VERSION 5.8 ;
BUSBITCHARS "[]" ;
DIVIDERCHAR "/" ;
UNITS
    DATABASE MICRONS 1000 ;
END UNITS

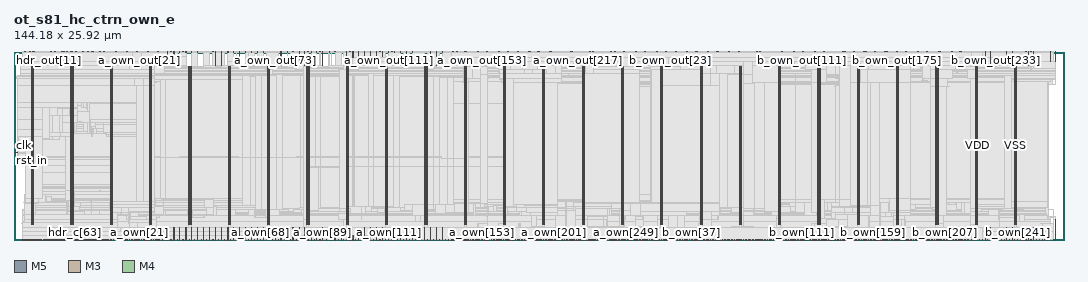
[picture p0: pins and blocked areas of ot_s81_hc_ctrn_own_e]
MACRO ot_s81_hc_ctrn_own_e
  FOREIGN ot_s81_hc_ctrn_own_e 0 0 ;
  CLASS BLOCK ;
  SIZE 144.18 BY 25.92 ;
  PIN a_own[0]
    DIRECTION INPUT ;
    USE SIGNAL ;
    PORT
      LAYER M5 ;
        RECT  13.008 0 13.032 0.084 ;
    END
  END a_own[0]
  PIN a_own[100]
    DIRECTION INPUT ;
    USE SIGNAL ;
    PORT
      LAYER M5 ;
        RECT  46.896 0 46.92 0.084 ;
    END
  END a_own[100]
  PIN a_own[101]
    DIRECTION INPUT ;
    USE SIGNAL ;
    PORT
      LAYER M3 ;
        RECT  47.304 0 47.322 0.038 ;
    END
    PORT
      LAYER M3 ;
        RECT  47.304 0.012 47.322 0.571 ;
    END
  END a_own[101]
  PIN a_own[102]
    DIRECTION INPUT ;
    USE SIGNAL ;
    PORT
      LAYER M5 ;
        RECT  47.76 0 47.784 0.084 ;
    END
  END a_own[102]
  PIN a_own[103]
    DIRECTION INPUT ;
    USE SIGNAL ;
    PORT
      LAYER M3 ;
        RECT  48.168 0 48.186 0.038 ;
    END
    PORT
      LAYER M3 ;
        RECT  48.168 0.012 48.186 1.723 ;
    END
  END a_own[103]
  PIN a_own[104]
    DIRECTION INPUT ;
    USE SIGNAL ;
    PORT
      LAYER M5 ;
        RECT  48.528 0 48.552 0.084 ;
    END
  END a_own[104]
  PIN a_own[105]
    DIRECTION INPUT ;
    USE SIGNAL ;
    PORT
      LAYER M3 ;
        RECT  48.96 0 48.978 0.038 ;
    END
    PORT
      LAYER M3 ;
        RECT  48.96 0.012 48.978 1.723 ;
    END
  END a_own[105]
  PIN a_own[106]
    DIRECTION INPUT ;
    USE SIGNAL ;
    PORT
      LAYER M5 ;
        RECT  49.392 0 49.416 0.084 ;
    END
  END a_own[106]
  PIN a_own[107]
    DIRECTION INPUT ;
    USE SIGNAL ;
    PORT
      LAYER M3 ;
        RECT  49.824 0 49.842 0.038 ;
    END
    PORT
      LAYER M3 ;
        RECT  49.824 0.012 49.842 1.723 ;
    END
  END a_own[107]
  PIN a_own[108]
    DIRECTION INPUT ;
    USE SIGNAL ;
    PORT
      LAYER M5 ;
        RECT  50.256 0 50.28 0.084 ;
    END
  END a_own[108]
  PIN a_own[109]
    DIRECTION INPUT ;
    USE SIGNAL ;
    PORT
      LAYER M3 ;
        RECT  50.58 0 50.598 0.038 ;
    END
    PORT
      LAYER M3 ;
        RECT  50.58 0.012 50.598 1.723 ;
    END
  END a_own[109]
  PIN a_own[10]
    DIRECTION INPUT ;
    USE SIGNAL ;
    PORT
      LAYER M5 ;
        RECT  15.024 0 15.048 0.084 ;
    END
  END a_own[10]
  PIN a_own[110]
    DIRECTION INPUT ;
    USE SIGNAL ;
    PORT
      LAYER M5 ;
        RECT  51.024 0 51.048 0.084 ;
    END
  END a_own[110]
  PIN a_own[111]
    DIRECTION INPUT ;
    USE SIGNAL ;
    PORT
      LAYER M3 ;
        RECT  51.444 0 51.462 0.038 ;
    END
    PORT
      LAYER M3 ;
        RECT  51.444 0.012 51.462 0.091 ;
    END
  END a_own[111]
  PIN a_own[112]
    DIRECTION INPUT ;
    USE SIGNAL ;
    PORT
      LAYER M5 ;
        RECT  51.888 0 51.912 0.084 ;
    END
  END a_own[112]
  PIN a_own[113]
    DIRECTION INPUT ;
    USE SIGNAL ;
    PORT
      LAYER M3 ;
        RECT  52.2 0 52.218 0.038 ;
    END
    PORT
      LAYER M3 ;
        RECT  52.2 0.012 52.218 0.091 ;
    END
  END a_own[113]
  PIN a_own[114]
    DIRECTION INPUT ;
    USE SIGNAL ;
    PORT
      LAYER M5 ;
        RECT  52.656 0 52.68 0.084 ;
    END
  END a_own[114]
  PIN a_own[115]
    DIRECTION INPUT ;
    USE SIGNAL ;
    PORT
      LAYER M3 ;
        RECT  53.064 0 53.082 0.038 ;
    END
    PORT
      LAYER M3 ;
        RECT  53.064 0.012 53.082 1.723 ;
    END
  END a_own[115]
  PIN a_own[116]
    DIRECTION INPUT ;
    USE SIGNAL ;
    PORT
      LAYER M5 ;
        RECT  53.52 0 53.544 0.084 ;
    END
  END a_own[116]
  PIN a_own[117]
    DIRECTION INPUT ;
    USE SIGNAL ;
    PORT
      LAYER M3 ;
        RECT  53.856 0 53.874 0.038 ;
    END
    PORT
      LAYER M3 ;
        RECT  53.856 0.012 53.874 1.723 ;
    END
  END a_own[117]
  PIN a_own[118]
    DIRECTION INPUT ;
    USE SIGNAL ;
    PORT
      LAYER M5 ;
        RECT  54.288 0 54.312 0.084 ;
    END
  END a_own[118]
  PIN a_own[119]
    DIRECTION INPUT ;
    USE SIGNAL ;
    PORT
      LAYER M3 ;
        RECT  54.72 0 54.738 0.038 ;
    END
    PORT
      LAYER M3 ;
        RECT  54.72 0.012 54.738 1.723 ;
    END
  END a_own[119]
  PIN a_own[11]
    DIRECTION INPUT ;
    USE SIGNAL ;
    PORT
      LAYER M3 ;
        RECT  15.264 0 15.282 0.038 ;
    END
  END a_own[11]
  PIN a_own[120]
    DIRECTION INPUT ;
    USE SIGNAL ;
    PORT
      LAYER M5 ;
        RECT  55.152 0 55.176 0.084 ;
    END
  END a_own[120]
  PIN a_own[121]
    DIRECTION INPUT ;
    USE SIGNAL ;
    PORT
      LAYER M3 ;
        RECT  55.476 0 55.494 0.038 ;
    END
    PORT
      LAYER M3 ;
        RECT  55.476 0.012 55.494 1.723 ;
    END
  END a_own[121]
  PIN a_own[122]
    DIRECTION INPUT ;
    USE SIGNAL ;
    PORT
      LAYER M5 ;
        RECT  55.92 0 55.944 0.084 ;
    END
  END a_own[122]
  PIN a_own[123]
    DIRECTION INPUT ;
    USE SIGNAL ;
    PORT
      LAYER M3 ;
        RECT  56.34 0 56.358 0.038 ;
    END
    PORT
      LAYER M3 ;
        RECT  56.34 0.012 56.358 1.723 ;
    END
  END a_own[123]
  PIN a_own[124]
    DIRECTION INPUT ;
    USE SIGNAL ;
    PORT
      LAYER M5 ;
        RECT  56.784 0 56.808 0.084 ;
    END
  END a_own[124]
  PIN a_own[125]
    DIRECTION INPUT ;
    USE SIGNAL ;
    PORT
      LAYER M3 ;
        RECT  57.204 0 57.222 0.038 ;
    END
    PORT
      LAYER M3 ;
        RECT  57.204 0.012 57.222 1.723 ;
    END
  END a_own[125]
  PIN a_own[126]
    DIRECTION INPUT ;
    USE SIGNAL ;
    PORT
      LAYER M5 ;
        RECT  57.552 0 57.576 0.084 ;
    END
  END a_own[126]
  PIN a_own[127]
    DIRECTION INPUT ;
    USE SIGNAL ;
    PORT
      LAYER M3 ;
        RECT  57.96 0 57.978 0.038 ;
    END
    PORT
      LAYER M3 ;
        RECT  57.96 0.012 57.978 1.723 ;
    END
  END a_own[127]
  PIN a_own[128]
    DIRECTION INPUT ;
    USE SIGNAL ;
    PORT
      LAYER M5 ;
        RECT  58.416 0 58.44 0.084 ;
    END
  END a_own[128]
  PIN a_own[129]
    DIRECTION INPUT ;
    USE SIGNAL ;
    PORT
      LAYER M3 ;
        RECT  58.824 0 58.842 0.038 ;
    END
    PORT
      LAYER M3 ;
        RECT  58.824 0.012 58.842 1.723 ;
    END
  END a_own[129]
  PIN a_own[12]
    DIRECTION INPUT ;
    USE SIGNAL ;
    PORT
      LAYER M5 ;
        RECT  15.504 0 15.528 0.084 ;
    END
  END a_own[12]
  PIN a_own[130]
    DIRECTION INPUT ;
    USE SIGNAL ;
    PORT
      LAYER M5 ;
        RECT  59.184 0 59.208 0.084 ;
    END
  END a_own[130]
  PIN a_own[131]
    DIRECTION INPUT ;
    USE SIGNAL ;
    PORT
      LAYER M3 ;
        RECT  59.616 0 59.634 0.038 ;
    END
  END a_own[131]
  PIN a_own[132]
    DIRECTION INPUT ;
    USE SIGNAL ;
    PORT
      LAYER M5 ;
        RECT  60.048 0 60.072 0.084 ;
    END
  END a_own[132]
  PIN a_own[133]
    DIRECTION INPUT ;
    USE SIGNAL ;
    PORT
      LAYER M3 ;
        RECT  60.264 0 60.282 0.038 ;
    END
  END a_own[133]
  PIN a_own[134]
    DIRECTION INPUT ;
    USE SIGNAL ;
    PORT
      LAYER M5 ;
        RECT  60.432 0 60.456 0.084 ;
    END
  END a_own[134]
  PIN a_own[135]
    DIRECTION INPUT ;
    USE SIGNAL ;
    PORT
      LAYER M3 ;
        RECT  60.66 0 60.678 0.038 ;
    END
  END a_own[135]
  PIN a_own[136]
    DIRECTION INPUT ;
    USE SIGNAL ;
    PORT
      LAYER M5 ;
        RECT  60.816 0 60.84 0.084 ;
    END
  END a_own[136]
  PIN a_own[137]
    DIRECTION INPUT ;
    USE SIGNAL ;
    PORT
      LAYER M3 ;
        RECT  61.056 0 61.074 0.038 ;
    END
  END a_own[137]
  PIN a_own[138]
    DIRECTION INPUT ;
    USE SIGNAL ;
    PORT
      LAYER M5 ;
        RECT  61.296 0 61.32 0.084 ;
    END
  END a_own[138]
  PIN a_own[139]
    DIRECTION INPUT ;
    USE SIGNAL ;
    PORT
      LAYER M3 ;
        RECT  61.416 0 61.434 0.038 ;
    END
  END a_own[139]
  PIN a_own[13]
    DIRECTION INPUT ;
    USE SIGNAL ;
    PORT
      LAYER M3 ;
        RECT  15.624 0 15.642 0.038 ;
    END
  END a_own[13]
  PIN a_own[140]
    DIRECTION INPUT ;
    USE SIGNAL ;
    PORT
      LAYER M5 ;
        RECT  61.68 0 61.704 0.084 ;
    END
  END a_own[140]
  PIN a_own[141]
    DIRECTION INPUT ;
    USE SIGNAL ;
    PORT
      LAYER M3 ;
        RECT  61.92 0 61.938 0.038 ;
    END
  END a_own[141]
  PIN a_own[142]
    DIRECTION INPUT ;
    USE SIGNAL ;
    PORT
      LAYER M5 ;
        RECT  62.064 0 62.088 0.084 ;
    END
  END a_own[142]
  PIN a_own[143]
    DIRECTION INPUT ;
    USE SIGNAL ;
    PORT
      LAYER M3 ;
        RECT  62.28 0 62.298 0.038 ;
    END
  END a_own[143]
  PIN a_own[144]
    DIRECTION INPUT ;
    USE SIGNAL ;
    PORT
      LAYER M5 ;
        RECT  62.448 0 62.472 0.084 ;
    END
  END a_own[144]
  PIN a_own[145]
    DIRECTION INPUT ;
    USE SIGNAL ;
    PORT
      LAYER M3 ;
        RECT  62.676 0 62.694 0.038 ;
    END
  END a_own[145]
  PIN a_own[146]
    DIRECTION INPUT ;
    USE SIGNAL ;
    PORT
      LAYER M5 ;
        RECT  62.928 0 62.952 0.084 ;
    END
  END a_own[146]
  PIN a_own[147]
    DIRECTION INPUT ;
    USE SIGNAL ;
    PORT
      LAYER M3 ;
        RECT  63.072 0 63.09 0.038 ;
    END
  END a_own[147]
  PIN a_own[148]
    DIRECTION INPUT ;
    USE SIGNAL ;
    PORT
      LAYER M5 ;
        RECT  63.312 0 63.336 0.084 ;
    END
  END a_own[148]
  PIN a_own[149]
    DIRECTION INPUT ;
    USE SIGNAL ;
    PORT
      LAYER M3 ;
        RECT  63.54 0 63.558 0.038 ;
    END
  END a_own[149]
  PIN a_own[14]
    DIRECTION INPUT ;
    USE SIGNAL ;
    PORT
      LAYER M5 ;
        RECT  15.888 0 15.912 0.084 ;
    END
  END a_own[14]
  PIN a_own[150]
    DIRECTION INPUT ;
    USE SIGNAL ;
    PORT
      LAYER M5 ;
        RECT  63.696 0 63.72 0.084 ;
    END
  END a_own[150]
  PIN a_own[151]
    DIRECTION INPUT ;
    USE SIGNAL ;
    PORT
      LAYER M3 ;
        RECT  63.936 0 63.954 0.038 ;
    END
  END a_own[151]
  PIN a_own[152]
    DIRECTION INPUT ;
    USE SIGNAL ;
    PORT
      LAYER M5 ;
        RECT  64.176 0 64.2 0.084 ;
    END
  END a_own[152]
  PIN a_own[153]
    DIRECTION INPUT ;
    USE SIGNAL ;
    PORT
      LAYER M3 ;
        RECT  64.296 0 64.314 0.038 ;
    END
  END a_own[153]
  PIN a_own[154]
    DIRECTION INPUT ;
    USE SIGNAL ;
    PORT
      LAYER M5 ;
        RECT  64.56 0 64.584 0.084 ;
    END
  END a_own[154]
  PIN a_own[155]
    DIRECTION INPUT ;
    USE SIGNAL ;
    PORT
      LAYER M3 ;
        RECT  64.692 0 64.71 0.038 ;
    END
  END a_own[155]
  PIN a_own[156]
    DIRECTION INPUT ;
    USE SIGNAL ;
    PORT
      LAYER M5 ;
        RECT  64.944 0 64.968 0.084 ;
    END
  END a_own[156]
  PIN a_own[157]
    DIRECTION INPUT ;
    USE SIGNAL ;
    PORT
      LAYER M3 ;
        RECT  65.16 0 65.178 0.038 ;
    END
  END a_own[157]
  PIN a_own[158]
    DIRECTION INPUT ;
    USE SIGNAL ;
    PORT
      LAYER M5 ;
        RECT  65.328 0 65.352 0.084 ;
    END
  END a_own[158]
  PIN a_own[159]
    DIRECTION INPUT ;
    USE SIGNAL ;
    PORT
      LAYER M3 ;
        RECT  65.556 0 65.574 0.038 ;
    END
  END a_own[159]
  PIN a_own[15]
    DIRECTION INPUT ;
    USE SIGNAL ;
    PORT
      LAYER M3 ;
        RECT  16.128 0 16.146 0.038 ;
    END
  END a_own[15]
  PIN a_own[160]
    DIRECTION INPUT ;
    USE SIGNAL ;
    PORT
      LAYER M5 ;
        RECT  65.808 0 65.832 0.084 ;
    END
  END a_own[160]
  PIN a_own[161]
    DIRECTION INPUT ;
    USE SIGNAL ;
    PORT
      LAYER M3 ;
        RECT  65.952 0 65.97 0.038 ;
    END
  END a_own[161]
  PIN a_own[162]
    DIRECTION INPUT ;
    USE SIGNAL ;
    PORT
      LAYER M5 ;
        RECT  66.192 0 66.216 0.084 ;
    END
  END a_own[162]
  PIN a_own[163]
    DIRECTION INPUT ;
    USE SIGNAL ;
    PORT
      LAYER M3 ;
        RECT  66.42 0 66.438 0.038 ;
    END
  END a_own[163]
  PIN a_own[164]
    DIRECTION INPUT ;
    USE SIGNAL ;
    PORT
      LAYER M5 ;
        RECT  66.576 0 66.6 0.084 ;
    END
  END a_own[164]
  PIN a_own[165]
    DIRECTION INPUT ;
    USE SIGNAL ;
    PORT
      LAYER M3 ;
        RECT  66.816 0 66.834 0.038 ;
    END
  END a_own[165]
  PIN a_own[166]
    DIRECTION INPUT ;
    USE SIGNAL ;
    PORT
      LAYER M5 ;
        RECT  66.96 0 66.984 0.084 ;
    END
  END a_own[166]
  PIN a_own[167]
    DIRECTION INPUT ;
    USE SIGNAL ;
    PORT
      LAYER M3 ;
        RECT  67.176 0 67.194 0.038 ;
    END
  END a_own[167]
  PIN a_own[168]
    DIRECTION INPUT ;
    USE SIGNAL ;
    PORT
      LAYER M5 ;
        RECT  67.44 0 67.464 0.084 ;
    END
  END a_own[168]
  PIN a_own[169]
    DIRECTION INPUT ;
    USE SIGNAL ;
    PORT
      LAYER M3 ;
        RECT  67.572 0 67.59 0.038 ;
    END
  END a_own[169]
  PIN a_own[16]
    DIRECTION INPUT ;
    USE SIGNAL ;
    PORT
      LAYER M5 ;
        RECT  16.272 0 16.296 0.084 ;
    END
  END a_own[16]
  PIN a_own[170]
    DIRECTION INPUT ;
    USE SIGNAL ;
    PORT
      LAYER M5 ;
        RECT  67.824 0 67.848 0.084 ;
    END
  END a_own[170]
  PIN a_own[171]
    DIRECTION INPUT ;
    USE SIGNAL ;
    PORT
      LAYER M3 ;
        RECT  68.04 0 68.058 0.038 ;
    END
  END a_own[171]
  PIN a_own[172]
    DIRECTION INPUT ;
    USE SIGNAL ;
    PORT
      LAYER M5 ;
        RECT  68.208 0 68.232 0.084 ;
    END
  END a_own[172]
  PIN a_own[173]
    DIRECTION INPUT ;
    USE SIGNAL ;
    PORT
      LAYER M3 ;
        RECT  68.436 0 68.454 0.038 ;
    END
  END a_own[173]
  PIN a_own[174]
    DIRECTION INPUT ;
    USE SIGNAL ;
    PORT
      LAYER M5 ;
        RECT  68.592 0 68.616 0.084 ;
    END
  END a_own[174]
  PIN a_own[175]
    DIRECTION INPUT ;
    USE SIGNAL ;
    PORT
      LAYER M3 ;
        RECT  68.832 0 68.85 0.038 ;
    END
  END a_own[175]
  PIN a_own[176]
    DIRECTION INPUT ;
    USE SIGNAL ;
    PORT
      LAYER M5 ;
        RECT  69.072 0 69.096 0.084 ;
    END
  END a_own[176]
  PIN a_own[177]
    DIRECTION INPUT ;
    USE SIGNAL ;
    PORT
      LAYER M3 ;
        RECT  69.192 0 69.21 0.038 ;
    END
  END a_own[177]
  PIN a_own[178]
    DIRECTION INPUT ;
    USE SIGNAL ;
    PORT
      LAYER M5 ;
        RECT  69.456 0 69.48 0.084 ;
    END
  END a_own[178]
  PIN a_own[179]
    DIRECTION INPUT ;
    USE SIGNAL ;
    PORT
      LAYER M3 ;
        RECT  69.696 0 69.714 0.038 ;
    END
  END a_own[179]
  PIN a_own[17]
    DIRECTION INPUT ;
    USE SIGNAL ;
    PORT
      LAYER M3 ;
        RECT  16.488 0 16.506 0.038 ;
    END
  END a_own[17]
  PIN a_own[180]
    DIRECTION INPUT ;
    USE SIGNAL ;
    PORT
      LAYER M5 ;
        RECT  69.84 0 69.864 0.084 ;
    END
  END a_own[180]
  PIN a_own[181]
    DIRECTION INPUT ;
    USE SIGNAL ;
    PORT
      LAYER M3 ;
        RECT  70.056 0 70.074 0.038 ;
    END
  END a_own[181]
  PIN a_own[182]
    DIRECTION INPUT ;
    USE SIGNAL ;
    PORT
      LAYER M5 ;
        RECT  70.32 0 70.344 0.084 ;
    END
  END a_own[182]
  PIN a_own[183]
    DIRECTION INPUT ;
    USE SIGNAL ;
    PORT
      LAYER M3 ;
        RECT  70.452 0 70.47 0.038 ;
    END
  END a_own[183]
  PIN a_own[184]
    DIRECTION INPUT ;
    USE SIGNAL ;
    PORT
      LAYER M5 ;
        RECT  70.704 0 70.728 0.084 ;
    END
  END a_own[184]
  PIN a_own[185]
    DIRECTION INPUT ;
    USE SIGNAL ;
    PORT
      LAYER M3 ;
        RECT  70.848 0 70.866 0.038 ;
    END
  END a_own[185]
  PIN a_own[186]
    DIRECTION INPUT ;
    USE SIGNAL ;
    PORT
      LAYER M5 ;
        RECT  71.088 0 71.112 0.084 ;
    END
  END a_own[186]
  PIN a_own[187]
    DIRECTION INPUT ;
    USE SIGNAL ;
    PORT
      LAYER M3 ;
        RECT  71.316 0 71.334 0.038 ;
    END
  END a_own[187]
  PIN a_own[188]
    DIRECTION INPUT ;
    USE SIGNAL ;
    PORT
      LAYER M5 ;
        RECT  71.472 0 71.496 0.084 ;
    END
  END a_own[188]
  PIN a_own[189]
    DIRECTION INPUT ;
    USE SIGNAL ;
    PORT
      LAYER M3 ;
        RECT  71.712 0 71.73 0.038 ;
    END
  END a_own[189]
  PIN a_own[18]
    DIRECTION INPUT ;
    USE SIGNAL ;
    PORT
      LAYER M5 ;
        RECT  16.656 0 16.68 0.084 ;
    END
  END a_own[18]
  PIN a_own[190]
    DIRECTION INPUT ;
    USE SIGNAL ;
    PORT
      LAYER M5 ;
        RECT  71.952 0 71.976 0.084 ;
    END
  END a_own[190]
  PIN a_own[191]
    DIRECTION INPUT ;
    USE SIGNAL ;
    PORT
      LAYER M3 ;
        RECT  72.072 0 72.09 0.038 ;
    END
  END a_own[191]
  PIN a_own[192]
    DIRECTION INPUT ;
    USE SIGNAL ;
    PORT
      LAYER M5 ;
        RECT  72.336 0 72.36 0.084 ;
    END
  END a_own[192]
  PIN a_own[193]
    DIRECTION INPUT ;
    USE SIGNAL ;
    PORT
      LAYER M3 ;
        RECT  72.468 0 72.486 0.038 ;
    END
  END a_own[193]
  PIN a_own[194]
    DIRECTION INPUT ;
    USE SIGNAL ;
    PORT
      LAYER M5 ;
        RECT  72.72 0 72.744 0.084 ;
    END
  END a_own[194]
  PIN a_own[195]
    DIRECTION INPUT ;
    USE SIGNAL ;
    PORT
      LAYER M3 ;
        RECT  72.936 0 72.954 0.038 ;
    END
  END a_own[195]
  PIN a_own[196]
    DIRECTION INPUT ;
    USE SIGNAL ;
    PORT
      LAYER M5 ;
        RECT  73.104 0 73.128 0.084 ;
    END
  END a_own[196]
  PIN a_own[197]
    DIRECTION INPUT ;
    USE SIGNAL ;
    PORT
      LAYER M3 ;
        RECT  73.332 0 73.35 0.038 ;
    END
  END a_own[197]
  PIN a_own[198]
    DIRECTION INPUT ;
    USE SIGNAL ;
    PORT
      LAYER M5 ;
        RECT  73.584 0 73.608 0.084 ;
    END
  END a_own[198]
  PIN a_own[199]
    DIRECTION INPUT ;
    USE SIGNAL ;
    PORT
      LAYER M3 ;
        RECT  73.728 0 73.746 0.038 ;
    END
  END a_own[199]
  PIN a_own[19]
    DIRECTION INPUT ;
    USE SIGNAL ;
    PORT
      LAYER M3 ;
        RECT  16.884 0 16.902 0.038 ;
    END
  END a_own[19]
  PIN a_own[1]
    DIRECTION INPUT ;
    USE SIGNAL ;
    PORT
      LAYER M3 ;
        RECT  13.248 0 13.266 0.038 ;
    END
  END a_own[1]
  PIN a_own[200]
    DIRECTION INPUT ;
    USE SIGNAL ;
    PORT
      LAYER M5 ;
        RECT  73.968 0 73.992 0.084 ;
    END
  END a_own[200]
  PIN a_own[201]
    DIRECTION INPUT ;
    USE SIGNAL ;
    PORT
      LAYER M3 ;
        RECT  74.196 0 74.214 0.038 ;
    END
  END a_own[201]
  PIN a_own[202]
    DIRECTION INPUT ;
    USE SIGNAL ;
    PORT
      LAYER M5 ;
        RECT  74.352 0 74.376 0.084 ;
    END
  END a_own[202]
  PIN a_own[203]
    DIRECTION INPUT ;
    USE SIGNAL ;
    PORT
      LAYER M3 ;
        RECT  74.592 0 74.61 0.038 ;
    END
  END a_own[203]
  PIN a_own[204]
    DIRECTION INPUT ;
    USE SIGNAL ;
    PORT
      LAYER M5 ;
        RECT  74.736 0 74.76 0.084 ;
    END
  END a_own[204]
  PIN a_own[205]
    DIRECTION INPUT ;
    USE SIGNAL ;
    PORT
      LAYER M3 ;
        RECT  74.952 0 74.97 0.038 ;
    END
  END a_own[205]
  PIN a_own[206]
    DIRECTION INPUT ;
    USE SIGNAL ;
    PORT
      LAYER M5 ;
        RECT  75.216 0 75.24 0.084 ;
    END
  END a_own[206]
  PIN a_own[207]
    DIRECTION INPUT ;
    USE SIGNAL ;
    PORT
      LAYER M3 ;
        RECT  75.348 0 75.366 0.038 ;
    END
  END a_own[207]
  PIN a_own[208]
    DIRECTION INPUT ;
    USE SIGNAL ;
    PORT
      LAYER M5 ;
        RECT  75.6 0 75.624 0.084 ;
    END
  END a_own[208]
  PIN a_own[209]
    DIRECTION INPUT ;
    USE SIGNAL ;
    PORT
      LAYER M3 ;
        RECT  75.816 0 75.834 0.038 ;
    END
  END a_own[209]
  PIN a_own[20]
    DIRECTION INPUT ;
    USE SIGNAL ;
    PORT
      LAYER M5 ;
        RECT  17.136 0 17.16 0.084 ;
    END
  END a_own[20]
  PIN a_own[210]
    DIRECTION INPUT ;
    USE SIGNAL ;
    PORT
      LAYER M5 ;
        RECT  75.984 0 76.008 0.084 ;
    END
  END a_own[210]
  PIN a_own[211]
    DIRECTION INPUT ;
    USE SIGNAL ;
    PORT
      LAYER M3 ;
        RECT  76.212 0 76.23 0.038 ;
    END
  END a_own[211]
  PIN a_own[212]
    DIRECTION INPUT ;
    USE SIGNAL ;
    PORT
      LAYER M5 ;
        RECT  76.464 0 76.488 0.084 ;
    END
  END a_own[212]
  PIN a_own[213]
    DIRECTION INPUT ;
    USE SIGNAL ;
    PORT
      LAYER M3 ;
        RECT  76.608 0 76.626 0.038 ;
    END
  END a_own[213]
  PIN a_own[214]
    DIRECTION INPUT ;
    USE SIGNAL ;
    PORT
      LAYER M5 ;
        RECT  76.848 0 76.872 0.084 ;
    END
  END a_own[214]
  PIN a_own[215]
    DIRECTION INPUT ;
    USE SIGNAL ;
    PORT
      LAYER M3 ;
        RECT  76.968 0 76.986 0.038 ;
    END
  END a_own[215]
  PIN a_own[216]
    DIRECTION INPUT ;
    USE SIGNAL ;
    PORT
      LAYER M5 ;
        RECT  77.232 0 77.256 0.084 ;
    END
  END a_own[216]
  PIN a_own[217]
    DIRECTION INPUT ;
    USE SIGNAL ;
    PORT
      LAYER M3 ;
        RECT  77.472 0 77.49 0.038 ;
    END
  END a_own[217]
  PIN a_own[218]
    DIRECTION INPUT ;
    USE SIGNAL ;
    PORT
      LAYER M5 ;
        RECT  77.616 0 77.64 0.084 ;
    END
  END a_own[218]
  PIN a_own[219]
    DIRECTION INPUT ;
    USE SIGNAL ;
    PORT
      LAYER M3 ;
        RECT  77.832 0 77.85 0.038 ;
    END
  END a_own[219]
  PIN a_own[21]
    DIRECTION INPUT ;
    USE SIGNAL ;
    PORT
      LAYER M3 ;
        RECT  17.28 0 17.298 0.038 ;
    END
  END a_own[21]
  PIN a_own[220]
    DIRECTION INPUT ;
    USE SIGNAL ;
    PORT
      LAYER M5 ;
        RECT  78.096 0 78.12 0.084 ;
    END
  END a_own[220]
  PIN a_own[221]
    DIRECTION INPUT ;
    USE SIGNAL ;
    PORT
      LAYER M3 ;
        RECT  78.228 0 78.246 0.038 ;
    END
  END a_own[221]
  PIN a_own[222]
    DIRECTION INPUT ;
    USE SIGNAL ;
    PORT
      LAYER M5 ;
        RECT  78.48 0 78.504 0.084 ;
    END
  END a_own[222]
  PIN a_own[223]
    DIRECTION INPUT ;
    USE SIGNAL ;
    PORT
      LAYER M3 ;
        RECT  78.624 0 78.642 0.038 ;
    END
  END a_own[223]
  PIN a_own[224]
    DIRECTION INPUT ;
    USE SIGNAL ;
    PORT
      LAYER M5 ;
        RECT  78.864 0 78.888 0.084 ;
    END
  END a_own[224]
  PIN a_own[225]
    DIRECTION INPUT ;
    USE SIGNAL ;
    PORT
      LAYER M3 ;
        RECT  79.092 0 79.11 0.038 ;
    END
  END a_own[225]
  PIN a_own[226]
    DIRECTION INPUT ;
    USE SIGNAL ;
    PORT
      LAYER M5 ;
        RECT  79.248 0 79.272 0.084 ;
    END
  END a_own[226]
  PIN a_own[227]
    DIRECTION INPUT ;
    USE SIGNAL ;
    PORT
      LAYER M3 ;
        RECT  79.488 0 79.506 0.038 ;
    END
  END a_own[227]
  PIN a_own[228]
    DIRECTION INPUT ;
    USE SIGNAL ;
    PORT
      LAYER M5 ;
        RECT  79.728 0 79.752 0.084 ;
    END
  END a_own[228]
  PIN a_own[229]
    DIRECTION INPUT ;
    USE SIGNAL ;
    PORT
      LAYER M3 ;
        RECT  79.848 0 79.866 0.038 ;
    END
  END a_own[229]
  PIN a_own[22]
    DIRECTION INPUT ;
    USE SIGNAL ;
    PORT
      LAYER M5 ;
        RECT  17.52 0 17.544 0.084 ;
    END
  END a_own[22]
  PIN a_own[230]
    DIRECTION INPUT ;
    USE SIGNAL ;
    PORT
      LAYER M5 ;
        RECT  80.112 0 80.136 0.084 ;
    END
  END a_own[230]
  PIN a_own[231]
    DIRECTION INPUT ;
    USE SIGNAL ;
    PORT
      LAYER M3 ;
        RECT  80.352 0 80.37 0.038 ;
    END
  END a_own[231]
  PIN a_own[232]
    DIRECTION INPUT ;
    USE SIGNAL ;
    PORT
      LAYER M5 ;
        RECT  80.496 0 80.52 0.084 ;
    END
  END a_own[232]
  PIN a_own[233]
    DIRECTION INPUT ;
    USE SIGNAL ;
    PORT
      LAYER M3 ;
        RECT  80.712 0 80.73 0.038 ;
    END
  END a_own[233]
  PIN a_own[234]
    DIRECTION INPUT ;
    USE SIGNAL ;
    PORT
      LAYER M5 ;
        RECT  80.88 0 80.904 0.084 ;
    END
  END a_own[234]
  PIN a_own[235]
    DIRECTION INPUT ;
    USE SIGNAL ;
    PORT
      LAYER M3 ;
        RECT  81.108 0 81.126 0.038 ;
    END
  END a_own[235]
  PIN a_own[236]
    DIRECTION INPUT ;
    USE SIGNAL ;
    PORT
      LAYER M5 ;
        RECT  81.36 0 81.384 0.084 ;
    END
  END a_own[236]
  PIN a_own[237]
    DIRECTION INPUT ;
    USE SIGNAL ;
    PORT
      LAYER M3 ;
        RECT  81.504 0 81.522 0.038 ;
    END
  END a_own[237]
  PIN a_own[238]
    DIRECTION INPUT ;
    USE SIGNAL ;
    PORT
      LAYER M5 ;
        RECT  81.744 0 81.768 0.084 ;
    END
  END a_own[238]
  PIN a_own[239]
    DIRECTION INPUT ;
    USE SIGNAL ;
    PORT
      LAYER M3 ;
        RECT  81.972 0 81.99 0.038 ;
    END
  END a_own[239]
  PIN a_own[23]
    DIRECTION INPUT ;
    USE SIGNAL ;
    PORT
      LAYER M3 ;
        RECT  17.748 0 17.766 0.038 ;
    END
  END a_own[23]
  PIN a_own[240]
    DIRECTION INPUT ;
    USE SIGNAL ;
    PORT
      LAYER M5 ;
        RECT  82.128 0 82.152 0.084 ;
    END
  END a_own[240]
  PIN a_own[241]
    DIRECTION INPUT ;
    USE SIGNAL ;
    PORT
      LAYER M3 ;
        RECT  82.368 0 82.386 0.038 ;
    END
  END a_own[241]
  PIN a_own[242]
    DIRECTION INPUT ;
    USE SIGNAL ;
    PORT
      LAYER M5 ;
        RECT  82.512 0 82.536 0.084 ;
    END
  END a_own[242]
  PIN a_own[243]
    DIRECTION INPUT ;
    USE SIGNAL ;
    PORT
      LAYER M3 ;
        RECT  82.728 0 82.746 0.038 ;
    END
  END a_own[243]
  PIN a_own[244]
    DIRECTION INPUT ;
    USE SIGNAL ;
    PORT
      LAYER M5 ;
        RECT  82.992 0 83.016 0.084 ;
    END
  END a_own[244]
  PIN a_own[245]
    DIRECTION INPUT ;
    USE SIGNAL ;
    PORT
      LAYER M3 ;
        RECT  83.124 0 83.142 0.038 ;
    END
  END a_own[245]
  PIN a_own[246]
    DIRECTION INPUT ;
    USE SIGNAL ;
    PORT
      LAYER M5 ;
        RECT  83.376 0 83.4 0.084 ;
    END
  END a_own[246]
  PIN a_own[247]
    DIRECTION INPUT ;
    USE SIGNAL ;
    PORT
      LAYER M3 ;
        RECT  83.592 0 83.61 0.038 ;
    END
  END a_own[247]
  PIN a_own[248]
    DIRECTION INPUT ;
    USE SIGNAL ;
    PORT
      LAYER M5 ;
        RECT  83.76 0 83.784 0.084 ;
    END
  END a_own[248]
  PIN a_own[249]
    DIRECTION INPUT ;
    USE SIGNAL ;
    PORT
      LAYER M3 ;
        RECT  83.988 0 84.006 0.038 ;
    END
  END a_own[249]
  PIN a_own[24]
    DIRECTION INPUT ;
    USE SIGNAL ;
    PORT
      LAYER M5 ;
        RECT  17.904 0 17.928 0.084 ;
    END
  END a_own[24]
  PIN a_own[250]
    DIRECTION INPUT ;
    USE SIGNAL ;
    PORT
      LAYER M5 ;
        RECT  84.24 0 84.264 0.084 ;
    END
  END a_own[250]
  PIN a_own[251]
    DIRECTION INPUT ;
    USE SIGNAL ;
    PORT
      LAYER M3 ;
        RECT  84.384 0 84.402 0.038 ;
    END
  END a_own[251]
  PIN a_own[252]
    DIRECTION INPUT ;
    USE SIGNAL ;
    PORT
      LAYER M5 ;
        RECT  84.624 0 84.648 0.084 ;
    END
  END a_own[252]
  PIN a_own[253]
    DIRECTION INPUT ;
    USE SIGNAL ;
    PORT
      LAYER M3 ;
        RECT  84.744 0 84.762 0.038 ;
    END
  END a_own[253]
  PIN a_own[254]
    DIRECTION INPUT ;
    USE SIGNAL ;
    PORT
      LAYER M5 ;
        RECT  85.008 0 85.032 0.084 ;
    END
  END a_own[254]
  PIN a_own[255]
    DIRECTION INPUT ;
    USE SIGNAL ;
    PORT
      LAYER M3 ;
        RECT  85.248 0 85.266 0.038 ;
    END
  END a_own[255]
  PIN a_own[25]
    DIRECTION INPUT ;
    USE SIGNAL ;
    PORT
      LAYER M3 ;
        RECT  18.144 0 18.162 0.038 ;
    END
  END a_own[25]
  PIN a_own[26]
    DIRECTION INPUT ;
    USE SIGNAL ;
    PORT
      LAYER M5 ;
        RECT  18.384 0 18.408 0.084 ;
    END
  END a_own[26]
  PIN a_own[27]
    DIRECTION INPUT ;
    USE SIGNAL ;
    PORT
      LAYER M3 ;
        RECT  18.504 0 18.522 0.038 ;
    END
  END a_own[27]
  PIN a_own[28]
    DIRECTION INPUT ;
    USE SIGNAL ;
    PORT
      LAYER M5 ;
        RECT  18.768 0 18.792 0.084 ;
    END
  END a_own[28]
  PIN a_own[29]
    DIRECTION INPUT ;
    USE SIGNAL ;
    PORT
      LAYER M3 ;
        RECT  18.9 0 18.918 0.038 ;
    END
  END a_own[29]
  PIN a_own[2]
    DIRECTION INPUT ;
    USE SIGNAL ;
    PORT
      LAYER M5 ;
        RECT  13.392 0 13.416 0.084 ;
    END
  END a_own[2]
  PIN a_own[30]
    DIRECTION INPUT ;
    USE SIGNAL ;
    PORT
      LAYER M5 ;
        RECT  19.152 0 19.176 0.084 ;
    END
  END a_own[30]
  PIN a_own[31]
    DIRECTION INPUT ;
    USE SIGNAL ;
    PORT
      LAYER M3 ;
        RECT  19.368 0 19.386 0.038 ;
    END
  END a_own[31]
  PIN a_own[32]
    DIRECTION INPUT ;
    USE SIGNAL ;
    PORT
      LAYER M5 ;
        RECT  19.536 0 19.56 0.084 ;
    END
  END a_own[32]
  PIN a_own[33]
    DIRECTION INPUT ;
    USE SIGNAL ;
    PORT
      LAYER M3 ;
        RECT  19.764 0 19.782 0.038 ;
    END
  END a_own[33]
  PIN a_own[34]
    DIRECTION INPUT ;
    USE SIGNAL ;
    PORT
      LAYER M5 ;
        RECT  20.016 0 20.04 0.084 ;
    END
  END a_own[34]
  PIN a_own[35]
    DIRECTION INPUT ;
    USE SIGNAL ;
    PORT
      LAYER M3 ;
        RECT  20.34 0 20.358 0.038 ;
    END
  END a_own[35]
  PIN a_own[36]
    DIRECTION INPUT ;
    USE SIGNAL ;
    PORT
      LAYER M5 ;
        RECT  20.688 0 20.712 0.084 ;
    END
  END a_own[36]
  PIN a_own[37]
    DIRECTION INPUT ;
    USE SIGNAL ;
    PORT
      LAYER M3 ;
        RECT  21.096 0 21.114 0.038 ;
    END
    PORT
      LAYER M3 ;
        RECT  21.096 0.012 21.114 1.723 ;
    END
  END a_own[37]
  PIN a_own[38]
    DIRECTION INPUT ;
    USE SIGNAL ;
    PORT
      LAYER M5 ;
        RECT  21.552 0 21.576 0.084 ;
    END
  END a_own[38]
  PIN a_own[39]
    DIRECTION INPUT ;
    USE SIGNAL ;
    PORT
      LAYER M3 ;
        RECT  21.96 0 21.978 0.038 ;
    END
    PORT
      LAYER M3 ;
        RECT  21.96 0.012 21.978 1.723 ;
    END
  END a_own[39]
  PIN a_own[3]
    DIRECTION INPUT ;
    USE SIGNAL ;
    PORT
      LAYER M3 ;
        RECT  13.608 0 13.626 0.038 ;
    END
  END a_own[3]
  PIN a_own[40]
    DIRECTION INPUT ;
    USE SIGNAL ;
    PORT
      LAYER M5 ;
        RECT  22.416 0 22.44 0.084 ;
    END
  END a_own[40]
  PIN a_own[41]
    DIRECTION INPUT ;
    USE SIGNAL ;
    PORT
      LAYER M3 ;
        RECT  22.752 0 22.77 0.038 ;
    END
    PORT
      LAYER M3 ;
        RECT  22.752 0.012 22.77 1.723 ;
    END
  END a_own[41]
  PIN a_own[42]
    DIRECTION INPUT ;
    USE SIGNAL ;
    PORT
      LAYER M5 ;
        RECT  23.184 0 23.208 0.084 ;
    END
  END a_own[42]
  PIN a_own[43]
    DIRECTION INPUT ;
    USE SIGNAL ;
    PORT
      LAYER M3 ;
        RECT  23.616 0 23.634 0.038 ;
    END
    PORT
      LAYER M3 ;
        RECT  23.616 0.012 23.634 1.723 ;
    END
  END a_own[43]
  PIN a_own[44]
    DIRECTION INPUT ;
    USE SIGNAL ;
    PORT
      LAYER M5 ;
        RECT  24.048 0 24.072 0.084 ;
    END
  END a_own[44]
  PIN a_own[45]
    DIRECTION INPUT ;
    USE SIGNAL ;
    PORT
      LAYER M3 ;
        RECT  24.372 0 24.39 0.038 ;
    END
    PORT
      LAYER M3 ;
        RECT  24.372 0.012 24.39 1.723 ;
    END
  END a_own[45]
  PIN a_own[46]
    DIRECTION INPUT ;
    USE SIGNAL ;
    PORT
      LAYER M5 ;
        RECT  24.816 0 24.84 0.084 ;
    END
  END a_own[46]
  PIN a_own[47]
    DIRECTION INPUT ;
    USE SIGNAL ;
    PORT
      LAYER M3 ;
        RECT  25.236 0 25.254 0.038 ;
    END
    PORT
      LAYER M3 ;
        RECT  25.236 0.012 25.254 1.723 ;
    END
  END a_own[47]
  PIN a_own[48]
    DIRECTION INPUT ;
    USE SIGNAL ;
    PORT
      LAYER M5 ;
        RECT  25.68 0 25.704 0.084 ;
    END
  END a_own[48]
  PIN a_own[49]
    DIRECTION INPUT ;
    USE SIGNAL ;
    PORT
      LAYER M3 ;
        RECT  25.992 0 26.01 0.038 ;
    END
    PORT
      LAYER M3 ;
        RECT  25.992 0.012 26.01 1.723 ;
    END
  END a_own[49]
  PIN a_own[4]
    DIRECTION INPUT ;
    USE SIGNAL ;
    PORT
      LAYER M5 ;
        RECT  13.872 0 13.896 0.084 ;
    END
  END a_own[4]
  PIN a_own[50]
    DIRECTION INPUT ;
    USE SIGNAL ;
    PORT
      LAYER M5 ;
        RECT  26.448 0 26.472 0.084 ;
    END
  END a_own[50]
  PIN a_own[51]
    DIRECTION INPUT ;
    USE SIGNAL ;
    PORT
      LAYER M3 ;
        RECT  26.856 0 26.874 0.038 ;
    END
    PORT
      LAYER M3 ;
        RECT  26.856 0.012 26.874 1.723 ;
    END
  END a_own[51]
  PIN a_own[52]
    DIRECTION INPUT ;
    USE SIGNAL ;
    PORT
      LAYER M5 ;
        RECT  27.312 0 27.336 0.084 ;
    END
  END a_own[52]
  PIN a_own[53]
    DIRECTION INPUT ;
    USE SIGNAL ;
    PORT
      LAYER M3 ;
        RECT  27.648 0 27.666 0.038 ;
    END
    PORT
      LAYER M3 ;
        RECT  27.648 0.012 27.666 1.723 ;
    END
  END a_own[53]
  PIN a_own[54]
    DIRECTION INPUT ;
    USE SIGNAL ;
    PORT
      LAYER M5 ;
        RECT  28.08 0 28.104 0.084 ;
    END
  END a_own[54]
  PIN a_own[55]
    DIRECTION INPUT ;
    USE SIGNAL ;
    PORT
      LAYER M3 ;
        RECT  28.512 0 28.53 0.038 ;
    END
    PORT
      LAYER M3 ;
        RECT  28.512 0.012 28.53 1.723 ;
    END
  END a_own[55]
  PIN a_own[56]
    DIRECTION INPUT ;
    USE SIGNAL ;
    PORT
      LAYER M5 ;
        RECT  28.944 0 28.968 0.084 ;
    END
  END a_own[56]
  PIN a_own[57]
    DIRECTION INPUT ;
    USE SIGNAL ;
    PORT
      LAYER M3 ;
        RECT  29.376 0 29.394 0.038 ;
    END
    PORT
      LAYER M3 ;
        RECT  29.376 0.012 29.394 1.723 ;
    END
  END a_own[57]
  PIN a_own[58]
    DIRECTION INPUT ;
    USE SIGNAL ;
    PORT
      LAYER M5 ;
        RECT  29.712 0 29.736 0.084 ;
    END
  END a_own[58]
  PIN a_own[59]
    DIRECTION INPUT ;
    USE SIGNAL ;
    PORT
      LAYER M3 ;
        RECT  30.132 0 30.15 0.038 ;
    END
    PORT
      LAYER M3 ;
        RECT  30.132 0.012 30.15 1.723 ;
    END
  END a_own[59]
  PIN a_own[5]
    DIRECTION INPUT ;
    USE SIGNAL ;
    PORT
      LAYER M3 ;
        RECT  14.004 0 14.022 0.038 ;
    END
  END a_own[5]
  PIN a_own[60]
    DIRECTION INPUT ;
    USE SIGNAL ;
    PORT
      LAYER M5 ;
        RECT  30.576 0 30.6 0.084 ;
    END
  END a_own[60]
  PIN a_own[61]
    DIRECTION INPUT ;
    USE SIGNAL ;
    PORT
      LAYER M3 ;
        RECT  30.996 0 31.014 0.038 ;
    END
    PORT
      LAYER M3 ;
        RECT  30.996 0.012 31.014 1.723 ;
    END
  END a_own[61]
  PIN a_own[62]
    DIRECTION INPUT ;
    USE SIGNAL ;
    PORT
      LAYER M5 ;
        RECT  31.344 0 31.368 0.084 ;
    END
  END a_own[62]
  PIN a_own[63]
    DIRECTION INPUT ;
    USE SIGNAL ;
    PORT
      LAYER M3 ;
        RECT  31.752 0 31.77 0.038 ;
    END
    PORT
      LAYER M3 ;
        RECT  31.752 0.012 31.77 1.723 ;
    END
  END a_own[63]
  PIN a_own[64]
    DIRECTION INPUT ;
    USE SIGNAL ;
    PORT
      LAYER M5 ;
        RECT  32.208 0 32.232 0.084 ;
    END
  END a_own[64]
  PIN a_own[65]
    DIRECTION INPUT ;
    USE SIGNAL ;
    PORT
      LAYER M3 ;
        RECT  32.616 0 32.634 0.038 ;
    END
    PORT
      LAYER M3 ;
        RECT  32.616 0.012 32.634 1.723 ;
    END
  END a_own[65]
  PIN a_own[66]
    DIRECTION INPUT ;
    USE SIGNAL ;
    PORT
      LAYER M5 ;
        RECT  32.976 0 33 0.084 ;
    END
  END a_own[66]
  PIN a_own[67]
    DIRECTION INPUT ;
    USE SIGNAL ;
    PORT
      LAYER M3 ;
        RECT  33.408 0 33.426 0.038 ;
    END
    PORT
      LAYER M3 ;
        RECT  33.408 0.012 33.426 1.723 ;
    END
  END a_own[67]
  PIN a_own[68]
    DIRECTION INPUT ;
    USE SIGNAL ;
    PORT
      LAYER M5 ;
        RECT  33.84 0 33.864 0.084 ;
    END
  END a_own[68]
  PIN a_own[69]
    DIRECTION INPUT ;
    USE SIGNAL ;
    PORT
      LAYER M3 ;
        RECT  34.272 0 34.29 0.038 ;
    END
    PORT
      LAYER M3 ;
        RECT  34.272 0.012 34.29 1.723 ;
    END
  END a_own[69]
  PIN a_own[6]
    DIRECTION INPUT ;
    USE SIGNAL ;
    PORT
      LAYER M5 ;
        RECT  14.256 0 14.28 0.084 ;
    END
  END a_own[6]
  PIN a_own[70]
    DIRECTION INPUT ;
    USE SIGNAL ;
    PORT
      LAYER M5 ;
        RECT  34.608 0 34.632 0.084 ;
    END
  END a_own[70]
  PIN a_own[71]
    DIRECTION INPUT ;
    USE SIGNAL ;
    PORT
      LAYER M3 ;
        RECT  35.028 0 35.046 0.038 ;
    END
    PORT
      LAYER M3 ;
        RECT  35.028 0.012 35.046 1.723 ;
    END
  END a_own[71]
  PIN a_own[72]
    DIRECTION INPUT ;
    USE SIGNAL ;
    PORT
      LAYER M5 ;
        RECT  35.472 0 35.496 0.084 ;
    END
  END a_own[72]
  PIN a_own[73]
    DIRECTION INPUT ;
    USE SIGNAL ;
    PORT
      LAYER M3 ;
        RECT  35.892 0 35.91 0.038 ;
    END
    PORT
      LAYER M3 ;
        RECT  35.892 0.012 35.91 1.723 ;
    END
  END a_own[73]
  PIN a_own[74]
    DIRECTION INPUT ;
    USE SIGNAL ;
    PORT
      LAYER M5 ;
        RECT  36.336 0 36.36 0.084 ;
    END
  END a_own[74]
  PIN a_own[75]
    DIRECTION INPUT ;
    USE SIGNAL ;
    PORT
      LAYER M3 ;
        RECT  36.648 0 36.666 0.038 ;
    END
    PORT
      LAYER M3 ;
        RECT  36.648 0.012 36.666 0.571 ;
    END
  END a_own[75]
  PIN a_own[76]
    DIRECTION INPUT ;
    USE SIGNAL ;
    PORT
      LAYER M5 ;
        RECT  37.104 0 37.128 0.084 ;
    END
  END a_own[76]
  PIN a_own[77]
    DIRECTION INPUT ;
    USE SIGNAL ;
    PORT
      LAYER M3 ;
        RECT  37.512 0 37.53 0.038 ;
    END
    PORT
      LAYER M3 ;
        RECT  37.512 0.012 37.53 0.571 ;
    END
  END a_own[77]
  PIN a_own[78]
    DIRECTION INPUT ;
    USE SIGNAL ;
    PORT
      LAYER M5 ;
        RECT  37.968 0 37.992 0.084 ;
    END
  END a_own[78]
  PIN a_own[79]
    DIRECTION INPUT ;
    USE SIGNAL ;
    PORT
      LAYER M3 ;
        RECT  38.304 0 38.322 0.038 ;
    END
    PORT
      LAYER M3 ;
        RECT  38.304 0.012 38.322 1.723 ;
    END
  END a_own[79]
  PIN a_own[7]
    DIRECTION INPUT ;
    USE SIGNAL ;
    PORT
      LAYER M3 ;
        RECT  14.4 0 14.418 0.038 ;
    END
  END a_own[7]
  PIN a_own[80]
    DIRECTION INPUT ;
    USE SIGNAL ;
    PORT
      LAYER M5 ;
        RECT  38.736 0 38.76 0.084 ;
    END
  END a_own[80]
  PIN a_own[81]
    DIRECTION INPUT ;
    USE SIGNAL ;
    PORT
      LAYER M3 ;
        RECT  39.168 0 39.186 0.038 ;
    END
    PORT
      LAYER M3 ;
        RECT  39.168 0.012 39.186 1.723 ;
    END
  END a_own[81]
  PIN a_own[82]
    DIRECTION INPUT ;
    USE SIGNAL ;
    PORT
      LAYER M5 ;
        RECT  39.6 0 39.624 0.084 ;
    END
  END a_own[82]
  PIN a_own[83]
    DIRECTION INPUT ;
    USE SIGNAL ;
    PORT
      LAYER M3 ;
        RECT  39.924 0 39.942 0.038 ;
    END
    PORT
      LAYER M3 ;
        RECT  39.924 0.012 39.942 1.723 ;
    END
  END a_own[83]
  PIN a_own[84]
    DIRECTION INPUT ;
    USE SIGNAL ;
    PORT
      LAYER M5 ;
        RECT  40.368 0 40.392 0.084 ;
    END
  END a_own[84]
  PIN a_own[85]
    DIRECTION INPUT ;
    USE SIGNAL ;
    PORT
      LAYER M3 ;
        RECT  40.788 0 40.806 0.038 ;
    END
    PORT
      LAYER M3 ;
        RECT  40.788 0.012 40.806 0.571 ;
    END
  END a_own[85]
  PIN a_own[86]
    DIRECTION INPUT ;
    USE SIGNAL ;
    PORT
      LAYER M5 ;
        RECT  41.232 0 41.256 0.084 ;
    END
  END a_own[86]
  PIN a_own[87]
    DIRECTION INPUT ;
    USE SIGNAL ;
    PORT
      LAYER M3 ;
        RECT  41.544 0 41.562 0.038 ;
    END
    PORT
      LAYER M3 ;
        RECT  41.544 0.012 41.562 0.571 ;
    END
  END a_own[87]
  PIN a_own[88]
    DIRECTION INPUT ;
    USE SIGNAL ;
    PORT
      LAYER M5 ;
        RECT  42 0 42.024 0.084 ;
    END
  END a_own[88]
  PIN a_own[89]
    DIRECTION INPUT ;
    USE SIGNAL ;
    PORT
      LAYER M3 ;
        RECT  42.408 0 42.426 0.038 ;
    END
    PORT
      LAYER M3 ;
        RECT  42.408 0.012 42.426 1.723 ;
    END
  END a_own[89]
  PIN a_own[8]
    DIRECTION INPUT ;
    USE SIGNAL ;
    PORT
      LAYER M5 ;
        RECT  14.64 0 14.664 0.084 ;
    END
  END a_own[8]
  PIN a_own[90]
    DIRECTION INPUT ;
    USE SIGNAL ;
    PORT
      LAYER M5 ;
        RECT  42.864 0 42.888 0.084 ;
    END
  END a_own[90]
  PIN a_own[91]
    DIRECTION INPUT ;
    USE SIGNAL ;
    PORT
      LAYER M3 ;
        RECT  43.272 0 43.29 0.038 ;
    END
    PORT
      LAYER M3 ;
        RECT  43.272 0.012 43.29 1.723 ;
    END
  END a_own[91]
  PIN a_own[92]
    DIRECTION INPUT ;
    USE SIGNAL ;
    PORT
      LAYER M5 ;
        RECT  43.632 0 43.656 0.084 ;
    END
  END a_own[92]
  PIN a_own[93]
    DIRECTION INPUT ;
    USE SIGNAL ;
    PORT
      LAYER M3 ;
        RECT  44.064 0 44.082 0.038 ;
    END
    PORT
      LAYER M3 ;
        RECT  44.064 0.012 44.082 0.571 ;
    END
  END a_own[93]
  PIN a_own[94]
    DIRECTION INPUT ;
    USE SIGNAL ;
    PORT
      LAYER M5 ;
        RECT  44.496 0 44.52 0.084 ;
    END
  END a_own[94]
  PIN a_own[95]
    DIRECTION INPUT ;
    USE SIGNAL ;
    PORT
      LAYER M3 ;
        RECT  44.928 0 44.946 0.038 ;
    END
    PORT
      LAYER M3 ;
        RECT  44.928 0.012 44.946 0.571 ;
    END
  END a_own[95]
  PIN a_own[96]
    DIRECTION INPUT ;
    USE SIGNAL ;
    PORT
      LAYER M5 ;
        RECT  45.264 0 45.288 0.084 ;
    END
  END a_own[96]
  PIN a_own[97]
    DIRECTION INPUT ;
    USE SIGNAL ;
    PORT
      LAYER M3 ;
        RECT  45.684 0 45.702 0.038 ;
    END
    PORT
      LAYER M3 ;
        RECT  45.684 0.012 45.702 1.723 ;
    END
  END a_own[97]
  PIN a_own[98]
    DIRECTION INPUT ;
    USE SIGNAL ;
    PORT
      LAYER M5 ;
        RECT  46.128 0 46.152 0.084 ;
    END
  END a_own[98]
  PIN a_own[99]
    DIRECTION INPUT ;
    USE SIGNAL ;
    PORT
      LAYER M3 ;
        RECT  46.548 0 46.566 0.038 ;
    END
    PORT
      LAYER M3 ;
        RECT  46.548 0.012 46.566 0.571 ;
    END
  END a_own[99]
  PIN a_own[9]
    DIRECTION INPUT ;
    USE SIGNAL ;
    PORT
      LAYER M3 ;
        RECT  14.868 0 14.886 0.038 ;
    END
  END a_own[9]
  PIN a_own_out[0]
    DIRECTION OUTPUT ;
    USE SIGNAL ;
    PORT
      LAYER M5 ;
        RECT  13.008 25.836 13.032 25.92 ;
    END
  END a_own_out[0]
  PIN a_own_out[100]
    DIRECTION OUTPUT ;
    USE SIGNAL ;
    PORT
      LAYER M5 ;
        RECT  46.896 25.836 46.92 25.92 ;
    END
  END a_own_out[100]
  PIN a_own_out[101]
    DIRECTION OUTPUT ;
    USE SIGNAL ;
    PORT
      LAYER M3 ;
        RECT  47.304 25.882 47.322 25.92 ;
    END
    PORT
      LAYER M3 ;
        RECT  47.304 25.085 47.322 25.901 ;
    END
  END a_own_out[101]
  PIN a_own_out[102]
    DIRECTION OUTPUT ;
    USE SIGNAL ;
    PORT
      LAYER M5 ;
        RECT  47.76 25.836 47.784 25.92 ;
    END
  END a_own_out[102]
  PIN a_own_out[103]
    DIRECTION OUTPUT ;
    USE SIGNAL ;
    PORT
      LAYER M3 ;
        RECT  48.168 25.882 48.186 25.92 ;
    END
    PORT
      LAYER M3 ;
        RECT  48.168 25.085 48.186 25.901 ;
    END
  END a_own_out[103]
  PIN a_own_out[104]
    DIRECTION OUTPUT ;
    USE SIGNAL ;
    PORT
      LAYER M5 ;
        RECT  48.528 25.836 48.552 25.92 ;
    END
  END a_own_out[104]
  PIN a_own_out[105]
    DIRECTION OUTPUT ;
    USE SIGNAL ;
    PORT
      LAYER M3 ;
        RECT  48.96 25.882 48.978 25.92 ;
    END
    PORT
      LAYER M3 ;
        RECT  48.96 25.133 48.978 25.901 ;
    END
  END a_own_out[105]
  PIN a_own_out[106]
    DIRECTION OUTPUT ;
    USE SIGNAL ;
    PORT
      LAYER M5 ;
        RECT  49.392 25.836 49.416 25.92 ;
    END
  END a_own_out[106]
  PIN a_own_out[107]
    DIRECTION OUTPUT ;
    USE SIGNAL ;
    PORT
      LAYER M3 ;
        RECT  49.824 25.882 49.842 25.92 ;
    END
    PORT
      LAYER M3 ;
        RECT  49.824 25.133 49.842 25.901 ;
    END
  END a_own_out[107]
  PIN a_own_out[108]
    DIRECTION OUTPUT ;
    USE SIGNAL ;
    PORT
      LAYER M5 ;
        RECT  50.256 25.836 50.28 25.92 ;
    END
  END a_own_out[108]
  PIN a_own_out[109]
    DIRECTION OUTPUT ;
    USE SIGNAL ;
    PORT
      LAYER M3 ;
        RECT  50.58 25.882 50.598 25.92 ;
    END
    PORT
      LAYER M3 ;
        RECT  50.58 25.133 50.598 25.901 ;
    END
  END a_own_out[109]
  PIN a_own_out[10]
    DIRECTION OUTPUT ;
    USE SIGNAL ;
    PORT
      LAYER M5 ;
        RECT  15.024 25.836 15.048 25.92 ;
    END
  END a_own_out[10]
  PIN a_own_out[110]
    DIRECTION OUTPUT ;
    USE SIGNAL ;
    PORT
      LAYER M5 ;
        RECT  51.024 25.836 51.048 25.92 ;
    END
  END a_own_out[110]
  PIN a_own_out[111]
    DIRECTION OUTPUT ;
    USE SIGNAL ;
    PORT
      LAYER M3 ;
        RECT  51.444 25.882 51.462 25.92 ;
    END
    PORT
      LAYER M3 ;
        RECT  51.444 25.805 51.462 25.901 ;
    END
  END a_own_out[111]
  PIN a_own_out[112]
    DIRECTION OUTPUT ;
    USE SIGNAL ;
    PORT
      LAYER M5 ;
        RECT  51.888 25.836 51.912 25.92 ;
    END
  END a_own_out[112]
  PIN a_own_out[113]
    DIRECTION OUTPUT ;
    USE SIGNAL ;
    PORT
      LAYER M3 ;
        RECT  52.2 25.882 52.218 25.92 ;
    END
    PORT
      LAYER M3 ;
        RECT  52.2 25.805 52.218 25.901 ;
    END
  END a_own_out[113]
  PIN a_own_out[114]
    DIRECTION OUTPUT ;
    USE SIGNAL ;
    PORT
      LAYER M5 ;
        RECT  52.656 25.836 52.68 25.92 ;
    END
  END a_own_out[114]
  PIN a_own_out[115]
    DIRECTION OUTPUT ;
    USE SIGNAL ;
    PORT
      LAYER M3 ;
        RECT  53.064 25.882 53.082 25.92 ;
    END
    PORT
      LAYER M3 ;
        RECT  53.064 25.805 53.082 25.901 ;
    END
  END a_own_out[115]
  PIN a_own_out[116]
    DIRECTION OUTPUT ;
    USE SIGNAL ;
    PORT
      LAYER M5 ;
        RECT  53.52 25.836 53.544 25.92 ;
    END
  END a_own_out[116]
  PIN a_own_out[117]
    DIRECTION OUTPUT ;
    USE SIGNAL ;
    PORT
      LAYER M3 ;
        RECT  53.856 25.882 53.874 25.92 ;
    END
    PORT
      LAYER M3 ;
        RECT  53.856 24.509 53.874 25.901 ;
    END
  END a_own_out[117]
  PIN a_own_out[118]
    DIRECTION OUTPUT ;
    USE SIGNAL ;
    PORT
      LAYER M5 ;
        RECT  54.288 25.836 54.312 25.92 ;
    END
  END a_own_out[118]
  PIN a_own_out[119]
    DIRECTION OUTPUT ;
    USE SIGNAL ;
    PORT
      LAYER M3 ;
        RECT  54.72 25.882 54.738 25.92 ;
    END
    PORT
      LAYER M3 ;
        RECT  54.72 25.805 54.738 25.901 ;
    END
  END a_own_out[119]
  PIN a_own_out[11]
    DIRECTION OUTPUT ;
    USE SIGNAL ;
    PORT
      LAYER M3 ;
        RECT  15.264 25.882 15.282 25.92 ;
    END
  END a_own_out[11]
  PIN a_own_out[120]
    DIRECTION OUTPUT ;
    USE SIGNAL ;
    PORT
      LAYER M5 ;
        RECT  55.152 25.836 55.176 25.92 ;
    END
  END a_own_out[120]
  PIN a_own_out[121]
    DIRECTION OUTPUT ;
    USE SIGNAL ;
    PORT
      LAYER M3 ;
        RECT  55.476 25.882 55.494 25.92 ;
    END
    PORT
      LAYER M3 ;
        RECT  55.476 25.889 55.494 25.901 ;
    END
  END a_own_out[121]
  PIN a_own_out[122]
    DIRECTION OUTPUT ;
    USE SIGNAL ;
    PORT
      LAYER M5 ;
        RECT  55.92 25.836 55.944 25.92 ;
    END
  END a_own_out[122]
  PIN a_own_out[123]
    DIRECTION OUTPUT ;
    USE SIGNAL ;
    PORT
      LAYER M3 ;
        RECT  56.34 25.882 56.358 25.92 ;
    END
    PORT
      LAYER M3 ;
        RECT  56.34 25.889 56.358 25.901 ;
    END
  END a_own_out[123]
  PIN a_own_out[124]
    DIRECTION OUTPUT ;
    USE SIGNAL ;
    PORT
      LAYER M5 ;
        RECT  56.784 25.836 56.808 25.92 ;
    END
  END a_own_out[124]
  PIN a_own_out[125]
    DIRECTION OUTPUT ;
    USE SIGNAL ;
    PORT
      LAYER M3 ;
        RECT  57.204 25.882 57.222 25.92 ;
    END
    PORT
      LAYER M3 ;
        RECT  57.204 23.933 57.222 25.901 ;
    END
  END a_own_out[125]
  PIN a_own_out[126]
    DIRECTION OUTPUT ;
    USE SIGNAL ;
    PORT
      LAYER M5 ;
        RECT  57.552 25.836 57.576 25.92 ;
    END
  END a_own_out[126]
  PIN a_own_out[127]
    DIRECTION OUTPUT ;
    USE SIGNAL ;
    PORT
      LAYER M3 ;
        RECT  57.96 25.882 57.978 25.92 ;
    END
    PORT
      LAYER M3 ;
        RECT  57.96 23.933 57.978 25.901 ;
    END
  END a_own_out[127]
  PIN a_own_out[128]
    DIRECTION OUTPUT ;
    USE SIGNAL ;
    PORT
      LAYER M5 ;
        RECT  58.416 25.836 58.44 25.92 ;
    END
  END a_own_out[128]
  PIN a_own_out[129]
    DIRECTION OUTPUT ;
    USE SIGNAL ;
    PORT
      LAYER M3 ;
        RECT  58.824 25.882 58.842 25.92 ;
    END
    PORT
      LAYER M3 ;
        RECT  58.824 25.805 58.842 25.901 ;
    END
  END a_own_out[129]
  PIN a_own_out[12]
    DIRECTION OUTPUT ;
    USE SIGNAL ;
    PORT
      LAYER M5 ;
        RECT  15.504 25.836 15.528 25.92 ;
    END
  END a_own_out[12]
  PIN a_own_out[130]
    DIRECTION OUTPUT ;
    USE SIGNAL ;
    PORT
      LAYER M5 ;
        RECT  59.184 25.836 59.208 25.92 ;
    END
  END a_own_out[130]
  PIN a_own_out[131]
    DIRECTION OUTPUT ;
    USE SIGNAL ;
    PORT
      LAYER M3 ;
        RECT  59.616 25.882 59.634 25.92 ;
    END
  END a_own_out[131]
  PIN a_own_out[132]
    DIRECTION OUTPUT ;
    USE SIGNAL ;
    PORT
      LAYER M5 ;
        RECT  60.048 25.836 60.072 25.92 ;
    END
  END a_own_out[132]
  PIN a_own_out[133]
    DIRECTION OUTPUT ;
    USE SIGNAL ;
    PORT
      LAYER M3 ;
        RECT  60.264 25.882 60.282 25.92 ;
    END
  END a_own_out[133]
  PIN a_own_out[134]
    DIRECTION OUTPUT ;
    USE SIGNAL ;
    PORT
      LAYER M5 ;
        RECT  60.432 25.836 60.456 25.92 ;
    END
  END a_own_out[134]
  PIN a_own_out[135]
    DIRECTION OUTPUT ;
    USE SIGNAL ;
    PORT
      LAYER M3 ;
        RECT  60.66 25.882 60.678 25.92 ;
    END
  END a_own_out[135]
  PIN a_own_out[136]
    DIRECTION OUTPUT ;
    USE SIGNAL ;
    PORT
      LAYER M5 ;
        RECT  60.816 25.836 60.84 25.92 ;
    END
  END a_own_out[136]
  PIN a_own_out[137]
    DIRECTION OUTPUT ;
    USE SIGNAL ;
    PORT
      LAYER M3 ;
        RECT  61.056 25.882 61.074 25.92 ;
    END
  END a_own_out[137]
  PIN a_own_out[138]
    DIRECTION OUTPUT ;
    USE SIGNAL ;
    PORT
      LAYER M5 ;
        RECT  61.296 25.836 61.32 25.92 ;
    END
  END a_own_out[138]
  PIN a_own_out[139]
    DIRECTION OUTPUT ;
    USE SIGNAL ;
    PORT
      LAYER M3 ;
        RECT  61.416 25.882 61.434 25.92 ;
    END
  END a_own_out[139]
  PIN a_own_out[13]
    DIRECTION OUTPUT ;
    USE SIGNAL ;
    PORT
      LAYER M3 ;
        RECT  15.624 25.882 15.642 25.92 ;
    END
  END a_own_out[13]
  PIN a_own_out[140]
    DIRECTION OUTPUT ;
    USE SIGNAL ;
    PORT
      LAYER M5 ;
        RECT  61.68 25.836 61.704 25.92 ;
    END
  END a_own_out[140]
  PIN a_own_out[141]
    DIRECTION OUTPUT ;
    USE SIGNAL ;
    PORT
      LAYER M3 ;
        RECT  61.92 25.882 61.938 25.92 ;
    END
  END a_own_out[141]
  PIN a_own_out[142]
    DIRECTION OUTPUT ;
    USE SIGNAL ;
    PORT
      LAYER M5 ;
        RECT  62.064 25.836 62.088 25.92 ;
    END
  END a_own_out[142]
  PIN a_own_out[143]
    DIRECTION OUTPUT ;
    USE SIGNAL ;
    PORT
      LAYER M3 ;
        RECT  62.28 25.882 62.298 25.92 ;
    END
  END a_own_out[143]
  PIN a_own_out[144]
    DIRECTION OUTPUT ;
    USE SIGNAL ;
    PORT
      LAYER M5 ;
        RECT  62.448 25.836 62.472 25.92 ;
    END
  END a_own_out[144]
  PIN a_own_out[145]
    DIRECTION OUTPUT ;
    USE SIGNAL ;
    PORT
      LAYER M3 ;
        RECT  62.676 25.882 62.694 25.92 ;
    END
  END a_own_out[145]
  PIN a_own_out[146]
    DIRECTION OUTPUT ;
    USE SIGNAL ;
    PORT
      LAYER M5 ;
        RECT  62.928 25.836 62.952 25.92 ;
    END
  END a_own_out[146]
  PIN a_own_out[147]
    DIRECTION OUTPUT ;
    USE SIGNAL ;
    PORT
      LAYER M3 ;
        RECT  63.072 25.882 63.09 25.92 ;
    END
  END a_own_out[147]
  PIN a_own_out[148]
    DIRECTION OUTPUT ;
    USE SIGNAL ;
    PORT
      LAYER M5 ;
        RECT  63.312 25.836 63.336 25.92 ;
    END
  END a_own_out[148]
  PIN a_own_out[149]
    DIRECTION OUTPUT ;
    USE SIGNAL ;
    PORT
      LAYER M3 ;
        RECT  63.54 25.882 63.558 25.92 ;
    END
  END a_own_out[149]
  PIN a_own_out[14]
    DIRECTION OUTPUT ;
    USE SIGNAL ;
    PORT
      LAYER M5 ;
        RECT  15.888 25.836 15.912 25.92 ;
    END
  END a_own_out[14]
  PIN a_own_out[150]
    DIRECTION OUTPUT ;
    USE SIGNAL ;
    PORT
      LAYER M5 ;
        RECT  63.696 25.836 63.72 25.92 ;
    END
  END a_own_out[150]
  PIN a_own_out[151]
    DIRECTION OUTPUT ;
    USE SIGNAL ;
    PORT
      LAYER M3 ;
        RECT  63.936 25.882 63.954 25.92 ;
    END
  END a_own_out[151]
  PIN a_own_out[152]
    DIRECTION OUTPUT ;
    USE SIGNAL ;
    PORT
      LAYER M5 ;
        RECT  64.176 25.836 64.2 25.92 ;
    END
  END a_own_out[152]
  PIN a_own_out[153]
    DIRECTION OUTPUT ;
    USE SIGNAL ;
    PORT
      LAYER M3 ;
        RECT  64.296 25.882 64.314 25.92 ;
    END
  END a_own_out[153]
  PIN a_own_out[154]
    DIRECTION OUTPUT ;
    USE SIGNAL ;
    PORT
      LAYER M5 ;
        RECT  64.56 25.836 64.584 25.92 ;
    END
  END a_own_out[154]
  PIN a_own_out[155]
    DIRECTION OUTPUT ;
    USE SIGNAL ;
    PORT
      LAYER M3 ;
        RECT  64.692 25.882 64.71 25.92 ;
    END
  END a_own_out[155]
  PIN a_own_out[156]
    DIRECTION OUTPUT ;
    USE SIGNAL ;
    PORT
      LAYER M5 ;
        RECT  64.944 25.836 64.968 25.92 ;
    END
  END a_own_out[156]
  PIN a_own_out[157]
    DIRECTION OUTPUT ;
    USE SIGNAL ;
    PORT
      LAYER M3 ;
        RECT  65.16 25.882 65.178 25.92 ;
    END
  END a_own_out[157]
  PIN a_own_out[158]
    DIRECTION OUTPUT ;
    USE SIGNAL ;
    PORT
      LAYER M5 ;
        RECT  65.328 25.836 65.352 25.92 ;
    END
  END a_own_out[158]
  PIN a_own_out[159]
    DIRECTION OUTPUT ;
    USE SIGNAL ;
    PORT
      LAYER M3 ;
        RECT  65.556 25.882 65.574 25.92 ;
    END
  END a_own_out[159]
  PIN a_own_out[15]
    DIRECTION OUTPUT ;
    USE SIGNAL ;
    PORT
      LAYER M3 ;
        RECT  16.128 25.882 16.146 25.92 ;
    END
  END a_own_out[15]
  PIN a_own_out[160]
    DIRECTION OUTPUT ;
    USE SIGNAL ;
    PORT
      LAYER M5 ;
        RECT  65.808 25.836 65.832 25.92 ;
    END
  END a_own_out[160]
  PIN a_own_out[161]
    DIRECTION OUTPUT ;
    USE SIGNAL ;
    PORT
      LAYER M3 ;
        RECT  65.952 25.882 65.97 25.92 ;
    END
  END a_own_out[161]
  PIN a_own_out[162]
    DIRECTION OUTPUT ;
    USE SIGNAL ;
    PORT
      LAYER M5 ;
        RECT  66.192 25.836 66.216 25.92 ;
    END
  END a_own_out[162]
  PIN a_own_out[163]
    DIRECTION OUTPUT ;
    USE SIGNAL ;
    PORT
      LAYER M3 ;
        RECT  66.42 25.882 66.438 25.92 ;
    END
  END a_own_out[163]
  PIN a_own_out[164]
    DIRECTION OUTPUT ;
    USE SIGNAL ;
    PORT
      LAYER M5 ;
        RECT  66.576 25.836 66.6 25.92 ;
    END
  END a_own_out[164]
  PIN a_own_out[165]
    DIRECTION OUTPUT ;
    USE SIGNAL ;
    PORT
      LAYER M3 ;
        RECT  66.816 25.882 66.834 25.92 ;
    END
  END a_own_out[165]
  PIN a_own_out[166]
    DIRECTION OUTPUT ;
    USE SIGNAL ;
    PORT
      LAYER M5 ;
        RECT  66.96 25.836 66.984 25.92 ;
    END
  END a_own_out[166]
  PIN a_own_out[167]
    DIRECTION OUTPUT ;
    USE SIGNAL ;
    PORT
      LAYER M3 ;
        RECT  67.176 25.882 67.194 25.92 ;
    END
  END a_own_out[167]
  PIN a_own_out[168]
    DIRECTION OUTPUT ;
    USE SIGNAL ;
    PORT
      LAYER M5 ;
        RECT  67.44 25.836 67.464 25.92 ;
    END
  END a_own_out[168]
  PIN a_own_out[169]
    DIRECTION OUTPUT ;
    USE SIGNAL ;
    PORT
      LAYER M3 ;
        RECT  67.572 25.882 67.59 25.92 ;
    END
  END a_own_out[169]
  PIN a_own_out[16]
    DIRECTION OUTPUT ;
    USE SIGNAL ;
    PORT
      LAYER M5 ;
        RECT  16.272 25.836 16.296 25.92 ;
    END
  END a_own_out[16]
  PIN a_own_out[170]
    DIRECTION OUTPUT ;
    USE SIGNAL ;
    PORT
      LAYER M5 ;
        RECT  67.824 25.836 67.848 25.92 ;
    END
  END a_own_out[170]
  PIN a_own_out[171]
    DIRECTION OUTPUT ;
    USE SIGNAL ;
    PORT
      LAYER M3 ;
        RECT  68.04 25.882 68.058 25.92 ;
    END
  END a_own_out[171]
  PIN a_own_out[172]
    DIRECTION OUTPUT ;
    USE SIGNAL ;
    PORT
      LAYER M5 ;
        RECT  68.208 25.836 68.232 25.92 ;
    END
  END a_own_out[172]
  PIN a_own_out[173]
    DIRECTION OUTPUT ;
    USE SIGNAL ;
    PORT
      LAYER M3 ;
        RECT  68.436 25.882 68.454 25.92 ;
    END
  END a_own_out[173]
  PIN a_own_out[174]
    DIRECTION OUTPUT ;
    USE SIGNAL ;
    PORT
      LAYER M5 ;
        RECT  68.592 25.836 68.616 25.92 ;
    END
  END a_own_out[174]
  PIN a_own_out[175]
    DIRECTION OUTPUT ;
    USE SIGNAL ;
    PORT
      LAYER M3 ;
        RECT  68.832 25.882 68.85 25.92 ;
    END
  END a_own_out[175]
  PIN a_own_out[176]
    DIRECTION OUTPUT ;
    USE SIGNAL ;
    PORT
      LAYER M5 ;
        RECT  69.072 25.836 69.096 25.92 ;
    END
  END a_own_out[176]
  PIN a_own_out[177]
    DIRECTION OUTPUT ;
    USE SIGNAL ;
    PORT
      LAYER M3 ;
        RECT  69.192 25.882 69.21 25.92 ;
    END
  END a_own_out[177]
  PIN a_own_out[178]
    DIRECTION OUTPUT ;
    USE SIGNAL ;
    PORT
      LAYER M5 ;
        RECT  69.456 25.836 69.48 25.92 ;
    END
  END a_own_out[178]
  PIN a_own_out[179]
    DIRECTION OUTPUT ;
    USE SIGNAL ;
    PORT
      LAYER M3 ;
        RECT  69.696 25.882 69.714 25.92 ;
    END
  END a_own_out[179]
  PIN a_own_out[17]
    DIRECTION OUTPUT ;
    USE SIGNAL ;
    PORT
      LAYER M3 ;
        RECT  16.488 25.882 16.506 25.92 ;
    END
  END a_own_out[17]
  PIN a_own_out[180]
    DIRECTION OUTPUT ;
    USE SIGNAL ;
    PORT
      LAYER M5 ;
        RECT  69.84 25.836 69.864 25.92 ;
    END
  END a_own_out[180]
  PIN a_own_out[181]
    DIRECTION OUTPUT ;
    USE SIGNAL ;
    PORT
      LAYER M3 ;
        RECT  70.056 25.882 70.074 25.92 ;
    END
  END a_own_out[181]
  PIN a_own_out[182]
    DIRECTION OUTPUT ;
    USE SIGNAL ;
    PORT
      LAYER M5 ;
        RECT  70.32 25.836 70.344 25.92 ;
    END
  END a_own_out[182]
  PIN a_own_out[183]
    DIRECTION OUTPUT ;
    USE SIGNAL ;
    PORT
      LAYER M3 ;
        RECT  70.452 25.882 70.47 25.92 ;
    END
  END a_own_out[183]
  PIN a_own_out[184]
    DIRECTION OUTPUT ;
    USE SIGNAL ;
    PORT
      LAYER M5 ;
        RECT  70.704 25.836 70.728 25.92 ;
    END
  END a_own_out[184]
  PIN a_own_out[185]
    DIRECTION OUTPUT ;
    USE SIGNAL ;
    PORT
      LAYER M3 ;
        RECT  70.848 25.882 70.866 25.92 ;
    END
  END a_own_out[185]
  PIN a_own_out[186]
    DIRECTION OUTPUT ;
    USE SIGNAL ;
    PORT
      LAYER M5 ;
        RECT  71.088 25.836 71.112 25.92 ;
    END
  END a_own_out[186]
  PIN a_own_out[187]
    DIRECTION OUTPUT ;
    USE SIGNAL ;
    PORT
      LAYER M3 ;
        RECT  71.316 25.882 71.334 25.92 ;
    END
  END a_own_out[187]
  PIN a_own_out[188]
    DIRECTION OUTPUT ;
    USE SIGNAL ;
    PORT
      LAYER M5 ;
        RECT  71.472 25.836 71.496 25.92 ;
    END
  END a_own_out[188]
  PIN a_own_out[189]
    DIRECTION OUTPUT ;
    USE SIGNAL ;
    PORT
      LAYER M3 ;
        RECT  71.712 25.882 71.73 25.92 ;
    END
  END a_own_out[189]
  PIN a_own_out[18]
    DIRECTION OUTPUT ;
    USE SIGNAL ;
    PORT
      LAYER M5 ;
        RECT  16.656 25.836 16.68 25.92 ;
    END
  END a_own_out[18]
  PIN a_own_out[190]
    DIRECTION OUTPUT ;
    USE SIGNAL ;
    PORT
      LAYER M5 ;
        RECT  71.952 25.836 71.976 25.92 ;
    END
  END a_own_out[190]
  PIN a_own_out[191]
    DIRECTION OUTPUT ;
    USE SIGNAL ;
    PORT
      LAYER M3 ;
        RECT  72.072 25.882 72.09 25.92 ;
    END
  END a_own_out[191]
  PIN a_own_out[192]
    DIRECTION OUTPUT ;
    USE SIGNAL ;
    PORT
      LAYER M5 ;
        RECT  72.336 25.836 72.36 25.92 ;
    END
  END a_own_out[192]
  PIN a_own_out[193]
    DIRECTION OUTPUT ;
    USE SIGNAL ;
    PORT
      LAYER M3 ;
        RECT  72.468 25.882 72.486 25.92 ;
    END
  END a_own_out[193]
  PIN a_own_out[194]
    DIRECTION OUTPUT ;
    USE SIGNAL ;
    PORT
      LAYER M5 ;
        RECT  72.72 25.836 72.744 25.92 ;
    END
  END a_own_out[194]
  PIN a_own_out[195]
    DIRECTION OUTPUT ;
    USE SIGNAL ;
    PORT
      LAYER M3 ;
        RECT  72.936 25.882 72.954 25.92 ;
    END
  END a_own_out[195]
  PIN a_own_out[196]
    DIRECTION OUTPUT ;
    USE SIGNAL ;
    PORT
      LAYER M5 ;
        RECT  73.104 25.836 73.128 25.92 ;
    END
  END a_own_out[196]
  PIN a_own_out[197]
    DIRECTION OUTPUT ;
    USE SIGNAL ;
    PORT
      LAYER M3 ;
        RECT  73.332 25.882 73.35 25.92 ;
    END
  END a_own_out[197]
  PIN a_own_out[198]
    DIRECTION OUTPUT ;
    USE SIGNAL ;
    PORT
      LAYER M5 ;
        RECT  73.584 25.836 73.608 25.92 ;
    END
  END a_own_out[198]
  PIN a_own_out[199]
    DIRECTION OUTPUT ;
    USE SIGNAL ;
    PORT
      LAYER M3 ;
        RECT  73.728 25.882 73.746 25.92 ;
    END
  END a_own_out[199]
  PIN a_own_out[19]
    DIRECTION OUTPUT ;
    USE SIGNAL ;
    PORT
      LAYER M3 ;
        RECT  16.884 25.882 16.902 25.92 ;
    END
  END a_own_out[19]
  PIN a_own_out[1]
    DIRECTION OUTPUT ;
    USE SIGNAL ;
    PORT
      LAYER M3 ;
        RECT  13.248 25.882 13.266 25.92 ;
    END
  END a_own_out[1]
  PIN a_own_out[200]
    DIRECTION OUTPUT ;
    USE SIGNAL ;
    PORT
      LAYER M5 ;
        RECT  73.968 25.836 73.992 25.92 ;
    END
  END a_own_out[200]
  PIN a_own_out[201]
    DIRECTION OUTPUT ;
    USE SIGNAL ;
    PORT
      LAYER M3 ;
        RECT  74.196 25.882 74.214 25.92 ;
    END
  END a_own_out[201]
  PIN a_own_out[202]
    DIRECTION OUTPUT ;
    USE SIGNAL ;
    PORT
      LAYER M5 ;
        RECT  74.352 25.836 74.376 25.92 ;
    END
  END a_own_out[202]
  PIN a_own_out[203]
    DIRECTION OUTPUT ;
    USE SIGNAL ;
    PORT
      LAYER M3 ;
        RECT  74.592 25.882 74.61 25.92 ;
    END
  END a_own_out[203]
  PIN a_own_out[204]
    DIRECTION OUTPUT ;
    USE SIGNAL ;
    PORT
      LAYER M5 ;
        RECT  74.736 25.836 74.76 25.92 ;
    END
  END a_own_out[204]
  PIN a_own_out[205]
    DIRECTION OUTPUT ;
    USE SIGNAL ;
    PORT
      LAYER M3 ;
        RECT  74.952 25.882 74.97 25.92 ;
    END
  END a_own_out[205]
  PIN a_own_out[206]
    DIRECTION OUTPUT ;
    USE SIGNAL ;
    PORT
      LAYER M5 ;
        RECT  75.216 25.836 75.24 25.92 ;
    END
  END a_own_out[206]
  PIN a_own_out[207]
    DIRECTION OUTPUT ;
    USE SIGNAL ;
    PORT
      LAYER M3 ;
        RECT  75.348 25.882 75.366 25.92 ;
    END
  END a_own_out[207]
  PIN a_own_out[208]
    DIRECTION OUTPUT ;
    USE SIGNAL ;
    PORT
      LAYER M5 ;
        RECT  75.6 25.836 75.624 25.92 ;
    END
  END a_own_out[208]
  PIN a_own_out[209]
    DIRECTION OUTPUT ;
    USE SIGNAL ;
    PORT
      LAYER M3 ;
        RECT  75.816 25.882 75.834 25.92 ;
    END
  END a_own_out[209]
  PIN a_own_out[20]
    DIRECTION OUTPUT ;
    USE SIGNAL ;
    PORT
      LAYER M5 ;
        RECT  17.136 25.836 17.16 25.92 ;
    END
  END a_own_out[20]
  PIN a_own_out[210]
    DIRECTION OUTPUT ;
    USE SIGNAL ;
    PORT
      LAYER M5 ;
        RECT  75.984 25.836 76.008 25.92 ;
    END
  END a_own_out[210]
  PIN a_own_out[211]
    DIRECTION OUTPUT ;
    USE SIGNAL ;
    PORT
      LAYER M3 ;
        RECT  76.212 25.882 76.23 25.92 ;
    END
  END a_own_out[211]
  PIN a_own_out[212]
    DIRECTION OUTPUT ;
    USE SIGNAL ;
    PORT
      LAYER M5 ;
        RECT  76.464 25.836 76.488 25.92 ;
    END
  END a_own_out[212]
  PIN a_own_out[213]
    DIRECTION OUTPUT ;
    USE SIGNAL ;
    PORT
      LAYER M3 ;
        RECT  76.608 25.882 76.626 25.92 ;
    END
  END a_own_out[213]
  PIN a_own_out[214]
    DIRECTION OUTPUT ;
    USE SIGNAL ;
    PORT
      LAYER M5 ;
        RECT  76.848 25.836 76.872 25.92 ;
    END
  END a_own_out[214]
  PIN a_own_out[215]
    DIRECTION OUTPUT ;
    USE SIGNAL ;
    PORT
      LAYER M3 ;
        RECT  76.968 25.882 76.986 25.92 ;
    END
  END a_own_out[215]
  PIN a_own_out[216]
    DIRECTION OUTPUT ;
    USE SIGNAL ;
    PORT
      LAYER M5 ;
        RECT  77.232 25.836 77.256 25.92 ;
    END
  END a_own_out[216]
  PIN a_own_out[217]
    DIRECTION OUTPUT ;
    USE SIGNAL ;
    PORT
      LAYER M3 ;
        RECT  77.472 25.882 77.49 25.92 ;
    END
  END a_own_out[217]
  PIN a_own_out[218]
    DIRECTION OUTPUT ;
    USE SIGNAL ;
    PORT
      LAYER M5 ;
        RECT  77.616 25.836 77.64 25.92 ;
    END
  END a_own_out[218]
  PIN a_own_out[219]
    DIRECTION OUTPUT ;
    USE SIGNAL ;
    PORT
      LAYER M3 ;
        RECT  77.832 25.882 77.85 25.92 ;
    END
  END a_own_out[219]
  PIN a_own_out[21]
    DIRECTION OUTPUT ;
    USE SIGNAL ;
    PORT
      LAYER M3 ;
        RECT  17.28 25.882 17.298 25.92 ;
    END
  END a_own_out[21]
  PIN a_own_out[220]
    DIRECTION OUTPUT ;
    USE SIGNAL ;
    PORT
      LAYER M5 ;
        RECT  78.096 25.836 78.12 25.92 ;
    END
  END a_own_out[220]
  PIN a_own_out[221]
    DIRECTION OUTPUT ;
    USE SIGNAL ;
    PORT
      LAYER M3 ;
        RECT  78.228 25.882 78.246 25.92 ;
    END
  END a_own_out[221]
  PIN a_own_out[222]
    DIRECTION OUTPUT ;
    USE SIGNAL ;
    PORT
      LAYER M5 ;
        RECT  78.48 25.836 78.504 25.92 ;
    END
  END a_own_out[222]
  PIN a_own_out[223]
    DIRECTION OUTPUT ;
    USE SIGNAL ;
    PORT
      LAYER M3 ;
        RECT  78.624 25.882 78.642 25.92 ;
    END
  END a_own_out[223]
  PIN a_own_out[224]
    DIRECTION OUTPUT ;
    USE SIGNAL ;
    PORT
      LAYER M5 ;
        RECT  78.864 25.836 78.888 25.92 ;
    END
  END a_own_out[224]
  PIN a_own_out[225]
    DIRECTION OUTPUT ;
    USE SIGNAL ;
    PORT
      LAYER M3 ;
        RECT  79.092 25.882 79.11 25.92 ;
    END
  END a_own_out[225]
  PIN a_own_out[226]
    DIRECTION OUTPUT ;
    USE SIGNAL ;
    PORT
      LAYER M5 ;
        RECT  79.248 25.836 79.272 25.92 ;
    END
  END a_own_out[226]
  PIN a_own_out[227]
    DIRECTION OUTPUT ;
    USE SIGNAL ;
    PORT
      LAYER M3 ;
        RECT  79.488 25.882 79.506 25.92 ;
    END
  END a_own_out[227]
  PIN a_own_out[228]
    DIRECTION OUTPUT ;
    USE SIGNAL ;
    PORT
      LAYER M5 ;
        RECT  79.728 25.836 79.752 25.92 ;
    END
  END a_own_out[228]
  PIN a_own_out[229]
    DIRECTION OUTPUT ;
    USE SIGNAL ;
    PORT
      LAYER M3 ;
        RECT  79.848 25.882 79.866 25.92 ;
    END
  END a_own_out[229]
  PIN a_own_out[22]
    DIRECTION OUTPUT ;
    USE SIGNAL ;
    PORT
      LAYER M5 ;
        RECT  17.52 25.836 17.544 25.92 ;
    END
  END a_own_out[22]
  PIN a_own_out[230]
    DIRECTION OUTPUT ;
    USE SIGNAL ;
    PORT
      LAYER M5 ;
        RECT  80.112 25.836 80.136 25.92 ;
    END
  END a_own_out[230]
  PIN a_own_out[231]
    DIRECTION OUTPUT ;
    USE SIGNAL ;
    PORT
      LAYER M3 ;
        RECT  80.352 25.882 80.37 25.92 ;
    END
  END a_own_out[231]
  PIN a_own_out[232]
    DIRECTION OUTPUT ;
    USE SIGNAL ;
    PORT
      LAYER M5 ;
        RECT  80.496 25.836 80.52 25.92 ;
    END
  END a_own_out[232]
  PIN a_own_out[233]
    DIRECTION OUTPUT ;
    USE SIGNAL ;
    PORT
      LAYER M3 ;
        RECT  80.712 25.882 80.73 25.92 ;
    END
  END a_own_out[233]
  PIN a_own_out[234]
    DIRECTION OUTPUT ;
    USE SIGNAL ;
    PORT
      LAYER M5 ;
        RECT  80.88 25.836 80.904 25.92 ;
    END
  END a_own_out[234]
  PIN a_own_out[235]
    DIRECTION OUTPUT ;
    USE SIGNAL ;
    PORT
      LAYER M3 ;
        RECT  81.108 25.882 81.126 25.92 ;
    END
  END a_own_out[235]
  PIN a_own_out[236]
    DIRECTION OUTPUT ;
    USE SIGNAL ;
    PORT
      LAYER M5 ;
        RECT  81.36 25.836 81.384 25.92 ;
    END
  END a_own_out[236]
  PIN a_own_out[237]
    DIRECTION OUTPUT ;
    USE SIGNAL ;
    PORT
      LAYER M3 ;
        RECT  81.504 25.882 81.522 25.92 ;
    END
  END a_own_out[237]
  PIN a_own_out[238]
    DIRECTION OUTPUT ;
    USE SIGNAL ;
    PORT
      LAYER M5 ;
        RECT  81.744 25.836 81.768 25.92 ;
    END
  END a_own_out[238]
  PIN a_own_out[239]
    DIRECTION OUTPUT ;
    USE SIGNAL ;
    PORT
      LAYER M3 ;
        RECT  81.972 25.882 81.99 25.92 ;
    END
  END a_own_out[239]
  PIN a_own_out[23]
    DIRECTION OUTPUT ;
    USE SIGNAL ;
    PORT
      LAYER M3 ;
        RECT  17.748 25.882 17.766 25.92 ;
    END
  END a_own_out[23]
  PIN a_own_out[240]
    DIRECTION OUTPUT ;
    USE SIGNAL ;
    PORT
      LAYER M5 ;
        RECT  82.128 25.836 82.152 25.92 ;
    END
  END a_own_out[240]
  PIN a_own_out[241]
    DIRECTION OUTPUT ;
    USE SIGNAL ;
    PORT
      LAYER M3 ;
        RECT  82.368 25.882 82.386 25.92 ;
    END
  END a_own_out[241]
  PIN a_own_out[242]
    DIRECTION OUTPUT ;
    USE SIGNAL ;
    PORT
      LAYER M5 ;
        RECT  82.512 25.836 82.536 25.92 ;
    END
  END a_own_out[242]
  PIN a_own_out[243]
    DIRECTION OUTPUT ;
    USE SIGNAL ;
    PORT
      LAYER M3 ;
        RECT  82.728 25.882 82.746 25.92 ;
    END
  END a_own_out[243]
  PIN a_own_out[244]
    DIRECTION OUTPUT ;
    USE SIGNAL ;
    PORT
      LAYER M5 ;
        RECT  82.992 25.836 83.016 25.92 ;
    END
  END a_own_out[244]
  PIN a_own_out[245]
    DIRECTION OUTPUT ;
    USE SIGNAL ;
    PORT
      LAYER M3 ;
        RECT  83.124 25.882 83.142 25.92 ;
    END
  END a_own_out[245]
  PIN a_own_out[246]
    DIRECTION OUTPUT ;
    USE SIGNAL ;
    PORT
      LAYER M5 ;
        RECT  83.376 25.836 83.4 25.92 ;
    END
  END a_own_out[246]
  PIN a_own_out[247]
    DIRECTION OUTPUT ;
    USE SIGNAL ;
    PORT
      LAYER M3 ;
        RECT  83.592 25.882 83.61 25.92 ;
    END
  END a_own_out[247]
  PIN a_own_out[248]
    DIRECTION OUTPUT ;
    USE SIGNAL ;
    PORT
      LAYER M5 ;
        RECT  83.76 25.836 83.784 25.92 ;
    END
  END a_own_out[248]
  PIN a_own_out[249]
    DIRECTION OUTPUT ;
    USE SIGNAL ;
    PORT
      LAYER M3 ;
        RECT  83.988 25.882 84.006 25.92 ;
    END
  END a_own_out[249]
  PIN a_own_out[24]
    DIRECTION OUTPUT ;
    USE SIGNAL ;
    PORT
      LAYER M5 ;
        RECT  17.904 25.836 17.928 25.92 ;
    END
  END a_own_out[24]
  PIN a_own_out[250]
    DIRECTION OUTPUT ;
    USE SIGNAL ;
    PORT
      LAYER M5 ;
        RECT  84.24 25.836 84.264 25.92 ;
    END
  END a_own_out[250]
  PIN a_own_out[251]
    DIRECTION OUTPUT ;
    USE SIGNAL ;
    PORT
      LAYER M3 ;
        RECT  84.384 25.882 84.402 25.92 ;
    END
  END a_own_out[251]
  PIN a_own_out[252]
    DIRECTION OUTPUT ;
    USE SIGNAL ;
    PORT
      LAYER M5 ;
        RECT  84.624 25.836 84.648 25.92 ;
    END
  END a_own_out[252]
  PIN a_own_out[253]
    DIRECTION OUTPUT ;
    USE SIGNAL ;
    PORT
      LAYER M3 ;
        RECT  84.744 25.882 84.762 25.92 ;
    END
  END a_own_out[253]
  PIN a_own_out[254]
    DIRECTION OUTPUT ;
    USE SIGNAL ;
    PORT
      LAYER M5 ;
        RECT  85.008 25.836 85.032 25.92 ;
    END
  END a_own_out[254]
  PIN a_own_out[255]
    DIRECTION OUTPUT ;
    USE SIGNAL ;
    PORT
      LAYER M3 ;
        RECT  85.248 25.882 85.266 25.92 ;
    END
  END a_own_out[255]
  PIN a_own_out[25]
    DIRECTION OUTPUT ;
    USE SIGNAL ;
    PORT
      LAYER M3 ;
        RECT  18.144 25.882 18.162 25.92 ;
    END
  END a_own_out[25]
  PIN a_own_out[26]
    DIRECTION OUTPUT ;
    USE SIGNAL ;
    PORT
      LAYER M5 ;
        RECT  18.384 25.836 18.408 25.92 ;
    END
  END a_own_out[26]
  PIN a_own_out[27]
    DIRECTION OUTPUT ;
    USE SIGNAL ;
    PORT
      LAYER M3 ;
        RECT  18.504 25.882 18.522 25.92 ;
    END
  END a_own_out[27]
  PIN a_own_out[28]
    DIRECTION OUTPUT ;
    USE SIGNAL ;
    PORT
      LAYER M5 ;
        RECT  18.768 25.836 18.792 25.92 ;
    END
  END a_own_out[28]
  PIN a_own_out[29]
    DIRECTION OUTPUT ;
    USE SIGNAL ;
    PORT
      LAYER M3 ;
        RECT  18.9 25.882 18.918 25.92 ;
    END
  END a_own_out[29]
  PIN a_own_out[2]
    DIRECTION OUTPUT ;
    USE SIGNAL ;
    PORT
      LAYER M5 ;
        RECT  13.392 25.836 13.416 25.92 ;
    END
  END a_own_out[2]
  PIN a_own_out[30]
    DIRECTION OUTPUT ;
    USE SIGNAL ;
    PORT
      LAYER M5 ;
        RECT  19.152 25.836 19.176 25.92 ;
    END
  END a_own_out[30]
  PIN a_own_out[31]
    DIRECTION OUTPUT ;
    USE SIGNAL ;
    PORT
      LAYER M3 ;
        RECT  19.368 25.882 19.386 25.92 ;
    END
  END a_own_out[31]
  PIN a_own_out[32]
    DIRECTION OUTPUT ;
    USE SIGNAL ;
    PORT
      LAYER M5 ;
        RECT  19.536 25.836 19.56 25.92 ;
    END
  END a_own_out[32]
  PIN a_own_out[33]
    DIRECTION OUTPUT ;
    USE SIGNAL ;
    PORT
      LAYER M3 ;
        RECT  19.764 25.882 19.782 25.92 ;
    END
  END a_own_out[33]
  PIN a_own_out[34]
    DIRECTION OUTPUT ;
    USE SIGNAL ;
    PORT
      LAYER M5 ;
        RECT  20.016 25.836 20.04 25.92 ;
    END
  END a_own_out[34]
  PIN a_own_out[35]
    DIRECTION OUTPUT ;
    USE SIGNAL ;
    PORT
      LAYER M3 ;
        RECT  20.34 25.882 20.358 25.92 ;
    END
  END a_own_out[35]
  PIN a_own_out[36]
    DIRECTION OUTPUT ;
    USE SIGNAL ;
    PORT
      LAYER M5 ;
        RECT  20.688 25.836 20.712 25.92 ;
    END
  END a_own_out[36]
  PIN a_own_out[37]
    DIRECTION OUTPUT ;
    USE SIGNAL ;
    PORT
      LAYER M3 ;
        RECT  21.096 25.882 21.114 25.92 ;
    END
    PORT
      LAYER M3 ;
        RECT  21.096 23.933 21.114 25.901 ;
    END
  END a_own_out[37]
  PIN a_own_out[38]
    DIRECTION OUTPUT ;
    USE SIGNAL ;
    PORT
      LAYER M5 ;
        RECT  21.552 25.836 21.576 25.92 ;
    END
  END a_own_out[38]
  PIN a_own_out[39]
    DIRECTION OUTPUT ;
    USE SIGNAL ;
    PORT
      LAYER M3 ;
        RECT  21.96 25.882 21.978 25.92 ;
    END
    PORT
      LAYER M3 ;
        RECT  21.96 25.133 21.978 25.901 ;
    END
  END a_own_out[39]
  PIN a_own_out[3]
    DIRECTION OUTPUT ;
    USE SIGNAL ;
    PORT
      LAYER M3 ;
        RECT  13.608 25.882 13.626 25.92 ;
    END
  END a_own_out[3]
  PIN a_own_out[40]
    DIRECTION OUTPUT ;
    USE SIGNAL ;
    PORT
      LAYER M5 ;
        RECT  22.416 25.836 22.44 25.92 ;
    END
  END a_own_out[40]
  PIN a_own_out[41]
    DIRECTION OUTPUT ;
    USE SIGNAL ;
    PORT
      LAYER M3 ;
        RECT  22.752 25.882 22.77 25.92 ;
    END
    PORT
      LAYER M3 ;
        RECT  22.752 25.805 22.77 25.901 ;
    END
  END a_own_out[41]
  PIN a_own_out[42]
    DIRECTION OUTPUT ;
    USE SIGNAL ;
    PORT
      LAYER M5 ;
        RECT  23.184 25.836 23.208 25.92 ;
    END
  END a_own_out[42]
  PIN a_own_out[43]
    DIRECTION OUTPUT ;
    USE SIGNAL ;
    PORT
      LAYER M3 ;
        RECT  23.616 25.882 23.634 25.92 ;
    END
    PORT
      LAYER M3 ;
        RECT  23.616 25.805 23.634 25.901 ;
    END
  END a_own_out[43]
  PIN a_own_out[44]
    DIRECTION OUTPUT ;
    USE SIGNAL ;
    PORT
      LAYER M5 ;
        RECT  24.048 25.836 24.072 25.92 ;
    END
  END a_own_out[44]
  PIN a_own_out[45]
    DIRECTION OUTPUT ;
    USE SIGNAL ;
    PORT
      LAYER M3 ;
        RECT  24.372 25.882 24.39 25.92 ;
    END
    PORT
      LAYER M3 ;
        RECT  24.372 25.805 24.39 25.901 ;
    END
  END a_own_out[45]
  PIN a_own_out[46]
    DIRECTION OUTPUT ;
    USE SIGNAL ;
    PORT
      LAYER M5 ;
        RECT  24.816 25.836 24.84 25.92 ;
    END
  END a_own_out[46]
  PIN a_own_out[47]
    DIRECTION OUTPUT ;
    USE SIGNAL ;
    PORT
      LAYER M3 ;
        RECT  25.236 25.882 25.254 25.92 ;
    END
    PORT
      LAYER M3 ;
        RECT  25.236 25.805 25.254 25.901 ;
    END
  END a_own_out[47]
  PIN a_own_out[48]
    DIRECTION OUTPUT ;
    USE SIGNAL ;
    PORT
      LAYER M5 ;
        RECT  25.68 25.836 25.704 25.92 ;
    END
  END a_own_out[48]
  PIN a_own_out[49]
    DIRECTION OUTPUT ;
    USE SIGNAL ;
    PORT
      LAYER M3 ;
        RECT  25.992 25.882 26.01 25.92 ;
    END
    PORT
      LAYER M3 ;
        RECT  25.992 25.889 26.01 25.901 ;
    END
  END a_own_out[49]
  PIN a_own_out[4]
    DIRECTION OUTPUT ;
    USE SIGNAL ;
    PORT
      LAYER M5 ;
        RECT  13.872 25.836 13.896 25.92 ;
    END
  END a_own_out[4]
  PIN a_own_out[50]
    DIRECTION OUTPUT ;
    USE SIGNAL ;
    PORT
      LAYER M5 ;
        RECT  26.448 25.836 26.472 25.92 ;
    END
  END a_own_out[50]
  PIN a_own_out[51]
    DIRECTION OUTPUT ;
    USE SIGNAL ;
    PORT
      LAYER M3 ;
        RECT  26.856 25.882 26.874 25.92 ;
    END
    PORT
      LAYER M3 ;
        RECT  26.856 25.889 26.874 25.901 ;
    END
  END a_own_out[51]
  PIN a_own_out[52]
    DIRECTION OUTPUT ;
    USE SIGNAL ;
    PORT
      LAYER M5 ;
        RECT  27.312 25.836 27.336 25.92 ;
    END
  END a_own_out[52]
  PIN a_own_out[53]
    DIRECTION OUTPUT ;
    USE SIGNAL ;
    PORT
      LAYER M3 ;
        RECT  27.648 25.882 27.666 25.92 ;
    END
    PORT
      LAYER M3 ;
        RECT  27.648 23.933 27.666 25.901 ;
    END
  END a_own_out[53]
  PIN a_own_out[54]
    DIRECTION OUTPUT ;
    USE SIGNAL ;
    PORT
      LAYER M5 ;
        RECT  28.08 25.836 28.104 25.92 ;
    END
  END a_own_out[54]
  PIN a_own_out[55]
    DIRECTION OUTPUT ;
    USE SIGNAL ;
    PORT
      LAYER M3 ;
        RECT  28.512 25.882 28.53 25.92 ;
    END
    PORT
      LAYER M3 ;
        RECT  28.512 23.933 28.53 25.901 ;
    END
  END a_own_out[55]
  PIN a_own_out[56]
    DIRECTION OUTPUT ;
    USE SIGNAL ;
    PORT
      LAYER M5 ;
        RECT  28.944 25.836 28.968 25.92 ;
    END
  END a_own_out[56]
  PIN a_own_out[57]
    DIRECTION OUTPUT ;
    USE SIGNAL ;
    PORT
      LAYER M3 ;
        RECT  29.376 25.882 29.394 25.92 ;
    END
    PORT
      LAYER M3 ;
        RECT  29.376 25.805 29.394 25.901 ;
    END
  END a_own_out[57]
  PIN a_own_out[58]
    DIRECTION OUTPUT ;
    USE SIGNAL ;
    PORT
      LAYER M5 ;
        RECT  29.712 25.836 29.736 25.92 ;
    END
  END a_own_out[58]
  PIN a_own_out[59]
    DIRECTION OUTPUT ;
    USE SIGNAL ;
    PORT
      LAYER M3 ;
        RECT  30.132 25.882 30.15 25.92 ;
    END
    PORT
      LAYER M3 ;
        RECT  30.132 25.805 30.15 25.901 ;
    END
  END a_own_out[59]
  PIN a_own_out[5]
    DIRECTION OUTPUT ;
    USE SIGNAL ;
    PORT
      LAYER M3 ;
        RECT  14.004 25.882 14.022 25.92 ;
    END
  END a_own_out[5]
  PIN a_own_out[60]
    DIRECTION OUTPUT ;
    USE SIGNAL ;
    PORT
      LAYER M5 ;
        RECT  30.576 25.836 30.6 25.92 ;
    END
  END a_own_out[60]
  PIN a_own_out[61]
    DIRECTION OUTPUT ;
    USE SIGNAL ;
    PORT
      LAYER M3 ;
        RECT  30.996 25.882 31.014 25.92 ;
    END
    PORT
      LAYER M3 ;
        RECT  30.996 24.509 31.014 25.901 ;
    END
  END a_own_out[61]
  PIN a_own_out[62]
    DIRECTION OUTPUT ;
    USE SIGNAL ;
    PORT
      LAYER M5 ;
        RECT  31.344 25.836 31.368 25.92 ;
    END
  END a_own_out[62]
  PIN a_own_out[63]
    DIRECTION OUTPUT ;
    USE SIGNAL ;
    PORT
      LAYER M3 ;
        RECT  31.752 25.882 31.77 25.92 ;
    END
    PORT
      LAYER M3 ;
        RECT  31.752 25.805 31.77 25.901 ;
    END
  END a_own_out[63]
  PIN a_own_out[64]
    DIRECTION OUTPUT ;
    USE SIGNAL ;
    PORT
      LAYER M5 ;
        RECT  32.208 25.836 32.232 25.92 ;
    END
  END a_own_out[64]
  PIN a_own_out[65]
    DIRECTION OUTPUT ;
    USE SIGNAL ;
    PORT
      LAYER M3 ;
        RECT  32.616 25.882 32.634 25.92 ;
    END
    PORT
      LAYER M3 ;
        RECT  32.616 25.805 32.634 25.901 ;
    END
  END a_own_out[65]
  PIN a_own_out[66]
    DIRECTION OUTPUT ;
    USE SIGNAL ;
    PORT
      LAYER M5 ;
        RECT  32.976 25.836 33 25.92 ;
    END
  END a_own_out[66]
  PIN a_own_out[67]
    DIRECTION OUTPUT ;
    USE SIGNAL ;
    PORT
      LAYER M3 ;
        RECT  33.408 25.882 33.426 25.92 ;
    END
    PORT
      LAYER M3 ;
        RECT  33.408 25.805 33.426 25.901 ;
    END
  END a_own_out[67]
  PIN a_own_out[68]
    DIRECTION OUTPUT ;
    USE SIGNAL ;
    PORT
      LAYER M5 ;
        RECT  33.84 25.836 33.864 25.92 ;
    END
  END a_own_out[68]
  PIN a_own_out[69]
    DIRECTION OUTPUT ;
    USE SIGNAL ;
    PORT
      LAYER M3 ;
        RECT  34.272 25.882 34.29 25.92 ;
    END
    PORT
      LAYER M3 ;
        RECT  34.272 25.805 34.29 25.901 ;
    END
  END a_own_out[69]
  PIN a_own_out[6]
    DIRECTION OUTPUT ;
    USE SIGNAL ;
    PORT
      LAYER M5 ;
        RECT  14.256 25.836 14.28 25.92 ;
    END
  END a_own_out[6]
  PIN a_own_out[70]
    DIRECTION OUTPUT ;
    USE SIGNAL ;
    PORT
      LAYER M5 ;
        RECT  34.608 25.836 34.632 25.92 ;
    END
  END a_own_out[70]
  PIN a_own_out[71]
    DIRECTION OUTPUT ;
    USE SIGNAL ;
    PORT
      LAYER M3 ;
        RECT  35.028 25.882 35.046 25.92 ;
    END
    PORT
      LAYER M3 ;
        RECT  35.028 25.889 35.046 25.901 ;
    END
  END a_own_out[71]
  PIN a_own_out[72]
    DIRECTION OUTPUT ;
    USE SIGNAL ;
    PORT
      LAYER M5 ;
        RECT  35.472 25.836 35.496 25.92 ;
    END
  END a_own_out[72]
  PIN a_own_out[73]
    DIRECTION OUTPUT ;
    USE SIGNAL ;
    PORT
      LAYER M3 ;
        RECT  35.892 25.882 35.91 25.92 ;
    END
    PORT
      LAYER M3 ;
        RECT  35.892 25.889 35.91 25.901 ;
    END
  END a_own_out[73]
  PIN a_own_out[74]
    DIRECTION OUTPUT ;
    USE SIGNAL ;
    PORT
      LAYER M5 ;
        RECT  36.336 25.836 36.36 25.92 ;
    END
  END a_own_out[74]
  PIN a_own_out[75]
    DIRECTION OUTPUT ;
    USE SIGNAL ;
    PORT
      LAYER M3 ;
        RECT  36.648 25.882 36.666 25.92 ;
    END
    PORT
      LAYER M3 ;
        RECT  36.648 23.933 36.666 25.901 ;
    END
  END a_own_out[75]
  PIN a_own_out[76]
    DIRECTION OUTPUT ;
    USE SIGNAL ;
    PORT
      LAYER M5 ;
        RECT  37.104 25.836 37.128 25.92 ;
    END
  END a_own_out[76]
  PIN a_own_out[77]
    DIRECTION OUTPUT ;
    USE SIGNAL ;
    PORT
      LAYER M3 ;
        RECT  37.512 25.882 37.53 25.92 ;
    END
    PORT
      LAYER M3 ;
        RECT  37.512 25.805 37.53 25.901 ;
    END
  END a_own_out[77]
  PIN a_own_out[78]
    DIRECTION OUTPUT ;
    USE SIGNAL ;
    PORT
      LAYER M5 ;
        RECT  37.968 25.836 37.992 25.92 ;
    END
  END a_own_out[78]
  PIN a_own_out[79]
    DIRECTION OUTPUT ;
    USE SIGNAL ;
    PORT
      LAYER M3 ;
        RECT  38.304 25.882 38.322 25.92 ;
    END
    PORT
      LAYER M3 ;
        RECT  38.304 25.861 38.394 25.889 ;
    END
    PORT
      LAYER M3 ;
        RECT  38.304 25.889 38.322 25.901 ;
    END
  END a_own_out[79]
  PIN a_own_out[7]
    DIRECTION OUTPUT ;
    USE SIGNAL ;
    PORT
      LAYER M3 ;
        RECT  14.4 25.882 14.418 25.92 ;
    END
  END a_own_out[7]
  PIN a_own_out[80]
    DIRECTION OUTPUT ;
    USE SIGNAL ;
    PORT
      LAYER M5 ;
        RECT  38.736 25.836 38.76 25.92 ;
    END
  END a_own_out[80]
  PIN a_own_out[81]
    DIRECTION OUTPUT ;
    USE SIGNAL ;
    PORT
      LAYER M3 ;
        RECT  39.168 25.882 39.186 25.92 ;
    END
    PORT
      LAYER M3 ;
        RECT  39.168 23.933 39.186 25.901 ;
    END
  END a_own_out[81]
  PIN a_own_out[82]
    DIRECTION OUTPUT ;
    USE SIGNAL ;
    PORT
      LAYER M5 ;
        RECT  39.6 25.836 39.624 25.92 ;
    END
  END a_own_out[82]
  PIN a_own_out[83]
    DIRECTION OUTPUT ;
    USE SIGNAL ;
    PORT
      LAYER M3 ;
        RECT  39.924 25.882 39.942 25.92 ;
    END
    PORT
      LAYER M3 ;
        RECT  39.924 23.933 39.942 25.901 ;
    END
  END a_own_out[83]
  PIN a_own_out[84]
    DIRECTION OUTPUT ;
    USE SIGNAL ;
    PORT
      LAYER M5 ;
        RECT  40.368 25.836 40.392 25.92 ;
    END
  END a_own_out[84]
  PIN a_own_out[85]
    DIRECTION OUTPUT ;
    USE SIGNAL ;
    PORT
      LAYER M3 ;
        RECT  40.788 25.882 40.806 25.92 ;
    END
    PORT
      LAYER M3 ;
        RECT  40.788 25.805 40.806 25.901 ;
    END
  END a_own_out[85]
  PIN a_own_out[86]
    DIRECTION OUTPUT ;
    USE SIGNAL ;
    PORT
      LAYER M5 ;
        RECT  41.232 25.836 41.256 25.92 ;
    END
  END a_own_out[86]
  PIN a_own_out[87]
    DIRECTION OUTPUT ;
    USE SIGNAL ;
    PORT
      LAYER M3 ;
        RECT  41.544 25.882 41.562 25.92 ;
    END
    PORT
      LAYER M3 ;
        RECT  41.544 25.805 41.562 25.901 ;
    END
  END a_own_out[87]
  PIN a_own_out[88]
    DIRECTION OUTPUT ;
    USE SIGNAL ;
    PORT
      LAYER M5 ;
        RECT  42 25.836 42.024 25.92 ;
    END
  END a_own_out[88]
  PIN a_own_out[89]
    DIRECTION OUTPUT ;
    USE SIGNAL ;
    PORT
      LAYER M3 ;
        RECT  42.408 25.882 42.426 25.92 ;
    END
    PORT
      LAYER M3 ;
        RECT  42.408 23.933 42.426 25.901 ;
    END
  END a_own_out[89]
  PIN a_own_out[8]
    DIRECTION OUTPUT ;
    USE SIGNAL ;
    PORT
      LAYER M5 ;
        RECT  14.64 25.836 14.664 25.92 ;
    END
  END a_own_out[8]
  PIN a_own_out[90]
    DIRECTION OUTPUT ;
    USE SIGNAL ;
    PORT
      LAYER M5 ;
        RECT  42.864 25.836 42.888 25.92 ;
    END
  END a_own_out[90]
  PIN a_own_out[91]
    DIRECTION OUTPUT ;
    USE SIGNAL ;
    PORT
      LAYER M3 ;
        RECT  43.272 25.882 43.29 25.92 ;
    END
    PORT
      LAYER M3 ;
        RECT  43.272 25.805 43.29 25.901 ;
    END
  END a_own_out[91]
  PIN a_own_out[92]
    DIRECTION OUTPUT ;
    USE SIGNAL ;
    PORT
      LAYER M5 ;
        RECT  43.632 25.836 43.656 25.92 ;
    END
  END a_own_out[92]
  PIN a_own_out[93]
    DIRECTION OUTPUT ;
    USE SIGNAL ;
    PORT
      LAYER M3 ;
        RECT  44.064 25.882 44.082 25.92 ;
    END
    PORT
      LAYER M3 ;
        RECT  44.064 25.889 44.082 25.901 ;
    END
  END a_own_out[93]
  PIN a_own_out[94]
    DIRECTION OUTPUT ;
    USE SIGNAL ;
    PORT
      LAYER M5 ;
        RECT  44.496 25.836 44.52 25.92 ;
    END
  END a_own_out[94]
  PIN a_own_out[95]
    DIRECTION OUTPUT ;
    USE SIGNAL ;
    PORT
      LAYER M3 ;
        RECT  44.928 25.882 44.946 25.92 ;
    END
    PORT
      LAYER M3 ;
        RECT  44.928 25.889 44.946 25.901 ;
    END
  END a_own_out[95]
  PIN a_own_out[96]
    DIRECTION OUTPUT ;
    USE SIGNAL ;
    PORT
      LAYER M5 ;
        RECT  45.264 25.836 45.288 25.92 ;
    END
  END a_own_out[96]
  PIN a_own_out[97]
    DIRECTION OUTPUT ;
    USE SIGNAL ;
    PORT
      LAYER M3 ;
        RECT  45.684 25.882 45.702 25.92 ;
    END
    PORT
      LAYER M3 ;
        RECT  45.684 23.933 45.702 25.901 ;
    END
  END a_own_out[97]
  PIN a_own_out[98]
    DIRECTION OUTPUT ;
    USE SIGNAL ;
    PORT
      LAYER M5 ;
        RECT  46.128 25.836 46.152 25.92 ;
    END
  END a_own_out[98]
  PIN a_own_out[99]
    DIRECTION OUTPUT ;
    USE SIGNAL ;
    PORT
      LAYER M3 ;
        RECT  46.548 25.882 46.566 25.92 ;
    END
    PORT
      LAYER M3 ;
        RECT  46.548 25.085 46.566 25.901 ;
    END
  END a_own_out[99]
  PIN a_own_out[9]
    DIRECTION OUTPUT ;
    USE SIGNAL ;
    PORT
      LAYER M3 ;
        RECT  14.868 25.882 14.886 25.92 ;
    END
  END a_own_out[9]
  PIN b_own[0]
    DIRECTION INPUT ;
    USE SIGNAL ;
    PORT
      LAYER M5 ;
        RECT  85.392 0 85.416 0.084 ;
    END
  END b_own[0]
  PIN b_own[100]
    DIRECTION INPUT ;
    USE SIGNAL ;
    PORT
      LAYER M5 ;
        RECT  105.936 0 105.96 0.084 ;
    END
  END b_own[100]
  PIN b_own[101]
    DIRECTION INPUT ;
    USE SIGNAL ;
    PORT
      LAYER M3 ;
        RECT  106.056 0 106.074 0.038 ;
    END
  END b_own[101]
  PIN b_own[102]
    DIRECTION INPUT ;
    USE SIGNAL ;
    PORT
      LAYER M5 ;
        RECT  106.32 0 106.344 0.084 ;
    END
  END b_own[102]
  PIN b_own[103]
    DIRECTION INPUT ;
    USE SIGNAL ;
    PORT
      LAYER M3 ;
        RECT  106.56 0 106.578 0.038 ;
    END
  END b_own[103]
  PIN b_own[104]
    DIRECTION INPUT ;
    USE SIGNAL ;
    PORT
      LAYER M5 ;
        RECT  106.704 0 106.728 0.084 ;
    END
  END b_own[104]
  PIN b_own[105]
    DIRECTION INPUT ;
    USE SIGNAL ;
    PORT
      LAYER M3 ;
        RECT  106.92 0 106.938 0.038 ;
    END
  END b_own[105]
  PIN b_own[106]
    DIRECTION INPUT ;
    USE SIGNAL ;
    PORT
      LAYER M5 ;
        RECT  107.088 0 107.112 0.084 ;
    END
  END b_own[106]
  PIN b_own[107]
    DIRECTION INPUT ;
    USE SIGNAL ;
    PORT
      LAYER M3 ;
        RECT  107.316 0 107.334 0.038 ;
    END
  END b_own[107]
  PIN b_own[108]
    DIRECTION INPUT ;
    USE SIGNAL ;
    PORT
      LAYER M5 ;
        RECT  107.568 0 107.592 0.084 ;
    END
  END b_own[108]
  PIN b_own[109]
    DIRECTION INPUT ;
    USE SIGNAL ;
    PORT
      LAYER M3 ;
        RECT  107.712 0 107.73 0.038 ;
    END
  END b_own[109]
  PIN b_own[10]
    DIRECTION INPUT ;
    USE SIGNAL ;
    PORT
      LAYER M5 ;
        RECT  87.504 0 87.528 0.084 ;
    END
  END b_own[10]
  PIN b_own[110]
    DIRECTION INPUT ;
    USE SIGNAL ;
    PORT
      LAYER M5 ;
        RECT  107.952 0 107.976 0.084 ;
    END
  END b_own[110]
  PIN b_own[111]
    DIRECTION INPUT ;
    USE SIGNAL ;
    PORT
      LAYER M3 ;
        RECT  108.18 0 108.198 0.038 ;
    END
  END b_own[111]
  PIN b_own[112]
    DIRECTION INPUT ;
    USE SIGNAL ;
    PORT
      LAYER M5 ;
        RECT  108.336 0 108.36 0.084 ;
    END
  END b_own[112]
  PIN b_own[113]
    DIRECTION INPUT ;
    USE SIGNAL ;
    PORT
      LAYER M3 ;
        RECT  108.576 0 108.594 0.038 ;
    END
  END b_own[113]
  PIN b_own[114]
    DIRECTION INPUT ;
    USE SIGNAL ;
    PORT
      LAYER M5 ;
        RECT  108.72 0 108.744 0.084 ;
    END
  END b_own[114]
  PIN b_own[115]
    DIRECTION INPUT ;
    USE SIGNAL ;
    PORT
      LAYER M3 ;
        RECT  108.936 0 108.954 0.038 ;
    END
  END b_own[115]
  PIN b_own[116]
    DIRECTION INPUT ;
    USE SIGNAL ;
    PORT
      LAYER M5 ;
        RECT  109.2 0 109.224 0.084 ;
    END
  END b_own[116]
  PIN b_own[117]
    DIRECTION INPUT ;
    USE SIGNAL ;
    PORT
      LAYER M3 ;
        RECT  109.332 0 109.35 0.038 ;
    END
  END b_own[117]
  PIN b_own[118]
    DIRECTION INPUT ;
    USE SIGNAL ;
    PORT
      LAYER M5 ;
        RECT  109.584 0 109.608 0.084 ;
    END
  END b_own[118]
  PIN b_own[119]
    DIRECTION INPUT ;
    USE SIGNAL ;
    PORT
      LAYER M3 ;
        RECT  109.8 0 109.818 0.038 ;
    END
  END b_own[119]
  PIN b_own[11]
    DIRECTION INPUT ;
    USE SIGNAL ;
    PORT
      LAYER M3 ;
        RECT  87.624 0 87.642 0.038 ;
    END
  END b_own[11]
  PIN b_own[120]
    DIRECTION INPUT ;
    USE SIGNAL ;
    PORT
      LAYER M5 ;
        RECT  109.968 0 109.992 0.084 ;
    END
  END b_own[120]
  PIN b_own[121]
    DIRECTION INPUT ;
    USE SIGNAL ;
    PORT
      LAYER M3 ;
        RECT  110.196 0 110.214 0.038 ;
    END
  END b_own[121]
  PIN b_own[122]
    DIRECTION INPUT ;
    USE SIGNAL ;
    PORT
      LAYER M5 ;
        RECT  110.448 0 110.472 0.084 ;
    END
  END b_own[122]
  PIN b_own[123]
    DIRECTION INPUT ;
    USE SIGNAL ;
    PORT
      LAYER M3 ;
        RECT  110.592 0 110.61 0.038 ;
    END
  END b_own[123]
  PIN b_own[124]
    DIRECTION INPUT ;
    USE SIGNAL ;
    PORT
      LAYER M5 ;
        RECT  110.832 0 110.856 0.084 ;
    END
  END b_own[124]
  PIN b_own[125]
    DIRECTION INPUT ;
    USE SIGNAL ;
    PORT
      LAYER M3 ;
        RECT  110.952 0 110.97 0.038 ;
    END
  END b_own[125]
  PIN b_own[126]
    DIRECTION INPUT ;
    USE SIGNAL ;
    PORT
      LAYER M5 ;
        RECT  111.216 0 111.24 0.084 ;
    END
  END b_own[126]
  PIN b_own[127]
    DIRECTION INPUT ;
    USE SIGNAL ;
    PORT
      LAYER M3 ;
        RECT  111.456 0 111.474 0.038 ;
    END
  END b_own[127]
  PIN b_own[128]
    DIRECTION INPUT ;
    USE SIGNAL ;
    PORT
      LAYER M5 ;
        RECT  111.6 0 111.624 0.084 ;
    END
  END b_own[128]
  PIN b_own[129]
    DIRECTION INPUT ;
    USE SIGNAL ;
    PORT
      LAYER M3 ;
        RECT  111.816 0 111.834 0.038 ;
    END
  END b_own[129]
  PIN b_own[12]
    DIRECTION INPUT ;
    USE SIGNAL ;
    PORT
      LAYER M5 ;
        RECT  87.888 0 87.912 0.084 ;
    END
  END b_own[12]
  PIN b_own[130]
    DIRECTION INPUT ;
    USE SIGNAL ;
    PORT
      LAYER M5 ;
        RECT  112.08 0 112.104 0.084 ;
    END
  END b_own[130]
  PIN b_own[131]
    DIRECTION INPUT ;
    USE SIGNAL ;
    PORT
      LAYER M3 ;
        RECT  112.212 0 112.23 0.038 ;
    END
  END b_own[131]
  PIN b_own[132]
    DIRECTION INPUT ;
    USE SIGNAL ;
    PORT
      LAYER M5 ;
        RECT  112.464 0 112.488 0.084 ;
    END
  END b_own[132]
  PIN b_own[133]
    DIRECTION INPUT ;
    USE SIGNAL ;
    PORT
      LAYER M3 ;
        RECT  112.608 0 112.626 0.038 ;
    END
  END b_own[133]
  PIN b_own[134]
    DIRECTION INPUT ;
    USE SIGNAL ;
    PORT
      LAYER M5 ;
        RECT  112.848 0 112.872 0.084 ;
    END
  END b_own[134]
  PIN b_own[135]
    DIRECTION INPUT ;
    USE SIGNAL ;
    PORT
      LAYER M3 ;
        RECT  113.076 0 113.094 0.038 ;
    END
  END b_own[135]
  PIN b_own[136]
    DIRECTION INPUT ;
    USE SIGNAL ;
    PORT
      LAYER M5 ;
        RECT  113.232 0 113.256 0.084 ;
    END
  END b_own[136]
  PIN b_own[137]
    DIRECTION INPUT ;
    USE SIGNAL ;
    PORT
      LAYER M3 ;
        RECT  113.472 0 113.49 0.038 ;
    END
  END b_own[137]
  PIN b_own[138]
    DIRECTION INPUT ;
    USE SIGNAL ;
    PORT
      LAYER M5 ;
        RECT  113.712 0 113.736 0.084 ;
    END
  END b_own[138]
  PIN b_own[139]
    DIRECTION INPUT ;
    USE SIGNAL ;
    PORT
      LAYER M3 ;
        RECT  113.832 0 113.85 0.038 ;
    END
  END b_own[139]
  PIN b_own[13]
    DIRECTION INPUT ;
    USE SIGNAL ;
    PORT
      LAYER M3 ;
        RECT  88.128 0 88.146 0.038 ;
    END
  END b_own[13]
  PIN b_own[140]
    DIRECTION INPUT ;
    USE SIGNAL ;
    PORT
      LAYER M5 ;
        RECT  114.096 0 114.12 0.084 ;
    END
  END b_own[140]
  PIN b_own[141]
    DIRECTION INPUT ;
    USE SIGNAL ;
    PORT
      LAYER M3 ;
        RECT  114.336 0 114.354 0.038 ;
    END
  END b_own[141]
  PIN b_own[142]
    DIRECTION INPUT ;
    USE SIGNAL ;
    PORT
      LAYER M5 ;
        RECT  114.48 0 114.504 0.084 ;
    END
  END b_own[142]
  PIN b_own[143]
    DIRECTION INPUT ;
    USE SIGNAL ;
    PORT
      LAYER M3 ;
        RECT  114.696 0 114.714 0.038 ;
    END
  END b_own[143]
  PIN b_own[144]
    DIRECTION INPUT ;
    USE SIGNAL ;
    PORT
      LAYER M5 ;
        RECT  114.864 0 114.888 0.084 ;
    END
  END b_own[144]
  PIN b_own[145]
    DIRECTION INPUT ;
    USE SIGNAL ;
    PORT
      LAYER M3 ;
        RECT  115.092 0 115.11 0.038 ;
    END
  END b_own[145]
  PIN b_own[146]
    DIRECTION INPUT ;
    USE SIGNAL ;
    PORT
      LAYER M5 ;
        RECT  115.344 0 115.368 0.084 ;
    END
  END b_own[146]
  PIN b_own[147]
    DIRECTION INPUT ;
    USE SIGNAL ;
    PORT
      LAYER M3 ;
        RECT  115.488 0 115.506 0.038 ;
    END
  END b_own[147]
  PIN b_own[148]
    DIRECTION INPUT ;
    USE SIGNAL ;
    PORT
      LAYER M5 ;
        RECT  115.728 0 115.752 0.084 ;
    END
  END b_own[148]
  PIN b_own[149]
    DIRECTION INPUT ;
    USE SIGNAL ;
    PORT
      LAYER M3 ;
        RECT  115.956 0 115.974 0.038 ;
    END
  END b_own[149]
  PIN b_own[14]
    DIRECTION INPUT ;
    USE SIGNAL ;
    PORT
      LAYER M5 ;
        RECT  88.272 0 88.296 0.084 ;
    END
  END b_own[14]
  PIN b_own[150]
    DIRECTION INPUT ;
    USE SIGNAL ;
    PORT
      LAYER M5 ;
        RECT  116.112 0 116.136 0.084 ;
    END
  END b_own[150]
  PIN b_own[151]
    DIRECTION INPUT ;
    USE SIGNAL ;
    PORT
      LAYER M3 ;
        RECT  116.352 0 116.37 0.038 ;
    END
  END b_own[151]
  PIN b_own[152]
    DIRECTION INPUT ;
    USE SIGNAL ;
    PORT
      LAYER M5 ;
        RECT  116.592 0 116.616 0.084 ;
    END
  END b_own[152]
  PIN b_own[153]
    DIRECTION INPUT ;
    USE SIGNAL ;
    PORT
      LAYER M3 ;
        RECT  116.712 0 116.73 0.038 ;
    END
  END b_own[153]
  PIN b_own[154]
    DIRECTION INPUT ;
    USE SIGNAL ;
    PORT
      LAYER M5 ;
        RECT  116.976 0 117 0.084 ;
    END
  END b_own[154]
  PIN b_own[155]
    DIRECTION INPUT ;
    USE SIGNAL ;
    PORT
      LAYER M3 ;
        RECT  117.108 0 117.126 0.038 ;
    END
  END b_own[155]
  PIN b_own[156]
    DIRECTION INPUT ;
    USE SIGNAL ;
    PORT
      LAYER M5 ;
        RECT  117.36 0 117.384 0.084 ;
    END
  END b_own[156]
  PIN b_own[157]
    DIRECTION INPUT ;
    USE SIGNAL ;
    PORT
      LAYER M3 ;
        RECT  117.576 0 117.594 0.038 ;
    END
  END b_own[157]
  PIN b_own[158]
    DIRECTION INPUT ;
    USE SIGNAL ;
    PORT
      LAYER M5 ;
        RECT  117.744 0 117.768 0.084 ;
    END
  END b_own[158]
  PIN b_own[159]
    DIRECTION INPUT ;
    USE SIGNAL ;
    PORT
      LAYER M3 ;
        RECT  117.972 0 117.99 0.038 ;
    END
  END b_own[159]
  PIN b_own[15]
    DIRECTION INPUT ;
    USE SIGNAL ;
    PORT
      LAYER M3 ;
        RECT  88.488 0 88.506 0.038 ;
    END
  END b_own[15]
  PIN b_own[160]
    DIRECTION INPUT ;
    USE SIGNAL ;
    PORT
      LAYER M5 ;
        RECT  118.224 0 118.248 0.084 ;
    END
  END b_own[160]
  PIN b_own[161]
    DIRECTION INPUT ;
    USE SIGNAL ;
    PORT
      LAYER M3 ;
        RECT  118.368 0 118.386 0.038 ;
    END
  END b_own[161]
  PIN b_own[162]
    DIRECTION INPUT ;
    USE SIGNAL ;
    PORT
      LAYER M5 ;
        RECT  118.608 0 118.632 0.084 ;
    END
  END b_own[162]
  PIN b_own[163]
    DIRECTION INPUT ;
    USE SIGNAL ;
    PORT
      LAYER M3 ;
        RECT  118.728 0 118.746 0.038 ;
    END
  END b_own[163]
  PIN b_own[164]
    DIRECTION INPUT ;
    USE SIGNAL ;
    PORT
      LAYER M5 ;
        RECT  118.992 0 119.016 0.084 ;
    END
  END b_own[164]
  PIN b_own[165]
    DIRECTION INPUT ;
    USE SIGNAL ;
    PORT
      LAYER M3 ;
        RECT  119.232 0 119.25 0.038 ;
    END
  END b_own[165]
  PIN b_own[166]
    DIRECTION INPUT ;
    USE SIGNAL ;
    PORT
      LAYER M5 ;
        RECT  119.376 0 119.4 0.084 ;
    END
  END b_own[166]
  PIN b_own[167]
    DIRECTION INPUT ;
    USE SIGNAL ;
    PORT
      LAYER M3 ;
        RECT  119.592 0 119.61 0.038 ;
    END
  END b_own[167]
  PIN b_own[168]
    DIRECTION INPUT ;
    USE SIGNAL ;
    PORT
      LAYER M5 ;
        RECT  119.856 0 119.88 0.084 ;
    END
  END b_own[168]
  PIN b_own[169]
    DIRECTION INPUT ;
    USE SIGNAL ;
    PORT
      LAYER M3 ;
        RECT  119.988 0 120.006 0.038 ;
    END
  END b_own[169]
  PIN b_own[16]
    DIRECTION INPUT ;
    USE SIGNAL ;
    PORT
      LAYER M5 ;
        RECT  88.656 0 88.68 0.084 ;
    END
  END b_own[16]
  PIN b_own[170]
    DIRECTION INPUT ;
    USE SIGNAL ;
    PORT
      LAYER M5 ;
        RECT  120.24 0 120.264 0.084 ;
    END
  END b_own[170]
  PIN b_own[171]
    DIRECTION INPUT ;
    USE SIGNAL ;
    PORT
      LAYER M3 ;
        RECT  120.456 0 120.474 0.038 ;
    END
  END b_own[171]
  PIN b_own[172]
    DIRECTION INPUT ;
    USE SIGNAL ;
    PORT
      LAYER M5 ;
        RECT  120.624 0 120.648 0.084 ;
    END
  END b_own[172]
  PIN b_own[173]
    DIRECTION INPUT ;
    USE SIGNAL ;
    PORT
      LAYER M3 ;
        RECT  120.852 0 120.87 0.038 ;
    END
  END b_own[173]
  PIN b_own[174]
    DIRECTION INPUT ;
    USE SIGNAL ;
    PORT
      LAYER M5 ;
        RECT  121.008 0 121.032 0.084 ;
    END
  END b_own[174]
  PIN b_own[175]
    DIRECTION INPUT ;
    USE SIGNAL ;
    PORT
      LAYER M3 ;
        RECT  121.248 0 121.266 0.038 ;
    END
  END b_own[175]
  PIN b_own[176]
    DIRECTION INPUT ;
    USE SIGNAL ;
    PORT
      LAYER M5 ;
        RECT  121.488 0 121.512 0.084 ;
    END
  END b_own[176]
  PIN b_own[177]
    DIRECTION INPUT ;
    USE SIGNAL ;
    PORT
      LAYER M3 ;
        RECT  121.608 0 121.626 0.038 ;
    END
  END b_own[177]
  PIN b_own[178]
    DIRECTION INPUT ;
    USE SIGNAL ;
    PORT
      LAYER M5 ;
        RECT  121.872 0 121.896 0.084 ;
    END
  END b_own[178]
  PIN b_own[179]
    DIRECTION INPUT ;
    USE SIGNAL ;
    PORT
      LAYER M3 ;
        RECT  122.112 0 122.13 0.038 ;
    END
  END b_own[179]
  PIN b_own[17]
    DIRECTION INPUT ;
    USE SIGNAL ;
    PORT
      LAYER M3 ;
        RECT  88.884 0 88.902 0.038 ;
    END
  END b_own[17]
  PIN b_own[180]
    DIRECTION INPUT ;
    USE SIGNAL ;
    PORT
      LAYER M5 ;
        RECT  122.256 0 122.28 0.084 ;
    END
  END b_own[180]
  PIN b_own[181]
    DIRECTION INPUT ;
    USE SIGNAL ;
    PORT
      LAYER M3 ;
        RECT  122.472 0 122.49 0.038 ;
    END
  END b_own[181]
  PIN b_own[182]
    DIRECTION INPUT ;
    USE SIGNAL ;
    PORT
      LAYER M5 ;
        RECT  122.64 0 122.664 0.084 ;
    END
  END b_own[182]
  PIN b_own[183]
    DIRECTION INPUT ;
    USE SIGNAL ;
    PORT
      LAYER M3 ;
        RECT  122.868 0 122.886 0.038 ;
    END
  END b_own[183]
  PIN b_own[184]
    DIRECTION INPUT ;
    USE SIGNAL ;
    PORT
      LAYER M5 ;
        RECT  123.12 0 123.144 0.084 ;
    END
  END b_own[184]
  PIN b_own[185]
    DIRECTION INPUT ;
    USE SIGNAL ;
    PORT
      LAYER M3 ;
        RECT  123.264 0 123.282 0.038 ;
    END
  END b_own[185]
  PIN b_own[186]
    DIRECTION INPUT ;
    USE SIGNAL ;
    PORT
      LAYER M5 ;
        RECT  123.504 0 123.528 0.084 ;
    END
  END b_own[186]
  PIN b_own[187]
    DIRECTION INPUT ;
    USE SIGNAL ;
    PORT
      LAYER M3 ;
        RECT  123.732 0 123.75 0.038 ;
    END
  END b_own[187]
  PIN b_own[188]
    DIRECTION INPUT ;
    USE SIGNAL ;
    PORT
      LAYER M5 ;
        RECT  123.888 0 123.912 0.084 ;
    END
  END b_own[188]
  PIN b_own[189]
    DIRECTION INPUT ;
    USE SIGNAL ;
    PORT
      LAYER M3 ;
        RECT  124.128 0 124.146 0.038 ;
    END
  END b_own[189]
  PIN b_own[18]
    DIRECTION INPUT ;
    USE SIGNAL ;
    PORT
      LAYER M5 ;
        RECT  89.136 0 89.16 0.084 ;
    END
  END b_own[18]
  PIN b_own[190]
    DIRECTION INPUT ;
    USE SIGNAL ;
    PORT
      LAYER M5 ;
        RECT  124.368 0 124.392 0.084 ;
    END
  END b_own[190]
  PIN b_own[191]
    DIRECTION INPUT ;
    USE SIGNAL ;
    PORT
      LAYER M3 ;
        RECT  124.488 0 124.506 0.038 ;
    END
  END b_own[191]
  PIN b_own[192]
    DIRECTION INPUT ;
    USE SIGNAL ;
    PORT
      LAYER M5 ;
        RECT  124.752 0 124.776 0.084 ;
    END
  END b_own[192]
  PIN b_own[193]
    DIRECTION INPUT ;
    USE SIGNAL ;
    PORT
      LAYER M3 ;
        RECT  124.884 0 124.902 0.038 ;
    END
  END b_own[193]
  PIN b_own[194]
    DIRECTION INPUT ;
    USE SIGNAL ;
    PORT
      LAYER M5 ;
        RECT  125.136 0 125.16 0.084 ;
    END
  END b_own[194]
  PIN b_own[195]
    DIRECTION INPUT ;
    USE SIGNAL ;
    PORT
      LAYER M3 ;
        RECT  125.352 0 125.37 0.038 ;
    END
  END b_own[195]
  PIN b_own[196]
    DIRECTION INPUT ;
    USE SIGNAL ;
    PORT
      LAYER M5 ;
        RECT  125.52 0 125.544 0.084 ;
    END
  END b_own[196]
  PIN b_own[197]
    DIRECTION INPUT ;
    USE SIGNAL ;
    PORT
      LAYER M3 ;
        RECT  125.748 0 125.766 0.038 ;
    END
  END b_own[197]
  PIN b_own[198]
    DIRECTION INPUT ;
    USE SIGNAL ;
    PORT
      LAYER M5 ;
        RECT  126 0 126.024 0.084 ;
    END
  END b_own[198]
  PIN b_own[199]
    DIRECTION INPUT ;
    USE SIGNAL ;
    PORT
      LAYER M3 ;
        RECT  126.144 0 126.162 0.038 ;
    END
  END b_own[199]
  PIN b_own[19]
    DIRECTION INPUT ;
    USE SIGNAL ;
    PORT
      LAYER M3 ;
        RECT  89.28 0 89.298 0.038 ;
    END
  END b_own[19]
  PIN b_own[1]
    DIRECTION INPUT ;
    USE SIGNAL ;
    PORT
      LAYER M3 ;
        RECT  85.608 0 85.626 0.038 ;
    END
  END b_own[1]
  PIN b_own[200]
    DIRECTION INPUT ;
    USE SIGNAL ;
    PORT
      LAYER M5 ;
        RECT  126.384 0 126.408 0.084 ;
    END
  END b_own[200]
  PIN b_own[201]
    DIRECTION INPUT ;
    USE SIGNAL ;
    PORT
      LAYER M3 ;
        RECT  126.612 0 126.63 0.038 ;
    END
  END b_own[201]
  PIN b_own[202]
    DIRECTION INPUT ;
    USE SIGNAL ;
    PORT
      LAYER M5 ;
        RECT  126.768 0 126.792 0.084 ;
    END
  END b_own[202]
  PIN b_own[203]
    DIRECTION INPUT ;
    USE SIGNAL ;
    PORT
      LAYER M3 ;
        RECT  127.008 0 127.026 0.038 ;
    END
  END b_own[203]
  PIN b_own[204]
    DIRECTION INPUT ;
    USE SIGNAL ;
    PORT
      LAYER M5 ;
        RECT  127.152 0 127.176 0.084 ;
    END
  END b_own[204]
  PIN b_own[205]
    DIRECTION INPUT ;
    USE SIGNAL ;
    PORT
      LAYER M3 ;
        RECT  127.368 0 127.386 0.038 ;
    END
  END b_own[205]
  PIN b_own[206]
    DIRECTION INPUT ;
    USE SIGNAL ;
    PORT
      LAYER M5 ;
        RECT  127.632 0 127.656 0.084 ;
    END
  END b_own[206]
  PIN b_own[207]
    DIRECTION INPUT ;
    USE SIGNAL ;
    PORT
      LAYER M3 ;
        RECT  127.764 0 127.782 0.038 ;
    END
  END b_own[207]
  PIN b_own[208]
    DIRECTION INPUT ;
    USE SIGNAL ;
    PORT
      LAYER M5 ;
        RECT  128.016 0 128.04 0.084 ;
    END
  END b_own[208]
  PIN b_own[209]
    DIRECTION INPUT ;
    USE SIGNAL ;
    PORT
      LAYER M3 ;
        RECT  128.232 0 128.25 0.038 ;
    END
  END b_own[209]
  PIN b_own[20]
    DIRECTION INPUT ;
    USE SIGNAL ;
    PORT
      LAYER M5 ;
        RECT  89.52 0 89.544 0.084 ;
    END
  END b_own[20]
  PIN b_own[210]
    DIRECTION INPUT ;
    USE SIGNAL ;
    PORT
      LAYER M5 ;
        RECT  128.4 0 128.424 0.084 ;
    END
  END b_own[210]
  PIN b_own[211]
    DIRECTION INPUT ;
    USE SIGNAL ;
    PORT
      LAYER M3 ;
        RECT  128.628 0 128.646 0.038 ;
    END
  END b_own[211]
  PIN b_own[212]
    DIRECTION INPUT ;
    USE SIGNAL ;
    PORT
      LAYER M5 ;
        RECT  128.784 0 128.808 0.084 ;
    END
  END b_own[212]
  PIN b_own[213]
    DIRECTION INPUT ;
    USE SIGNAL ;
    PORT
      LAYER M3 ;
        RECT  129.024 0 129.042 0.038 ;
    END
  END b_own[213]
  PIN b_own[214]
    DIRECTION INPUT ;
    USE SIGNAL ;
    PORT
      LAYER M5 ;
        RECT  129.264 0 129.288 0.084 ;
    END
  END b_own[214]
  PIN b_own[215]
    DIRECTION INPUT ;
    USE SIGNAL ;
    PORT
      LAYER M3 ;
        RECT  129.384 0 129.402 0.038 ;
    END
  END b_own[215]
  PIN b_own[216]
    DIRECTION INPUT ;
    USE SIGNAL ;
    PORT
      LAYER M5 ;
        RECT  129.648 0 129.672 0.084 ;
    END
  END b_own[216]
  PIN b_own[217]
    DIRECTION INPUT ;
    USE SIGNAL ;
    PORT
      LAYER M3 ;
        RECT  129.888 0 129.906 0.038 ;
    END
  END b_own[217]
  PIN b_own[218]
    DIRECTION INPUT ;
    USE SIGNAL ;
    PORT
      LAYER M5 ;
        RECT  130.032 0 130.056 0.084 ;
    END
  END b_own[218]
  PIN b_own[219]
    DIRECTION INPUT ;
    USE SIGNAL ;
    PORT
      LAYER M3 ;
        RECT  130.248 0 130.266 0.038 ;
    END
  END b_own[219]
  PIN b_own[21]
    DIRECTION INPUT ;
    USE SIGNAL ;
    PORT
      LAYER M3 ;
        RECT  89.748 0 89.766 0.038 ;
    END
  END b_own[21]
  PIN b_own[220]
    DIRECTION INPUT ;
    USE SIGNAL ;
    PORT
      LAYER M5 ;
        RECT  130.512 0 130.536 0.084 ;
    END
  END b_own[220]
  PIN b_own[221]
    DIRECTION INPUT ;
    USE SIGNAL ;
    PORT
      LAYER M3 ;
        RECT  130.644 0 130.662 0.038 ;
    END
  END b_own[221]
  PIN b_own[222]
    DIRECTION INPUT ;
    USE SIGNAL ;
    PORT
      LAYER M5 ;
        RECT  130.896 0 130.92 0.084 ;
    END
  END b_own[222]
  PIN b_own[223]
    DIRECTION INPUT ;
    USE SIGNAL ;
    PORT
      LAYER M3 ;
        RECT  131.112 0 131.13 0.038 ;
    END
  END b_own[223]
  PIN b_own[224]
    DIRECTION INPUT ;
    USE SIGNAL ;
    PORT
      LAYER M5 ;
        RECT  131.472 0 131.496 0.084 ;
    END
  END b_own[224]
  PIN b_own[225]
    DIRECTION INPUT ;
    USE SIGNAL ;
    PORT
      LAYER M3 ;
        RECT  131.904 0 131.922 0.038 ;
    END
  END b_own[225]
  PIN b_own[226]
    DIRECTION INPUT ;
    USE SIGNAL ;
    PORT
      LAYER M5 ;
        RECT  132.24 0 132.264 0.084 ;
    END
  END b_own[226]
  PIN b_own[227]
    DIRECTION INPUT ;
    USE SIGNAL ;
    PORT
      LAYER M3 ;
        RECT  132.552 0 132.57 0.038 ;
    END
  END b_own[227]
  PIN b_own[228]
    DIRECTION INPUT ;
    USE SIGNAL ;
    PORT
      LAYER M5 ;
        RECT  133.008 0 133.032 0.084 ;
    END
  END b_own[228]
  PIN b_own[229]
    DIRECTION INPUT ;
    USE SIGNAL ;
    PORT
      LAYER M3 ;
        RECT  133.344 0 133.362 0.038 ;
    END
    PORT
      LAYER M3 ;
        RECT  133.344 0.012 133.362 1.723 ;
    END
  END b_own[229]
  PIN b_own[22]
    DIRECTION INPUT ;
    USE SIGNAL ;
    PORT
      LAYER M5 ;
        RECT  89.904 0 89.928 0.084 ;
    END
  END b_own[22]
  PIN b_own[230]
    DIRECTION INPUT ;
    USE SIGNAL ;
    PORT
      LAYER M5 ;
        RECT  133.68 0 133.704 0.084 ;
    END
  END b_own[230]
  PIN b_own[231]
    DIRECTION INPUT ;
    USE SIGNAL ;
    PORT
      LAYER M3 ;
        RECT  134.1 0 134.118 0.038 ;
    END
    PORT
      LAYER M3 ;
        RECT  134.1 0.012 134.118 1.723 ;
    END
  END b_own[231]
  PIN b_own[232]
    DIRECTION INPUT ;
    USE SIGNAL ;
    PORT
      LAYER M5 ;
        RECT  134.448 0 134.472 0.084 ;
    END
  END b_own[232]
  PIN b_own[233]
    DIRECTION INPUT ;
    USE SIGNAL ;
    PORT
      LAYER M3 ;
        RECT  134.856 0 134.874 0.038 ;
    END
  END b_own[233]
  PIN b_own[234]
    DIRECTION INPUT ;
    USE SIGNAL ;
    PORT
      LAYER M5 ;
        RECT  135.216 0 135.24 0.084 ;
    END
  END b_own[234]
  PIN b_own[235]
    DIRECTION INPUT ;
    USE SIGNAL ;
    PORT
      LAYER M3 ;
        RECT  135.54 0 135.558 0.038 ;
    END
  END b_own[235]
  PIN b_own[236]
    DIRECTION INPUT ;
    USE SIGNAL ;
    PORT
      LAYER M5 ;
        RECT  135.984 0 136.008 0.084 ;
    END
  END b_own[236]
  PIN b_own[237]
    DIRECTION INPUT ;
    USE SIGNAL ;
    PORT
      LAYER M3 ;
        RECT  136.296 0 136.314 0.038 ;
    END
    PORT
      LAYER M3 ;
        RECT  136.296 0.012 136.314 1.723 ;
    END
  END b_own[237]
  PIN b_own[238]
    DIRECTION INPUT ;
    USE SIGNAL ;
    PORT
      LAYER M5 ;
        RECT  136.656 0 136.68 0.084 ;
    END
  END b_own[238]
  PIN b_own[239]
    DIRECTION INPUT ;
    USE SIGNAL ;
    PORT
      LAYER M3 ;
        RECT  137.088 0 137.106 0.038 ;
    END
    PORT
      LAYER M3 ;
        RECT  137.088 0.012 137.106 1.723 ;
    END
  END b_own[239]
  PIN b_own[23]
    DIRECTION INPUT ;
    USE SIGNAL ;
    PORT
      LAYER M3 ;
        RECT  90.144 0 90.162 0.038 ;
    END
  END b_own[23]
  PIN b_own[240]
    DIRECTION INPUT ;
    USE SIGNAL ;
    PORT
      LAYER M5 ;
        RECT  137.424 0 137.448 0.084 ;
    END
  END b_own[240]
  PIN b_own[241]
    DIRECTION INPUT ;
    USE SIGNAL ;
    PORT
      LAYER M3 ;
        RECT  137.844 0 137.862 0.038 ;
    END
  END b_own[241]
  PIN b_own[242]
    DIRECTION INPUT ;
    USE SIGNAL ;
    PORT
      LAYER M5 ;
        RECT  138.192 0 138.216 0.084 ;
    END
  END b_own[242]
  PIN b_own[243]
    DIRECTION INPUT ;
    USE SIGNAL ;
    PORT
      LAYER M3 ;
        RECT  138.528 0 138.546 0.038 ;
    END
  END b_own[243]
  PIN b_own[244]
    DIRECTION INPUT ;
    USE SIGNAL ;
    PORT
      LAYER M5 ;
        RECT  138.96 0 138.984 0.084 ;
    END
  END b_own[244]
  PIN b_own[245]
    DIRECTION INPUT ;
    USE SIGNAL ;
    PORT
      LAYER M3 ;
        RECT  139.284 0 139.302 0.038 ;
    END
    PORT
      LAYER M3 ;
        RECT  139.284 0.012 139.302 1.723 ;
    END
  END b_own[245]
  PIN b_own[246]
    DIRECTION INPUT ;
    USE SIGNAL ;
    PORT
      LAYER M5 ;
        RECT  139.632 0 139.656 0.084 ;
    END
  END b_own[246]
  PIN b_own[247]
    DIRECTION INPUT ;
    USE SIGNAL ;
    PORT
      LAYER M3 ;
        RECT  140.04 0 140.058 0.038 ;
    END
    PORT
      LAYER M3 ;
        RECT  140.04 0.012 140.058 1.723 ;
    END
  END b_own[247]
  PIN b_own[248]
    DIRECTION INPUT ;
    USE SIGNAL ;
    PORT
      LAYER M5 ;
        RECT  140.4 0 140.424 0.084 ;
    END
  END b_own[248]
  PIN b_own[249]
    DIRECTION INPUT ;
    USE SIGNAL ;
    PORT
      LAYER M3 ;
        RECT  140.832 0 140.85 0.038 ;
    END
  END b_own[249]
  PIN b_own[24]
    DIRECTION INPUT ;
    USE SIGNAL ;
    PORT
      LAYER M5 ;
        RECT  90.384 0 90.408 0.084 ;
    END
  END b_own[24]
  PIN b_own[250]
    DIRECTION INPUT ;
    USE SIGNAL ;
    PORT
      LAYER M5 ;
        RECT  141.168 0 141.192 0.084 ;
    END
  END b_own[250]
  PIN b_own[251]
    DIRECTION INPUT ;
    USE SIGNAL ;
    PORT
      LAYER M3 ;
        RECT  141.48 0 141.498 0.038 ;
    END
  END b_own[251]
  PIN b_own[252]
    DIRECTION INPUT ;
    USE SIGNAL ;
    PORT
      LAYER M5 ;
        RECT  141.936 0 141.96 0.084 ;
    END
  END b_own[252]
  PIN b_own[253]
    DIRECTION INPUT ;
    USE SIGNAL ;
    PORT
      LAYER M3 ;
        RECT  142.272 0 142.29 0.038 ;
    END
    PORT
      LAYER M3 ;
        RECT  142.272 0.012 142.29 1.147 ;
    END
  END b_own[253]
  PIN b_own[254]
    DIRECTION INPUT ;
    USE SIGNAL ;
    PORT
      LAYER M5 ;
        RECT  142.704 0 142.728 0.084 ;
    END
  END b_own[254]
  PIN b_own[255]
    DIRECTION INPUT ;
    USE SIGNAL ;
    PORT
      LAYER M3 ;
        RECT  143.028 0 143.046 0.038 ;
    END
    PORT
      LAYER M3 ;
        RECT  143.028 0.012 143.046 2.875 ;
    END
  END b_own[255]
  PIN b_own[25]
    DIRECTION INPUT ;
    USE SIGNAL ;
    PORT
      LAYER M3 ;
        RECT  90.504 0 90.522 0.038 ;
    END
  END b_own[25]
  PIN b_own[26]
    DIRECTION INPUT ;
    USE SIGNAL ;
    PORT
      LAYER M5 ;
        RECT  90.768 0 90.792 0.084 ;
    END
  END b_own[26]
  PIN b_own[27]
    DIRECTION INPUT ;
    USE SIGNAL ;
    PORT
      LAYER M3 ;
        RECT  90.9 0 90.918 0.038 ;
    END
  END b_own[27]
  PIN b_own[28]
    DIRECTION INPUT ;
    USE SIGNAL ;
    PORT
      LAYER M5 ;
        RECT  91.152 0 91.176 0.084 ;
    END
  END b_own[28]
  PIN b_own[29]
    DIRECTION INPUT ;
    USE SIGNAL ;
    PORT
      LAYER M3 ;
        RECT  91.368 0 91.386 0.038 ;
    END
  END b_own[29]
  PIN b_own[2]
    DIRECTION INPUT ;
    USE SIGNAL ;
    PORT
      LAYER M5 ;
        RECT  85.872 0 85.896 0.084 ;
    END
  END b_own[2]
  PIN b_own[30]
    DIRECTION INPUT ;
    USE SIGNAL ;
    PORT
      LAYER M5 ;
        RECT  91.536 0 91.56 0.084 ;
    END
  END b_own[30]
  PIN b_own[31]
    DIRECTION INPUT ;
    USE SIGNAL ;
    PORT
      LAYER M3 ;
        RECT  91.764 0 91.782 0.038 ;
    END
  END b_own[31]
  PIN b_own[32]
    DIRECTION INPUT ;
    USE SIGNAL ;
    PORT
      LAYER M5 ;
        RECT  92.016 0 92.04 0.084 ;
    END
  END b_own[32]
  PIN b_own[33]
    DIRECTION INPUT ;
    USE SIGNAL ;
    PORT
      LAYER M3 ;
        RECT  92.16 0 92.178 0.038 ;
    END
  END b_own[33]
  PIN b_own[34]
    DIRECTION INPUT ;
    USE SIGNAL ;
    PORT
      LAYER M5 ;
        RECT  92.4 0 92.424 0.084 ;
    END
  END b_own[34]
  PIN b_own[35]
    DIRECTION INPUT ;
    USE SIGNAL ;
    PORT
      LAYER M3 ;
        RECT  92.52 0 92.538 0.038 ;
    END
  END b_own[35]
  PIN b_own[36]
    DIRECTION INPUT ;
    USE SIGNAL ;
    PORT
      LAYER M5 ;
        RECT  92.784 0 92.808 0.084 ;
    END
  END b_own[36]
  PIN b_own[37]
    DIRECTION INPUT ;
    USE SIGNAL ;
    PORT
      LAYER M3 ;
        RECT  93.024 0 93.042 0.038 ;
    END
  END b_own[37]
  PIN b_own[38]
    DIRECTION INPUT ;
    USE SIGNAL ;
    PORT
      LAYER M5 ;
        RECT  93.168 0 93.192 0.084 ;
    END
  END b_own[38]
  PIN b_own[39]
    DIRECTION INPUT ;
    USE SIGNAL ;
    PORT
      LAYER M3 ;
        RECT  93.384 0 93.402 0.038 ;
    END
  END b_own[39]
  PIN b_own[3]
    DIRECTION INPUT ;
    USE SIGNAL ;
    PORT
      LAYER M3 ;
        RECT  86.004 0 86.022 0.038 ;
    END
  END b_own[3]
  PIN b_own[40]
    DIRECTION INPUT ;
    USE SIGNAL ;
    PORT
      LAYER M5 ;
        RECT  93.648 0 93.672 0.084 ;
    END
  END b_own[40]
  PIN b_own[41]
    DIRECTION INPUT ;
    USE SIGNAL ;
    PORT
      LAYER M3 ;
        RECT  93.78 0 93.798 0.038 ;
    END
  END b_own[41]
  PIN b_own[42]
    DIRECTION INPUT ;
    USE SIGNAL ;
    PORT
      LAYER M5 ;
        RECT  94.032 0 94.056 0.084 ;
    END
  END b_own[42]
  PIN b_own[43]
    DIRECTION INPUT ;
    USE SIGNAL ;
    PORT
      LAYER M3 ;
        RECT  94.248 0 94.266 0.038 ;
    END
  END b_own[43]
  PIN b_own[44]
    DIRECTION INPUT ;
    USE SIGNAL ;
    PORT
      LAYER M5 ;
        RECT  94.416 0 94.44 0.084 ;
    END
  END b_own[44]
  PIN b_own[45]
    DIRECTION INPUT ;
    USE SIGNAL ;
    PORT
      LAYER M3 ;
        RECT  94.644 0 94.662 0.038 ;
    END
  END b_own[45]
  PIN b_own[46]
    DIRECTION INPUT ;
    USE SIGNAL ;
    PORT
      LAYER M5 ;
        RECT  94.8 0 94.824 0.084 ;
    END
  END b_own[46]
  PIN b_own[47]
    DIRECTION INPUT ;
    USE SIGNAL ;
    PORT
      LAYER M3 ;
        RECT  95.04 0 95.058 0.038 ;
    END
  END b_own[47]
  PIN b_own[48]
    DIRECTION INPUT ;
    USE SIGNAL ;
    PORT
      LAYER M5 ;
        RECT  95.28 0 95.304 0.084 ;
    END
  END b_own[48]
  PIN b_own[49]
    DIRECTION INPUT ;
    USE SIGNAL ;
    PORT
      LAYER M3 ;
        RECT  95.4 0 95.418 0.038 ;
    END
  END b_own[49]
  PIN b_own[4]
    DIRECTION INPUT ;
    USE SIGNAL ;
    PORT
      LAYER M5 ;
        RECT  86.256 0 86.28 0.084 ;
    END
  END b_own[4]
  PIN b_own[50]
    DIRECTION INPUT ;
    USE SIGNAL ;
    PORT
      LAYER M5 ;
        RECT  95.664 0 95.688 0.084 ;
    END
  END b_own[50]
  PIN b_own[51]
    DIRECTION INPUT ;
    USE SIGNAL ;
    PORT
      LAYER M3 ;
        RECT  95.904 0 95.922 0.038 ;
    END
  END b_own[51]
  PIN b_own[52]
    DIRECTION INPUT ;
    USE SIGNAL ;
    PORT
      LAYER M5 ;
        RECT  96.048 0 96.072 0.084 ;
    END
  END b_own[52]
  PIN b_own[53]
    DIRECTION INPUT ;
    USE SIGNAL ;
    PORT
      LAYER M3 ;
        RECT  96.264 0 96.282 0.038 ;
    END
  END b_own[53]
  PIN b_own[54]
    DIRECTION INPUT ;
    USE SIGNAL ;
    PORT
      LAYER M5 ;
        RECT  96.528 0 96.552 0.084 ;
    END
  END b_own[54]
  PIN b_own[55]
    DIRECTION INPUT ;
    USE SIGNAL ;
    PORT
      LAYER M3 ;
        RECT  96.66 0 96.678 0.038 ;
    END
  END b_own[55]
  PIN b_own[56]
    DIRECTION INPUT ;
    USE SIGNAL ;
    PORT
      LAYER M5 ;
        RECT  96.912 0 96.936 0.084 ;
    END
  END b_own[56]
  PIN b_own[57]
    DIRECTION INPUT ;
    USE SIGNAL ;
    PORT
      LAYER M3 ;
        RECT  97.056 0 97.074 0.038 ;
    END
  END b_own[57]
  PIN b_own[58]
    DIRECTION INPUT ;
    USE SIGNAL ;
    PORT
      LAYER M5 ;
        RECT  97.296 0 97.32 0.084 ;
    END
  END b_own[58]
  PIN b_own[59]
    DIRECTION INPUT ;
    USE SIGNAL ;
    PORT
      LAYER M3 ;
        RECT  97.524 0 97.542 0.038 ;
    END
  END b_own[59]
  PIN b_own[5]
    DIRECTION INPUT ;
    USE SIGNAL ;
    PORT
      LAYER M3 ;
        RECT  86.472 0 86.49 0.038 ;
    END
  END b_own[5]
  PIN b_own[60]
    DIRECTION INPUT ;
    USE SIGNAL ;
    PORT
      LAYER M5 ;
        RECT  97.68 0 97.704 0.084 ;
    END
  END b_own[60]
  PIN b_own[61]
    DIRECTION INPUT ;
    USE SIGNAL ;
    PORT
      LAYER M3 ;
        RECT  97.92 0 97.938 0.038 ;
    END
  END b_own[61]
  PIN b_own[62]
    DIRECTION INPUT ;
    USE SIGNAL ;
    PORT
      LAYER M5 ;
        RECT  98.16 0 98.184 0.084 ;
    END
  END b_own[62]
  PIN b_own[63]
    DIRECTION INPUT ;
    USE SIGNAL ;
    PORT
      LAYER M3 ;
        RECT  98.28 0 98.298 0.038 ;
    END
  END b_own[63]
  PIN b_own[64]
    DIRECTION INPUT ;
    USE SIGNAL ;
    PORT
      LAYER M5 ;
        RECT  98.544 0 98.568 0.084 ;
    END
  END b_own[64]
  PIN b_own[65]
    DIRECTION INPUT ;
    USE SIGNAL ;
    PORT
      LAYER M3 ;
        RECT  98.676 0 98.694 0.038 ;
    END
  END b_own[65]
  PIN b_own[66]
    DIRECTION INPUT ;
    USE SIGNAL ;
    PORT
      LAYER M5 ;
        RECT  98.928 0 98.952 0.084 ;
    END
  END b_own[66]
  PIN b_own[67]
    DIRECTION INPUT ;
    USE SIGNAL ;
    PORT
      LAYER M3 ;
        RECT  99.144 0 99.162 0.038 ;
    END
  END b_own[67]
  PIN b_own[68]
    DIRECTION INPUT ;
    USE SIGNAL ;
    PORT
      LAYER M5 ;
        RECT  99.312 0 99.336 0.084 ;
    END
  END b_own[68]
  PIN b_own[69]
    DIRECTION INPUT ;
    USE SIGNAL ;
    PORT
      LAYER M3 ;
        RECT  99.54 0 99.558 0.038 ;
    END
  END b_own[69]
  PIN b_own[6]
    DIRECTION INPUT ;
    USE SIGNAL ;
    PORT
      LAYER M5 ;
        RECT  86.64 0 86.664 0.084 ;
    END
  END b_own[6]
  PIN b_own[70]
    DIRECTION INPUT ;
    USE SIGNAL ;
    PORT
      LAYER M5 ;
        RECT  99.792 0 99.816 0.084 ;
    END
  END b_own[70]
  PIN b_own[71]
    DIRECTION INPUT ;
    USE SIGNAL ;
    PORT
      LAYER M3 ;
        RECT  99.936 0 99.954 0.038 ;
    END
  END b_own[71]
  PIN b_own[72]
    DIRECTION INPUT ;
    USE SIGNAL ;
    PORT
      LAYER M5 ;
        RECT  100.176 0 100.2 0.084 ;
    END
  END b_own[72]
  PIN b_own[73]
    DIRECTION INPUT ;
    USE SIGNAL ;
    PORT
      LAYER M3 ;
        RECT  100.404 0 100.422 0.038 ;
    END
  END b_own[73]
  PIN b_own[74]
    DIRECTION INPUT ;
    USE SIGNAL ;
    PORT
      LAYER M5 ;
        RECT  100.56 0 100.584 0.084 ;
    END
  END b_own[74]
  PIN b_own[75]
    DIRECTION INPUT ;
    USE SIGNAL ;
    PORT
      LAYER M3 ;
        RECT  100.8 0 100.818 0.038 ;
    END
  END b_own[75]
  PIN b_own[76]
    DIRECTION INPUT ;
    USE SIGNAL ;
    PORT
      LAYER M5 ;
        RECT  100.944 0 100.968 0.084 ;
    END
  END b_own[76]
  PIN b_own[77]
    DIRECTION INPUT ;
    USE SIGNAL ;
    PORT
      LAYER M3 ;
        RECT  101.16 0 101.178 0.038 ;
    END
  END b_own[77]
  PIN b_own[78]
    DIRECTION INPUT ;
    USE SIGNAL ;
    PORT
      LAYER M5 ;
        RECT  101.424 0 101.448 0.084 ;
    END
  END b_own[78]
  PIN b_own[79]
    DIRECTION INPUT ;
    USE SIGNAL ;
    PORT
      LAYER M3 ;
        RECT  101.556 0 101.574 0.038 ;
    END
  END b_own[79]
  PIN b_own[7]
    DIRECTION INPUT ;
    USE SIGNAL ;
    PORT
      LAYER M3 ;
        RECT  86.868 0 86.886 0.038 ;
    END
  END b_own[7]
  PIN b_own[80]
    DIRECTION INPUT ;
    USE SIGNAL ;
    PORT
      LAYER M5 ;
        RECT  101.808 0 101.832 0.084 ;
    END
  END b_own[80]
  PIN b_own[81]
    DIRECTION INPUT ;
    USE SIGNAL ;
    PORT
      LAYER M3 ;
        RECT  102.024 0 102.042 0.038 ;
    END
  END b_own[81]
  PIN b_own[82]
    DIRECTION INPUT ;
    USE SIGNAL ;
    PORT
      LAYER M5 ;
        RECT  102.192 0 102.216 0.084 ;
    END
  END b_own[82]
  PIN b_own[83]
    DIRECTION INPUT ;
    USE SIGNAL ;
    PORT
      LAYER M3 ;
        RECT  102.42 0 102.438 0.038 ;
    END
  END b_own[83]
  PIN b_own[84]
    DIRECTION INPUT ;
    USE SIGNAL ;
    PORT
      LAYER M5 ;
        RECT  102.576 0 102.6 0.084 ;
    END
  END b_own[84]
  PIN b_own[85]
    DIRECTION INPUT ;
    USE SIGNAL ;
    PORT
      LAYER M3 ;
        RECT  102.816 0 102.834 0.038 ;
    END
  END b_own[85]
  PIN b_own[86]
    DIRECTION INPUT ;
    USE SIGNAL ;
    PORT
      LAYER M5 ;
        RECT  103.056 0 103.08 0.084 ;
    END
  END b_own[86]
  PIN b_own[87]
    DIRECTION INPUT ;
    USE SIGNAL ;
    PORT
      LAYER M3 ;
        RECT  103.176 0 103.194 0.038 ;
    END
  END b_own[87]
  PIN b_own[88]
    DIRECTION INPUT ;
    USE SIGNAL ;
    PORT
      LAYER M5 ;
        RECT  103.44 0 103.464 0.084 ;
    END
  END b_own[88]
  PIN b_own[89]
    DIRECTION INPUT ;
    USE SIGNAL ;
    PORT
      LAYER M3 ;
        RECT  103.68 0 103.698 0.038 ;
    END
  END b_own[89]
  PIN b_own[8]
    DIRECTION INPUT ;
    USE SIGNAL ;
    PORT
      LAYER M5 ;
        RECT  87.024 0 87.048 0.084 ;
    END
  END b_own[8]
  PIN b_own[90]
    DIRECTION INPUT ;
    USE SIGNAL ;
    PORT
      LAYER M5 ;
        RECT  103.824 0 103.848 0.084 ;
    END
  END b_own[90]
  PIN b_own[91]
    DIRECTION INPUT ;
    USE SIGNAL ;
    PORT
      LAYER M3 ;
        RECT  104.04 0 104.058 0.038 ;
    END
  END b_own[91]
  PIN b_own[92]
    DIRECTION INPUT ;
    USE SIGNAL ;
    PORT
      LAYER M5 ;
        RECT  104.304 0 104.328 0.084 ;
    END
  END b_own[92]
  PIN b_own[93]
    DIRECTION INPUT ;
    USE SIGNAL ;
    PORT
      LAYER M3 ;
        RECT  104.436 0 104.454 0.038 ;
    END
  END b_own[93]
  PIN b_own[94]
    DIRECTION INPUT ;
    USE SIGNAL ;
    PORT
      LAYER M5 ;
        RECT  104.688 0 104.712 0.084 ;
    END
  END b_own[94]
  PIN b_own[95]
    DIRECTION INPUT ;
    USE SIGNAL ;
    PORT
      LAYER M3 ;
        RECT  104.832 0 104.85 0.038 ;
    END
  END b_own[95]
  PIN b_own[96]
    DIRECTION INPUT ;
    USE SIGNAL ;
    PORT
      LAYER M5 ;
        RECT  105.072 0 105.096 0.084 ;
    END
  END b_own[96]
  PIN b_own[97]
    DIRECTION INPUT ;
    USE SIGNAL ;
    PORT
      LAYER M3 ;
        RECT  105.3 0 105.318 0.038 ;
    END
  END b_own[97]
  PIN b_own[98]
    DIRECTION INPUT ;
    USE SIGNAL ;
    PORT
      LAYER M5 ;
        RECT  105.456 0 105.48 0.084 ;
    END
  END b_own[98]
  PIN b_own[99]
    DIRECTION INPUT ;
    USE SIGNAL ;
    PORT
      LAYER M3 ;
        RECT  105.696 0 105.714 0.038 ;
    END
  END b_own[99]
  PIN b_own[9]
    DIRECTION INPUT ;
    USE SIGNAL ;
    PORT
      LAYER M3 ;
        RECT  87.264 0 87.282 0.038 ;
    END
  END b_own[9]
  PIN b_own_out[0]
    DIRECTION OUTPUT ;
    USE SIGNAL ;
    PORT
      LAYER M5 ;
        RECT  85.392 25.836 85.416 25.92 ;
    END
  END b_own_out[0]
  PIN b_own_out[100]
    DIRECTION OUTPUT ;
    USE SIGNAL ;
    PORT
      LAYER M5 ;
        RECT  105.936 25.836 105.96 25.92 ;
    END
  END b_own_out[100]
  PIN b_own_out[101]
    DIRECTION OUTPUT ;
    USE SIGNAL ;
    PORT
      LAYER M3 ;
        RECT  106.056 25.882 106.074 25.92 ;
    END
  END b_own_out[101]
  PIN b_own_out[102]
    DIRECTION OUTPUT ;
    USE SIGNAL ;
    PORT
      LAYER M5 ;
        RECT  106.32 25.836 106.344 25.92 ;
    END
  END b_own_out[102]
  PIN b_own_out[103]
    DIRECTION OUTPUT ;
    USE SIGNAL ;
    PORT
      LAYER M3 ;
        RECT  106.56 25.882 106.578 25.92 ;
    END
  END b_own_out[103]
  PIN b_own_out[104]
    DIRECTION OUTPUT ;
    USE SIGNAL ;
    PORT
      LAYER M5 ;
        RECT  106.704 25.836 106.728 25.92 ;
    END
  END b_own_out[104]
  PIN b_own_out[105]
    DIRECTION OUTPUT ;
    USE SIGNAL ;
    PORT
      LAYER M3 ;
        RECT  106.92 25.882 106.938 25.92 ;
    END
  END b_own_out[105]
  PIN b_own_out[106]
    DIRECTION OUTPUT ;
    USE SIGNAL ;
    PORT
      LAYER M5 ;
        RECT  107.088 25.836 107.112 25.92 ;
    END
  END b_own_out[106]
  PIN b_own_out[107]
    DIRECTION OUTPUT ;
    USE SIGNAL ;
    PORT
      LAYER M3 ;
        RECT  107.316 25.882 107.334 25.92 ;
    END
  END b_own_out[107]
  PIN b_own_out[108]
    DIRECTION OUTPUT ;
    USE SIGNAL ;
    PORT
      LAYER M5 ;
        RECT  107.568 25.836 107.592 25.92 ;
    END
  END b_own_out[108]
  PIN b_own_out[109]
    DIRECTION OUTPUT ;
    USE SIGNAL ;
    PORT
      LAYER M3 ;
        RECT  107.712 25.882 107.73 25.92 ;
    END
  END b_own_out[109]
  PIN b_own_out[10]
    DIRECTION OUTPUT ;
    USE SIGNAL ;
    PORT
      LAYER M5 ;
        RECT  87.504 25.836 87.528 25.92 ;
    END
  END b_own_out[10]
  PIN b_own_out[110]
    DIRECTION OUTPUT ;
    USE SIGNAL ;
    PORT
      LAYER M5 ;
        RECT  107.952 25.836 107.976 25.92 ;
    END
  END b_own_out[110]
  PIN b_own_out[111]
    DIRECTION OUTPUT ;
    USE SIGNAL ;
    PORT
      LAYER M3 ;
        RECT  108.18 25.882 108.198 25.92 ;
    END
  END b_own_out[111]
  PIN b_own_out[112]
    DIRECTION OUTPUT ;
    USE SIGNAL ;
    PORT
      LAYER M5 ;
        RECT  108.336 25.836 108.36 25.92 ;
    END
  END b_own_out[112]
  PIN b_own_out[113]
    DIRECTION OUTPUT ;
    USE SIGNAL ;
    PORT
      LAYER M3 ;
        RECT  108.576 25.882 108.594 25.92 ;
    END
  END b_own_out[113]
  PIN b_own_out[114]
    DIRECTION OUTPUT ;
    USE SIGNAL ;
    PORT
      LAYER M5 ;
        RECT  108.72 25.836 108.744 25.92 ;
    END
  END b_own_out[114]
  PIN b_own_out[115]
    DIRECTION OUTPUT ;
    USE SIGNAL ;
    PORT
      LAYER M3 ;
        RECT  108.936 25.882 108.954 25.92 ;
    END
  END b_own_out[115]
  PIN b_own_out[116]
    DIRECTION OUTPUT ;
    USE SIGNAL ;
    PORT
      LAYER M5 ;
        RECT  109.2 25.836 109.224 25.92 ;
    END
  END b_own_out[116]
  PIN b_own_out[117]
    DIRECTION OUTPUT ;
    USE SIGNAL ;
    PORT
      LAYER M3 ;
        RECT  109.332 25.882 109.35 25.92 ;
    END
  END b_own_out[117]
  PIN b_own_out[118]
    DIRECTION OUTPUT ;
    USE SIGNAL ;
    PORT
      LAYER M5 ;
        RECT  109.584 25.836 109.608 25.92 ;
    END
  END b_own_out[118]
  PIN b_own_out[119]
    DIRECTION OUTPUT ;
    USE SIGNAL ;
    PORT
      LAYER M3 ;
        RECT  109.8 25.882 109.818 25.92 ;
    END
  END b_own_out[119]
  PIN b_own_out[11]
    DIRECTION OUTPUT ;
    USE SIGNAL ;
    PORT
      LAYER M3 ;
        RECT  87.624 25.882 87.642 25.92 ;
    END
  END b_own_out[11]
  PIN b_own_out[120]
    DIRECTION OUTPUT ;
    USE SIGNAL ;
    PORT
      LAYER M5 ;
        RECT  109.968 25.836 109.992 25.92 ;
    END
  END b_own_out[120]
  PIN b_own_out[121]
    DIRECTION OUTPUT ;
    USE SIGNAL ;
    PORT
      LAYER M3 ;
        RECT  110.196 25.882 110.214 25.92 ;
    END
  END b_own_out[121]
  PIN b_own_out[122]
    DIRECTION OUTPUT ;
    USE SIGNAL ;
    PORT
      LAYER M5 ;
        RECT  110.448 25.836 110.472 25.92 ;
    END
  END b_own_out[122]
  PIN b_own_out[123]
    DIRECTION OUTPUT ;
    USE SIGNAL ;
    PORT
      LAYER M3 ;
        RECT  110.592 25.882 110.61 25.92 ;
    END
  END b_own_out[123]
  PIN b_own_out[124]
    DIRECTION OUTPUT ;
    USE SIGNAL ;
    PORT
      LAYER M5 ;
        RECT  110.832 25.836 110.856 25.92 ;
    END
  END b_own_out[124]
  PIN b_own_out[125]
    DIRECTION OUTPUT ;
    USE SIGNAL ;
    PORT
      LAYER M3 ;
        RECT  110.952 25.882 110.97 25.92 ;
    END
  END b_own_out[125]
  PIN b_own_out[126]
    DIRECTION OUTPUT ;
    USE SIGNAL ;
    PORT
      LAYER M5 ;
        RECT  111.216 25.836 111.24 25.92 ;
    END
  END b_own_out[126]
  PIN b_own_out[127]
    DIRECTION OUTPUT ;
    USE SIGNAL ;
    PORT
      LAYER M3 ;
        RECT  111.456 25.882 111.474 25.92 ;
    END
  END b_own_out[127]
  PIN b_own_out[128]
    DIRECTION OUTPUT ;
    USE SIGNAL ;
    PORT
      LAYER M5 ;
        RECT  111.6 25.836 111.624 25.92 ;
    END
  END b_own_out[128]
  PIN b_own_out[129]
    DIRECTION OUTPUT ;
    USE SIGNAL ;
    PORT
      LAYER M3 ;
        RECT  111.816 25.882 111.834 25.92 ;
    END
  END b_own_out[129]
  PIN b_own_out[12]
    DIRECTION OUTPUT ;
    USE SIGNAL ;
    PORT
      LAYER M5 ;
        RECT  87.888 25.836 87.912 25.92 ;
    END
  END b_own_out[12]
  PIN b_own_out[130]
    DIRECTION OUTPUT ;
    USE SIGNAL ;
    PORT
      LAYER M5 ;
        RECT  112.08 25.836 112.104 25.92 ;
    END
  END b_own_out[130]
  PIN b_own_out[131]
    DIRECTION OUTPUT ;
    USE SIGNAL ;
    PORT
      LAYER M3 ;
        RECT  112.212 25.882 112.23 25.92 ;
    END
  END b_own_out[131]
  PIN b_own_out[132]
    DIRECTION OUTPUT ;
    USE SIGNAL ;
    PORT
      LAYER M5 ;
        RECT  112.464 25.836 112.488 25.92 ;
    END
  END b_own_out[132]
  PIN b_own_out[133]
    DIRECTION OUTPUT ;
    USE SIGNAL ;
    PORT
      LAYER M3 ;
        RECT  112.608 25.882 112.626 25.92 ;
    END
  END b_own_out[133]
  PIN b_own_out[134]
    DIRECTION OUTPUT ;
    USE SIGNAL ;
    PORT
      LAYER M5 ;
        RECT  112.848 25.836 112.872 25.92 ;
    END
  END b_own_out[134]
  PIN b_own_out[135]
    DIRECTION OUTPUT ;
    USE SIGNAL ;
    PORT
      LAYER M3 ;
        RECT  113.076 25.882 113.094 25.92 ;
    END
  END b_own_out[135]
  PIN b_own_out[136]
    DIRECTION OUTPUT ;
    USE SIGNAL ;
    PORT
      LAYER M5 ;
        RECT  113.232 25.836 113.256 25.92 ;
    END
  END b_own_out[136]
  PIN b_own_out[137]
    DIRECTION OUTPUT ;
    USE SIGNAL ;
    PORT
      LAYER M3 ;
        RECT  113.472 25.882 113.49 25.92 ;
    END
  END b_own_out[137]
  PIN b_own_out[138]
    DIRECTION OUTPUT ;
    USE SIGNAL ;
    PORT
      LAYER M5 ;
        RECT  113.712 25.836 113.736 25.92 ;
    END
  END b_own_out[138]
  PIN b_own_out[139]
    DIRECTION OUTPUT ;
    USE SIGNAL ;
    PORT
      LAYER M3 ;
        RECT  113.832 25.882 113.85 25.92 ;
    END
  END b_own_out[139]
  PIN b_own_out[13]
    DIRECTION OUTPUT ;
    USE SIGNAL ;
    PORT
      LAYER M3 ;
        RECT  88.128 25.882 88.146 25.92 ;
    END
  END b_own_out[13]
  PIN b_own_out[140]
    DIRECTION OUTPUT ;
    USE SIGNAL ;
    PORT
      LAYER M5 ;
        RECT  114.096 25.836 114.12 25.92 ;
    END
  END b_own_out[140]
  PIN b_own_out[141]
    DIRECTION OUTPUT ;
    USE SIGNAL ;
    PORT
      LAYER M3 ;
        RECT  114.336 25.882 114.354 25.92 ;
    END
  END b_own_out[141]
  PIN b_own_out[142]
    DIRECTION OUTPUT ;
    USE SIGNAL ;
    PORT
      LAYER M5 ;
        RECT  114.48 25.836 114.504 25.92 ;
    END
  END b_own_out[142]
  PIN b_own_out[143]
    DIRECTION OUTPUT ;
    USE SIGNAL ;
    PORT
      LAYER M3 ;
        RECT  114.696 25.882 114.714 25.92 ;
    END
  END b_own_out[143]
  PIN b_own_out[144]
    DIRECTION OUTPUT ;
    USE SIGNAL ;
    PORT
      LAYER M5 ;
        RECT  114.864 25.836 114.888 25.92 ;
    END
  END b_own_out[144]
  PIN b_own_out[145]
    DIRECTION OUTPUT ;
    USE SIGNAL ;
    PORT
      LAYER M3 ;
        RECT  115.092 25.882 115.11 25.92 ;
    END
  END b_own_out[145]
  PIN b_own_out[146]
    DIRECTION OUTPUT ;
    USE SIGNAL ;
    PORT
      LAYER M5 ;
        RECT  115.344 25.836 115.368 25.92 ;
    END
  END b_own_out[146]
  PIN b_own_out[147]
    DIRECTION OUTPUT ;
    USE SIGNAL ;
    PORT
      LAYER M3 ;
        RECT  115.488 25.882 115.506 25.92 ;
    END
  END b_own_out[147]
  PIN b_own_out[148]
    DIRECTION OUTPUT ;
    USE SIGNAL ;
    PORT
      LAYER M5 ;
        RECT  115.728 25.836 115.752 25.92 ;
    END
  END b_own_out[148]
  PIN b_own_out[149]
    DIRECTION OUTPUT ;
    USE SIGNAL ;
    PORT
      LAYER M3 ;
        RECT  115.956 25.882 115.974 25.92 ;
    END
  END b_own_out[149]
  PIN b_own_out[14]
    DIRECTION OUTPUT ;
    USE SIGNAL ;
    PORT
      LAYER M5 ;
        RECT  88.272 25.836 88.296 25.92 ;
    END
  END b_own_out[14]
  PIN b_own_out[150]
    DIRECTION OUTPUT ;
    USE SIGNAL ;
    PORT
      LAYER M5 ;
        RECT  116.112 25.836 116.136 25.92 ;
    END
  END b_own_out[150]
  PIN b_own_out[151]
    DIRECTION OUTPUT ;
    USE SIGNAL ;
    PORT
      LAYER M3 ;
        RECT  116.352 25.882 116.37 25.92 ;
    END
  END b_own_out[151]
  PIN b_own_out[152]
    DIRECTION OUTPUT ;
    USE SIGNAL ;
    PORT
      LAYER M5 ;
        RECT  116.592 25.836 116.616 25.92 ;
    END
  END b_own_out[152]
  PIN b_own_out[153]
    DIRECTION OUTPUT ;
    USE SIGNAL ;
    PORT
      LAYER M3 ;
        RECT  116.712 25.882 116.73 25.92 ;
    END
  END b_own_out[153]
  PIN b_own_out[154]
    DIRECTION OUTPUT ;
    USE SIGNAL ;
    PORT
      LAYER M5 ;
        RECT  116.976 25.836 117 25.92 ;
    END
  END b_own_out[154]
  PIN b_own_out[155]
    DIRECTION OUTPUT ;
    USE SIGNAL ;
    PORT
      LAYER M3 ;
        RECT  117.108 25.882 117.126 25.92 ;
    END
  END b_own_out[155]
  PIN b_own_out[156]
    DIRECTION OUTPUT ;
    USE SIGNAL ;
    PORT
      LAYER M5 ;
        RECT  117.36 25.836 117.384 25.92 ;
    END
  END b_own_out[156]
  PIN b_own_out[157]
    DIRECTION OUTPUT ;
    USE SIGNAL ;
    PORT
      LAYER M3 ;
        RECT  117.576 25.882 117.594 25.92 ;
    END
  END b_own_out[157]
  PIN b_own_out[158]
    DIRECTION OUTPUT ;
    USE SIGNAL ;
    PORT
      LAYER M5 ;
        RECT  117.744 25.836 117.768 25.92 ;
    END
  END b_own_out[158]
  PIN b_own_out[159]
    DIRECTION OUTPUT ;
    USE SIGNAL ;
    PORT
      LAYER M3 ;
        RECT  117.972 25.882 117.99 25.92 ;
    END
  END b_own_out[159]
  PIN b_own_out[15]
    DIRECTION OUTPUT ;
    USE SIGNAL ;
    PORT
      LAYER M3 ;
        RECT  88.488 25.882 88.506 25.92 ;
    END
  END b_own_out[15]
  PIN b_own_out[160]
    DIRECTION OUTPUT ;
    USE SIGNAL ;
    PORT
      LAYER M5 ;
        RECT  118.224 25.836 118.248 25.92 ;
    END
  END b_own_out[160]
  PIN b_own_out[161]
    DIRECTION OUTPUT ;
    USE SIGNAL ;
    PORT
      LAYER M3 ;
        RECT  118.368 25.882 118.386 25.92 ;
    END
  END b_own_out[161]
  PIN b_own_out[162]
    DIRECTION OUTPUT ;
    USE SIGNAL ;
    PORT
      LAYER M5 ;
        RECT  118.608 25.836 118.632 25.92 ;
    END
  END b_own_out[162]
  PIN b_own_out[163]
    DIRECTION OUTPUT ;
    USE SIGNAL ;
    PORT
      LAYER M3 ;
        RECT  118.728 25.882 118.746 25.92 ;
    END
  END b_own_out[163]
  PIN b_own_out[164]
    DIRECTION OUTPUT ;
    USE SIGNAL ;
    PORT
      LAYER M5 ;
        RECT  118.992 25.836 119.016 25.92 ;
    END
  END b_own_out[164]
  PIN b_own_out[165]
    DIRECTION OUTPUT ;
    USE SIGNAL ;
    PORT
      LAYER M3 ;
        RECT  119.232 25.882 119.25 25.92 ;
    END
  END b_own_out[165]
  PIN b_own_out[166]
    DIRECTION OUTPUT ;
    USE SIGNAL ;
    PORT
      LAYER M5 ;
        RECT  119.376 25.836 119.4 25.92 ;
    END
  END b_own_out[166]
  PIN b_own_out[167]
    DIRECTION OUTPUT ;
    USE SIGNAL ;
    PORT
      LAYER M3 ;
        RECT  119.592 25.882 119.61 25.92 ;
    END
  END b_own_out[167]
  PIN b_own_out[168]
    DIRECTION OUTPUT ;
    USE SIGNAL ;
    PORT
      LAYER M5 ;
        RECT  119.856 25.836 119.88 25.92 ;
    END
  END b_own_out[168]
  PIN b_own_out[169]
    DIRECTION OUTPUT ;
    USE SIGNAL ;
    PORT
      LAYER M3 ;
        RECT  119.988 25.882 120.006 25.92 ;
    END
  END b_own_out[169]
  PIN b_own_out[16]
    DIRECTION OUTPUT ;
    USE SIGNAL ;
    PORT
      LAYER M5 ;
        RECT  88.656 25.836 88.68 25.92 ;
    END
  END b_own_out[16]
  PIN b_own_out[170]
    DIRECTION OUTPUT ;
    USE SIGNAL ;
    PORT
      LAYER M5 ;
        RECT  120.24 25.836 120.264 25.92 ;
    END
  END b_own_out[170]
  PIN b_own_out[171]
    DIRECTION OUTPUT ;
    USE SIGNAL ;
    PORT
      LAYER M3 ;
        RECT  120.456 25.882 120.474 25.92 ;
    END
  END b_own_out[171]
  PIN b_own_out[172]
    DIRECTION OUTPUT ;
    USE SIGNAL ;
    PORT
      LAYER M5 ;
        RECT  120.624 25.836 120.648 25.92 ;
    END
  END b_own_out[172]
  PIN b_own_out[173]
    DIRECTION OUTPUT ;
    USE SIGNAL ;
    PORT
      LAYER M3 ;
        RECT  120.852 25.882 120.87 25.92 ;
    END
  END b_own_out[173]
  PIN b_own_out[174]
    DIRECTION OUTPUT ;
    USE SIGNAL ;
    PORT
      LAYER M5 ;
        RECT  121.008 25.836 121.032 25.92 ;
    END
  END b_own_out[174]
  PIN b_own_out[175]
    DIRECTION OUTPUT ;
    USE SIGNAL ;
    PORT
      LAYER M3 ;
        RECT  121.248 25.882 121.266 25.92 ;
    END
  END b_own_out[175]
  PIN b_own_out[176]
    DIRECTION OUTPUT ;
    USE SIGNAL ;
    PORT
      LAYER M5 ;
        RECT  121.488 25.836 121.512 25.92 ;
    END
  END b_own_out[176]
  PIN b_own_out[177]
    DIRECTION OUTPUT ;
    USE SIGNAL ;
    PORT
      LAYER M3 ;
        RECT  121.608 25.882 121.626 25.92 ;
    END
  END b_own_out[177]
  PIN b_own_out[178]
    DIRECTION OUTPUT ;
    USE SIGNAL ;
    PORT
      LAYER M5 ;
        RECT  121.872 25.836 121.896 25.92 ;
    END
  END b_own_out[178]
  PIN b_own_out[179]
    DIRECTION OUTPUT ;
    USE SIGNAL ;
    PORT
      LAYER M3 ;
        RECT  122.112 25.882 122.13 25.92 ;
    END
  END b_own_out[179]
  PIN b_own_out[17]
    DIRECTION OUTPUT ;
    USE SIGNAL ;
    PORT
      LAYER M3 ;
        RECT  88.884 25.882 88.902 25.92 ;
    END
  END b_own_out[17]
  PIN b_own_out[180]
    DIRECTION OUTPUT ;
    USE SIGNAL ;
    PORT
      LAYER M5 ;
        RECT  122.256 25.836 122.28 25.92 ;
    END
  END b_own_out[180]
  PIN b_own_out[181]
    DIRECTION OUTPUT ;
    USE SIGNAL ;
    PORT
      LAYER M3 ;
        RECT  122.472 25.882 122.49 25.92 ;
    END
  END b_own_out[181]
  PIN b_own_out[182]
    DIRECTION OUTPUT ;
    USE SIGNAL ;
    PORT
      LAYER M5 ;
        RECT  122.64 25.836 122.664 25.92 ;
    END
  END b_own_out[182]
  PIN b_own_out[183]
    DIRECTION OUTPUT ;
    USE SIGNAL ;
    PORT
      LAYER M3 ;
        RECT  122.868 25.882 122.886 25.92 ;
    END
  END b_own_out[183]
  PIN b_own_out[184]
    DIRECTION OUTPUT ;
    USE SIGNAL ;
    PORT
      LAYER M5 ;
        RECT  123.12 25.836 123.144 25.92 ;
    END
  END b_own_out[184]
  PIN b_own_out[185]
    DIRECTION OUTPUT ;
    USE SIGNAL ;
    PORT
      LAYER M3 ;
        RECT  123.264 25.882 123.282 25.92 ;
    END
  END b_own_out[185]
  PIN b_own_out[186]
    DIRECTION OUTPUT ;
    USE SIGNAL ;
    PORT
      LAYER M5 ;
        RECT  123.504 25.836 123.528 25.92 ;
    END
  END b_own_out[186]
  PIN b_own_out[187]
    DIRECTION OUTPUT ;
    USE SIGNAL ;
    PORT
      LAYER M3 ;
        RECT  123.732 25.882 123.75 25.92 ;
    END
  END b_own_out[187]
  PIN b_own_out[188]
    DIRECTION OUTPUT ;
    USE SIGNAL ;
    PORT
      LAYER M5 ;
        RECT  123.888 25.836 123.912 25.92 ;
    END
  END b_own_out[188]
  PIN b_own_out[189]
    DIRECTION OUTPUT ;
    USE SIGNAL ;
    PORT
      LAYER M3 ;
        RECT  124.128 25.882 124.146 25.92 ;
    END
  END b_own_out[189]
  PIN b_own_out[18]
    DIRECTION OUTPUT ;
    USE SIGNAL ;
    PORT
      LAYER M5 ;
        RECT  89.136 25.836 89.16 25.92 ;
    END
  END b_own_out[18]
  PIN b_own_out[190]
    DIRECTION OUTPUT ;
    USE SIGNAL ;
    PORT
      LAYER M5 ;
        RECT  124.368 25.836 124.392 25.92 ;
    END
  END b_own_out[190]
  PIN b_own_out[191]
    DIRECTION OUTPUT ;
    USE SIGNAL ;
    PORT
      LAYER M3 ;
        RECT  124.488 25.882 124.506 25.92 ;
    END
  END b_own_out[191]
  PIN b_own_out[192]
    DIRECTION OUTPUT ;
    USE SIGNAL ;
    PORT
      LAYER M5 ;
        RECT  124.752 25.836 124.776 25.92 ;
    END
  END b_own_out[192]
  PIN b_own_out[193]
    DIRECTION OUTPUT ;
    USE SIGNAL ;
    PORT
      LAYER M3 ;
        RECT  124.884 25.882 124.902 25.92 ;
    END
  END b_own_out[193]
  PIN b_own_out[194]
    DIRECTION OUTPUT ;
    USE SIGNAL ;
    PORT
      LAYER M5 ;
        RECT  125.136 25.836 125.16 25.92 ;
    END
  END b_own_out[194]
  PIN b_own_out[195]
    DIRECTION OUTPUT ;
    USE SIGNAL ;
    PORT
      LAYER M3 ;
        RECT  125.352 25.882 125.37 25.92 ;
    END
  END b_own_out[195]
  PIN b_own_out[196]
    DIRECTION OUTPUT ;
    USE SIGNAL ;
    PORT
      LAYER M5 ;
        RECT  125.52 25.836 125.544 25.92 ;
    END
  END b_own_out[196]
  PIN b_own_out[197]
    DIRECTION OUTPUT ;
    USE SIGNAL ;
    PORT
      LAYER M3 ;
        RECT  125.748 25.882 125.766 25.92 ;
    END
  END b_own_out[197]
  PIN b_own_out[198]
    DIRECTION OUTPUT ;
    USE SIGNAL ;
    PORT
      LAYER M5 ;
        RECT  126 25.836 126.024 25.92 ;
    END
  END b_own_out[198]
  PIN b_own_out[199]
    DIRECTION OUTPUT ;
    USE SIGNAL ;
    PORT
      LAYER M3 ;
        RECT  126.144 25.882 126.162 25.92 ;
    END
  END b_own_out[199]
  PIN b_own_out[19]
    DIRECTION OUTPUT ;
    USE SIGNAL ;
    PORT
      LAYER M3 ;
        RECT  89.28 25.882 89.298 25.92 ;
    END
  END b_own_out[19]
  PIN b_own_out[1]
    DIRECTION OUTPUT ;
    USE SIGNAL ;
    PORT
      LAYER M3 ;
        RECT  85.608 25.882 85.626 25.92 ;
    END
  END b_own_out[1]
  PIN b_own_out[200]
    DIRECTION OUTPUT ;
    USE SIGNAL ;
    PORT
      LAYER M5 ;
        RECT  126.384 25.836 126.408 25.92 ;
    END
  END b_own_out[200]
  PIN b_own_out[201]
    DIRECTION OUTPUT ;
    USE SIGNAL ;
    PORT
      LAYER M3 ;
        RECT  126.612 25.882 126.63 25.92 ;
    END
  END b_own_out[201]
  PIN b_own_out[202]
    DIRECTION OUTPUT ;
    USE SIGNAL ;
    PORT
      LAYER M5 ;
        RECT  126.768 25.836 126.792 25.92 ;
    END
  END b_own_out[202]
  PIN b_own_out[203]
    DIRECTION OUTPUT ;
    USE SIGNAL ;
    PORT
      LAYER M3 ;
        RECT  127.008 25.882 127.026 25.92 ;
    END
  END b_own_out[203]
  PIN b_own_out[204]
    DIRECTION OUTPUT ;
    USE SIGNAL ;
    PORT
      LAYER M5 ;
        RECT  127.152 25.836 127.176 25.92 ;
    END
  END b_own_out[204]
  PIN b_own_out[205]
    DIRECTION OUTPUT ;
    USE SIGNAL ;
    PORT
      LAYER M3 ;
        RECT  127.368 25.882 127.386 25.92 ;
    END
  END b_own_out[205]
  PIN b_own_out[206]
    DIRECTION OUTPUT ;
    USE SIGNAL ;
    PORT
      LAYER M5 ;
        RECT  127.632 25.836 127.656 25.92 ;
    END
  END b_own_out[206]
  PIN b_own_out[207]
    DIRECTION OUTPUT ;
    USE SIGNAL ;
    PORT
      LAYER M3 ;
        RECT  127.764 25.882 127.782 25.92 ;
    END
  END b_own_out[207]
  PIN b_own_out[208]
    DIRECTION OUTPUT ;
    USE SIGNAL ;
    PORT
      LAYER M5 ;
        RECT  128.016 25.836 128.04 25.92 ;
    END
  END b_own_out[208]
  PIN b_own_out[209]
    DIRECTION OUTPUT ;
    USE SIGNAL ;
    PORT
      LAYER M3 ;
        RECT  128.232 25.882 128.25 25.92 ;
    END
  END b_own_out[209]
  PIN b_own_out[20]
    DIRECTION OUTPUT ;
    USE SIGNAL ;
    PORT
      LAYER M5 ;
        RECT  89.52 25.836 89.544 25.92 ;
    END
  END b_own_out[20]
  PIN b_own_out[210]
    DIRECTION OUTPUT ;
    USE SIGNAL ;
    PORT
      LAYER M5 ;
        RECT  128.4 25.836 128.424 25.92 ;
    END
  END b_own_out[210]
  PIN b_own_out[211]
    DIRECTION OUTPUT ;
    USE SIGNAL ;
    PORT
      LAYER M3 ;
        RECT  128.628 25.882 128.646 25.92 ;
    END
  END b_own_out[211]
  PIN b_own_out[212]
    DIRECTION OUTPUT ;
    USE SIGNAL ;
    PORT
      LAYER M5 ;
        RECT  128.784 25.836 128.808 25.92 ;
    END
  END b_own_out[212]
  PIN b_own_out[213]
    DIRECTION OUTPUT ;
    USE SIGNAL ;
    PORT
      LAYER M3 ;
        RECT  129.024 25.882 129.042 25.92 ;
    END
  END b_own_out[213]
  PIN b_own_out[214]
    DIRECTION OUTPUT ;
    USE SIGNAL ;
    PORT
      LAYER M5 ;
        RECT  129.264 25.836 129.288 25.92 ;
    END
  END b_own_out[214]
  PIN b_own_out[215]
    DIRECTION OUTPUT ;
    USE SIGNAL ;
    PORT
      LAYER M3 ;
        RECT  129.384 25.882 129.402 25.92 ;
    END
  END b_own_out[215]
  PIN b_own_out[216]
    DIRECTION OUTPUT ;
    USE SIGNAL ;
    PORT
      LAYER M5 ;
        RECT  129.648 25.836 129.672 25.92 ;
    END
  END b_own_out[216]
  PIN b_own_out[217]
    DIRECTION OUTPUT ;
    USE SIGNAL ;
    PORT
      LAYER M3 ;
        RECT  129.888 25.882 129.906 25.92 ;
    END
  END b_own_out[217]
  PIN b_own_out[218]
    DIRECTION OUTPUT ;
    USE SIGNAL ;
    PORT
      LAYER M5 ;
        RECT  130.032 25.836 130.056 25.92 ;
    END
  END b_own_out[218]
  PIN b_own_out[219]
    DIRECTION OUTPUT ;
    USE SIGNAL ;
    PORT
      LAYER M3 ;
        RECT  130.248 25.882 130.266 25.92 ;
    END
  END b_own_out[219]
  PIN b_own_out[21]
    DIRECTION OUTPUT ;
    USE SIGNAL ;
    PORT
      LAYER M3 ;
        RECT  89.748 25.882 89.766 25.92 ;
    END
  END b_own_out[21]
  PIN b_own_out[220]
    DIRECTION OUTPUT ;
    USE SIGNAL ;
    PORT
      LAYER M5 ;
        RECT  130.512 25.836 130.536 25.92 ;
    END
  END b_own_out[220]
  PIN b_own_out[221]
    DIRECTION OUTPUT ;
    USE SIGNAL ;
    PORT
      LAYER M3 ;
        RECT  130.644 25.882 130.662 25.92 ;
    END
  END b_own_out[221]
  PIN b_own_out[222]
    DIRECTION OUTPUT ;
    USE SIGNAL ;
    PORT
      LAYER M5 ;
        RECT  130.896 25.836 130.92 25.92 ;
    END
  END b_own_out[222]
  PIN b_own_out[223]
    DIRECTION OUTPUT ;
    USE SIGNAL ;
    PORT
      LAYER M3 ;
        RECT  131.112 25.882 131.13 25.92 ;
    END
  END b_own_out[223]
  PIN b_own_out[224]
    DIRECTION OUTPUT ;
    USE SIGNAL ;
    PORT
      LAYER M5 ;
        RECT  131.472 25.836 131.496 25.92 ;
    END
  END b_own_out[224]
  PIN b_own_out[225]
    DIRECTION OUTPUT ;
    USE SIGNAL ;
    PORT
      LAYER M3 ;
        RECT  131.904 25.882 131.922 25.92 ;
    END
  END b_own_out[225]
  PIN b_own_out[226]
    DIRECTION OUTPUT ;
    USE SIGNAL ;
    PORT
      LAYER M5 ;
        RECT  132.24 25.836 132.264 25.92 ;
    END
  END b_own_out[226]
  PIN b_own_out[227]
    DIRECTION OUTPUT ;
    USE SIGNAL ;
    PORT
      LAYER M3 ;
        RECT  132.552 25.882 132.57 25.92 ;
    END
  END b_own_out[227]
  PIN b_own_out[228]
    DIRECTION OUTPUT ;
    USE SIGNAL ;
    PORT
      LAYER M5 ;
        RECT  133.008 25.836 133.032 25.92 ;
    END
  END b_own_out[228]
  PIN b_own_out[229]
    DIRECTION OUTPUT ;
    USE SIGNAL ;
    PORT
      LAYER M3 ;
        RECT  133.344 25.882 133.362 25.92 ;
    END
    PORT
      LAYER M3 ;
        RECT  133.344 23.999 133.362 25.901 ;
    END
  END b_own_out[229]
  PIN b_own_out[22]
    DIRECTION OUTPUT ;
    USE SIGNAL ;
    PORT
      LAYER M5 ;
        RECT  89.904 25.836 89.928 25.92 ;
    END
  END b_own_out[22]
  PIN b_own_out[230]
    DIRECTION OUTPUT ;
    USE SIGNAL ;
    PORT
      LAYER M5 ;
        RECT  133.68 25.836 133.704 25.92 ;
    END
  END b_own_out[230]
  PIN b_own_out[231]
    DIRECTION OUTPUT ;
    USE SIGNAL ;
    PORT
      LAYER M3 ;
        RECT  134.1 25.882 134.118 25.92 ;
    END
    PORT
      LAYER M3 ;
        RECT  134.1 23.933 134.118 25.901 ;
    END
  END b_own_out[231]
  PIN b_own_out[232]
    DIRECTION OUTPUT ;
    USE SIGNAL ;
    PORT
      LAYER M5 ;
        RECT  134.448 25.836 134.472 25.92 ;
    END
  END b_own_out[232]
  PIN b_own_out[233]
    DIRECTION OUTPUT ;
    USE SIGNAL ;
    PORT
      LAYER M3 ;
        RECT  134.856 25.882 134.874 25.92 ;
    END
  END b_own_out[233]
  PIN b_own_out[234]
    DIRECTION OUTPUT ;
    USE SIGNAL ;
    PORT
      LAYER M5 ;
        RECT  135.216 25.836 135.24 25.92 ;
    END
  END b_own_out[234]
  PIN b_own_out[235]
    DIRECTION OUTPUT ;
    USE SIGNAL ;
    PORT
      LAYER M3 ;
        RECT  135.54 25.882 135.558 25.92 ;
    END
  END b_own_out[235]
  PIN b_own_out[236]
    DIRECTION OUTPUT ;
    USE SIGNAL ;
    PORT
      LAYER M5 ;
        RECT  135.984 25.836 136.008 25.92 ;
    END
  END b_own_out[236]
  PIN b_own_out[237]
    DIRECTION OUTPUT ;
    USE SIGNAL ;
    PORT
      LAYER M3 ;
        RECT  136.296 25.882 136.314 25.92 ;
    END
    PORT
      LAYER M3 ;
        RECT  136.296 23.933 136.314 25.901 ;
    END
  END b_own_out[237]
  PIN b_own_out[238]
    DIRECTION OUTPUT ;
    USE SIGNAL ;
    PORT
      LAYER M5 ;
        RECT  136.656 25.836 136.68 25.92 ;
    END
  END b_own_out[238]
  PIN b_own_out[239]
    DIRECTION OUTPUT ;
    USE SIGNAL ;
    PORT
      LAYER M3 ;
        RECT  137.088 25.882 137.106 25.92 ;
    END
    PORT
      LAYER M3 ;
        RECT  137.088 25.805 137.106 25.901 ;
    END
  END b_own_out[239]
  PIN b_own_out[23]
    DIRECTION OUTPUT ;
    USE SIGNAL ;
    PORT
      LAYER M3 ;
        RECT  90.144 25.882 90.162 25.92 ;
    END
  END b_own_out[23]
  PIN b_own_out[240]
    DIRECTION OUTPUT ;
    USE SIGNAL ;
    PORT
      LAYER M5 ;
        RECT  137.424 25.836 137.448 25.92 ;
    END
  END b_own_out[240]
  PIN b_own_out[241]
    DIRECTION OUTPUT ;
    USE SIGNAL ;
    PORT
      LAYER M3 ;
        RECT  137.844 25.882 137.862 25.92 ;
    END
  END b_own_out[241]
  PIN b_own_out[242]
    DIRECTION OUTPUT ;
    USE SIGNAL ;
    PORT
      LAYER M5 ;
        RECT  138.192 25.836 138.216 25.92 ;
    END
  END b_own_out[242]
  PIN b_own_out[243]
    DIRECTION OUTPUT ;
    USE SIGNAL ;
    PORT
      LAYER M3 ;
        RECT  138.528 25.882 138.546 25.92 ;
    END
  END b_own_out[243]
  PIN b_own_out[244]
    DIRECTION OUTPUT ;
    USE SIGNAL ;
    PORT
      LAYER M5 ;
        RECT  138.96 25.836 138.984 25.92 ;
    END
  END b_own_out[244]
  PIN b_own_out[245]
    DIRECTION OUTPUT ;
    USE SIGNAL ;
    PORT
      LAYER M3 ;
        RECT  139.284 25.882 139.302 25.92 ;
    END
    PORT
      LAYER M3 ;
        RECT  139.284 23.933 139.302 25.901 ;
    END
  END b_own_out[245]
  PIN b_own_out[246]
    DIRECTION OUTPUT ;
    USE SIGNAL ;
    PORT
      LAYER M5 ;
        RECT  139.632 25.836 139.656 25.92 ;
    END
  END b_own_out[246]
  PIN b_own_out[247]
    DIRECTION OUTPUT ;
    USE SIGNAL ;
    PORT
      LAYER M3 ;
        RECT  140.04 25.882 140.058 25.92 ;
    END
    PORT
      LAYER M3 ;
        RECT  140.04 24.557 140.058 25.901 ;
    END
  END b_own_out[247]
  PIN b_own_out[248]
    DIRECTION OUTPUT ;
    USE SIGNAL ;
    PORT
      LAYER M5 ;
        RECT  140.4 25.836 140.424 25.92 ;
    END
  END b_own_out[248]
  PIN b_own_out[249]
    DIRECTION OUTPUT ;
    USE SIGNAL ;
    PORT
      LAYER M3 ;
        RECT  140.832 25.882 140.85 25.92 ;
    END
  END b_own_out[249]
  PIN b_own_out[24]
    DIRECTION OUTPUT ;
    USE SIGNAL ;
    PORT
      LAYER M5 ;
        RECT  90.384 25.836 90.408 25.92 ;
    END
  END b_own_out[24]
  PIN b_own_out[250]
    DIRECTION OUTPUT ;
    USE SIGNAL ;
    PORT
      LAYER M5 ;
        RECT  141.168 25.836 141.192 25.92 ;
    END
  END b_own_out[250]
  PIN b_own_out[251]
    DIRECTION OUTPUT ;
    USE SIGNAL ;
    PORT
      LAYER M3 ;
        RECT  141.48 25.882 141.498 25.92 ;
    END
  END b_own_out[251]
  PIN b_own_out[252]
    DIRECTION OUTPUT ;
    USE SIGNAL ;
    PORT
      LAYER M5 ;
        RECT  141.936 25.836 141.96 25.92 ;
    END
  END b_own_out[252]
  PIN b_own_out[253]
    DIRECTION OUTPUT ;
    USE SIGNAL ;
    PORT
      LAYER M3 ;
        RECT  142.272 25.882 142.29 25.92 ;
    END
    PORT
      LAYER M3 ;
        RECT  142.272 24.557 142.29 25.901 ;
    END
  END b_own_out[253]
  PIN b_own_out[254]
    DIRECTION OUTPUT ;
    USE SIGNAL ;
    PORT
      LAYER M5 ;
        RECT  142.704 25.836 142.728 25.92 ;
    END
  END b_own_out[254]
  PIN b_own_out[255]
    DIRECTION OUTPUT ;
    USE SIGNAL ;
    PORT
      LAYER M3 ;
        RECT  143.028 25.882 143.046 25.92 ;
    END
    PORT
      LAYER M3 ;
        RECT  143.028 24.557 143.046 25.901 ;
    END
  END b_own_out[255]
  PIN b_own_out[25]
    DIRECTION OUTPUT ;
    USE SIGNAL ;
    PORT
      LAYER M3 ;
        RECT  90.504 25.882 90.522 25.92 ;
    END
  END b_own_out[25]
  PIN b_own_out[26]
    DIRECTION OUTPUT ;
    USE SIGNAL ;
    PORT
      LAYER M5 ;
        RECT  90.768 25.836 90.792 25.92 ;
    END
  END b_own_out[26]
  PIN b_own_out[27]
    DIRECTION OUTPUT ;
    USE SIGNAL ;
    PORT
      LAYER M3 ;
        RECT  90.9 25.882 90.918 25.92 ;
    END
  END b_own_out[27]
  PIN b_own_out[28]
    DIRECTION OUTPUT ;
    USE SIGNAL ;
    PORT
      LAYER M5 ;
        RECT  91.152 25.836 91.176 25.92 ;
    END
  END b_own_out[28]
  PIN b_own_out[29]
    DIRECTION OUTPUT ;
    USE SIGNAL ;
    PORT
      LAYER M3 ;
        RECT  91.368 25.882 91.386 25.92 ;
    END
  END b_own_out[29]
  PIN b_own_out[2]
    DIRECTION OUTPUT ;
    USE SIGNAL ;
    PORT
      LAYER M5 ;
        RECT  85.872 25.836 85.896 25.92 ;
    END
  END b_own_out[2]
  PIN b_own_out[30]
    DIRECTION OUTPUT ;
    USE SIGNAL ;
    PORT
      LAYER M5 ;
        RECT  91.536 25.836 91.56 25.92 ;
    END
  END b_own_out[30]
  PIN b_own_out[31]
    DIRECTION OUTPUT ;
    USE SIGNAL ;
    PORT
      LAYER M3 ;
        RECT  91.764 25.882 91.782 25.92 ;
    END
  END b_own_out[31]
  PIN b_own_out[32]
    DIRECTION OUTPUT ;
    USE SIGNAL ;
    PORT
      LAYER M5 ;
        RECT  92.016 25.836 92.04 25.92 ;
    END
  END b_own_out[32]
  PIN b_own_out[33]
    DIRECTION OUTPUT ;
    USE SIGNAL ;
    PORT
      LAYER M3 ;
        RECT  92.16 25.882 92.178 25.92 ;
    END
  END b_own_out[33]
  PIN b_own_out[34]
    DIRECTION OUTPUT ;
    USE SIGNAL ;
    PORT
      LAYER M5 ;
        RECT  92.4 25.836 92.424 25.92 ;
    END
  END b_own_out[34]
  PIN b_own_out[35]
    DIRECTION OUTPUT ;
    USE SIGNAL ;
    PORT
      LAYER M3 ;
        RECT  92.52 25.882 92.538 25.92 ;
    END
  END b_own_out[35]
  PIN b_own_out[36]
    DIRECTION OUTPUT ;
    USE SIGNAL ;
    PORT
      LAYER M5 ;
        RECT  92.784 25.836 92.808 25.92 ;
    END
  END b_own_out[36]
  PIN b_own_out[37]
    DIRECTION OUTPUT ;
    USE SIGNAL ;
    PORT
      LAYER M3 ;
        RECT  93.024 25.882 93.042 25.92 ;
    END
  END b_own_out[37]
  PIN b_own_out[38]
    DIRECTION OUTPUT ;
    USE SIGNAL ;
    PORT
      LAYER M5 ;
        RECT  93.168 25.836 93.192 25.92 ;
    END
  END b_own_out[38]
  PIN b_own_out[39]
    DIRECTION OUTPUT ;
    USE SIGNAL ;
    PORT
      LAYER M3 ;
        RECT  93.384 25.882 93.402 25.92 ;
    END
  END b_own_out[39]
  PIN b_own_out[3]
    DIRECTION OUTPUT ;
    USE SIGNAL ;
    PORT
      LAYER M3 ;
        RECT  86.004 25.882 86.022 25.92 ;
    END
  END b_own_out[3]
  PIN b_own_out[40]
    DIRECTION OUTPUT ;
    USE SIGNAL ;
    PORT
      LAYER M5 ;
        RECT  93.648 25.836 93.672 25.92 ;
    END
  END b_own_out[40]
  PIN b_own_out[41]
    DIRECTION OUTPUT ;
    USE SIGNAL ;
    PORT
      LAYER M3 ;
        RECT  93.78 25.882 93.798 25.92 ;
    END
  END b_own_out[41]
  PIN b_own_out[42]
    DIRECTION OUTPUT ;
    USE SIGNAL ;
    PORT
      LAYER M5 ;
        RECT  94.032 25.836 94.056 25.92 ;
    END
  END b_own_out[42]
  PIN b_own_out[43]
    DIRECTION OUTPUT ;
    USE SIGNAL ;
    PORT
      LAYER M3 ;
        RECT  94.248 25.882 94.266 25.92 ;
    END
  END b_own_out[43]
  PIN b_own_out[44]
    DIRECTION OUTPUT ;
    USE SIGNAL ;
    PORT
      LAYER M5 ;
        RECT  94.416 25.836 94.44 25.92 ;
    END
  END b_own_out[44]
  PIN b_own_out[45]
    DIRECTION OUTPUT ;
    USE SIGNAL ;
    PORT
      LAYER M3 ;
        RECT  94.644 25.882 94.662 25.92 ;
    END
  END b_own_out[45]
  PIN b_own_out[46]
    DIRECTION OUTPUT ;
    USE SIGNAL ;
    PORT
      LAYER M5 ;
        RECT  94.8 25.836 94.824 25.92 ;
    END
  END b_own_out[46]
  PIN b_own_out[47]
    DIRECTION OUTPUT ;
    USE SIGNAL ;
    PORT
      LAYER M3 ;
        RECT  95.04 25.882 95.058 25.92 ;
    END
  END b_own_out[47]
  PIN b_own_out[48]
    DIRECTION OUTPUT ;
    USE SIGNAL ;
    PORT
      LAYER M5 ;
        RECT  95.28 25.836 95.304 25.92 ;
    END
  END b_own_out[48]
  PIN b_own_out[49]
    DIRECTION OUTPUT ;
    USE SIGNAL ;
    PORT
      LAYER M3 ;
        RECT  95.4 25.882 95.418 25.92 ;
    END
  END b_own_out[49]
  PIN b_own_out[4]
    DIRECTION OUTPUT ;
    USE SIGNAL ;
    PORT
      LAYER M5 ;
        RECT  86.256 25.836 86.28 25.92 ;
    END
  END b_own_out[4]
  PIN b_own_out[50]
    DIRECTION OUTPUT ;
    USE SIGNAL ;
    PORT
      LAYER M5 ;
        RECT  95.664 25.836 95.688 25.92 ;
    END
  END b_own_out[50]
  PIN b_own_out[51]
    DIRECTION OUTPUT ;
    USE SIGNAL ;
    PORT
      LAYER M3 ;
        RECT  95.904 25.882 95.922 25.92 ;
    END
  END b_own_out[51]
  PIN b_own_out[52]
    DIRECTION OUTPUT ;
    USE SIGNAL ;
    PORT
      LAYER M5 ;
        RECT  96.048 25.836 96.072 25.92 ;
    END
  END b_own_out[52]
  PIN b_own_out[53]
    DIRECTION OUTPUT ;
    USE SIGNAL ;
    PORT
      LAYER M3 ;
        RECT  96.264 25.882 96.282 25.92 ;
    END
  END b_own_out[53]
  PIN b_own_out[54]
    DIRECTION OUTPUT ;
    USE SIGNAL ;
    PORT
      LAYER M5 ;
        RECT  96.528 25.836 96.552 25.92 ;
    END
  END b_own_out[54]
  PIN b_own_out[55]
    DIRECTION OUTPUT ;
    USE SIGNAL ;
    PORT
      LAYER M3 ;
        RECT  96.66 25.882 96.678 25.92 ;
    END
  END b_own_out[55]
  PIN b_own_out[56]
    DIRECTION OUTPUT ;
    USE SIGNAL ;
    PORT
      LAYER M5 ;
        RECT  96.912 25.836 96.936 25.92 ;
    END
  END b_own_out[56]
  PIN b_own_out[57]
    DIRECTION OUTPUT ;
    USE SIGNAL ;
    PORT
      LAYER M3 ;
        RECT  97.056 25.882 97.074 25.92 ;
    END
  END b_own_out[57]
  PIN b_own_out[58]
    DIRECTION OUTPUT ;
    USE SIGNAL ;
    PORT
      LAYER M5 ;
        RECT  97.296 25.836 97.32 25.92 ;
    END
  END b_own_out[58]
  PIN b_own_out[59]
    DIRECTION OUTPUT ;
    USE SIGNAL ;
    PORT
      LAYER M3 ;
        RECT  97.524 25.882 97.542 25.92 ;
    END
  END b_own_out[59]
  PIN b_own_out[5]
    DIRECTION OUTPUT ;
    USE SIGNAL ;
    PORT
      LAYER M3 ;
        RECT  86.472 25.882 86.49 25.92 ;
    END
  END b_own_out[5]
  PIN b_own_out[60]
    DIRECTION OUTPUT ;
    USE SIGNAL ;
    PORT
      LAYER M5 ;
        RECT  97.68 25.836 97.704 25.92 ;
    END
  END b_own_out[60]
  PIN b_own_out[61]
    DIRECTION OUTPUT ;
    USE SIGNAL ;
    PORT
      LAYER M3 ;
        RECT  97.92 25.882 97.938 25.92 ;
    END
  END b_own_out[61]
  PIN b_own_out[62]
    DIRECTION OUTPUT ;
    USE SIGNAL ;
    PORT
      LAYER M5 ;
        RECT  98.16 25.836 98.184 25.92 ;
    END
  END b_own_out[62]
  PIN b_own_out[63]
    DIRECTION OUTPUT ;
    USE SIGNAL ;
    PORT
      LAYER M3 ;
        RECT  98.28 25.882 98.298 25.92 ;
    END
  END b_own_out[63]
  PIN b_own_out[64]
    DIRECTION OUTPUT ;
    USE SIGNAL ;
    PORT
      LAYER M5 ;
        RECT  98.544 25.836 98.568 25.92 ;
    END
  END b_own_out[64]
  PIN b_own_out[65]
    DIRECTION OUTPUT ;
    USE SIGNAL ;
    PORT
      LAYER M3 ;
        RECT  98.676 25.882 98.694 25.92 ;
    END
  END b_own_out[65]
  PIN b_own_out[66]
    DIRECTION OUTPUT ;
    USE SIGNAL ;
    PORT
      LAYER M5 ;
        RECT  98.928 25.836 98.952 25.92 ;
    END
  END b_own_out[66]
  PIN b_own_out[67]
    DIRECTION OUTPUT ;
    USE SIGNAL ;
    PORT
      LAYER M3 ;
        RECT  99.144 25.882 99.162 25.92 ;
    END
  END b_own_out[67]
  PIN b_own_out[68]
    DIRECTION OUTPUT ;
    USE SIGNAL ;
    PORT
      LAYER M5 ;
        RECT  99.312 25.836 99.336 25.92 ;
    END
  END b_own_out[68]
  PIN b_own_out[69]
    DIRECTION OUTPUT ;
    USE SIGNAL ;
    PORT
      LAYER M3 ;
        RECT  99.54 25.882 99.558 25.92 ;
    END
  END b_own_out[69]
  PIN b_own_out[6]
    DIRECTION OUTPUT ;
    USE SIGNAL ;
    PORT
      LAYER M5 ;
        RECT  86.64 25.836 86.664 25.92 ;
    END
  END b_own_out[6]
  PIN b_own_out[70]
    DIRECTION OUTPUT ;
    USE SIGNAL ;
    PORT
      LAYER M5 ;
        RECT  99.792 25.836 99.816 25.92 ;
    END
  END b_own_out[70]
  PIN b_own_out[71]
    DIRECTION OUTPUT ;
    USE SIGNAL ;
    PORT
      LAYER M3 ;
        RECT  99.936 25.882 99.954 25.92 ;
    END
  END b_own_out[71]
  PIN b_own_out[72]
    DIRECTION OUTPUT ;
    USE SIGNAL ;
    PORT
      LAYER M5 ;
        RECT  100.176 25.836 100.2 25.92 ;
    END
  END b_own_out[72]
  PIN b_own_out[73]
    DIRECTION OUTPUT ;
    USE SIGNAL ;
    PORT
      LAYER M3 ;
        RECT  100.404 25.882 100.422 25.92 ;
    END
  END b_own_out[73]
  PIN b_own_out[74]
    DIRECTION OUTPUT ;
    USE SIGNAL ;
    PORT
      LAYER M5 ;
        RECT  100.56 25.836 100.584 25.92 ;
    END
  END b_own_out[74]
  PIN b_own_out[75]
    DIRECTION OUTPUT ;
    USE SIGNAL ;
    PORT
      LAYER M3 ;
        RECT  100.8 25.882 100.818 25.92 ;
    END
  END b_own_out[75]
  PIN b_own_out[76]
    DIRECTION OUTPUT ;
    USE SIGNAL ;
    PORT
      LAYER M5 ;
        RECT  100.944 25.836 100.968 25.92 ;
    END
  END b_own_out[76]
  PIN b_own_out[77]
    DIRECTION OUTPUT ;
    USE SIGNAL ;
    PORT
      LAYER M3 ;
        RECT  101.16 25.882 101.178 25.92 ;
    END
  END b_own_out[77]
  PIN b_own_out[78]
    DIRECTION OUTPUT ;
    USE SIGNAL ;
    PORT
      LAYER M5 ;
        RECT  101.424 25.836 101.448 25.92 ;
    END
  END b_own_out[78]
  PIN b_own_out[79]
    DIRECTION OUTPUT ;
    USE SIGNAL ;
    PORT
      LAYER M3 ;
        RECT  101.556 25.882 101.574 25.92 ;
    END
  END b_own_out[79]
  PIN b_own_out[7]
    DIRECTION OUTPUT ;
    USE SIGNAL ;
    PORT
      LAYER M3 ;
        RECT  86.868 25.882 86.886 25.92 ;
    END
  END b_own_out[7]
  PIN b_own_out[80]
    DIRECTION OUTPUT ;
    USE SIGNAL ;
    PORT
      LAYER M5 ;
        RECT  101.808 25.836 101.832 25.92 ;
    END
  END b_own_out[80]
  PIN b_own_out[81]
    DIRECTION OUTPUT ;
    USE SIGNAL ;
    PORT
      LAYER M3 ;
        RECT  102.024 25.882 102.042 25.92 ;
    END
  END b_own_out[81]
  PIN b_own_out[82]
    DIRECTION OUTPUT ;
    USE SIGNAL ;
    PORT
      LAYER M5 ;
        RECT  102.192 25.836 102.216 25.92 ;
    END
  END b_own_out[82]
  PIN b_own_out[83]
    DIRECTION OUTPUT ;
    USE SIGNAL ;
    PORT
      LAYER M3 ;
        RECT  102.42 25.882 102.438 25.92 ;
    END
  END b_own_out[83]
  PIN b_own_out[84]
    DIRECTION OUTPUT ;
    USE SIGNAL ;
    PORT
      LAYER M5 ;
        RECT  102.576 25.836 102.6 25.92 ;
    END
  END b_own_out[84]
  PIN b_own_out[85]
    DIRECTION OUTPUT ;
    USE SIGNAL ;
    PORT
      LAYER M3 ;
        RECT  102.816 25.882 102.834 25.92 ;
    END
  END b_own_out[85]
  PIN b_own_out[86]
    DIRECTION OUTPUT ;
    USE SIGNAL ;
    PORT
      LAYER M5 ;
        RECT  103.056 25.836 103.08 25.92 ;
    END
  END b_own_out[86]
  PIN b_own_out[87]
    DIRECTION OUTPUT ;
    USE SIGNAL ;
    PORT
      LAYER M3 ;
        RECT  103.176 25.882 103.194 25.92 ;
    END
  END b_own_out[87]
  PIN b_own_out[88]
    DIRECTION OUTPUT ;
    USE SIGNAL ;
    PORT
      LAYER M5 ;
        RECT  103.44 25.836 103.464 25.92 ;
    END
  END b_own_out[88]
  PIN b_own_out[89]
    DIRECTION OUTPUT ;
    USE SIGNAL ;
    PORT
      LAYER M3 ;
        RECT  103.68 25.882 103.698 25.92 ;
    END
  END b_own_out[89]
  PIN b_own_out[8]
    DIRECTION OUTPUT ;
    USE SIGNAL ;
    PORT
      LAYER M5 ;
        RECT  87.024 25.836 87.048 25.92 ;
    END
  END b_own_out[8]
  PIN b_own_out[90]
    DIRECTION OUTPUT ;
    USE SIGNAL ;
    PORT
      LAYER M5 ;
        RECT  103.824 25.836 103.848 25.92 ;
    END
  END b_own_out[90]
  PIN b_own_out[91]
    DIRECTION OUTPUT ;
    USE SIGNAL ;
    PORT
      LAYER M3 ;
        RECT  104.04 25.882 104.058 25.92 ;
    END
  END b_own_out[91]
  PIN b_own_out[92]
    DIRECTION OUTPUT ;
    USE SIGNAL ;
    PORT
      LAYER M5 ;
        RECT  104.304 25.836 104.328 25.92 ;
    END
  END b_own_out[92]
  PIN b_own_out[93]
    DIRECTION OUTPUT ;
    USE SIGNAL ;
    PORT
      LAYER M3 ;
        RECT  104.436 25.882 104.454 25.92 ;
    END
  END b_own_out[93]
  PIN b_own_out[94]
    DIRECTION OUTPUT ;
    USE SIGNAL ;
    PORT
      LAYER M5 ;
        RECT  104.688 25.836 104.712 25.92 ;
    END
  END b_own_out[94]
  PIN b_own_out[95]
    DIRECTION OUTPUT ;
    USE SIGNAL ;
    PORT
      LAYER M3 ;
        RECT  104.832 25.882 104.85 25.92 ;
    END
  END b_own_out[95]
  PIN b_own_out[96]
    DIRECTION OUTPUT ;
    USE SIGNAL ;
    PORT
      LAYER M5 ;
        RECT  105.072 25.836 105.096 25.92 ;
    END
  END b_own_out[96]
  PIN b_own_out[97]
    DIRECTION OUTPUT ;
    USE SIGNAL ;
    PORT
      LAYER M3 ;
        RECT  105.3 25.882 105.318 25.92 ;
    END
  END b_own_out[97]
  PIN b_own_out[98]
    DIRECTION OUTPUT ;
    USE SIGNAL ;
    PORT
      LAYER M5 ;
        RECT  105.456 25.836 105.48 25.92 ;
    END
  END b_own_out[98]
  PIN b_own_out[99]
    DIRECTION OUTPUT ;
    USE SIGNAL ;
    PORT
      LAYER M3 ;
        RECT  105.696 25.882 105.714 25.92 ;
    END
  END b_own_out[99]
  PIN b_own_out[9]
    DIRECTION OUTPUT ;
    USE SIGNAL ;
    PORT
      LAYER M3 ;
        RECT  87.264 25.882 87.282 25.92 ;
    END
  END b_own_out[9]
  PIN clk
    DIRECTION INPUT ;
    USE SIGNAL ;
    PORT
      LAYER M4 ;
        RECT  0 13.008 0.084 13.032 ;
    END
    PORT
      LAYER M4 ;
        RECT  0.06 13.008 0.517 13.032 ;
    END
  END clk
  PIN flg_fault[0]
    DIRECTION INPUT ;
    USE SIGNAL ;
    PORT
      LAYER M5 ;
        RECT  1.104 0 1.128 0.084 ;
    END
  END flg_fault[0]
  PIN flg_fault[1]
    DIRECTION INPUT ;
    USE SIGNAL ;
    PORT
      LAYER M3 ;
        RECT  1.152 0 1.17 0.038 ;
    END
  END flg_fault[1]
  PIN flg_fault[2]
    DIRECTION INPUT ;
    USE SIGNAL ;
    PORT
      LAYER M5 ;
        RECT  1.2 0 1.224 0.084 ;
    END
  END flg_fault[2]
  PIN flg_fault[3]
    DIRECTION INPUT ;
    USE SIGNAL ;
    PORT
      LAYER M3 ;
        RECT  1.224 0 1.242 0.038 ;
    END
  END flg_fault[3]
  PIN flg_hnz[0]
    DIRECTION INPUT ;
    USE SIGNAL ;
    PORT
      LAYER M5 ;
        RECT  1.296 0 1.32 0.084 ;
    END
  END flg_hnz[0]
  PIN flg_hnz[1]
    DIRECTION INPUT ;
    USE SIGNAL ;
    PORT
      LAYER M3 ;
        RECT  1.332 0 1.35 0.038 ;
    END
  END flg_hnz[1]
  PIN flg_hnz[2]
    DIRECTION INPUT ;
    USE SIGNAL ;
    PORT
      LAYER M5 ;
        RECT  1.392 0 1.416 0.084 ;
    END
  END flg_hnz[2]
  PIN flg_hnz[3]
    DIRECTION INPUT ;
    USE SIGNAL ;
    PORT
      LAYER M3 ;
        RECT  1.44 0 1.458 0.038 ;
    END
  END flg_hnz[3]
  PIN hdr_c[0]
    DIRECTION INPUT ;
    USE SIGNAL ;
    PORT
      LAYER M5 ;
        RECT  1.872 0 1.896 0.084 ;
    END
  END hdr_c[0]
  PIN hdr_c[100]
    DIRECTION INPUT ;
    USE SIGNAL ;
    PORT
      LAYER M5 ;
        RECT  12.144 0 12.168 0.084 ;
    END
  END hdr_c[100]
  PIN hdr_c[101]
    DIRECTION INPUT ;
    USE SIGNAL ;
    PORT
      LAYER M3 ;
        RECT  12.276 0 12.294 0.038 ;
    END
  END hdr_c[101]
  PIN hdr_c[102]
    DIRECTION INPUT ;
    USE SIGNAL ;
    PORT
      LAYER M5 ;
        RECT  12.336 0 12.36 0.084 ;
    END
  END hdr_c[102]
  PIN hdr_c[103]
    DIRECTION INPUT ;
    USE SIGNAL ;
    PORT
      LAYER M3 ;
        RECT  12.456 0 12.474 0.038 ;
    END
  END hdr_c[103]
  PIN hdr_c[104]
    DIRECTION INPUT ;
    USE SIGNAL ;
    PORT
      LAYER M5 ;
        RECT  12.528 0 12.552 0.084 ;
    END
  END hdr_c[104]
  PIN hdr_c[105]
    DIRECTION INPUT ;
    USE SIGNAL ;
    PORT
      LAYER M3 ;
        RECT  12.672 0 12.69 0.038 ;
    END
  END hdr_c[105]
  PIN hdr_c[106]
    DIRECTION INPUT ;
    USE SIGNAL ;
    PORT
      LAYER M5 ;
        RECT  12.72 0 12.744 0.084 ;
    END
  END hdr_c[106]
  PIN hdr_c[107]
    DIRECTION INPUT ;
    USE SIGNAL ;
    PORT
      LAYER M3 ;
        RECT  12.852 0 12.87 0.038 ;
    END
  END hdr_c[107]
  PIN hdr_c[10]
    DIRECTION INPUT ;
    USE SIGNAL ;
    PORT
      LAYER M5 ;
        RECT  2.928 0 2.952 0.084 ;
    END
  END hdr_c[10]
  PIN hdr_c[11]
    DIRECTION INPUT ;
    USE SIGNAL ;
    PORT
      LAYER M3 ;
        RECT  3.06 0 3.078 0.038 ;
    END
  END hdr_c[11]
  PIN hdr_c[12]
    DIRECTION INPUT ;
    USE SIGNAL ;
    PORT
      LAYER M5 ;
        RECT  3.12 0 3.144 0.084 ;
    END
  END hdr_c[12]
  PIN hdr_c[13]
    DIRECTION INPUT ;
    USE SIGNAL ;
    PORT
      LAYER M3 ;
        RECT  3.24 0 3.258 0.038 ;
    END
  END hdr_c[13]
  PIN hdr_c[14]
    DIRECTION INPUT ;
    USE SIGNAL ;
    PORT
      LAYER M5 ;
        RECT  3.312 0 3.336 0.084 ;
    END
  END hdr_c[14]
  PIN hdr_c[15]
    DIRECTION INPUT ;
    USE SIGNAL ;
    PORT
      LAYER M3 ;
        RECT  3.456 0 3.474 0.038 ;
    END
  END hdr_c[15]
  PIN hdr_c[16]
    DIRECTION INPUT ;
    USE SIGNAL ;
    PORT
      LAYER M5 ;
        RECT  3.504 0 3.528 0.084 ;
    END
  END hdr_c[16]
  PIN hdr_c[17]
    DIRECTION INPUT ;
    USE SIGNAL ;
    PORT
      LAYER M3 ;
        RECT  3.636 0 3.654 0.038 ;
    END
  END hdr_c[17]
  PIN hdr_c[18]
    DIRECTION INPUT ;
    USE SIGNAL ;
    PORT
      LAYER M5 ;
        RECT  3.792 0 3.816 0.084 ;
    END
  END hdr_c[18]
  PIN hdr_c[19]
    DIRECTION INPUT ;
    USE SIGNAL ;
    PORT
      LAYER M3 ;
        RECT  3.816 0 3.834 0.038 ;
    END
  END hdr_c[19]
  PIN hdr_c[1]
    DIRECTION INPUT ;
    USE SIGNAL ;
    PORT
      LAYER M3 ;
        RECT  2.016 0 2.034 0.038 ;
    END
  END hdr_c[1]
  PIN hdr_c[20]
    DIRECTION INPUT ;
    USE SIGNAL ;
    PORT
      LAYER M5 ;
        RECT  3.984 0 4.008 0.084 ;
    END
  END hdr_c[20]
  PIN hdr_c[21]
    DIRECTION INPUT ;
    USE SIGNAL ;
    PORT
      LAYER M3 ;
        RECT  4.032 0 4.05 0.038 ;
    END
  END hdr_c[21]
  PIN hdr_c[22]
    DIRECTION INPUT ;
    USE SIGNAL ;
    PORT
      LAYER M5 ;
        RECT  4.176 0 4.2 0.084 ;
    END
  END hdr_c[22]
  PIN hdr_c[23]
    DIRECTION INPUT ;
    USE SIGNAL ;
    PORT
      LAYER M3 ;
        RECT  4.212 0 4.23 0.038 ;
    END
  END hdr_c[23]
  PIN hdr_c[24]
    DIRECTION INPUT ;
    USE SIGNAL ;
    PORT
      LAYER M5 ;
        RECT  4.368 0 4.392 0.084 ;
    END
  END hdr_c[24]
  PIN hdr_c[25]
    DIRECTION INPUT ;
    USE SIGNAL ;
    PORT
      LAYER M3 ;
        RECT  4.5 0 4.518 0.038 ;
    END
  END hdr_c[25]
  PIN hdr_c[26]
    DIRECTION INPUT ;
    USE SIGNAL ;
    PORT
      LAYER M5 ;
        RECT  4.56 0 4.584 0.084 ;
    END
  END hdr_c[26]
  PIN hdr_c[27]
    DIRECTION INPUT ;
    USE SIGNAL ;
    PORT
      LAYER M3 ;
        RECT  4.68 0 4.698 0.038 ;
    END
  END hdr_c[27]
  PIN hdr_c[28]
    DIRECTION INPUT ;
    USE SIGNAL ;
    PORT
      LAYER M5 ;
        RECT  4.752 0 4.776 0.084 ;
    END
  END hdr_c[28]
  PIN hdr_c[29]
    DIRECTION INPUT ;
    USE SIGNAL ;
    PORT
      LAYER M3 ;
        RECT  4.896 0 4.914 0.038 ;
    END
  END hdr_c[29]
  PIN hdr_c[2]
    DIRECTION INPUT ;
    USE SIGNAL ;
    PORT
      LAYER M5 ;
        RECT  2.064 0 2.088 0.084 ;
    END
  END hdr_c[2]
  PIN hdr_c[30]
    DIRECTION INPUT ;
    USE SIGNAL ;
    PORT
      LAYER M5 ;
        RECT  4.944 0 4.968 0.084 ;
    END
  END hdr_c[30]
  PIN hdr_c[31]
    DIRECTION INPUT ;
    USE SIGNAL ;
    PORT
      LAYER M3 ;
        RECT  5.076 0 5.094 0.038 ;
    END
  END hdr_c[31]
  PIN hdr_c[32]
    DIRECTION INPUT ;
    USE SIGNAL ;
    PORT
      LAYER M5 ;
        RECT  5.136 0 5.16 0.084 ;
    END
  END hdr_c[32]
  PIN hdr_c[33]
    DIRECTION INPUT ;
    USE SIGNAL ;
    PORT
      LAYER M3 ;
        RECT  5.256 0 5.274 0.038 ;
    END
  END hdr_c[33]
  PIN hdr_c[34]
    DIRECTION INPUT ;
    USE SIGNAL ;
    PORT
      LAYER M5 ;
        RECT  5.424 0 5.448 0.084 ;
    END
  END hdr_c[34]
  PIN hdr_c[35]
    DIRECTION INPUT ;
    USE SIGNAL ;
    PORT
      LAYER M3 ;
        RECT  5.472 0 5.49 0.038 ;
    END
  END hdr_c[35]
  PIN hdr_c[36]
    DIRECTION INPUT ;
    USE SIGNAL ;
    PORT
      LAYER M5 ;
        RECT  5.616 0 5.64 0.084 ;
    END
  END hdr_c[36]
  PIN hdr_c[37]
    DIRECTION INPUT ;
    USE SIGNAL ;
    PORT
      LAYER M3 ;
        RECT  5.652 0 5.67 0.038 ;
    END
  END hdr_c[37]
  PIN hdr_c[38]
    DIRECTION INPUT ;
    USE SIGNAL ;
    PORT
      LAYER M5 ;
        RECT  5.808 0 5.832 0.084 ;
    END
  END hdr_c[38]
  PIN hdr_c[39]
    DIRECTION INPUT ;
    USE SIGNAL ;
    PORT
      LAYER M3 ;
        RECT  5.832 0 5.85 0.038 ;
    END
  END hdr_c[39]
  PIN hdr_c[3]
    DIRECTION INPUT ;
    USE SIGNAL ;
    PORT
      LAYER M3 ;
        RECT  2.196 0 2.214 0.038 ;
    END
  END hdr_c[3]
  PIN hdr_c[40]
    DIRECTION INPUT ;
    USE SIGNAL ;
    PORT
      LAYER M5 ;
        RECT  6 0 6.024 0.084 ;
    END
  END hdr_c[40]
  PIN hdr_c[41]
    DIRECTION INPUT ;
    USE SIGNAL ;
    PORT
      LAYER M3 ;
        RECT  6.12 0 6.138 0.038 ;
    END
  END hdr_c[41]
  PIN hdr_c[42]
    DIRECTION INPUT ;
    USE SIGNAL ;
    PORT
      LAYER M5 ;
        RECT  6.192 0 6.216 0.084 ;
    END
  END hdr_c[42]
  PIN hdr_c[43]
    DIRECTION INPUT ;
    USE SIGNAL ;
    PORT
      LAYER M3 ;
        RECT  6.336 0 6.354 0.038 ;
    END
  END hdr_c[43]
  PIN hdr_c[44]
    DIRECTION INPUT ;
    USE SIGNAL ;
    PORT
      LAYER M5 ;
        RECT  6.384 0 6.408 0.084 ;
    END
  END hdr_c[44]
  PIN hdr_c[45]
    DIRECTION INPUT ;
    USE SIGNAL ;
    PORT
      LAYER M3 ;
        RECT  6.516 0 6.534 0.038 ;
    END
  END hdr_c[45]
  PIN hdr_c[46]
    DIRECTION INPUT ;
    USE SIGNAL ;
    PORT
      LAYER M5 ;
        RECT  6.576 0 6.6 0.084 ;
    END
  END hdr_c[46]
  PIN hdr_c[47]
    DIRECTION INPUT ;
    USE SIGNAL ;
    PORT
      LAYER M3 ;
        RECT  6.696 0 6.714 0.038 ;
    END
  END hdr_c[47]
  PIN hdr_c[48]
    DIRECTION INPUT ;
    USE SIGNAL ;
    PORT
      LAYER M5 ;
        RECT  6.864 0 6.888 0.084 ;
    END
  END hdr_c[48]
  PIN hdr_c[49]
    DIRECTION INPUT ;
    USE SIGNAL ;
    PORT
      LAYER M3 ;
        RECT  6.912 0 6.93 0.038 ;
    END
  END hdr_c[49]
  PIN hdr_c[4]
    DIRECTION INPUT ;
    USE SIGNAL ;
    PORT
      LAYER M5 ;
        RECT  2.352 0 2.376 0.084 ;
    END
  END hdr_c[4]
  PIN hdr_c[50]
    DIRECTION INPUT ;
    USE SIGNAL ;
    PORT
      LAYER M5 ;
        RECT  7.056 0 7.08 0.084 ;
    END
  END hdr_c[50]
  PIN hdr_c[51]
    DIRECTION INPUT ;
    USE SIGNAL ;
    PORT
      LAYER M3 ;
        RECT  7.092 0 7.11 0.038 ;
    END
  END hdr_c[51]
  PIN hdr_c[52]
    DIRECTION INPUT ;
    USE SIGNAL ;
    PORT
      LAYER M5 ;
        RECT  7.248 0 7.272 0.084 ;
    END
  END hdr_c[52]
  PIN hdr_c[53]
    DIRECTION INPUT ;
    USE SIGNAL ;
    PORT
      LAYER M3 ;
        RECT  7.272 0 7.29 0.038 ;
    END
  END hdr_c[53]
  PIN hdr_c[54]
    DIRECTION INPUT ;
    USE SIGNAL ;
    PORT
      LAYER M5 ;
        RECT  7.44 0 7.464 0.084 ;
    END
  END hdr_c[54]
  PIN hdr_c[55]
    DIRECTION INPUT ;
    USE SIGNAL ;
    PORT
      LAYER M3 ;
        RECT  7.56 0 7.578 0.038 ;
    END
  END hdr_c[55]
  PIN hdr_c[56]
    DIRECTION INPUT ;
    USE SIGNAL ;
    PORT
      LAYER M5 ;
        RECT  7.632 0 7.656 0.084 ;
    END
  END hdr_c[56]
  PIN hdr_c[57]
    DIRECTION INPUT ;
    USE SIGNAL ;
    PORT
      LAYER M3 ;
        RECT  7.776 0 7.794 0.038 ;
    END
  END hdr_c[57]
  PIN hdr_c[58]
    DIRECTION INPUT ;
    USE SIGNAL ;
    PORT
      LAYER M5 ;
        RECT  7.824 0 7.848 0.084 ;
    END
  END hdr_c[58]
  PIN hdr_c[59]
    DIRECTION INPUT ;
    USE SIGNAL ;
    PORT
      LAYER M3 ;
        RECT  7.956 0 7.974 0.038 ;
    END
  END hdr_c[59]
  PIN hdr_c[5]
    DIRECTION INPUT ;
    USE SIGNAL ;
    PORT
      LAYER M3 ;
        RECT  2.376 0 2.394 0.038 ;
    END
  END hdr_c[5]
  PIN hdr_c[60]
    DIRECTION INPUT ;
    USE SIGNAL ;
    PORT
      LAYER M5 ;
        RECT  8.016 0 8.04 0.084 ;
    END
  END hdr_c[60]
  PIN hdr_c[61]
    DIRECTION INPUT ;
    USE SIGNAL ;
    PORT
      LAYER M3 ;
        RECT  8.136 0 8.154 0.038 ;
    END
  END hdr_c[61]
  PIN hdr_c[62]
    DIRECTION INPUT ;
    USE SIGNAL ;
    PORT
      LAYER M5 ;
        RECT  8.208 0 8.232 0.084 ;
    END
  END hdr_c[62]
  PIN hdr_c[63]
    DIRECTION INPUT ;
    USE SIGNAL ;
    PORT
      LAYER M3 ;
        RECT  8.352 0 8.37 0.038 ;
    END
  END hdr_c[63]
  PIN hdr_c[64]
    DIRECTION INPUT ;
    USE SIGNAL ;
    PORT
      LAYER M5 ;
        RECT  8.496 0 8.52 0.084 ;
    END
  END hdr_c[64]
  PIN hdr_c[65]
    DIRECTION INPUT ;
    USE SIGNAL ;
    PORT
      LAYER M3 ;
        RECT  8.532 0 8.55 0.038 ;
    END
  END hdr_c[65]
  PIN hdr_c[66]
    DIRECTION INPUT ;
    USE SIGNAL ;
    PORT
      LAYER M5 ;
        RECT  8.688 0 8.712 0.084 ;
    END
  END hdr_c[66]
  PIN hdr_c[67]
    DIRECTION INPUT ;
    USE SIGNAL ;
    PORT
      LAYER M3 ;
        RECT  8.712 0 8.73 0.038 ;
    END
  END hdr_c[67]
  PIN hdr_c[68]
    DIRECTION INPUT ;
    USE SIGNAL ;
    PORT
      LAYER M5 ;
        RECT  8.88 0 8.904 0.084 ;
    END
  END hdr_c[68]
  PIN hdr_c[69]
    DIRECTION INPUT ;
    USE SIGNAL ;
    PORT
      LAYER M3 ;
        RECT  8.928 0 8.946 0.038 ;
    END
  END hdr_c[69]
  PIN hdr_c[6]
    DIRECTION INPUT ;
    USE SIGNAL ;
    PORT
      LAYER M5 ;
        RECT  2.544 0 2.568 0.084 ;
    END
  END hdr_c[6]
  PIN hdr_c[70]
    DIRECTION INPUT ;
    USE SIGNAL ;
    PORT
      LAYER M5 ;
        RECT  9.072 0 9.096 0.084 ;
    END
  END hdr_c[70]
  PIN hdr_c[71]
    DIRECTION INPUT ;
    USE SIGNAL ;
    PORT
      LAYER M3 ;
        RECT  9.216 0 9.234 0.038 ;
    END
  END hdr_c[71]
  PIN hdr_c[72]
    DIRECTION INPUT ;
    USE SIGNAL ;
    PORT
      LAYER M5 ;
        RECT  9.264 0 9.288 0.084 ;
    END
  END hdr_c[72]
  PIN hdr_c[73]
    DIRECTION INPUT ;
    USE SIGNAL ;
    PORT
      LAYER M3 ;
        RECT  9.396 0 9.414 0.038 ;
    END
  END hdr_c[73]
  PIN hdr_c[74]
    DIRECTION INPUT ;
    USE SIGNAL ;
    PORT
      LAYER M5 ;
        RECT  9.456 0 9.48 0.084 ;
    END
  END hdr_c[74]
  PIN hdr_c[75]
    DIRECTION INPUT ;
    USE SIGNAL ;
    PORT
      LAYER M3 ;
        RECT  9.576 0 9.594 0.038 ;
    END
  END hdr_c[75]
  PIN hdr_c[76]
    DIRECTION INPUT ;
    USE SIGNAL ;
    PORT
      LAYER M5 ;
        RECT  9.648 0 9.672 0.084 ;
    END
  END hdr_c[76]
  PIN hdr_c[77]
    DIRECTION INPUT ;
    USE SIGNAL ;
    PORT
      LAYER M3 ;
        RECT  9.792 0 9.81 0.038 ;
    END
  END hdr_c[77]
  PIN hdr_c[78]
    DIRECTION INPUT ;
    USE SIGNAL ;
    PORT
      LAYER M5 ;
        RECT  9.936 0 9.96 0.084 ;
    END
  END hdr_c[78]
  PIN hdr_c[79]
    DIRECTION INPUT ;
    USE SIGNAL ;
    PORT
      LAYER M3 ;
        RECT  9.972 0 9.99 0.038 ;
    END
  END hdr_c[79]
  PIN hdr_c[7]
    DIRECTION INPUT ;
    USE SIGNAL ;
    PORT
      LAYER M3 ;
        RECT  2.592 0 2.61 0.038 ;
    END
  END hdr_c[7]
  PIN hdr_c[80]
    DIRECTION INPUT ;
    USE SIGNAL ;
    PORT
      LAYER M5 ;
        RECT  10.128 0 10.152 0.084 ;
    END
  END hdr_c[80]
  PIN hdr_c[81]
    DIRECTION INPUT ;
    USE SIGNAL ;
    PORT
      LAYER M3 ;
        RECT  10.152 0 10.17 0.038 ;
    END
  END hdr_c[81]
  PIN hdr_c[82]
    DIRECTION INPUT ;
    USE SIGNAL ;
    PORT
      LAYER M5 ;
        RECT  10.32 0 10.344 0.084 ;
    END
  END hdr_c[82]
  PIN hdr_c[83]
    DIRECTION INPUT ;
    USE SIGNAL ;
    PORT
      LAYER M3 ;
        RECT  10.368 0 10.386 0.038 ;
    END
  END hdr_c[83]
  PIN hdr_c[84]
    DIRECTION INPUT ;
    USE SIGNAL ;
    PORT
      LAYER M5 ;
        RECT  10.512 0 10.536 0.084 ;
    END
  END hdr_c[84]
  PIN hdr_c[85]
    DIRECTION INPUT ;
    USE SIGNAL ;
    PORT
      LAYER M3 ;
        RECT  10.548 0 10.566 0.038 ;
    END
  END hdr_c[85]
  PIN hdr_c[86]
    DIRECTION INPUT ;
    USE SIGNAL ;
    PORT
      LAYER M5 ;
        RECT  10.704 0 10.728 0.084 ;
    END
  END hdr_c[86]
  PIN hdr_c[87]
    DIRECTION INPUT ;
    USE SIGNAL ;
    PORT
      LAYER M3 ;
        RECT  10.836 0 10.854 0.038 ;
    END
  END hdr_c[87]
  PIN hdr_c[88]
    DIRECTION INPUT ;
    USE SIGNAL ;
    PORT
      LAYER M5 ;
        RECT  10.896 0 10.92 0.084 ;
    END
  END hdr_c[88]
  PIN hdr_c[89]
    DIRECTION INPUT ;
    USE SIGNAL ;
    PORT
      LAYER M3 ;
        RECT  11.016 0 11.034 0.038 ;
    END
  END hdr_c[89]
  PIN hdr_c[8]
    DIRECTION INPUT ;
    USE SIGNAL ;
    PORT
      LAYER M5 ;
        RECT  2.736 0 2.76 0.084 ;
    END
  END hdr_c[8]
  PIN hdr_c[90]
    DIRECTION INPUT ;
    USE SIGNAL ;
    PORT
      LAYER M5 ;
        RECT  11.088 0 11.112 0.084 ;
    END
  END hdr_c[90]
  PIN hdr_c[91]
    DIRECTION INPUT ;
    USE SIGNAL ;
    PORT
      LAYER M3 ;
        RECT  11.232 0 11.25 0.038 ;
    END
  END hdr_c[91]
  PIN hdr_c[92]
    DIRECTION INPUT ;
    USE SIGNAL ;
    PORT
      LAYER M5 ;
        RECT  11.28 0 11.304 0.084 ;
    END
  END hdr_c[92]
  PIN hdr_c[93]
    DIRECTION INPUT ;
    USE SIGNAL ;
    PORT
      LAYER M3 ;
        RECT  11.412 0 11.43 0.038 ;
    END
  END hdr_c[93]
  PIN hdr_c[94]
    DIRECTION INPUT ;
    USE SIGNAL ;
    PORT
      LAYER M5 ;
        RECT  11.568 0 11.592 0.084 ;
    END
  END hdr_c[94]
  PIN hdr_c[95]
    DIRECTION INPUT ;
    USE SIGNAL ;
    PORT
      LAYER M3 ;
        RECT  11.592 0 11.61 0.038 ;
    END
  END hdr_c[95]
  PIN hdr_c[96]
    DIRECTION INPUT ;
    USE SIGNAL ;
    PORT
      LAYER M5 ;
        RECT  11.76 0 11.784 0.084 ;
    END
  END hdr_c[96]
  PIN hdr_c[97]
    DIRECTION INPUT ;
    USE SIGNAL ;
    PORT
      LAYER M3 ;
        RECT  11.808 0 11.826 0.038 ;
    END
  END hdr_c[97]
  PIN hdr_c[98]
    DIRECTION INPUT ;
    USE SIGNAL ;
    PORT
      LAYER M5 ;
        RECT  11.952 0 11.976 0.084 ;
    END
  END hdr_c[98]
  PIN hdr_c[99]
    DIRECTION INPUT ;
    USE SIGNAL ;
    PORT
      LAYER M3 ;
        RECT  11.988 0 12.006 0.038 ;
    END
  END hdr_c[99]
  PIN hdr_c[9]
    DIRECTION INPUT ;
    USE SIGNAL ;
    PORT
      LAYER M3 ;
        RECT  2.772 0 2.79 0.038 ;
    END
  END hdr_c[9]
  PIN hdr_out[0]
    DIRECTION OUTPUT ;
    USE SIGNAL ;
    PORT
      LAYER M5 ;
        RECT  1.872 25.836 1.896 25.92 ;
    END
  END hdr_out[0]
  PIN hdr_out[100]
    DIRECTION OUTPUT ;
    USE SIGNAL ;
    PORT
      LAYER M5 ;
        RECT  12.144 25.836 12.168 25.92 ;
    END
  END hdr_out[100]
  PIN hdr_out[101]
    DIRECTION OUTPUT ;
    USE SIGNAL ;
    PORT
      LAYER M3 ;
        RECT  12.276 25.882 12.294 25.92 ;
    END
  END hdr_out[101]
  PIN hdr_out[102]
    DIRECTION OUTPUT ;
    USE SIGNAL ;
    PORT
      LAYER M5 ;
        RECT  12.336 25.836 12.36 25.92 ;
    END
  END hdr_out[102]
  PIN hdr_out[103]
    DIRECTION OUTPUT ;
    USE SIGNAL ;
    PORT
      LAYER M3 ;
        RECT  12.456 25.882 12.474 25.92 ;
    END
  END hdr_out[103]
  PIN hdr_out[104]
    DIRECTION OUTPUT ;
    USE SIGNAL ;
    PORT
      LAYER M5 ;
        RECT  12.528 25.836 12.552 25.92 ;
    END
  END hdr_out[104]
  PIN hdr_out[105]
    DIRECTION OUTPUT ;
    USE SIGNAL ;
    PORT
      LAYER M3 ;
        RECT  12.672 25.882 12.69 25.92 ;
    END
  END hdr_out[105]
  PIN hdr_out[106]
    DIRECTION OUTPUT ;
    USE SIGNAL ;
    PORT
      LAYER M5 ;
        RECT  12.72 25.836 12.744 25.92 ;
    END
  END hdr_out[106]
  PIN hdr_out[107]
    DIRECTION OUTPUT ;
    USE SIGNAL ;
    PORT
      LAYER M3 ;
        RECT  12.852 25.882 12.87 25.92 ;
    END
  END hdr_out[107]
  PIN hdr_out[10]
    DIRECTION OUTPUT ;
    USE SIGNAL ;
    PORT
      LAYER M5 ;
        RECT  2.928 25.836 2.952 25.92 ;
    END
  END hdr_out[10]
  PIN hdr_out[11]
    DIRECTION OUTPUT ;
    USE SIGNAL ;
    PORT
      LAYER M3 ;
        RECT  3.06 25.882 3.078 25.92 ;
    END
  END hdr_out[11]
  PIN hdr_out[12]
    DIRECTION OUTPUT ;
    USE SIGNAL ;
    PORT
      LAYER M5 ;
        RECT  3.12 25.836 3.144 25.92 ;
    END
  END hdr_out[12]
  PIN hdr_out[13]
    DIRECTION OUTPUT ;
    USE SIGNAL ;
    PORT
      LAYER M3 ;
        RECT  3.24 25.882 3.258 25.92 ;
    END
  END hdr_out[13]
  PIN hdr_out[14]
    DIRECTION OUTPUT ;
    USE SIGNAL ;
    PORT
      LAYER M5 ;
        RECT  3.312 25.836 3.336 25.92 ;
    END
  END hdr_out[14]
  PIN hdr_out[15]
    DIRECTION OUTPUT ;
    USE SIGNAL ;
    PORT
      LAYER M3 ;
        RECT  3.456 25.882 3.474 25.92 ;
    END
  END hdr_out[15]
  PIN hdr_out[16]
    DIRECTION OUTPUT ;
    USE SIGNAL ;
    PORT
      LAYER M5 ;
        RECT  3.504 25.836 3.528 25.92 ;
    END
  END hdr_out[16]
  PIN hdr_out[17]
    DIRECTION OUTPUT ;
    USE SIGNAL ;
    PORT
      LAYER M3 ;
        RECT  3.636 25.882 3.654 25.92 ;
    END
  END hdr_out[17]
  PIN hdr_out[18]
    DIRECTION OUTPUT ;
    USE SIGNAL ;
    PORT
      LAYER M5 ;
        RECT  3.792 25.836 3.816 25.92 ;
    END
  END hdr_out[18]
  PIN hdr_out[19]
    DIRECTION OUTPUT ;
    USE SIGNAL ;
    PORT
      LAYER M3 ;
        RECT  3.816 25.882 3.834 25.92 ;
    END
  END hdr_out[19]
  PIN hdr_out[1]
    DIRECTION OUTPUT ;
    USE SIGNAL ;
    PORT
      LAYER M3 ;
        RECT  2.016 25.882 2.034 25.92 ;
    END
  END hdr_out[1]
  PIN hdr_out[20]
    DIRECTION OUTPUT ;
    USE SIGNAL ;
    PORT
      LAYER M5 ;
        RECT  3.984 25.836 4.008 25.92 ;
    END
  END hdr_out[20]
  PIN hdr_out[21]
    DIRECTION OUTPUT ;
    USE SIGNAL ;
    PORT
      LAYER M3 ;
        RECT  4.032 25.882 4.05 25.92 ;
    END
  END hdr_out[21]
  PIN hdr_out[22]
    DIRECTION OUTPUT ;
    USE SIGNAL ;
    PORT
      LAYER M5 ;
        RECT  4.176 25.836 4.2 25.92 ;
    END
  END hdr_out[22]
  PIN hdr_out[23]
    DIRECTION OUTPUT ;
    USE SIGNAL ;
    PORT
      LAYER M3 ;
        RECT  4.212 25.882 4.23 25.92 ;
    END
  END hdr_out[23]
  PIN hdr_out[24]
    DIRECTION OUTPUT ;
    USE SIGNAL ;
    PORT
      LAYER M5 ;
        RECT  4.368 25.836 4.392 25.92 ;
    END
  END hdr_out[24]
  PIN hdr_out[25]
    DIRECTION OUTPUT ;
    USE SIGNAL ;
    PORT
      LAYER M3 ;
        RECT  4.5 25.882 4.518 25.92 ;
    END
  END hdr_out[25]
  PIN hdr_out[26]
    DIRECTION OUTPUT ;
    USE SIGNAL ;
    PORT
      LAYER M5 ;
        RECT  4.56 25.836 4.584 25.92 ;
    END
  END hdr_out[26]
  PIN hdr_out[27]
    DIRECTION OUTPUT ;
    USE SIGNAL ;
    PORT
      LAYER M3 ;
        RECT  4.68 25.882 4.698 25.92 ;
    END
  END hdr_out[27]
  PIN hdr_out[28]
    DIRECTION OUTPUT ;
    USE SIGNAL ;
    PORT
      LAYER M5 ;
        RECT  4.752 25.836 4.776 25.92 ;
    END
  END hdr_out[28]
  PIN hdr_out[29]
    DIRECTION OUTPUT ;
    USE SIGNAL ;
    PORT
      LAYER M3 ;
        RECT  4.896 25.882 4.914 25.92 ;
    END
  END hdr_out[29]
  PIN hdr_out[2]
    DIRECTION OUTPUT ;
    USE SIGNAL ;
    PORT
      LAYER M5 ;
        RECT  2.064 25.836 2.088 25.92 ;
    END
  END hdr_out[2]
  PIN hdr_out[30]
    DIRECTION OUTPUT ;
    USE SIGNAL ;
    PORT
      LAYER M5 ;
        RECT  4.944 25.836 4.968 25.92 ;
    END
  END hdr_out[30]
  PIN hdr_out[31]
    DIRECTION OUTPUT ;
    USE SIGNAL ;
    PORT
      LAYER M3 ;
        RECT  5.076 25.882 5.094 25.92 ;
    END
  END hdr_out[31]
  PIN hdr_out[32]
    DIRECTION OUTPUT ;
    USE SIGNAL ;
    PORT
      LAYER M5 ;
        RECT  5.136 25.836 5.16 25.92 ;
    END
  END hdr_out[32]
  PIN hdr_out[33]
    DIRECTION OUTPUT ;
    USE SIGNAL ;
    PORT
      LAYER M3 ;
        RECT  5.256 25.882 5.274 25.92 ;
    END
  END hdr_out[33]
  PIN hdr_out[34]
    DIRECTION OUTPUT ;
    USE SIGNAL ;
    PORT
      LAYER M5 ;
        RECT  5.424 25.836 5.448 25.92 ;
    END
  END hdr_out[34]
  PIN hdr_out[35]
    DIRECTION OUTPUT ;
    USE SIGNAL ;
    PORT
      LAYER M3 ;
        RECT  5.472 25.882 5.49 25.92 ;
    END
  END hdr_out[35]
  PIN hdr_out[36]
    DIRECTION OUTPUT ;
    USE SIGNAL ;
    PORT
      LAYER M5 ;
        RECT  5.616 25.836 5.64 25.92 ;
    END
  END hdr_out[36]
  PIN hdr_out[37]
    DIRECTION OUTPUT ;
    USE SIGNAL ;
    PORT
      LAYER M3 ;
        RECT  5.652 25.882 5.67 25.92 ;
    END
  END hdr_out[37]
  PIN hdr_out[38]
    DIRECTION OUTPUT ;
    USE SIGNAL ;
    PORT
      LAYER M5 ;
        RECT  5.808 25.836 5.832 25.92 ;
    END
  END hdr_out[38]
  PIN hdr_out[39]
    DIRECTION OUTPUT ;
    USE SIGNAL ;
    PORT
      LAYER M3 ;
        RECT  5.832 25.882 5.85 25.92 ;
    END
  END hdr_out[39]
  PIN hdr_out[3]
    DIRECTION OUTPUT ;
    USE SIGNAL ;
    PORT
      LAYER M3 ;
        RECT  2.196 25.882 2.214 25.92 ;
    END
  END hdr_out[3]
  PIN hdr_out[40]
    DIRECTION OUTPUT ;
    USE SIGNAL ;
    PORT
      LAYER M5 ;
        RECT  6 25.836 6.024 25.92 ;
    END
  END hdr_out[40]
  PIN hdr_out[41]
    DIRECTION OUTPUT ;
    USE SIGNAL ;
    PORT
      LAYER M3 ;
        RECT  6.12 25.882 6.138 25.92 ;
    END
  END hdr_out[41]
  PIN hdr_out[42]
    DIRECTION OUTPUT ;
    USE SIGNAL ;
    PORT
      LAYER M5 ;
        RECT  6.192 25.836 6.216 25.92 ;
    END
  END hdr_out[42]
  PIN hdr_out[43]
    DIRECTION OUTPUT ;
    USE SIGNAL ;
    PORT
      LAYER M3 ;
        RECT  6.336 25.882 6.354 25.92 ;
    END
  END hdr_out[43]
  PIN hdr_out[44]
    DIRECTION OUTPUT ;
    USE SIGNAL ;
    PORT
      LAYER M5 ;
        RECT  6.384 25.836 6.408 25.92 ;
    END
  END hdr_out[44]
  PIN hdr_out[45]
    DIRECTION OUTPUT ;
    USE SIGNAL ;
    PORT
      LAYER M3 ;
        RECT  6.516 25.882 6.534 25.92 ;
    END
  END hdr_out[45]
  PIN hdr_out[46]
    DIRECTION OUTPUT ;
    USE SIGNAL ;
    PORT
      LAYER M5 ;
        RECT  6.576 25.836 6.6 25.92 ;
    END
  END hdr_out[46]
  PIN hdr_out[47]
    DIRECTION OUTPUT ;
    USE SIGNAL ;
    PORT
      LAYER M3 ;
        RECT  6.696 25.882 6.714 25.92 ;
    END
  END hdr_out[47]
  PIN hdr_out[48]
    DIRECTION OUTPUT ;
    USE SIGNAL ;
    PORT
      LAYER M5 ;
        RECT  6.864 25.836 6.888 25.92 ;
    END
  END hdr_out[48]
  PIN hdr_out[49]
    DIRECTION OUTPUT ;
    USE SIGNAL ;
    PORT
      LAYER M3 ;
        RECT  6.912 25.882 6.93 25.92 ;
    END
  END hdr_out[49]
  PIN hdr_out[4]
    DIRECTION OUTPUT ;
    USE SIGNAL ;
    PORT
      LAYER M5 ;
        RECT  2.352 25.836 2.376 25.92 ;
    END
  END hdr_out[4]
  PIN hdr_out[50]
    DIRECTION OUTPUT ;
    USE SIGNAL ;
    PORT
      LAYER M5 ;
        RECT  7.056 25.836 7.08 25.92 ;
    END
  END hdr_out[50]
  PIN hdr_out[51]
    DIRECTION OUTPUT ;
    USE SIGNAL ;
    PORT
      LAYER M3 ;
        RECT  7.092 25.882 7.11 25.92 ;
    END
  END hdr_out[51]
  PIN hdr_out[52]
    DIRECTION OUTPUT ;
    USE SIGNAL ;
    PORT
      LAYER M5 ;
        RECT  7.248 25.836 7.272 25.92 ;
    END
  END hdr_out[52]
  PIN hdr_out[53]
    DIRECTION OUTPUT ;
    USE SIGNAL ;
    PORT
      LAYER M3 ;
        RECT  7.272 25.882 7.29 25.92 ;
    END
  END hdr_out[53]
  PIN hdr_out[54]
    DIRECTION OUTPUT ;
    USE SIGNAL ;
    PORT
      LAYER M5 ;
        RECT  7.44 25.836 7.464 25.92 ;
    END
  END hdr_out[54]
  PIN hdr_out[55]
    DIRECTION OUTPUT ;
    USE SIGNAL ;
    PORT
      LAYER M3 ;
        RECT  7.56 25.882 7.578 25.92 ;
    END
  END hdr_out[55]
  PIN hdr_out[56]
    DIRECTION OUTPUT ;
    USE SIGNAL ;
    PORT
      LAYER M5 ;
        RECT  7.632 25.836 7.656 25.92 ;
    END
  END hdr_out[56]
  PIN hdr_out[57]
    DIRECTION OUTPUT ;
    USE SIGNAL ;
    PORT
      LAYER M3 ;
        RECT  7.776 25.882 7.794 25.92 ;
    END
  END hdr_out[57]
  PIN hdr_out[58]
    DIRECTION OUTPUT ;
    USE SIGNAL ;
    PORT
      LAYER M5 ;
        RECT  7.824 25.836 7.848 25.92 ;
    END
  END hdr_out[58]
  PIN hdr_out[59]
    DIRECTION OUTPUT ;
    USE SIGNAL ;
    PORT
      LAYER M3 ;
        RECT  7.956 25.882 7.974 25.92 ;
    END
  END hdr_out[59]
  PIN hdr_out[5]
    DIRECTION OUTPUT ;
    USE SIGNAL ;
    PORT
      LAYER M3 ;
        RECT  2.376 25.882 2.394 25.92 ;
    END
  END hdr_out[5]
  PIN hdr_out[60]
    DIRECTION OUTPUT ;
    USE SIGNAL ;
    PORT
      LAYER M5 ;
        RECT  8.016 25.836 8.04 25.92 ;
    END
  END hdr_out[60]
  PIN hdr_out[61]
    DIRECTION OUTPUT ;
    USE SIGNAL ;
    PORT
      LAYER M3 ;
        RECT  8.136 25.882 8.154 25.92 ;
    END
  END hdr_out[61]
  PIN hdr_out[62]
    DIRECTION OUTPUT ;
    USE SIGNAL ;
    PORT
      LAYER M5 ;
        RECT  8.208 25.836 8.232 25.92 ;
    END
  END hdr_out[62]
  PIN hdr_out[63]
    DIRECTION OUTPUT ;
    USE SIGNAL ;
    PORT
      LAYER M3 ;
        RECT  8.352 25.882 8.37 25.92 ;
    END
  END hdr_out[63]
  PIN hdr_out[64]
    DIRECTION OUTPUT ;
    USE SIGNAL ;
    PORT
      LAYER M5 ;
        RECT  8.496 25.836 8.52 25.92 ;
    END
  END hdr_out[64]
  PIN hdr_out[65]
    DIRECTION OUTPUT ;
    USE SIGNAL ;
    PORT
      LAYER M3 ;
        RECT  8.532 25.882 8.55 25.92 ;
    END
  END hdr_out[65]
  PIN hdr_out[66]
    DIRECTION OUTPUT ;
    USE SIGNAL ;
    PORT
      LAYER M5 ;
        RECT  8.688 25.836 8.712 25.92 ;
    END
  END hdr_out[66]
  PIN hdr_out[67]
    DIRECTION OUTPUT ;
    USE SIGNAL ;
    PORT
      LAYER M3 ;
        RECT  8.712 25.882 8.73 25.92 ;
    END
  END hdr_out[67]
  PIN hdr_out[68]
    DIRECTION OUTPUT ;
    USE SIGNAL ;
    PORT
      LAYER M5 ;
        RECT  8.88 25.836 8.904 25.92 ;
    END
  END hdr_out[68]
  PIN hdr_out[69]
    DIRECTION OUTPUT ;
    USE SIGNAL ;
    PORT
      LAYER M3 ;
        RECT  8.928 25.882 8.946 25.92 ;
    END
  END hdr_out[69]
  PIN hdr_out[6]
    DIRECTION OUTPUT ;
    USE SIGNAL ;
    PORT
      LAYER M5 ;
        RECT  2.544 25.836 2.568 25.92 ;
    END
  END hdr_out[6]
  PIN hdr_out[70]
    DIRECTION OUTPUT ;
    USE SIGNAL ;
    PORT
      LAYER M5 ;
        RECT  9.072 25.836 9.096 25.92 ;
    END
  END hdr_out[70]
  PIN hdr_out[71]
    DIRECTION OUTPUT ;
    USE SIGNAL ;
    PORT
      LAYER M3 ;
        RECT  9.216 25.882 9.234 25.92 ;
    END
  END hdr_out[71]
  PIN hdr_out[72]
    DIRECTION OUTPUT ;
    USE SIGNAL ;
    PORT
      LAYER M5 ;
        RECT  9.264 25.836 9.288 25.92 ;
    END
  END hdr_out[72]
  PIN hdr_out[73]
    DIRECTION OUTPUT ;
    USE SIGNAL ;
    PORT
      LAYER M3 ;
        RECT  9.396 25.882 9.414 25.92 ;
    END
  END hdr_out[73]
  PIN hdr_out[74]
    DIRECTION OUTPUT ;
    USE SIGNAL ;
    PORT
      LAYER M5 ;
        RECT  9.456 25.836 9.48 25.92 ;
    END
  END hdr_out[74]
  PIN hdr_out[75]
    DIRECTION OUTPUT ;
    USE SIGNAL ;
    PORT
      LAYER M3 ;
        RECT  9.576 25.882 9.594 25.92 ;
    END
  END hdr_out[75]
  PIN hdr_out[76]
    DIRECTION OUTPUT ;
    USE SIGNAL ;
    PORT
      LAYER M5 ;
        RECT  9.648 25.836 9.672 25.92 ;
    END
  END hdr_out[76]
  PIN hdr_out[77]
    DIRECTION OUTPUT ;
    USE SIGNAL ;
    PORT
      LAYER M3 ;
        RECT  9.792 25.882 9.81 25.92 ;
    END
  END hdr_out[77]
  PIN hdr_out[78]
    DIRECTION OUTPUT ;
    USE SIGNAL ;
    PORT
      LAYER M5 ;
        RECT  9.936 25.836 9.96 25.92 ;
    END
  END hdr_out[78]
  PIN hdr_out[79]
    DIRECTION OUTPUT ;
    USE SIGNAL ;
    PORT
      LAYER M3 ;
        RECT  9.972 25.882 9.99 25.92 ;
    END
  END hdr_out[79]
  PIN hdr_out[7]
    DIRECTION OUTPUT ;
    USE SIGNAL ;
    PORT
      LAYER M3 ;
        RECT  2.592 25.882 2.61 25.92 ;
    END
  END hdr_out[7]
  PIN hdr_out[80]
    DIRECTION OUTPUT ;
    USE SIGNAL ;
    PORT
      LAYER M5 ;
        RECT  10.128 25.836 10.152 25.92 ;
    END
  END hdr_out[80]
  PIN hdr_out[81]
    DIRECTION OUTPUT ;
    USE SIGNAL ;
    PORT
      LAYER M3 ;
        RECT  10.152 25.882 10.17 25.92 ;
    END
  END hdr_out[81]
  PIN hdr_out[82]
    DIRECTION OUTPUT ;
    USE SIGNAL ;
    PORT
      LAYER M5 ;
        RECT  10.32 25.836 10.344 25.92 ;
    END
  END hdr_out[82]
  PIN hdr_out[83]
    DIRECTION OUTPUT ;
    USE SIGNAL ;
    PORT
      LAYER M3 ;
        RECT  10.368 25.882 10.386 25.92 ;
    END
  END hdr_out[83]
  PIN hdr_out[84]
    DIRECTION OUTPUT ;
    USE SIGNAL ;
    PORT
      LAYER M5 ;
        RECT  10.512 25.836 10.536 25.92 ;
    END
  END hdr_out[84]
  PIN hdr_out[85]
    DIRECTION OUTPUT ;
    USE SIGNAL ;
    PORT
      LAYER M3 ;
        RECT  10.548 25.882 10.566 25.92 ;
    END
  END hdr_out[85]
  PIN hdr_out[86]
    DIRECTION OUTPUT ;
    USE SIGNAL ;
    PORT
      LAYER M5 ;
        RECT  10.704 25.836 10.728 25.92 ;
    END
  END hdr_out[86]
  PIN hdr_out[87]
    DIRECTION OUTPUT ;
    USE SIGNAL ;
    PORT
      LAYER M3 ;
        RECT  10.836 25.882 10.854 25.92 ;
    END
  END hdr_out[87]
  PIN hdr_out[88]
    DIRECTION OUTPUT ;
    USE SIGNAL ;
    PORT
      LAYER M5 ;
        RECT  10.896 25.836 10.92 25.92 ;
    END
  END hdr_out[88]
  PIN hdr_out[89]
    DIRECTION OUTPUT ;
    USE SIGNAL ;
    PORT
      LAYER M3 ;
        RECT  11.016 25.882 11.034 25.92 ;
    END
  END hdr_out[89]
  PIN hdr_out[8]
    DIRECTION OUTPUT ;
    USE SIGNAL ;
    PORT
      LAYER M5 ;
        RECT  2.736 25.836 2.76 25.92 ;
    END
  END hdr_out[8]
  PIN hdr_out[90]
    DIRECTION OUTPUT ;
    USE SIGNAL ;
    PORT
      LAYER M5 ;
        RECT  11.088 25.836 11.112 25.92 ;
    END
  END hdr_out[90]
  PIN hdr_out[91]
    DIRECTION OUTPUT ;
    USE SIGNAL ;
    PORT
      LAYER M3 ;
        RECT  11.232 25.882 11.25 25.92 ;
    END
  END hdr_out[91]
  PIN hdr_out[92]
    DIRECTION OUTPUT ;
    USE SIGNAL ;
    PORT
      LAYER M5 ;
        RECT  11.28 25.836 11.304 25.92 ;
    END
  END hdr_out[92]
  PIN hdr_out[93]
    DIRECTION OUTPUT ;
    USE SIGNAL ;
    PORT
      LAYER M3 ;
        RECT  11.412 25.882 11.43 25.92 ;
    END
  END hdr_out[93]
  PIN hdr_out[94]
    DIRECTION OUTPUT ;
    USE SIGNAL ;
    PORT
      LAYER M5 ;
        RECT  11.568 25.836 11.592 25.92 ;
    END
  END hdr_out[94]
  PIN hdr_out[95]
    DIRECTION OUTPUT ;
    USE SIGNAL ;
    PORT
      LAYER M3 ;
        RECT  11.592 25.882 11.61 25.92 ;
    END
  END hdr_out[95]
  PIN hdr_out[96]
    DIRECTION OUTPUT ;
    USE SIGNAL ;
    PORT
      LAYER M5 ;
        RECT  11.76 25.836 11.784 25.92 ;
    END
  END hdr_out[96]
  PIN hdr_out[97]
    DIRECTION OUTPUT ;
    USE SIGNAL ;
    PORT
      LAYER M3 ;
        RECT  11.808 25.882 11.826 25.92 ;
    END
  END hdr_out[97]
  PIN hdr_out[98]
    DIRECTION OUTPUT ;
    USE SIGNAL ;
    PORT
      LAYER M5 ;
        RECT  11.952 25.836 11.976 25.92 ;
    END
  END hdr_out[98]
  PIN hdr_out[99]
    DIRECTION OUTPUT ;
    USE SIGNAL ;
    PORT
      LAYER M3 ;
        RECT  11.988 25.882 12.006 25.92 ;
    END
  END hdr_out[99]
  PIN hdr_out[9]
    DIRECTION OUTPUT ;
    USE SIGNAL ;
    PORT
      LAYER M3 ;
        RECT  2.772 25.882 2.79 25.92 ;
    END
  END hdr_out[9]
  PIN rst_in
    DIRECTION INPUT ;
    USE SIGNAL ;
    PORT
      LAYER M4 ;
        RECT  0 11.952 0.084 11.976 ;
    END
    PORT
      LAYER M4 ;
        RECT  0.06 11.952 0.517 11.976 ;
    END
  END rst_in
  PIN rv_c[0]
    DIRECTION INPUT ;
    USE SIGNAL ;
    PORT
      LAYER M5 ;
        RECT  1.488 0 1.512 0.084 ;
    END
  END rv_c[0]
  PIN rv_c[1]
    DIRECTION INPUT ;
    USE SIGNAL ;
    PORT
      LAYER M3 ;
        RECT  1.512 0 1.53 0.038 ;
    END
  END rv_c[1]
  PIN rv_c[2]
    DIRECTION INPUT ;
    USE SIGNAL ;
    PORT
      LAYER M5 ;
        RECT  1.584 0 1.608 0.084 ;
    END
  END rv_c[2]
  PIN rv_c[3]
    DIRECTION INPUT ;
    USE SIGNAL ;
    PORT
      LAYER M3 ;
        RECT  1.62 0 1.638 0.038 ;
    END
  END rv_c[3]
  PIN rv_c[4]
    DIRECTION INPUT ;
    USE SIGNAL ;
    PORT
      LAYER M5 ;
        RECT  1.68 0 1.704 0.084 ;
    END
  END rv_c[4]
  PIN rv_c[5]
    DIRECTION INPUT ;
    USE SIGNAL ;
    PORT
      LAYER M3 ;
        RECT  1.728 0 1.746 0.038 ;
    END
  END rv_c[5]
  PIN rv_c[6]
    DIRECTION INPUT ;
    USE SIGNAL ;
    PORT
      LAYER M5 ;
        RECT  1.776 0 1.8 0.084 ;
    END
  END rv_c[6]
  PIN rv_c[7]
    DIRECTION INPUT ;
    USE SIGNAL ;
    PORT
      LAYER M3 ;
        RECT  1.8 0 1.818 0.038 ;
    END
  END rv_c[7]
  PIN rv_out[0]
    DIRECTION OUTPUT ;
    USE SIGNAL ;
    PORT
      LAYER M5 ;
        RECT  1.104 25.836 1.128 25.92 ;
    END
  END rv_out[0]
  PIN rv_out[1]
    DIRECTION OUTPUT ;
    USE SIGNAL ;
    PORT
      LAYER M3 ;
        RECT  1.152 25.882 1.17 25.92 ;
    END
  END rv_out[1]
  PIN rv_out[2]
    DIRECTION OUTPUT ;
    USE SIGNAL ;
    PORT
      LAYER M5 ;
        RECT  1.296 25.836 1.32 25.92 ;
    END
  END rv_out[2]
  PIN rv_out[3]
    DIRECTION OUTPUT ;
    USE SIGNAL ;
    PORT
      LAYER M3 ;
        RECT  1.44 25.882 1.458 25.92 ;
    END
  END rv_out[3]
  PIN rv_out[4]
    DIRECTION OUTPUT ;
    USE SIGNAL ;
    PORT
      LAYER M5 ;
        RECT  1.488 25.836 1.512 25.92 ;
    END
  END rv_out[4]
  PIN rv_out[5]
    DIRECTION OUTPUT ;
    USE SIGNAL ;
    PORT
      LAYER M3 ;
        RECT  1.62 25.882 1.638 25.92 ;
    END
  END rv_out[5]
  PIN rv_out[6]
    DIRECTION OUTPUT ;
    USE SIGNAL ;
    PORT
      LAYER M5 ;
        RECT  1.68 25.836 1.704 25.92 ;
    END
  END rv_out[6]
  PIN rv_out[7]
    DIRECTION OUTPUT ;
    USE SIGNAL ;
    PORT
      LAYER M3 ;
        RECT  1.8 25.882 1.818 25.92 ;
    END
  END rv_out[7]
  PIN VDD
    DIRECTION INOUT ;
    USE POWER ;
    PORT
      LAYER M5 ;
        RECT  137.592 2.151 137.712 23.769 ;
        RECT  132.192 2.151 132.312 23.769 ;
        RECT  126.792 2.151 126.912 23.769 ;
        RECT  121.392 2.151 121.512 23.769 ;
        RECT  115.992 2.151 116.112 23.769 ;
        RECT  110.592 2.151 110.712 23.769 ;
        RECT  105.192 2.151 105.312 23.769 ;
        RECT  99.792 2.151 99.912 23.769 ;
        RECT  94.392 2.151 94.512 23.769 ;
        RECT  88.992 2.151 89.112 23.769 ;
        RECT  83.592 2.151 83.712 23.769 ;
        RECT  78.192 2.151 78.312 23.769 ;
        RECT  72.792 2.151 72.912 23.769 ;
        RECT  67.392 2.151 67.512 23.769 ;
        RECT  61.992 2.151 62.112 23.769 ;
        RECT  56.592 2.151 56.712 23.769 ;
        RECT  51.192 2.151 51.312 23.769 ;
        RECT  45.792 2.151 45.912 23.769 ;
        RECT  40.392 2.151 40.512 23.769 ;
        RECT  34.992 2.151 35.112 23.769 ;
        RECT  29.592 2.151 29.712 23.769 ;
        RECT  24.192 2.151 24.312 23.769 ;
        RECT  18.792 2.151 18.912 23.769 ;
        RECT  13.392 2.151 13.512 23.769 ;
        RECT  7.992 2.151 8.112 23.769 ;
        RECT  2.592 2.151 2.712 23.769 ;
    END
  END VDD
  PIN VSS
    DIRECTION INOUT ;
    USE GROUND ;
    PORT
      LAYER M5 ;
        RECT  137.4 2.137 137.52 23.783 ;
        RECT  132 2.137 132.12 23.783 ;
        RECT  126.6 2.137 126.72 23.783 ;
        RECT  121.2 2.137 121.32 23.783 ;
        RECT  115.8 2.137 115.92 23.783 ;
        RECT  110.4 2.137 110.52 23.783 ;
        RECT  105 2.137 105.12 23.783 ;
        RECT  99.6 2.137 99.72 23.783 ;
        RECT  94.2 2.137 94.32 23.783 ;
        RECT  88.8 2.137 88.92 23.783 ;
        RECT  83.4 2.137 83.52 23.783 ;
        RECT  78 2.137 78.12 23.783 ;
        RECT  72.6 2.137 72.72 23.783 ;
        RECT  67.2 2.137 67.32 23.783 ;
        RECT  61.8 2.137 61.92 23.783 ;
        RECT  56.4 2.137 56.52 23.783 ;
        RECT  51 2.137 51.12 23.783 ;
        RECT  45.6 2.137 45.72 23.783 ;
        RECT  40.2 2.137 40.32 23.783 ;
        RECT  34.8 2.137 34.92 23.783 ;
        RECT  29.4 2.137 29.52 23.783 ;
        RECT  24 2.137 24.12 23.783 ;
        RECT  18.6 2.137 18.72 23.783 ;
        RECT  13.2 2.137 13.32 23.783 ;
        RECT  7.8 2.137 7.92 23.783 ;
        RECT  2.4 2.137 2.52 23.783 ;
    END
  END VSS
  # OT_OBS_CLOSED layer=M5 d_um=1.536 added=154
  OBS
    LAYER RVTN ;
     RECT  2.16 2.16 142.02 2.295 ;
     RECT  2.16 2.565 142.02 2.835 ;
     RECT  2.16 3.105 142.02 3.375 ;
     RECT  2.16 3.645 142.02 3.915 ;
     RECT  2.16 4.185 142.02 4.455 ;
     RECT  2.16 4.725 142.02 4.995 ;
     RECT  2.16 5.265 142.02 5.535 ;
     RECT  2.16 5.805 142.02 6.075 ;
     RECT  2.16 6.345 142.02 6.615 ;
     RECT  2.16 6.885 142.02 7.155 ;
     RECT  2.16 7.425 142.02 7.695 ;
     RECT  2.16 7.965 142.02 8.235 ;
     RECT  2.16 8.505 142.02 8.775 ;
     RECT  2.16 9.045 142.02 9.315 ;
     RECT  2.16 9.585 142.02 9.855 ;
     RECT  2.16 10.125 142.02 10.395 ;
     RECT  2.16 10.665 142.02 10.935 ;
     RECT  2.16 11.205 142.02 11.475 ;
     RECT  2.16 11.745 142.02 12.015 ;
     RECT  2.16 12.285 142.02 12.555 ;
     RECT  2.16 12.825 142.02 13.095 ;
     RECT  2.16 13.365 142.02 13.635 ;
     RECT  2.16 13.905 142.02 14.175 ;
     RECT  2.16 14.445 142.02 14.715 ;
     RECT  2.16 14.985 142.02 15.255 ;
     RECT  2.16 15.525 142.02 15.795 ;
     RECT  2.16 16.065 142.02 16.335 ;
     RECT  2.16 16.605 142.02 16.875 ;
     RECT  2.16 17.145 142.02 17.415 ;
     RECT  2.16 17.685 142.02 17.955 ;
     RECT  2.16 18.225 142.02 18.495 ;
     RECT  2.16 18.765 142.02 19.035 ;
     RECT  2.16 19.305 142.02 19.575 ;
     RECT  2.16 19.845 142.02 20.115 ;
     RECT  2.16 20.385 142.02 20.655 ;
     RECT  2.16 20.925 142.02 21.195 ;
     RECT  2.16 21.465 142.02 21.735 ;
     RECT  2.16 22.005 142.02 22.275 ;
     RECT  2.16 22.545 142.02 22.815 ;
     RECT  2.16 23.085 142.02 23.355 ;
     RECT  2.16 23.625 142.02 23.76 ;
    LAYER RVTP ;
     RECT  2.16 2.295 142.02 2.565 ;
     RECT  2.16 2.835 142.02 3.105 ;
     RECT  2.16 3.375 142.02 3.645 ;
     RECT  2.16 3.915 142.02 4.185 ;
     RECT  2.16 4.455 142.02 4.725 ;
     RECT  2.16 4.995 142.02 5.265 ;
     RECT  2.16 5.535 142.02 5.805 ;
     RECT  2.16 6.075 142.02 6.345 ;
     RECT  2.16 6.615 142.02 6.885 ;
     RECT  2.16 7.155 142.02 7.425 ;
     RECT  2.16 7.695 142.02 7.965 ;
     RECT  2.16 8.235 142.02 8.505 ;
     RECT  2.16 8.775 142.02 9.045 ;
     RECT  2.16 9.315 142.02 9.585 ;
     RECT  2.16 9.855 142.02 10.125 ;
     RECT  2.16 10.395 142.02 10.665 ;
     RECT  2.16 10.935 142.02 11.205 ;
     RECT  2.16 11.475 142.02 11.745 ;
     RECT  2.16 12.015 142.02 12.285 ;
     RECT  2.16 12.555 142.02 12.825 ;
     RECT  2.16 13.095 142.02 13.365 ;
     RECT  2.16 13.635 142.02 13.905 ;
     RECT  2.16 14.175 142.02 14.445 ;
     RECT  2.16 14.715 142.02 14.985 ;
     RECT  2.16 15.255 142.02 15.525 ;
     RECT  2.16 15.795 142.02 16.065 ;
     RECT  2.16 16.335 142.02 16.605 ;
     RECT  2.16 16.875 142.02 17.145 ;
     RECT  2.16 17.415 142.02 17.685 ;
     RECT  2.16 17.955 142.02 18.225 ;
     RECT  2.16 18.495 142.02 18.765 ;
     RECT  2.16 19.035 142.02 19.305 ;
     RECT  2.16 19.575 142.02 19.845 ;
     RECT  2.16 20.115 142.02 20.385 ;
     RECT  2.16 20.655 142.02 20.925 ;
     RECT  2.16 21.195 142.02 21.465 ;
     RECT  2.16 21.735 142.02 22.005 ;
     RECT  2.16 22.275 142.02 22.545 ;
     RECT  2.16 22.815 142.02 23.085 ;
     RECT  2.16 23.355 142.02 23.625 ;
    LAYER M1 ;
     RECT  2.16 2.151 142.02 23.769 ;
    LAYER M2 ;
     RECT  0.535 15.606 1.039 15.624 ;
     RECT  1.039 15.03 1.111 15.624 ;
     RECT  1.147 3.96 1.219 3.978 ;
     RECT  1.111 14.958 1.291 15.624 ;
     RECT  0.535 22.518 1.291 22.536 ;
     RECT  1.291 14.958 1.327 16.326 ;
     RECT  1.291 22.518 1.363 23.184 ;
     RECT  1.327 23.94 1.363 23.958 ;
     RECT  1.399 20.466 1.435 20.484 ;
     RECT  1.147 18.666 1.471 18.684 ;
     RECT  1.399 5.472 1.507 5.49 ;
     RECT  1.435 6.282 1.507 6.3 ;
     RECT  1.327 14.958 1.507 17.064 ;
     RECT  1.507 5.472 1.615 6.3 ;
     RECT  1.471 18.234 1.615 18.684 ;
     RECT  1.435 19.818 1.615 20.484 ;
     RECT  1.615 18.234 1.651 20.484 ;
     RECT  1.723 0.036 1.787 0.054 ;
     RECT  1.615 5.202 1.795 6.3 ;
     RECT  1.795 0.108 1.895 0.126 ;
     RECT  1.507 14.958 1.903 17.244 ;
     RECT  1.651 18.036 1.903 20.484 ;
     RECT  1.219 3.96 2.011 4.212 ;
     RECT  1.903 14.958 2.047 20.484 ;
     RECT  2.011 3.96 2.083 4.248 ;
     RECT  1.795 5.076 2.083 6.642 ;
     RECT  1.327 2.232 2.119 2.25 ;
     RECT  2.083 3.96 2.155 6.642 ;
     RECT  2.119 2.232 2.16 2.664 ;
     RECT  2.155 3.96 2.16 7.11 ;
     RECT  2.047 14.688 2.16 20.484 ;
     RECT  1.363 22.518 2.16 23.958 ;
     RECT  2.16 2.151 2.399 23.958 ;
     RECT  2.399 2.151 2.767 23.922 ;
     RECT  2.767 1.728 2.831 23.922 ;
     RECT  2.831 1.728 2.939 23.769 ;
     RECT  3.127 25.02 3.263 25.038 ;
     RECT  2.939 2.151 3.631 23.769 ;
     RECT  3.631 2.151 3.667 23.814 ;
     RECT  3.667 2.151 4.495 23.85 ;
     RECT  5.251 0.036 5.351 0.054 ;
     RECT  3.451 25.056 5.567 25.074 ;
     RECT  4.495 1.728 5.711 23.85 ;
     RECT  5.711 1.728 5.783 23.814 ;
     RECT  5.783 1.728 6.539 23.769 ;
     RECT  6.539 1.8 6.755 23.769 ;
     RECT  6.439 0.036 7.295 0.054 ;
     RECT  6.755 2.151 7.339 23.769 ;
     RECT  7.339 2.151 7.411 23.814 ;
     RECT  7.411 2.151 7.555 23.922 ;
     RECT  6.907 25.056 7.799 25.074 ;
     RECT  7.555 2.151 7.979 23.958 ;
     RECT  8.131 0.036 8.231 0.054 ;
     RECT  8.527 25.866 8.627 25.884 ;
     RECT  7.979 2.151 8.923 23.922 ;
     RECT  9.211 0.036 9.311 0.054 ;
     RECT  9.391 25.866 9.707 25.884 ;
     RECT  8.923 2.151 11.011 24.228 ;
     RECT  10.147 25.101 11.011 25.119 ;
     RECT  11.011 25.056 11.407 25.119 ;
     RECT  11.407 24.984 11.615 25.119 ;
     RECT  10.147 0.036 11.687 0.054 ;
     RECT  11.615 25.056 11.687 25.119 ;
     RECT  11.687 25.056 11.867 25.074 ;
     RECT  11.011 1.728 11.939 24.228 ;
     RECT  11.939 2.151 12.047 24.228 ;
     RECT  12.199 25.866 12.299 25.884 ;
     RECT  12.047 2.151 13.171 23.814 ;
     RECT  13.171 0.036 13.271 0.054 ;
     RECT  13.171 2.151 13.271 23.85 ;
     RECT  13.271 2.151 13.999 23.814 ;
     RECT  13.999 2.151 14.927 23.922 ;
     RECT  16.411 25.056 16.511 25.074 ;
     RECT  14.927 2.151 17.231 23.814 ;
     RECT  17.231 2.151 18.499 23.769 ;
     RECT  18.499 0.036 18.599 0.054 ;
     RECT  18.499 2.151 19.283 23.886 ;
     RECT  19.283 2.151 25.843 23.769 ;
     RECT  25.843 1.728 26.015 23.769 ;
     RECT  25.987 25.866 26.159 25.884 ;
     RECT  26.015 2.151 29.083 23.769 ;
     RECT  29.083 1.728 29.399 23.769 ;
     RECT  29.399 2.151 32.611 23.769 ;
     RECT  32.611 2.151 32.963 23.922 ;
     RECT  35.023 25.866 35.267 25.884 ;
     RECT  38.299 25.866 38.399 25.884 ;
     RECT  32.963 2.151 40.639 23.769 ;
     RECT  40.639 1.728 40.811 23.769 ;
     RECT  44.059 25.866 44.231 25.884 ;
     RECT  40.811 2.151 45.679 23.769 ;
     RECT  45.679 1.728 45.779 23.85 ;
     RECT  45.779 2.151 46.543 23.769 ;
     RECT  46.543 2.151 46.643 23.814 ;
     RECT  46.643 2.151 47.983 23.769 ;
     RECT  47.983 1.728 48.191 23.769 ;
     RECT  48.191 2.151 54.715 23.769 ;
     RECT  54.715 2.151 55.067 23.814 ;
     RECT  55.471 25.866 55.679 25.884 ;
     RECT  55.067 2.151 58.819 23.769 ;
     RECT  58.819 2.151 58.991 23.814 ;
     RECT  58.991 2.151 61.915 23.769 ;
     RECT  61.699 0.036 61.943 0.054 ;
     RECT  61.915 2.151 62.239 23.85 ;
     RECT  62.599 25.866 62.699 25.884 ;
     RECT  62.959 0.036 63.095 0.054 ;
     RECT  62.239 2.151 63.311 23.886 ;
     RECT  63.311 2.151 64.291 23.769 ;
     RECT  64.291 2.151 64.643 23.814 ;
     RECT  65.947 0.036 66.047 0.054 ;
     RECT  64.643 2.151 66.811 23.769 ;
     RECT  66.811 2.151 67.091 23.814 ;
     RECT  69.187 25.146 69.287 25.164 ;
     RECT  67.091 2.151 69.907 23.769 ;
     RECT  69.907 2.151 71.519 23.814 ;
     RECT  71.519 2.151 72.859 23.769 ;
     RECT  72.859 0.036 72.959 0.054 ;
     RECT  72.859 2.151 72.959 23.994 ;
     RECT  72.959 2.151 73.319 23.922 ;
     RECT  73.319 2.151 75.811 23.769 ;
     RECT  75.811 2.151 75.947 23.814 ;
     RECT  75.947 2.151 76.855 23.769 ;
     RECT  76.855 2.151 77.387 23.814 ;
     RECT  77.387 2.151 83.119 23.769 ;
     RECT  83.119 2.151 83.615 23.814 ;
     RECT  83.615 2.151 84.379 23.769 ;
     RECT  84.379 2.151 84.739 23.814 ;
     RECT  84.739 0.036 84.839 0.054 ;
     RECT  84.739 2.151 84.875 23.886 ;
     RECT  85.891 25.056 86.027 25.074 ;
     RECT  86.863 25.056 88.295 25.074 ;
     RECT  84.875 2.151 88.771 23.769 ;
     RECT  88.771 0.036 88.907 0.054 ;
     RECT  88.771 2.151 89.735 23.922 ;
     RECT  91.759 25.056 92.723 25.074 ;
     RECT  89.735 2.151 94.243 23.769 ;
     RECT  94.243 0.036 94.379 0.054 ;
     RECT  94.243 2.151 94.639 23.85 ;
     RECT  94.639 2.151 95.171 23.922 ;
     RECT  95.171 2.151 96.187 23.769 ;
     RECT  96.187 2.151 96.287 23.994 ;
     RECT  96.287 2.151 97.915 23.769 ;
     RECT  97.915 2.151 98.087 23.958 ;
     RECT  99.031 25.056 99.563 25.074 ;
     RECT  99.931 0.036 100.031 0.054 ;
     RECT  98.087 2.151 100.795 23.769 ;
     RECT  100.795 2.151 100.931 23.886 ;
     RECT  102.415 0.036 102.515 0.054 ;
     RECT  100.931 2.151 105.295 23.769 ;
     RECT  105.295 0.036 105.395 0.054 ;
     RECT  105.295 2.151 105.691 23.814 ;
     RECT  105.691 2.151 106.223 23.886 ;
     RECT  106.771 25.146 106.943 25.164 ;
     RECT  106.223 2.151 110.587 23.769 ;
     RECT  110.587 2.151 110.947 23.922 ;
     RECT  110.875 0.036 110.975 0.054 ;
     RECT  110.947 2.151 111.083 23.994 ;
     RECT  111.083 2.151 112.919 23.886 ;
     RECT  112.919 2.151 115.951 23.769 ;
     RECT  115.951 2.151 116.159 23.814 ;
     RECT  118.723 0.036 118.859 0.054 ;
     RECT  116.159 2.151 121.063 23.769 ;
     RECT  121.063 2.151 121.271 23.85 ;
     RECT  121.243 0.036 121.379 0.054 ;
     RECT  121.271 2.151 122.467 23.769 ;
     RECT  122.467 2.151 123.071 23.886 ;
     RECT  123.071 2.151 126.607 23.769 ;
     RECT  126.607 2.151 127.003 23.85 ;
     RECT  126.535 0.036 127.391 0.054 ;
     RECT  127.003 2.151 127.499 23.922 ;
     RECT  127.499 2.151 128.039 23.85 ;
     RECT  128.155 25.056 128.255 25.074 ;
     RECT  128.039 2.151 130.243 23.814 ;
     RECT  130.243 2.151 130.847 23.886 ;
     RECT  130.847 2.151 131.899 23.769 ;
     RECT  131.899 2.151 132.547 23.814 ;
     RECT  132.547 1.728 132.683 23.814 ;
     RECT  132.683 2.151 133.159 23.814 ;
     RECT  133.159 2.151 133.367 23.994 ;
     RECT  133.367 2.151 142.02 23.769 ;
     RECT  142.02 2.808 142.295 3.168 ;
     RECT  142.02 21.366 142.547 22.032 ;
     RECT  142.02 4.158 142.727 4.176 ;
     RECT  142.295 3.15 143.051 3.168 ;
     RECT  142.547 21.366 143.051 21.384 ;
    LAYER M3 ;
     RECT  1.17 0.012 1.224 0.038 ;
     RECT  1.242 0.012 1.332 0.038 ;
     RECT  1.35 0.012 1.44 0.038 ;
     RECT  1.458 0.012 1.512 0.038 ;
     RECT  1.53 0.012 1.62 0.038 ;
     RECT  1.638 0.012 1.728 0.038 ;
     RECT  1.746 0.012 1.8 0.038 ;
     RECT  1.818 0.012 2.016 0.038 ;
     RECT  2.034 0.012 2.196 0.038 ;
     RECT  2.214 0.012 2.376 0.038 ;
     RECT  2.394 0.012 2.592 0.038 ;
     RECT  2.61 0.012 2.772 0.038 ;
     RECT  2.79 0.012 3.06 0.038 ;
     RECT  3.078 0.012 3.24 0.038 ;
     RECT  3.258 0.012 3.456 0.038 ;
     RECT  3.474 0.012 3.636 0.038 ;
     RECT  3.654 0.012 3.816 0.038 ;
     RECT  3.834 0.012 4.032 0.038 ;
     RECT  4.05 0.012 4.212 0.038 ;
     RECT  4.23 0.012 4.5 0.038 ;
     RECT  4.518 0.012 4.68 0.038 ;
     RECT  4.698 0.012 4.896 0.038 ;
     RECT  4.914 0.012 5.076 0.038 ;
     RECT  5.094 0.012 5.256 0.038 ;
     RECT  5.274 0.012 5.472 0.038 ;
     RECT  5.49 0.012 5.652 0.038 ;
     RECT  5.67 0.012 5.832 0.038 ;
     RECT  5.85 0.012 6.12 0.038 ;
     RECT  6.138 0.012 6.336 0.038 ;
     RECT  6.354 0.012 6.516 0.038 ;
     RECT  6.534 0.012 6.696 0.038 ;
     RECT  6.714 0.012 6.912 0.038 ;
     RECT  6.93 0.012 7.092 0.038 ;
     RECT  7.11 0.012 7.272 0.038 ;
     RECT  7.29 0.012 7.56 0.038 ;
     RECT  7.578 0.012 7.776 0.038 ;
     RECT  7.794 0.012 7.956 0.038 ;
     RECT  7.974 0.012 8.136 0.038 ;
     RECT  8.154 0.012 8.352 0.038 ;
     RECT  8.37 0.012 8.532 0.038 ;
     RECT  8.55 0.012 8.712 0.038 ;
     RECT  8.73 0.012 8.928 0.038 ;
     RECT  8.946 0.012 9.216 0.038 ;
     RECT  9.234 0.012 9.396 0.038 ;
     RECT  9.414 0.012 9.576 0.038 ;
     RECT  9.594 0.012 9.792 0.038 ;
     RECT  9.81 0.012 9.972 0.038 ;
     RECT  9.99 0.012 10.152 0.038 ;
     RECT  10.17 0.012 10.368 0.038 ;
     RECT  10.386 0.012 10.548 0.038 ;
     RECT  10.566 0.012 10.836 0.038 ;
     RECT  10.854 0.012 11.016 0.038 ;
     RECT  11.034 0.012 11.232 0.038 ;
     RECT  11.25 0.012 11.412 0.038 ;
     RECT  11.43 0.012 11.592 0.038 ;
     RECT  11.61 0.012 11.808 0.038 ;
     RECT  11.826 0.012 11.988 0.038 ;
     RECT  12.006 0.012 12.276 0.038 ;
     RECT  12.294 0.012 12.456 0.038 ;
     RECT  12.474 0.012 12.672 0.038 ;
     RECT  12.69 0.012 12.852 0.038 ;
     RECT  12.87 0.012 13.248 0.038 ;
     RECT  13.266 0.012 13.608 0.038 ;
     RECT  13.626 0.012 14.004 0.038 ;
     RECT  14.022 0.012 14.4 0.038 ;
     RECT  14.418 0.012 14.868 0.038 ;
     RECT  14.886 0.012 15.264 0.038 ;
     RECT  15.282 0.012 15.624 0.038 ;
     RECT  15.642 0.012 16.128 0.038 ;
     RECT  16.146 0.012 16.488 0.038 ;
     RECT  16.506 0.012 16.884 0.038 ;
     RECT  16.902 0.012 17.28 0.038 ;
     RECT  17.298 0.012 17.748 0.038 ;
     RECT  17.766 0.012 18.144 0.038 ;
     RECT  18.162 0.012 18.504 0.038 ;
     RECT  18.522 0.012 18.9 0.038 ;
     RECT  18.918 0.012 19.368 0.038 ;
     RECT  19.386 0.012 19.764 0.038 ;
     RECT  19.782 0.012 20.34 0.038 ;
     RECT  1.152 0.038 20.358 0.077 ;
     RECT  59.634 0.012 60.264 0.038 ;
     RECT  60.282 0.012 60.66 0.038 ;
     RECT  60.678 0.012 61.056 0.038 ;
     RECT  61.074 0.012 61.416 0.038 ;
     RECT  61.434 0.012 61.92 0.038 ;
     RECT  61.938 0.012 62.28 0.038 ;
     RECT  62.298 0.012 62.676 0.038 ;
     RECT  62.694 0.012 63.072 0.038 ;
     RECT  63.09 0.012 63.54 0.038 ;
     RECT  63.558 0.012 63.936 0.038 ;
     RECT  63.954 0.012 64.296 0.038 ;
     RECT  64.314 0.012 64.692 0.038 ;
     RECT  64.71 0.012 65.16 0.038 ;
     RECT  65.178 0.012 65.556 0.038 ;
     RECT  65.574 0.012 65.952 0.038 ;
     RECT  65.97 0.012 66.42 0.038 ;
     RECT  66.438 0.012 66.816 0.038 ;
     RECT  66.834 0.012 67.176 0.038 ;
     RECT  67.194 0.012 67.572 0.038 ;
     RECT  67.59 0.012 68.04 0.038 ;
     RECT  68.058 0.012 68.436 0.038 ;
     RECT  68.454 0.012 68.832 0.038 ;
     RECT  68.85 0.012 69.192 0.038 ;
     RECT  69.21 0.012 69.696 0.038 ;
     RECT  69.714 0.012 70.056 0.038 ;
     RECT  70.074 0.012 70.452 0.038 ;
     RECT  70.47 0.012 70.848 0.038 ;
     RECT  70.866 0.012 71.316 0.038 ;
     RECT  71.334 0.012 71.712 0.038 ;
     RECT  71.73 0.012 72.072 0.038 ;
     RECT  72.09 0.012 72.468 0.038 ;
     RECT  72.486 0.012 72.936 0.038 ;
     RECT  72.954 0.012 73.332 0.038 ;
     RECT  73.35 0.012 73.728 0.038 ;
     RECT  73.746 0.012 74.196 0.038 ;
     RECT  74.214 0.012 74.592 0.038 ;
     RECT  74.61 0.012 74.952 0.038 ;
     RECT  74.97 0.012 75.348 0.038 ;
     RECT  75.366 0.012 75.816 0.038 ;
     RECT  75.834 0.012 76.212 0.038 ;
     RECT  76.23 0.012 76.608 0.038 ;
     RECT  76.626 0.012 76.968 0.038 ;
     RECT  76.986 0.012 77.472 0.038 ;
     RECT  77.49 0.012 77.832 0.038 ;
     RECT  77.85 0.012 78.228 0.038 ;
     RECT  78.246 0.012 78.624 0.038 ;
     RECT  78.642 0.012 79.092 0.038 ;
     RECT  79.11 0.012 79.488 0.038 ;
     RECT  79.506 0.012 79.848 0.038 ;
     RECT  79.866 0.012 80.352 0.038 ;
     RECT  80.37 0.012 80.712 0.038 ;
     RECT  80.73 0.012 81.108 0.038 ;
     RECT  81.126 0.012 81.504 0.038 ;
     RECT  81.522 0.012 81.972 0.038 ;
     RECT  81.99 0.012 82.368 0.038 ;
     RECT  82.386 0.012 82.728 0.038 ;
     RECT  82.746 0.012 83.124 0.038 ;
     RECT  83.142 0.012 83.592 0.038 ;
     RECT  83.61 0.012 83.988 0.038 ;
     RECT  84.006 0.012 84.384 0.038 ;
     RECT  84.402 0.012 84.744 0.038 ;
     RECT  84.762 0.012 85.248 0.038 ;
     RECT  85.266 0.012 85.608 0.038 ;
     RECT  85.626 0.012 86.004 0.038 ;
     RECT  86.022 0.012 86.472 0.038 ;
     RECT  86.49 0.012 86.868 0.038 ;
     RECT  86.886 0.012 87.264 0.038 ;
     RECT  87.282 0.012 87.624 0.038 ;
     RECT  87.642 0.012 88.128 0.038 ;
     RECT  88.146 0.012 88.488 0.038 ;
     RECT  88.506 0.012 88.884 0.038 ;
     RECT  88.902 0.012 89.28 0.038 ;
     RECT  89.298 0.012 89.748 0.038 ;
     RECT  89.766 0.012 90.144 0.038 ;
     RECT  90.162 0.012 90.504 0.038 ;
     RECT  90.522 0.012 90.9 0.038 ;
     RECT  90.918 0.012 91.368 0.038 ;
     RECT  91.386 0.012 91.764 0.038 ;
     RECT  91.782 0.012 92.16 0.038 ;
     RECT  92.178 0.012 92.52 0.038 ;
     RECT  92.538 0.012 93.024 0.038 ;
     RECT  93.042 0.012 93.384 0.038 ;
     RECT  93.402 0.012 93.78 0.038 ;
     RECT  93.798 0.012 94.248 0.038 ;
     RECT  94.266 0.012 94.644 0.038 ;
     RECT  94.662 0.012 95.04 0.038 ;
     RECT  95.058 0.012 95.4 0.038 ;
     RECT  95.418 0.012 95.904 0.038 ;
     RECT  95.922 0.012 96.264 0.038 ;
     RECT  96.282 0.012 96.66 0.038 ;
     RECT  96.678 0.012 97.056 0.038 ;
     RECT  97.074 0.012 97.524 0.038 ;
     RECT  97.542 0.012 97.92 0.038 ;
     RECT  97.938 0.012 98.28 0.038 ;
     RECT  98.298 0.012 98.676 0.038 ;
     RECT  98.694 0.012 99.144 0.038 ;
     RECT  99.162 0.012 99.54 0.038 ;
     RECT  99.558 0.012 99.936 0.038 ;
     RECT  99.954 0.012 100.404 0.038 ;
     RECT  100.422 0.012 100.8 0.038 ;
     RECT  100.818 0.012 101.16 0.038 ;
     RECT  101.178 0.012 101.556 0.038 ;
     RECT  101.574 0.012 102.024 0.038 ;
     RECT  102.042 0.012 102.42 0.038 ;
     RECT  102.438 0.012 102.816 0.038 ;
     RECT  102.834 0.012 103.176 0.038 ;
     RECT  103.194 0.012 103.68 0.038 ;
     RECT  103.698 0.012 104.04 0.038 ;
     RECT  104.058 0.012 104.436 0.038 ;
     RECT  104.454 0.012 104.832 0.038 ;
     RECT  104.85 0.012 105.3 0.038 ;
     RECT  105.318 0.012 105.696 0.038 ;
     RECT  105.714 0.012 106.056 0.038 ;
     RECT  106.074 0.012 106.56 0.038 ;
     RECT  106.578 0.012 106.92 0.038 ;
     RECT  106.938 0.012 107.316 0.038 ;
     RECT  107.334 0.012 107.712 0.038 ;
     RECT  107.73 0.012 108.18 0.038 ;
     RECT  108.198 0.012 108.576 0.038 ;
     RECT  108.594 0.012 108.936 0.038 ;
     RECT  108.954 0.012 109.332 0.038 ;
     RECT  109.35 0.012 109.8 0.038 ;
     RECT  109.818 0.012 110.196 0.038 ;
     RECT  110.214 0.012 110.592 0.038 ;
     RECT  110.61 0.012 110.952 0.038 ;
     RECT  110.97 0.012 111.456 0.038 ;
     RECT  111.474 0.012 111.816 0.038 ;
     RECT  111.834 0.012 112.212 0.038 ;
     RECT  112.23 0.012 112.608 0.038 ;
     RECT  112.626 0.012 113.076 0.038 ;
     RECT  113.094 0.012 113.472 0.038 ;
     RECT  113.49 0.012 113.832 0.038 ;
     RECT  113.85 0.012 114.336 0.038 ;
     RECT  114.354 0.012 114.696 0.038 ;
     RECT  114.714 0.012 115.092 0.038 ;
     RECT  115.11 0.012 115.488 0.038 ;
     RECT  115.506 0.012 115.956 0.038 ;
     RECT  115.974 0.012 116.352 0.038 ;
     RECT  116.37 0.012 116.712 0.038 ;
     RECT  116.73 0.012 117.108 0.038 ;
     RECT  117.126 0.012 117.576 0.038 ;
     RECT  117.594 0.012 117.972 0.038 ;
     RECT  117.99 0.012 118.368 0.038 ;
     RECT  118.386 0.012 118.728 0.038 ;
     RECT  118.746 0.012 119.232 0.038 ;
     RECT  119.25 0.012 119.592 0.038 ;
     RECT  119.61 0.012 119.988 0.038 ;
     RECT  120.006 0.012 120.456 0.038 ;
     RECT  120.474 0.012 120.852 0.038 ;
     RECT  120.87 0.012 121.248 0.038 ;
     RECT  121.266 0.012 121.608 0.038 ;
     RECT  121.626 0.012 122.112 0.038 ;
     RECT  122.13 0.012 122.472 0.038 ;
     RECT  122.49 0.012 122.868 0.038 ;
     RECT  122.886 0.012 123.264 0.038 ;
     RECT  123.282 0.012 123.732 0.038 ;
     RECT  123.75 0.012 124.128 0.038 ;
     RECT  124.146 0.012 124.488 0.038 ;
     RECT  124.506 0.012 124.884 0.038 ;
     RECT  124.902 0.012 125.352 0.038 ;
     RECT  125.37 0.012 125.748 0.038 ;
     RECT  125.766 0.012 126.144 0.038 ;
     RECT  126.162 0.012 126.612 0.038 ;
     RECT  126.63 0.012 127.008 0.038 ;
     RECT  127.026 0.012 127.368 0.038 ;
     RECT  127.386 0.012 127.764 0.038 ;
     RECT  127.782 0.012 128.232 0.038 ;
     RECT  128.25 0.012 128.628 0.038 ;
     RECT  128.646 0.012 129.024 0.038 ;
     RECT  129.042 0.012 129.384 0.038 ;
     RECT  129.402 0.012 129.888 0.038 ;
     RECT  129.906 0.012 130.248 0.038 ;
     RECT  130.266 0.012 130.644 0.038 ;
     RECT  130.662 0.012 131.112 0.038 ;
     RECT  59.616 0.038 131.13 0.077 ;
     RECT  59.616 0.077 115.974 0.557 ;
     RECT  140.85 0.012 141.48 0.038 ;
     RECT  140.832 0.038 141.498 1.147 ;
     RECT  1.152 0.077 16.506 1.723 ;
     RECT  17.28 0.077 18.594 1.723 ;
     RECT  19.368 0.077 20.358 1.723 ;
     RECT  36.648 0.571 37.53 1.723 ;
     RECT  40.788 0.571 41.562 1.723 ;
     RECT  44.064 0.571 44.946 1.723 ;
     RECT  46.548 0.571 47.322 1.723 ;
     RECT  51.444 0.091 52.218 1.723 ;
     RECT  59.616 0.557 113.094 1.723 ;
     RECT  113.832 0.557 115.974 1.723 ;
     RECT  117.108 0.077 131.13 1.723 ;
     RECT  131.922 0.012 132.552 0.038 ;
     RECT  131.904 0.038 132.57 1.723 ;
     RECT  134.874 0.012 135.54 0.038 ;
     RECT  134.856 0.038 135.558 1.723 ;
     RECT  137.862 0.012 138.528 0.038 ;
     RECT  137.844 0.038 138.546 1.723 ;
     RECT  140.832 1.147 142.29 1.723 ;
     RECT  1.152 1.723 142.29 2.525 ;
     RECT  138.744 2.525 142.29 2.831 ;
     RECT  142.704 2.875 143.046 3.173 ;
     RECT  1.152 2.525 55.098 3.343 ;
     RECT  55.872 2.525 138.006 3.343 ;
     RECT  138.744 2.831 141.966 3.371 ;
     RECT  1.152 3.343 138.006 3.451 ;
     RECT  138.744 3.371 141.714 3.451 ;
     RECT  1.152 3.451 141.714 3.569 ;
     RECT  27.432 3.569 141.714 3.605 ;
     RECT  27.432 3.605 39.474 3.839 ;
     RECT  27.432 3.839 36.126 3.917 ;
     RECT  40.215 3.605 141.678 3.965 ;
     RECT  1.152 3.569 26.442 3.983 ;
     RECT  42.12 3.965 141.678 4.109 ;
     RECT  27.432 3.917 36.09 4.145 ;
     RECT  42.12 4.109 59.49 4.145 ;
     RECT  142.704 3.173 142.722 4.181 ;
     RECT  1.224 3.983 26.442 4.217 ;
     RECT  36.864 3.839 39.474 4.379 ;
     RECT  60.3 4.109 141.678 4.379 ;
     RECT  42.12 4.145 52.074 4.415 ;
     RECT  1.44 4.217 26.442 4.531 ;
     RECT  27.432 4.145 33.174 4.531 ;
     RECT  137.016 4.379 141.678 4.531 ;
     RECT  46.728 4.415 52.074 4.541 ;
     RECT  60.3 4.379 136.026 4.589 ;
     RECT  1.44 4.531 33.174 4.793 ;
     RECT  60.336 4.589 136.026 4.829 ;
     RECT  1.44 4.793 31.41 5.131 ;
     RECT  60.336 4.829 91.098 5.189 ;
     RECT  137.016 4.531 141.858 5.341 ;
     RECT  1.404 5.131 31.41 5.459 ;
     RECT  73.98 5.189 91.098 5.459 ;
     RECT  1.404 5.459 14.274 5.495 ;
     RECT  15.084 5.459 17.37 5.495 ;
     RECT  73.98 5.459 81.594 5.495 ;
     RECT  91.944 4.829 136.026 5.531 ;
     RECT  60.336 5.189 73.242 5.597 ;
     RECT  1.44 5.495 14.274 5.693 ;
     RECT  18.108 5.459 31.41 5.693 ;
     RECT  122.256 5.531 136.026 5.693 ;
     RECT  18.108 5.693 20.07 5.729 ;
     RECT  122.256 5.693 122.274 5.789 ;
     RECT  82.44 5.459 91.098 6.269 ;
     RECT  1.44 5.693 13.878 6.305 ;
     RECT  1.8 6.305 13.878 6.647 ;
     RECT  2.16 6.647 13.878 6.691 ;
     RECT  2.16 6.691 13.986 7.115 ;
     RECT  2.232 7.115 13.986 7.187 ;
     RECT  2.304 7.187 13.986 7.349 ;
     RECT  2.376 7.349 13.986 7.655 ;
     RECT  2.415 7.655 13.986 9.319 ;
     RECT  40.215 3.965 41.382 9.979 ;
     RECT  42.12 4.415 45.897 9.979 ;
     RECT  40.215 9.979 45.897 10.049 ;
     RECT  2.34 9.319 13.986 10.201 ;
     RECT  2.34 10.201 14.022 11.011 ;
     RECT  15.084 5.495 15.102 11.275 ;
     RECT  18.615 5.729 20.07 11.275 ;
     RECT  40.215 10.049 41.382 11.371 ;
     RECT  14.832 11.275 15.102 11.405 ;
     RECT  18.504 11.275 20.07 11.435 ;
     RECT  40.104 11.371 41.382 11.471 ;
     RECT  2.304 11.011 14.022 14.611 ;
     RECT  2.304 14.611 14.31 14.683 ;
     RECT  2.052 14.683 14.31 14.881 ;
     RECT  15.084 11.405 15.102 14.881 ;
     RECT  1.116 14.953 1.134 15.025 ;
     RECT  2.052 14.881 15.102 15.331 ;
     RECT  1.98 15.331 15.102 15.529 ;
     RECT  1.044 15.025 1.134 15.601 ;
     RECT  1.944 15.529 15.102 15.871 ;
     RECT  0.54 15.601 1.134 16.069 ;
     RECT  1.872 15.871 15.102 16.069 ;
     RECT  0.54 16.069 15.102 17.609 ;
     RECT  0.54 17.609 5.418 18.535 ;
     RECT  6.156 17.609 15.102 18.535 ;
     RECT  60.336 5.597 73.134 18.805 ;
     RECT  82.44 6.269 90.954 21.091 ;
     RECT  0.54 18.535 15.102 21.235 ;
     RECT  82.224 21.091 90.954 21.361 ;
     RECT  91.944 5.531 121.497 21.361 ;
     RECT  82.224 21.361 121.497 21.397 ;
     RECT  0.54 21.235 15.426 21.469 ;
     RECT  16.164 5.495 17.37 21.469 ;
     RECT  73.98 5.495 81.342 21.469 ;
     RECT  82.224 21.397 121.914 21.469 ;
     RECT  73.98 21.469 121.986 21.631 ;
     RECT  123.12 5.693 136.026 21.631 ;
     RECT  0.54 21.469 17.37 21.667 ;
     RECT  18.615 11.435 20.07 21.703 ;
     RECT  60.336 18.805 73.17 21.703 ;
     RECT  73.98 21.631 136.026 21.703 ;
     RECT  0.54 21.667 17.694 21.739 ;
     RECT  18.468 21.703 20.07 21.739 ;
     RECT  137.016 5.341 141.93 21.811 ;
     RECT  0.54 21.739 20.07 22.009 ;
     RECT  20.808 5.693 31.41 22.009 ;
     RECT  137.016 21.811 142.29 22.009 ;
     RECT  143.028 21.361 143.046 22.009 ;
     RECT  137.016 22.009 143.046 22.207 ;
     RECT  58.392 4.145 59.49 22.315 ;
     RECT  60.336 21.703 136.026 22.315 ;
     RECT  52.992 4.145 57.582 22.441 ;
     RECT  58.392 22.315 136.026 22.441 ;
     RECT  32.436 4.793 33.174 22.477 ;
     RECT  40.215 11.471 41.382 22.477 ;
     RECT  42.12 10.049 45.897 22.477 ;
     RECT  0.54 22.009 31.41 22.541 ;
     RECT  36.864 4.379 39.366 22.549 ;
     RECT  40.215 22.477 45.897 22.549 ;
     RECT  46.728 4.541 48.69 22.549 ;
     RECT  1.044 22.541 31.41 22.585 ;
     RECT  52.992 22.441 136.026 22.585 ;
     RECT  136.908 22.207 143.046 22.585 ;
     RECT  1.044 22.585 31.518 22.621 ;
     RECT  32.292 22.477 33.174 22.621 ;
     RECT  34.02 4.145 36.09 22.621 ;
     RECT  49.428 4.541 52.074 22.621 ;
     RECT  52.992 22.585 143.046 22.621 ;
     RECT  1.044 22.621 36.09 22.711 ;
     RECT  36.864 22.549 48.69 22.711 ;
     RECT  1.044 22.711 48.69 22.891 ;
     RECT  49.428 22.621 143.046 22.891 ;
     RECT  1.044 22.891 143.046 23.165 ;
     RECT  1.08 23.165 143.046 23.309 ;
     RECT  1.116 23.309 143.046 23.585 ;
     RECT  1.116 23.585 139.302 23.645 ;
     RECT  1.152 23.645 139.302 23.657 ;
     RECT  1.152 23.657 27.666 23.729 ;
     RECT  31.752 23.657 139.302 23.729 ;
     RECT  57.96 23.729 139.302 23.741 ;
     RECT  21.096 23.729 25.254 23.777 ;
     RECT  31.752 23.729 36.666 23.777 ;
     RECT  1.152 23.729 20.358 23.855 ;
     RECT  21.096 23.777 23.634 23.933 ;
     RECT  25.992 23.729 27.666 23.933 ;
     RECT  28.44 23.657 31.014 23.933 ;
     RECT  31.752 23.777 34.29 23.933 ;
     RECT  35.244 23.777 36.666 23.933 ;
     RECT  37.512 23.729 38.394 23.933 ;
     RECT  39.168 23.729 42.426 23.933 ;
     RECT  43.164 23.729 57.222 23.933 ;
     RECT  57.96 23.741 134.118 23.933 ;
     RECT  134.856 23.741 139.302 23.933 ;
     RECT  131.904 23.933 133.362 23.999 ;
     RECT  29.376 23.933 31.014 24.509 ;
     RECT  48.168 23.933 53.082 24.509 ;
     RECT  53.856 23.933 56.358 24.509 ;
     RECT  140.04 23.585 143.046 24.557 ;
     RECT  1.152 23.855 9.81 24.811 ;
     RECT  1.152 24.811 10.386 24.859 ;
     RECT  11.16 23.855 20.358 24.859 ;
     RECT  46.548 23.933 47.322 25.085 ;
     RECT  48.168 24.509 49.842 25.085 ;
     RECT  21.96 23.933 23.634 25.133 ;
     RECT  48.96 25.085 49.842 25.133 ;
     RECT  50.58 24.509 53.082 25.133 ;
     RECT  22.752 25.133 23.634 25.805 ;
     RECT  24.372 23.777 25.254 25.805 ;
     RECT  29.376 24.509 30.15 25.805 ;
     RECT  31.752 23.933 32.634 25.805 ;
     RECT  33.408 23.933 34.29 25.805 ;
     RECT  37.512 23.933 37.602 25.805 ;
     RECT  40.788 23.933 41.562 25.805 ;
     RECT  43.164 23.933 43.29 25.805 ;
     RECT  51.444 25.133 53.082 25.805 ;
     RECT  54.72 24.509 56.358 25.805 ;
     RECT  58.824 23.933 131.13 25.805 ;
     RECT  137.088 23.933 138.546 25.805 ;
     RECT  35.244 23.933 35.91 25.861 ;
     RECT  38.376 23.933 38.394 25.861 ;
     RECT  44.208 23.933 44.946 25.861 ;
     RECT  25.992 23.933 26.874 25.882 ;
     RECT  26.01 25.882 26.856 25.889 ;
     RECT  35.028 25.861 35.91 25.882 ;
     RECT  35.046 25.882 35.892 25.889 ;
     RECT  44.064 25.861 44.946 25.882 ;
     RECT  44.082 25.882 44.928 25.889 ;
     RECT  55.476 25.805 56.358 25.882 ;
     RECT  55.494 25.882 56.34 25.889 ;
     RECT  1.152 24.859 20.358 25.882 ;
     RECT  1.17 25.882 1.44 25.901 ;
     RECT  1.458 25.882 1.62 25.901 ;
     RECT  1.638 25.882 1.8 25.901 ;
     RECT  1.818 25.882 2.016 25.901 ;
     RECT  2.034 25.882 2.196 25.901 ;
     RECT  2.214 25.882 2.376 25.901 ;
     RECT  2.394 25.882 2.592 25.901 ;
     RECT  2.61 25.882 2.772 25.901 ;
     RECT  2.79 25.882 3.06 25.901 ;
     RECT  3.078 25.882 3.24 25.901 ;
     RECT  3.258 25.882 3.456 25.901 ;
     RECT  3.474 25.882 3.636 25.901 ;
     RECT  3.654 25.882 3.816 25.901 ;
     RECT  3.834 25.882 4.032 25.901 ;
     RECT  4.05 25.882 4.212 25.901 ;
     RECT  4.23 25.882 4.5 25.901 ;
     RECT  4.518 25.882 4.68 25.901 ;
     RECT  4.698 25.882 4.896 25.901 ;
     RECT  4.914 25.882 5.076 25.901 ;
     RECT  5.094 25.882 5.256 25.901 ;
     RECT  5.274 25.882 5.472 25.901 ;
     RECT  5.49 25.882 5.652 25.901 ;
     RECT  5.67 25.882 5.832 25.901 ;
     RECT  5.85 25.882 6.12 25.901 ;
     RECT  6.138 25.882 6.336 25.901 ;
     RECT  6.354 25.882 6.516 25.901 ;
     RECT  6.534 25.882 6.696 25.901 ;
     RECT  6.714 25.882 6.912 25.901 ;
     RECT  6.93 25.882 7.092 25.901 ;
     RECT  7.11 25.882 7.272 25.901 ;
     RECT  7.29 25.882 7.56 25.901 ;
     RECT  7.578 25.882 7.776 25.901 ;
     RECT  7.794 25.882 7.956 25.901 ;
     RECT  7.974 25.882 8.136 25.901 ;
     RECT  8.154 25.882 8.352 25.901 ;
     RECT  8.37 25.882 8.532 25.901 ;
     RECT  8.55 25.882 8.712 25.901 ;
     RECT  8.73 25.882 8.928 25.901 ;
     RECT  8.946 25.882 9.216 25.901 ;
     RECT  9.234 25.882 9.396 25.901 ;
     RECT  9.414 25.882 9.576 25.901 ;
     RECT  9.594 25.882 9.792 25.901 ;
     RECT  9.81 25.882 9.972 25.901 ;
     RECT  9.99 25.882 10.152 25.901 ;
     RECT  10.17 25.882 10.368 25.901 ;
     RECT  10.386 25.882 10.548 25.901 ;
     RECT  10.566 25.882 10.836 25.901 ;
     RECT  10.854 25.882 11.016 25.901 ;
     RECT  11.034 25.882 11.232 25.901 ;
     RECT  11.25 25.882 11.412 25.901 ;
     RECT  11.43 25.882 11.592 25.901 ;
     RECT  11.61 25.882 11.808 25.901 ;
     RECT  11.826 25.882 11.988 25.901 ;
     RECT  12.006 25.882 12.276 25.901 ;
     RECT  12.294 25.882 12.456 25.901 ;
     RECT  12.474 25.882 12.672 25.901 ;
     RECT  12.69 25.882 12.852 25.901 ;
     RECT  12.87 25.882 13.248 25.901 ;
     RECT  13.266 25.882 13.608 25.901 ;
     RECT  13.626 25.882 14.004 25.901 ;
     RECT  14.022 25.882 14.4 25.901 ;
     RECT  14.418 25.882 14.868 25.901 ;
     RECT  14.886 25.882 15.264 25.901 ;
     RECT  15.282 25.882 15.624 25.901 ;
     RECT  15.642 25.882 16.128 25.901 ;
     RECT  16.146 25.882 16.488 25.901 ;
     RECT  16.506 25.882 16.884 25.901 ;
     RECT  16.902 25.882 17.28 25.901 ;
     RECT  17.298 25.882 17.748 25.901 ;
     RECT  17.766 25.882 18.144 25.901 ;
     RECT  18.162 25.882 18.504 25.901 ;
     RECT  18.522 25.882 18.9 25.901 ;
     RECT  18.918 25.882 19.368 25.901 ;
     RECT  19.386 25.882 19.764 25.901 ;
     RECT  19.782 25.882 20.34 25.901 ;
     RECT  59.616 25.805 131.13 25.882 ;
     RECT  59.634 25.882 60.264 25.901 ;
     RECT  60.282 25.882 60.66 25.901 ;
     RECT  60.678 25.882 61.056 25.901 ;
     RECT  61.074 25.882 61.416 25.901 ;
     RECT  61.434 25.882 61.92 25.901 ;
     RECT  61.938 25.882 62.28 25.901 ;
     RECT  62.298 25.882 62.676 25.901 ;
     RECT  62.694 25.882 63.072 25.901 ;
     RECT  63.09 25.882 63.54 25.901 ;
     RECT  63.558 25.882 63.936 25.901 ;
     RECT  63.954 25.882 64.296 25.901 ;
     RECT  64.314 25.882 64.692 25.901 ;
     RECT  64.71 25.882 65.16 25.901 ;
     RECT  65.178 25.882 65.556 25.901 ;
     RECT  65.574 25.882 65.952 25.901 ;
     RECT  65.97 25.882 66.42 25.901 ;
     RECT  66.438 25.882 66.816 25.901 ;
     RECT  66.834 25.882 67.176 25.901 ;
     RECT  67.194 25.882 67.572 25.901 ;
     RECT  67.59 25.882 68.04 25.901 ;
     RECT  68.058 25.882 68.436 25.901 ;
     RECT  68.454 25.882 68.832 25.901 ;
     RECT  68.85 25.882 69.192 25.901 ;
     RECT  69.21 25.882 69.696 25.901 ;
     RECT  69.714 25.882 70.056 25.901 ;
     RECT  70.074 25.882 70.452 25.901 ;
     RECT  70.47 25.882 70.848 25.901 ;
     RECT  70.866 25.882 71.316 25.901 ;
     RECT  71.334 25.882 71.712 25.901 ;
     RECT  71.73 25.882 72.072 25.901 ;
     RECT  72.09 25.882 72.468 25.901 ;
     RECT  72.486 25.882 72.936 25.901 ;
     RECT  72.954 25.882 73.332 25.901 ;
     RECT  73.35 25.882 73.728 25.901 ;
     RECT  73.746 25.882 74.196 25.901 ;
     RECT  74.214 25.882 74.592 25.901 ;
     RECT  74.61 25.882 74.952 25.901 ;
     RECT  74.97 25.882 75.348 25.901 ;
     RECT  75.366 25.882 75.816 25.901 ;
     RECT  75.834 25.882 76.212 25.901 ;
     RECT  76.23 25.882 76.608 25.901 ;
     RECT  76.626 25.882 76.968 25.901 ;
     RECT  76.986 25.882 77.472 25.901 ;
     RECT  77.49 25.882 77.832 25.901 ;
     RECT  77.85 25.882 78.228 25.901 ;
     RECT  78.246 25.882 78.624 25.901 ;
     RECT  78.642 25.882 79.092 25.901 ;
     RECT  79.11 25.882 79.488 25.901 ;
     RECT  79.506 25.882 79.848 25.901 ;
     RECT  79.866 25.882 80.352 25.901 ;
     RECT  80.37 25.882 80.712 25.901 ;
     RECT  80.73 25.882 81.108 25.901 ;
     RECT  81.126 25.882 81.504 25.901 ;
     RECT  81.522 25.882 81.972 25.901 ;
     RECT  81.99 25.882 82.368 25.901 ;
     RECT  82.386 25.882 82.728 25.901 ;
     RECT  82.746 25.882 83.124 25.901 ;
     RECT  83.142 25.882 83.592 25.901 ;
     RECT  83.61 25.882 83.988 25.901 ;
     RECT  84.006 25.882 84.384 25.901 ;
     RECT  84.402 25.882 84.744 25.901 ;
     RECT  84.762 25.882 85.248 25.901 ;
     RECT  85.266 25.882 85.608 25.901 ;
     RECT  85.626 25.882 86.004 25.901 ;
     RECT  86.022 25.882 86.472 25.901 ;
     RECT  86.49 25.882 86.868 25.901 ;
     RECT  86.886 25.882 87.264 25.901 ;
     RECT  87.282 25.882 87.624 25.901 ;
     RECT  87.642 25.882 88.128 25.901 ;
     RECT  88.146 25.882 88.488 25.901 ;
     RECT  88.506 25.882 88.884 25.901 ;
     RECT  88.902 25.882 89.28 25.901 ;
     RECT  89.298 25.882 89.748 25.901 ;
     RECT  89.766 25.882 90.144 25.901 ;
     RECT  90.162 25.882 90.504 25.901 ;
     RECT  90.522 25.882 90.9 25.901 ;
     RECT  90.918 25.882 91.368 25.901 ;
     RECT  91.386 25.882 91.764 25.901 ;
     RECT  91.782 25.882 92.16 25.901 ;
     RECT  92.178 25.882 92.52 25.901 ;
     RECT  92.538 25.882 93.024 25.901 ;
     RECT  93.042 25.882 93.384 25.901 ;
     RECT  93.402 25.882 93.78 25.901 ;
     RECT  93.798 25.882 94.248 25.901 ;
     RECT  94.266 25.882 94.644 25.901 ;
     RECT  94.662 25.882 95.04 25.901 ;
     RECT  95.058 25.882 95.4 25.901 ;
     RECT  95.418 25.882 95.904 25.901 ;
     RECT  95.922 25.882 96.264 25.901 ;
     RECT  96.282 25.882 96.66 25.901 ;
     RECT  96.678 25.882 97.056 25.901 ;
     RECT  97.074 25.882 97.524 25.901 ;
     RECT  97.542 25.882 97.92 25.901 ;
     RECT  97.938 25.882 98.28 25.901 ;
     RECT  98.298 25.882 98.676 25.901 ;
     RECT  98.694 25.882 99.144 25.901 ;
     RECT  99.162 25.882 99.54 25.901 ;
     RECT  99.558 25.882 99.936 25.901 ;
     RECT  99.954 25.882 100.404 25.901 ;
     RECT  100.422 25.882 100.8 25.901 ;
     RECT  100.818 25.882 101.16 25.901 ;
     RECT  101.178 25.882 101.556 25.901 ;
     RECT  101.574 25.882 102.024 25.901 ;
     RECT  102.042 25.882 102.42 25.901 ;
     RECT  102.438 25.882 102.816 25.901 ;
     RECT  102.834 25.882 103.176 25.901 ;
     RECT  103.194 25.882 103.68 25.901 ;
     RECT  103.698 25.882 104.04 25.901 ;
     RECT  104.058 25.882 104.436 25.901 ;
     RECT  104.454 25.882 104.832 25.901 ;
     RECT  104.85 25.882 105.3 25.901 ;
     RECT  105.318 25.882 105.696 25.901 ;
     RECT  105.714 25.882 106.056 25.901 ;
     RECT  106.074 25.882 106.56 25.901 ;
     RECT  106.578 25.882 106.92 25.901 ;
     RECT  106.938 25.882 107.316 25.901 ;
     RECT  107.334 25.882 107.712 25.901 ;
     RECT  107.73 25.882 108.18 25.901 ;
     RECT  108.198 25.882 108.576 25.901 ;
     RECT  108.594 25.882 108.936 25.901 ;
     RECT  108.954 25.882 109.332 25.901 ;
     RECT  109.35 25.882 109.8 25.901 ;
     RECT  109.818 25.882 110.196 25.901 ;
     RECT  110.214 25.882 110.592 25.901 ;
     RECT  110.61 25.882 110.952 25.901 ;
     RECT  110.97 25.882 111.456 25.901 ;
     RECT  111.474 25.882 111.816 25.901 ;
     RECT  111.834 25.882 112.212 25.901 ;
     RECT  112.23 25.882 112.608 25.901 ;
     RECT  112.626 25.882 113.076 25.901 ;
     RECT  113.094 25.882 113.472 25.901 ;
     RECT  113.49 25.882 113.832 25.901 ;
     RECT  113.85 25.882 114.336 25.901 ;
     RECT  114.354 25.882 114.696 25.901 ;
     RECT  114.714 25.882 115.092 25.901 ;
     RECT  115.11 25.882 115.488 25.901 ;
     RECT  115.506 25.882 115.956 25.901 ;
     RECT  115.974 25.882 116.352 25.901 ;
     RECT  116.37 25.882 116.712 25.901 ;
     RECT  116.73 25.882 117.108 25.901 ;
     RECT  117.126 25.882 117.576 25.901 ;
     RECT  117.594 25.882 117.972 25.901 ;
     RECT  117.99 25.882 118.368 25.901 ;
     RECT  118.386 25.882 118.728 25.901 ;
     RECT  118.746 25.882 119.232 25.901 ;
     RECT  119.25 25.882 119.592 25.901 ;
     RECT  119.61 25.882 119.988 25.901 ;
     RECT  120.006 25.882 120.456 25.901 ;
     RECT  120.474 25.882 120.852 25.901 ;
     RECT  120.87 25.882 121.248 25.901 ;
     RECT  121.266 25.882 121.608 25.901 ;
     RECT  121.626 25.882 122.112 25.901 ;
     RECT  122.13 25.882 122.472 25.901 ;
     RECT  122.49 25.882 122.868 25.901 ;
     RECT  122.886 25.882 123.264 25.901 ;
     RECT  123.282 25.882 123.732 25.901 ;
     RECT  123.75 25.882 124.128 25.901 ;
     RECT  124.146 25.882 124.488 25.901 ;
     RECT  124.506 25.882 124.884 25.901 ;
     RECT  124.902 25.882 125.352 25.901 ;
     RECT  125.37 25.882 125.748 25.901 ;
     RECT  125.766 25.882 126.144 25.901 ;
     RECT  126.162 25.882 126.612 25.901 ;
     RECT  126.63 25.882 127.008 25.901 ;
     RECT  127.026 25.882 127.368 25.901 ;
     RECT  127.386 25.882 127.764 25.901 ;
     RECT  127.782 25.882 128.232 25.901 ;
     RECT  128.25 25.882 128.628 25.901 ;
     RECT  128.646 25.882 129.024 25.901 ;
     RECT  129.042 25.882 129.384 25.901 ;
     RECT  129.402 25.882 129.888 25.901 ;
     RECT  129.906 25.882 130.248 25.901 ;
     RECT  130.266 25.882 130.644 25.901 ;
     RECT  130.662 25.882 131.112 25.901 ;
     RECT  131.904 23.999 132.57 25.882 ;
     RECT  131.922 25.882 132.552 25.901 ;
     RECT  134.856 23.933 135.558 25.882 ;
     RECT  134.874 25.882 135.54 25.901 ;
     RECT  137.844 25.805 138.546 25.882 ;
     RECT  137.862 25.882 138.528 25.901 ;
     RECT  140.832 24.557 141.498 25.882 ;
     RECT  140.85 25.882 141.48 25.901 ;
    LAYER M4 ;
     RECT  0.325 22.224 0.469 22.488 ;
     RECT  0.469 22.224 0.517 22.536 ;
     RECT  0.517 13.008 0.563 13.848 ;
     RECT  0.563 13.824 0.901 13.848 ;
     RECT  0.469 15.216 0.901 15.24 ;
     RECT  0.901 13.824 0.949 15.24 ;
     RECT  0.421 16.512 0.949 16.536 ;
     RECT  0.901 23.904 0.949 23.928 ;
     RECT  0.949 23.664 0.997 23.928 ;
     RECT  0.517 21.984 1.033 22.536 ;
     RECT  0.997 23.568 1.033 23.928 ;
     RECT  1.093 2.304 1.189 2.328 ;
     RECT  1.033 21.984 1.285 23.928 ;
     RECT  1.285 21.504 1.465 23.928 ;
     RECT  1.349 5.136 1.477 5.16 ;
     RECT  1.093 20.496 1.477 20.52 ;
     RECT  1.477 4.56 1.621 5.16 ;
     RECT  1.621 4.56 1.669 6.024 ;
     RECT  1.189 2.304 1.765 2.376 ;
     RECT  1.669 3.84 1.861 6.024 ;
     RECT  1.477 20.16 1.957 20.52 ;
     RECT  1.465 21.504 1.957 23.976 ;
     RECT  1.669 17.616 2.005 17.64 ;
     RECT  1.957 21.504 2.005 24.552 ;
     RECT  1.285 0.576 2.293 0.6 ;
     RECT  1.957 19.584 2.293 20.52 ;
     RECT  2.005 21.504 2.293 25.128 ;
     RECT  2.293 0.24 2.333 0.6 ;
     RECT  2.333 0.24 2.341 0.264 ;
     RECT  1.765 1.728 2.408 2.376 ;
     RECT  1.861 3.408 2.408 6.024 ;
     RECT  0.517 11.232 2.408 11.976 ;
     RECT  0.949 13.824 2.408 16.536 ;
     RECT  2.005 17.616 2.408 18.504 ;
     RECT  2.293 19.536 2.408 25.128 ;
     RECT  2.408 1.728 2.533 25.128 ;
     RECT  2.533 1.728 2.704 25.8 ;
     RECT  2.704 3.408 2.765 6.312 ;
     RECT  2.341 0.144 2.819 0.264 ;
     RECT  2.819 0.24 2.867 0.264 ;
     RECT  2.704 7.344 2.873 7.368 ;
     RECT  2.765 3.84 2.945 6.312 ;
     RECT  2.945 4.56 2.981 6.312 ;
     RECT  2.981 4.992 3.107 6.312 ;
     RECT  2.704 17.616 3.161 25.8 ;
     RECT  3.161 17.616 3.269 25.704 ;
     RECT  3.269 25.584 3.395 25.704 ;
     RECT  3.107 4.992 3.413 6.264 ;
     RECT  3.395 25.68 3.539 25.704 ;
     RECT  3.269 17.616 3.845 24.552 ;
     RECT  2.704 13.824 3.913 16.584 ;
     RECT  3.845 17.616 3.913 23.928 ;
     RECT  3.913 0.528 4.019 0.552 ;
     RECT  2.704 1.728 4.097 2.376 ;
     RECT  3.913 13.824 4.169 23.928 ;
     RECT  3.413 5.088 4.349 6.264 ;
     RECT  3.781 3.408 4.357 3.432 ;
     RECT  4.349 5.088 4.457 6.024 ;
     RECT  4.357 25.056 4.741 25.08 ;
     RECT  4.741 25.056 4.789 25.56 ;
     RECT  4.097 1.728 4.817 1.8 ;
     RECT  4.789 25.056 5.075 25.752 ;
     RECT  4.357 3.408 5.125 3.48 ;
     RECT  5.125 2.88 5.177 3.48 ;
     RECT  4.457 5.232 5.213 6.024 ;
     RECT  4.169 13.824 5.249 17.496 ;
     RECT  4.169 18.672 5.461 23.928 ;
     RECT  5.461 18.192 5.891 23.928 ;
     RECT  5.249 13.824 6.185 17.112 ;
     RECT  5.075 25.632 6.325 25.752 ;
     RECT  5.891 18.192 6.581 23.688 ;
     RECT  6.185 14.16 6.613 17.112 ;
     RECT  6.581 18.192 6.613 23.592 ;
     RECT  6.325 25.056 6.755 25.752 ;
     RECT  4.817 1.728 6.905 1.752 ;
     RECT  5.213 5.232 7.093 5.256 ;
     RECT  7.093 5.232 7.153 5.496 ;
     RECT  2.704 11.376 7.153 11.4 ;
     RECT  5.177 2.88 7.189 3.432 ;
     RECT  7.153 4.512 7.189 5.496 ;
     RECT  7.189 2.88 7.381 5.496 ;
     RECT  6.755 25.728 7.549 25.752 ;
     RECT  7.381 2.148 7.573 5.496 ;
     RECT  6.613 14.16 7.621 23.592 ;
     RECT  7.573 2.148 7.808 6.312 ;
     RECT  7.153 10.8 7.808 11.4 ;
     RECT  7.621 14.16 7.808 24.504 ;
     RECT  7.669 0.144 8.005 0.168 ;
     RECT  7.808 2.148 8.104 24.504 ;
     RECT  7.549 25.728 8.125 25.8 ;
     RECT  8.104 18.432 8.165 24.504 ;
     RECT  8.005 0.144 8.197 0.312 ;
     RECT  8.104 14.736 8.201 16.392 ;
     RECT  8.197 0.096 8.243 0.312 ;
     RECT  8.165 18.816 8.291 24.504 ;
     RECT  8.201 14.736 8.309 16.248 ;
     RECT  8.243 0.096 8.339 0.12 ;
     RECT  8.104 6.816 8.339 6.84 ;
     RECT  8.104 4.512 8.345 5.256 ;
     RECT  8.125 25.728 8.593 25.848 ;
     RECT  8.309 14.832 8.633 16.248 ;
     RECT  8.665 1.728 8.749 1.752 ;
     RECT  8.345 4.512 9.1 5.208 ;
     RECT  8.633 16.176 9.245 16.248 ;
     RECT  8.291 18.816 9.277 23.64 ;
     RECT  8.104 2.736 9.389 3.432 ;
     RECT  9.389 3.408 9.565 3.432 ;
     RECT  9.277 18.24 9.565 23.64 ;
     RECT  8.593 24.768 9.565 25.848 ;
     RECT  8.633 14.832 9.601 14.856 ;
     RECT  9.565 3.408 9.649 4.056 ;
     RECT  9.589 2.256 9.713 2.28 ;
     RECT  9.565 18.24 9.925 25.848 ;
     RECT  9.601 14.832 10.033 16.104 ;
     RECT  9.925 18.096 10.141 25.848 ;
     RECT  10.033 14.64 10.316 16.104 ;
     RECT  9.649 3.408 10.508 3.528 ;
     RECT  9.1 5.136 10.573 5.208 ;
     RECT  10.316 14.64 10.573 16.536 ;
     RECT  10.141 17.664 10.573 25.848 ;
     RECT  10.573 14.64 10.645 25.848 ;
     RECT  10.573 5.136 10.691 5.688 ;
     RECT  10.097 1.728 10.693 1.752 ;
     RECT  10.645 14.208 10.732 25.848 ;
     RECT  10.693 1.728 10.757 1.8 ;
     RECT  10.757 1.776 10.829 1.8 ;
     RECT  10.732 14.64 10.973 25.848 ;
     RECT  10.508 3.312 11.077 3.528 ;
     RECT  11.077 3.312 11.113 4.008 ;
     RECT  10.973 17.088 11.123 25.848 ;
     RECT  11.113 2.88 11.188 4.008 ;
     RECT  11.188 2.88 11.213 4.056 ;
     RECT  10.973 14.64 11.267 16.104 ;
     RECT  11.213 2.832 11.297 4.056 ;
     RECT  11.297 2.88 11.341 4.056 ;
     RECT  11.761 6.816 11.909 6.84 ;
     RECT  11.341 3.984 11.981 4.056 ;
     RECT  11.123 18.24 11.981 25.848 ;
     RECT  11.267 15.84 12.044 16.104 ;
     RECT  11.123 17.088 12.044 17.208 ;
     RECT  12.044 15.84 12.125 17.208 ;
     RECT  12.125 15.84 12.131 16.2 ;
     RECT  12.125 17.184 12.221 17.208 ;
     RECT  11.981 18.24 12.221 18.792 ;
     RECT  11.267 14.64 12.284 14.664 ;
     RECT  12.284 14.64 12.332 14.808 ;
     RECT  12.131 15.84 12.332 15.96 ;
     RECT  11.341 2.88 12.481 2.904 ;
     RECT  12.332 14.64 12.62 15.96 ;
     RECT  12.62 14.544 12.769 15.96 ;
     RECT  12.481 2.88 12.985 3.432 ;
     RECT  12.985 2.88 13.057 3.864 ;
     RECT  10.691 5.136 13.057 5.208 ;
     RECT  11.981 19.776 13.139 25.848 ;
     RECT  12.121 1.728 13.208 1.752 ;
     RECT  13.057 2.88 13.208 5.208 ;
     RECT  8.104 11.376 13.208 11.4 ;
     RECT  12.769 14.208 13.208 15.96 ;
     RECT  12.221 17.184 13.208 18.792 ;
     RECT  13.139 19.776 13.208 25.8 ;
     RECT  13.208 1.728 13.504 25.8 ;
     RECT  13.504 19.776 13.619 25.8 ;
     RECT  13.619 19.776 13.667 25.656 ;
     RECT  13.667 19.776 13.715 25.56 ;
     RECT  13.715 19.776 13.811 24.84 ;
     RECT  13.504 17.088 13.859 17.304 ;
     RECT  13.859 17.088 13.907 17.16 ;
     RECT  13.811 20.592 14.033 24.84 ;
     RECT  13.504 15.888 14.099 15.912 ;
     RECT  13.907 17.088 14.147 17.112 ;
     RECT  13.504 2.832 14.291 2.856 ;
     RECT  13.504 3.84 14.329 5.688 ;
     RECT  14.033 21.072 14.387 24.84 ;
     RECT  14.492 16.992 14.579 17.016 ;
     RECT  14.329 3.84 14.636 5.4 ;
     RECT  14.636 3.408 14.723 5.4 ;
     RECT  13.504 1.728 14.789 1.752 ;
     RECT  13.504 11.376 14.821 11.4 ;
     RECT  14.821 11.28 14.861 11.4 ;
     RECT  14.387 21.072 15.049 24.792 ;
     RECT  14.893 0.576 15.059 0.6 ;
     RECT  14.993 25.776 15.077 25.8 ;
     RECT  15.049 21.552 15.443 24.792 ;
     RECT  14.723 3.408 15.469 3.432 ;
     RECT  15.443 21.552 15.484 24.504 ;
     RECT  15.484 21.648 15.539 24.504 ;
     RECT  15.469 1.152 15.553 1.176 ;
     RECT  15.469 2.832 15.685 3.432 ;
     RECT  15.685 2.256 15.692 3.432 ;
     RECT  14.723 4.464 15.692 5.4 ;
     RECT  15.692 2.256 15.923 5.4 ;
     RECT  15.539 22.176 15.941 24.504 ;
     RECT  15.941 22.176 16.337 23.4 ;
     RECT  15.923 2.832 16.405 5.4 ;
     RECT  15.941 24.48 16.481 24.504 ;
     RECT  16.337 23.376 16.633 23.4 ;
     RECT  16.405 2.832 16.813 5.688 ;
     RECT  16.261 1.728 16.885 1.752 ;
     RECT  16.813 2.832 16.885 5.496 ;
     RECT  16.844 0.048 16.931 0.072 ;
     RECT  16.885 1.728 16.985 5.496 ;
     RECT  16.741 21.12 17.345 21.144 ;
     RECT  16.985 3.216 17.797 5.496 ;
     RECT  16.337 22.176 17.909 22.2 ;
     RECT  17.773 23.376 17.909 23.4 ;
     RECT  17.797 3.216 18.125 5.688 ;
     RECT  16.645 25.776 18.133 25.8 ;
     RECT  18.133 25.776 18.275 25.848 ;
     RECT  18.275 25.776 18.373 25.8 ;
     RECT  17.909 22.176 18.469 23.4 ;
     RECT  18.373 25.056 18.605 25.8 ;
     RECT  16.985 1.728 18.608 1.752 ;
     RECT  18.125 2.832 18.608 5.688 ;
     RECT  14.861 11.28 18.608 11.304 ;
     RECT  18.469 21.504 18.608 23.4 ;
     RECT  18.605 25.776 18.803 25.8 ;
     RECT  18.608 1.728 18.904 23.772 ;
     RECT  18.889 0.048 19.043 0.072 ;
     RECT  18.904 22.8 19.235 23.772 ;
     RECT  19.235 22.8 19.283 22.824 ;
     RECT  18.904 21.12 19.333 21.672 ;
     RECT  18.904 3.024 19.433 5.688 ;
     RECT  19.333 21.648 19.505 21.672 ;
     RECT  19.525 23.904 19.789 23.928 ;
     RECT  19.789 23.904 19.937 24.552 ;
     RECT  19.433 3.024 20.045 4.104 ;
     RECT  19.937 24.528 20.051 24.552 ;
     RECT  19.433 5.472 20.225 5.688 ;
     RECT  20.045 3.312 20.501 4.104 ;
     RECT  20.225 5.472 20.501 5.496 ;
     RECT  20.501 3.312 20.585 5.496 ;
     RECT  20.585 3.312 20.801 4.104 ;
     RECT  21.541 23.904 21.629 23.928 ;
     RECT  20.801 3.312 21.665 3.432 ;
     RECT  20.677 22.752 21.989 22.776 ;
     RECT  22.345 25.104 22.451 25.128 ;
     RECT  18.904 11.28 22.777 11.304 ;
     RECT  22.777 11.28 22.817 11.4 ;
     RECT  21.665 3.408 23.821 3.432 ;
     RECT  18.904 1.728 24.008 1.752 ;
     RECT  23.821 3.408 24.008 3.96 ;
     RECT  20.585 5.472 24.008 5.496 ;
     RECT  22.817 11.376 24.008 11.4 ;
     RECT  24.008 1.728 24.112 23.772 ;
     RECT  24.112 1.728 24.304 23.502 ;
     RECT  24.304 3.12 24.545 3.96 ;
     RECT  24.545 3.12 26.089 3.144 ;
     RECT  24.304 5.472 26.125 5.496 ;
     RECT  26.089 3.12 26.129 3.432 ;
     RECT  23.173 25.776 26.561 25.8 ;
     RECT  26.129 3.408 27.349 3.432 ;
     RECT  26.125 4.512 27.349 5.496 ;
     RECT  27.349 3.408 27.395 5.496 ;
     RECT  27.395 3.408 27.785 4.536 ;
     RECT  27.269 23.904 29.081 23.928 ;
     RECT  24.304 1.728 29.408 1.752 ;
     RECT  27.785 3.408 29.408 4.248 ;
     RECT  24.304 11.376 29.408 11.4 ;
     RECT  29.408 1.728 29.512 23.772 ;
     RECT  29.512 1.728 29.704 23.502 ;
     RECT  29.701 25.776 30.017 25.8 ;
     RECT  29.704 3.408 30.449 4.152 ;
     RECT  30.409 24.48 30.611 24.504 ;
     RECT  29.704 11.376 30.769 11.4 ;
     RECT  30.769 11.28 30.809 11.4 ;
     RECT  31.333 25.776 31.925 25.8 ;
     RECT  30.449 3.792 32.173 4.152 ;
     RECT  32.165 24.48 32.249 24.504 ;
     RECT  32.957 23.904 33.041 23.928 ;
     RECT  32.173 3.408 33.073 4.152 ;
     RECT  33.073 3.024 33.113 4.152 ;
     RECT  33.829 25.776 34.085 25.8 ;
     RECT  33.113 3.024 34.477 3.048 ;
     RECT  33.113 4.08 34.477 4.152 ;
     RECT  29.704 1.728 34.808 1.752 ;
     RECT  34.477 3.024 34.808 4.248 ;
     RECT  30.809 11.28 34.808 11.304 ;
     RECT  34.597 23.376 34.808 23.4 ;
     RECT  34.808 1.728 34.912 23.772 ;
     RECT  34.912 1.728 35.104 23.502 ;
     RECT  35.104 1.728 36.397 1.752 ;
     RECT  35.104 3.408 36.497 4.152 ;
     RECT  36.325 23.904 36.497 23.928 ;
     RECT  35.104 22.752 36.641 22.776 ;
     RECT  37.069 0.576 37.153 0.6 ;
     RECT  37.093 25.776 37.613 25.8 ;
     RECT  36.497 3.888 37.681 4.152 ;
     RECT  37.925 23.904 38.009 23.928 ;
     RECT  37.681 3.888 38.441 4.392 ;
     RECT  35.104 11.28 38.725 11.304 ;
     RECT  38.725 11.28 38.765 11.4 ;
     RECT  38.441 4.128 39.265 4.392 ;
     RECT  38.684 23.376 39.589 23.4 ;
     RECT  39.733 2.832 39.836 2.856 ;
     RECT  39.265 4.128 39.836 4.488 ;
     RECT  37.925 1.728 40.208 1.752 ;
     RECT  39.836 2.832 40.208 4.488 ;
     RECT  38.765 11.376 40.208 11.4 ;
     RECT  39.589 23.376 40.208 23.928 ;
     RECT  40.208 1.728 40.429 23.928 ;
     RECT  40.429 2.418 40.504 23.502 ;
     RECT  40.504 4.128 40.565 4.488 ;
     RECT  41.029 0.576 41.267 0.6 ;
     RECT  40.565 4.128 41.533 4.152 ;
     RECT  41.221 25.776 41.537 25.8 ;
     RECT  41.533 3.936 41.749 4.152 ;
     RECT  40.504 9.744 41.795 10.104 ;
     RECT  41.989 23.904 42.185 23.928 ;
     RECT  42.853 25.776 43.193 25.8 ;
     RECT  41.989 1.728 43.697 1.752 ;
     RECT  43.621 23.904 43.733 23.928 ;
     RECT  44.485 0.576 44.569 0.6 ;
     RECT  44.485 25.776 44.633 25.8 ;
     RECT  44.533 2.832 44.725 2.856 ;
     RECT  44.725 2.784 44.953 2.856 ;
     RECT  41.749 3.936 44.953 4.392 ;
     RECT  44.557 23.376 45.253 23.4 ;
     RECT  45.253 1.728 45.608 1.752 ;
     RECT  44.953 2.784 45.608 4.392 ;
     RECT  41.795 10.08 45.608 10.104 ;
     RECT  40.504 11.376 45.608 11.4 ;
     RECT  45.253 23.376 45.608 23.928 ;
     RECT  45.608 1.728 45.904 23.928 ;
     RECT  45.904 1.728 46.163 1.752 ;
     RECT  45.904 23.424 46.181 23.928 ;
     RECT  46.789 0.576 46.931 0.6 ;
     RECT  46.853 25.056 46.937 25.08 ;
     RECT  46.181 23.424 47.261 23.448 ;
     RECT  45.904 3.6 47.66 4.536 ;
     RECT  47.66 2.832 47.747 4.536 ;
     RECT  47.717 23.904 47.801 23.928 ;
     RECT  47.747 3.6 48.233 4.536 ;
     RECT  48.517 25.056 48.601 25.08 ;
     RECT  48.233 3.888 49.097 4.536 ;
     RECT  49.201 25.104 49.427 25.128 ;
     RECT  49.097 3.888 49.957 4.392 ;
     RECT  50.245 24.48 50.501 24.504 ;
     RECT  49.957 3.84 50.893 4.392 ;
     RECT  47.473 1.728 51.008 1.752 ;
     RECT  50.893 3.84 51.008 4.488 ;
     RECT  45.904 10.08 51.008 10.104 ;
     RECT  45.904 11.376 51.008 11.4 ;
     RECT  51.008 1.728 51.059 23.772 ;
     RECT  50.965 25.104 51.059 25.128 ;
     RECT  51.059 2.148 51.112 23.772 ;
     RECT  51.112 2.418 51.304 23.502 ;
     RECT  51.793 0.096 51.923 0.12 ;
     RECT  51.877 25.776 52.877 25.8 ;
     RECT  51.304 3.936 53.093 4.488 ;
     RECT  53.093 4.032 53.557 4.488 ;
     RECT  53.477 23.904 53.561 23.928 ;
     RECT  54.277 24.48 54.569 24.504 ;
     RECT  53.557 4.032 54.781 4.92 ;
     RECT  55.141 25.776 56.081 25.8 ;
     RECT  52.621 1.728 56.408 1.752 ;
     RECT  54.781 3.408 56.408 4.92 ;
     RECT  51.304 10.08 56.408 10.104 ;
     RECT  51.304 11.376 56.408 11.4 ;
     RECT  56.408 1.728 56.704 23.772 ;
     RECT  56.704 23.376 56.773 23.772 ;
     RECT  56.773 23.376 57.017 23.928 ;
     RECT  57.017 23.376 57.587 23.4 ;
     RECT  56.704 3.408 57.841 3.432 ;
     RECT  56.704 4.896 57.841 4.92 ;
     RECT  57.841 3.408 57.881 4.92 ;
     RECT  56.704 11.376 58.705 11.4 ;
     RECT  58.405 23.904 58.709 23.928 ;
     RECT  58.705 11.232 58.745 11.4 ;
     RECT  59.165 25.776 59.249 25.8 ;
     RECT  57.881 3.6 59.285 4.92 ;
     RECT  59.285 3.84 60.505 4.92 ;
     RECT  60.421 25.776 60.797 25.8 ;
     RECT  56.704 1.728 61.808 1.752 ;
     RECT  60.505 3.84 61.808 4.968 ;
     RECT  56.704 10.08 61.808 10.104 ;
     RECT  58.745 11.232 61.808 11.256 ;
     RECT  61.649 21.648 61.808 21.672 ;
     RECT  60.029 23.904 61.808 23.928 ;
     RECT  61.225 25.104 62.099 25.128 ;
     RECT  61.808 1.728 62.104 23.928 ;
     RECT  62.104 23.376 62.461 23.928 ;
     RECT  62.104 3.744 63.097 4.968 ;
     RECT  62.104 1.728 63.101 1.752 ;
     RECT  63.241 0.096 63.347 0.12 ;
     RECT  63.097 3.408 63.353 4.968 ;
     RECT  62.461 23.568 63.641 23.928 ;
     RECT  63.644 2.256 63.731 2.28 ;
     RECT  63.641 23.568 63.731 23.88 ;
     RECT  62.104 22.128 63.961 22.152 ;
     RECT  63.731 23.568 63.961 23.592 ;
     RECT  63.353 4.512 64.028 4.968 ;
     RECT  64.028 4.512 64.115 5.112 ;
     RECT  63.961 22.128 64.115 23.592 ;
     RECT  64.115 22.128 64.357 23.4 ;
     RECT  64.357 21.648 64.403 23.4 ;
     RECT  64.508 25.104 64.595 25.128 ;
     RECT  64.115 4.512 64.649 4.968 ;
     RECT  64.403 21.648 64.892 22.776 ;
     RECT  63.353 3.408 64.94 3.432 ;
     RECT  64.892 21.552 64.979 22.776 ;
     RECT  64.94 3.216 65.027 3.432 ;
     RECT  64.979 22.224 65.027 22.776 ;
     RECT  65.027 3.408 65.077 3.432 ;
     RECT  64.649 4.512 65.077 4.536 ;
     RECT  65.077 3.408 65.117 4.536 ;
     RECT  65.027 22.224 65.153 22.248 ;
     RECT  65.185 25.776 65.363 25.8 ;
     RECT  65.117 3.936 65.869 4.536 ;
     RECT  65.797 25.056 65.945 25.08 ;
     RECT  65.869 3.936 66.197 4.68 ;
     RECT  64.165 1.728 66.517 1.752 ;
     RECT  66.373 22.8 66.524 22.824 ;
     RECT  66.524 22.8 66.661 23.4 ;
     RECT  66.181 24.48 66.665 24.504 ;
     RECT  66.661 21.984 66.941 23.4 ;
     RECT  66.517 1.728 67.208 2.28 ;
     RECT  66.197 4.512 67.208 4.68 ;
     RECT  62.104 10.08 67.208 10.104 ;
     RECT  62.104 11.376 67.208 11.4 ;
     RECT  66.941 21.648 67.208 23.4 ;
     RECT  67.208 1.728 67.504 23.928 ;
     RECT  67.504 3.456 67.889 4.68 ;
     RECT  67.504 1.728 68.141 1.8 ;
     RECT  67.813 25.776 68.357 25.8 ;
     RECT  67.504 21.984 68.393 23.928 ;
     RECT  68.393 21.984 68.573 23.448 ;
     RECT  68.573 23.376 68.579 23.448 ;
     RECT  67.889 3.936 68.965 4.68 ;
     RECT  68.573 21.984 68.969 22.2 ;
     RECT  68.581 25.056 69.221 25.08 ;
     RECT  68.141 1.728 69.289 1.752 ;
     RECT  68.965 3.936 69.397 4.872 ;
     RECT  69.289 1.728 69.491 2.28 ;
     RECT  68.969 22.176 69.577 22.2 ;
     RECT  68.579 23.376 69.577 23.4 ;
     RECT  69.397 3.408 69.685 4.872 ;
     RECT  69.577 22.176 69.721 23.4 ;
     RECT  69.445 24.48 69.721 24.504 ;
     RECT  69.721 22.176 69.875 24.504 ;
     RECT  69.875 22.176 70.013 23.448 ;
     RECT  70.013 22.224 70.093 23.448 ;
     RECT  69.875 24.48 70.268 24.504 ;
     RECT  70.268 24.48 70.355 24.552 ;
     RECT  70.093 22.224 70.451 23.4 ;
     RECT  69.685 3.408 70.933 5.208 ;
     RECT  70.933 3.36 70.988 5.208 ;
     RECT  69.491 1.728 71.045 1.752 ;
     RECT  70.988 3.312 71.075 5.208 ;
     RECT  71.075 3.36 71.165 5.208 ;
     RECT  70.451 22.224 71.221 22.296 ;
     RECT  67.504 11.376 71.237 11.4 ;
     RECT  70.355 24.48 71.237 24.504 ;
     RECT  71.221 21.648 71.381 22.296 ;
     RECT  71.461 25.776 71.633 25.8 ;
     RECT  71.165 3.792 71.653 5.208 ;
     RECT  71.045 1.728 71.665 1.848 ;
     RECT  71.381 22.176 71.845 22.296 ;
     RECT  70.451 23.376 71.845 23.4 ;
     RECT  71.845 22.176 71.909 23.4 ;
     RECT  71.653 3.792 72.277 5.592 ;
     RECT  67.504 10.08 72.421 10.104 ;
     RECT  71.665 1.728 72.608 2.28 ;
     RECT  72.277 3.312 72.608 5.592 ;
     RECT  72.421 10.08 72.608 10.872 ;
     RECT  71.909 22.176 72.608 23.928 ;
     RECT  72.608 1.728 72.904 23.928 ;
     RECT  72.904 22.176 72.965 23.928 ;
     RECT  72.904 2.832 73.253 5.592 ;
     RECT  73.253 2.832 73.657 5.256 ;
     RECT  72.965 22.176 73.793 23.592 ;
     RECT  72.904 1.728 73.861 1.752 ;
     RECT  73.573 25.776 73.901 25.8 ;
     RECT  73.793 22.8 73.907 23.592 ;
     RECT  73.907 23.376 73.957 23.592 ;
     RECT  73.657 3.216 74.003 5.256 ;
     RECT  73.957 23.376 74.339 23.928 ;
     RECT  73.861 1.104 74.341 1.752 ;
     RECT  74.339 23.568 74.341 23.928 ;
     RECT  74.341 1.104 74.387 2.232 ;
     RECT  74.341 23.568 74.549 24.504 ;
     RECT  74.003 3.312 74.627 5.256 ;
     RECT  74.549 23.568 74.627 23.976 ;
     RECT  74.627 23.952 74.771 23.976 ;
     RECT  75.301 22.8 75.449 22.824 ;
     RECT  74.627 3.312 75.661 3.432 ;
     RECT  74.627 4.512 75.661 5.256 ;
     RECT  75.661 3.312 75.665 5.256 ;
     RECT  75.665 3.408 75.827 5.256 ;
     RECT  74.387 1.728 75.881 2.232 ;
     RECT  76.093 22.656 76.205 22.68 ;
     RECT  76.453 25.776 76.781 25.8 ;
     RECT  75.205 21.648 76.853 21.672 ;
     RECT  75.589 23.904 76.889 23.928 ;
     RECT  75.881 1.728 77.093 1.752 ;
     RECT  75.827 4.656 77.125 5.256 ;
     RECT  77.125 4.608 77.173 5.256 ;
     RECT  77.221 24.48 77.597 24.504 ;
     RECT  77.597 24.48 77.681 25.08 ;
     RECT  77.093 1.728 77.753 2.28 ;
     RECT  77.753 2.148 77.893 2.28 ;
     RECT  75.827 3.408 77.893 3.432 ;
     RECT  77.893 0.528 77.929 0.552 ;
     RECT  77.893 2.148 78.008 3.432 ;
     RECT  77.173 4.56 78.008 5.256 ;
     RECT  77.681 24.48 78.008 24.504 ;
     RECT  78.008 2.148 78.112 24.504 ;
     RECT  77.929 0.096 78.131 0.552 ;
     RECT  78.131 0.528 78.257 0.552 ;
     RECT  78.112 2.148 78.304 23.502 ;
     RECT  78.112 24.48 78.581 24.504 ;
     RECT  78.304 21.552 78.653 22.824 ;
     RECT  78.304 2.148 78.748 5.256 ;
     RECT  78.748 2.832 78.761 5.256 ;
     RECT  78.653 22.32 79.013 22.824 ;
     RECT  78.853 25.056 79.085 25.08 ;
     RECT  79.013 22.8 79.283 22.824 ;
     RECT  79.237 23.904 79.513 23.928 ;
     RECT  78.853 1.728 79.717 1.8 ;
     RECT  79.717 1.728 79.805 1.896 ;
     RECT  79.513 23.376 80.269 23.928 ;
     RECT  80.269 22.8 80.669 23.928 ;
     RECT  78.761 3.312 80.677 5.256 ;
     RECT  80.677 3.216 80.773 5.256 ;
     RECT  79.805 1.728 80.869 1.752 ;
     RECT  80.869 1.728 80.909 1.8 ;
     RECT  80.773 3.216 80.909 5.4 ;
     RECT  80.869 21.648 81.349 21.672 ;
     RECT  80.909 1.728 81.425 5.4 ;
     RECT  80.669 22.8 81.443 23.448 ;
     RECT  81.425 2.832 81.497 5.4 ;
     RECT  81.349 21.6 81.497 21.672 ;
     RECT  81.443 23.376 81.733 23.448 ;
     RECT  81.497 3.408 81.781 5.4 ;
     RECT  81.497 21.648 81.893 21.672 ;
     RECT  81.781 3.408 82.108 5.688 ;
     RECT  81.733 23.376 82.493 23.928 ;
     RECT  81.425 1.728 82.501 1.752 ;
     RECT  82.493 23.28 82.613 23.928 ;
     RECT  82.613 23.28 83.005 23.772 ;
     RECT  82.501 1.728 83.105 1.8 ;
     RECT  82.108 3.408 83.125 3.432 ;
     RECT  82.108 4.512 83.125 5.688 ;
     RECT  82.609 25.104 83.269 25.128 ;
     RECT  83.269 25.104 83.365 25.8 ;
     RECT  83.105 1.728 83.408 2.28 ;
     RECT  83.125 3.408 83.408 5.688 ;
     RECT  83.269 21.504 83.408 21.528 ;
     RECT  83.005 22.8 83.408 23.772 ;
     RECT  83.408 1.728 83.512 23.772 ;
     RECT  83.512 1.728 83.704 23.502 ;
     RECT  83.704 4.512 83.765 5.496 ;
     RECT  83.365 25.056 83.795 25.8 ;
     RECT  83.704 21.504 83.801 22.2 ;
     RECT  83.704 1.728 83.837 3.432 ;
     RECT  83.837 2.832 83.981 3.432 ;
     RECT  83.765 4.8 84.269 5.496 ;
     RECT  83.795 25.056 84.305 25.08 ;
     RECT  83.801 22.176 84.665 22.2 ;
     RECT  83.981 3.312 84.707 3.432 ;
     RECT  83.704 23.376 84.707 23.448 ;
     RECT  84.707 3.408 84.913 3.432 ;
     RECT  84.269 4.8 84.913 5.256 ;
     RECT  84.913 22.8 84.997 22.824 ;
     RECT  84.977 24.48 85.061 24.504 ;
     RECT  83.837 1.728 85.381 1.752 ;
     RECT  85.381 1.728 85.465 1.848 ;
     RECT  85.777 23.376 85.861 23.4 ;
     RECT  85.861 0.096 85.961 0.12 ;
     RECT  85.381 21.648 85.997 21.672 ;
     RECT  84.913 3.408 86.005 5.256 ;
     RECT  85.861 23.472 86.033 23.496 ;
     RECT  86.005 3.216 86.341 5.256 ;
     RECT  86.341 2.832 86.428 5.256 ;
     RECT  86.237 24.48 86.629 24.504 ;
     RECT  86.428 3.312 86.825 5.256 ;
     RECT  86.629 23.904 86.897 24.504 ;
     RECT  86.897 24.48 87.077 24.504 ;
     RECT  86.825 3.36 87.445 5.256 ;
     RECT  87.433 23.376 87.517 23.4 ;
     RECT  87.493 25.776 87.761 25.8 ;
     RECT  87.877 24.528 87.964 24.552 ;
     RECT  87.445 3.36 88.397 5.496 ;
     RECT  88.253 23.904 88.697 24.504 ;
     RECT  85.465 1.728 88.705 1.752 ;
     RECT  88.397 2.832 88.808 5.496 ;
     RECT  88.808 2.148 88.912 23.772 ;
     RECT  88.912 2.256 89.104 23.502 ;
     RECT  89.125 25.776 89.381 25.8 ;
     RECT  89.104 2.256 89.561 5.256 ;
     RECT  89.477 25.056 89.561 25.08 ;
     RECT  89.561 2.256 89.893 2.28 ;
     RECT  89.104 23.376 89.893 23.502 ;
     RECT  89.893 1.728 89.965 2.28 ;
     RECT  89.561 3.312 90.173 5.256 ;
     RECT  89.125 0.096 90.419 0.12 ;
     RECT  90.385 22.224 90.713 22.248 ;
     RECT  90.469 6.24 91.109 6.264 ;
     RECT  89.965 1.728 91.133 1.752 ;
     RECT  90.173 3.408 91.213 5.256 ;
     RECT  89.893 23.376 91.217 23.928 ;
     RECT  91.217 23.376 91.645 23.448 ;
     RECT  91.645 22.8 91.729 23.448 ;
     RECT  91.141 21.648 91.793 21.672 ;
     RECT  91.133 1.728 92.051 2.28 ;
     RECT  92.051 1.728 92.125 2.184 ;
     RECT  91.213 3.312 92.284 5.256 ;
     RECT  92.284 4.56 92.297 5.256 ;
     RECT  92.284 3.312 92.387 3.336 ;
     RECT  91.729 23.376 92.51 23.448 ;
     RECT  92.297 4.8 93.26 5.256 ;
     RECT  92.005 24.48 93.269 24.504 ;
     RECT  92.125 1.728 93.98 1.752 ;
     RECT  92.773 21.648 93.98 21.672 ;
     RECT  93.98 1.728 94.069 2.28 ;
     RECT  94.069 1.728 94.208 2.856 ;
     RECT  93.26 3.888 94.208 5.256 ;
     RECT  93.98 21.648 94.208 22.152 ;
     RECT  92.51 23.376 94.208 23.4 ;
     RECT  94.208 1.728 94.405 23.772 ;
     RECT  94.405 1.728 94.504 23.88 ;
     RECT  94.504 23.856 94.637 23.88 ;
     RECT  94.504 2.832 95.393 5.256 ;
     RECT  94.504 21.12 95.507 21.144 ;
     RECT  95.653 21.648 95.861 21.672 ;
     RECT  94.789 24.48 96.037 24.504 ;
     RECT  95.597 22.8 96.361 22.824 ;
     RECT  96.037 23.904 96.361 24.504 ;
     RECT  96.361 22.8 96.515 24.504 ;
     RECT  95.393 2.832 96.649 2.856 ;
     RECT  95.393 3.84 96.649 5.256 ;
     RECT  96.649 2.832 96.725 5.256 ;
     RECT  96.515 23.904 96.761 24.504 ;
     RECT  96.515 22.8 96.901 22.824 ;
     RECT  96.793 0.096 96.947 0.12 ;
     RECT  96.725 3.312 97.049 5.256 ;
     RECT  96.761 23.904 97.049 23.976 ;
     RECT  96.901 22.032 97.477 22.824 ;
     RECT  97.049 4.512 97.589 5.256 ;
     RECT  97.049 3.312 97.625 3.528 ;
     RECT  97.477 22.032 97.661 22.872 ;
     RECT  97.661 22.224 98.003 22.872 ;
     RECT  97.589 4.512 98.029 5.208 ;
     RECT  97.049 23.952 98.237 23.976 ;
     RECT  97.625 3.504 98.444 3.528 ;
     RECT  94.504 1.728 98.521 1.752 ;
     RECT  98.444 3.504 98.531 3.768 ;
     RECT  98.521 1.728 98.605 1.848 ;
     RECT  98.531 3.504 98.633 3.528 ;
     RECT  98.003 22.224 98.917 22.824 ;
     RECT  98.917 22.176 99.205 22.824 ;
     RECT  98.513 23.904 99.205 23.928 ;
     RECT  99.205 22.176 99.301 23.928 ;
     RECT  98.029 5.184 99.445 5.208 ;
     RECT  99.301 22.176 99.497 23.976 ;
     RECT  98.605 1.728 99.608 1.752 ;
     RECT  99.565 3.408 99.608 3.432 ;
     RECT  99.445 4.512 99.608 5.208 ;
     RECT  99.497 22.176 99.608 23.772 ;
     RECT  99.608 1.728 99.712 23.772 ;
     RECT  99.712 1.728 99.904 23.502 ;
     RECT  99.904 3.312 100.019 5.208 ;
     RECT  99.904 21.648 100.115 23.4 ;
     RECT  99.781 25.776 100.115 25.8 ;
     RECT  100.019 3.312 100.163 3.96 ;
     RECT  100.115 22.752 100.217 23.4 ;
     RECT  100.549 24.528 100.721 24.552 ;
     RECT  100.933 24.48 101.333 24.504 ;
     RECT  99.904 1.728 101.393 1.752 ;
     RECT  100.115 21.648 101.413 21.672 ;
     RECT  101.393 1.728 101.477 1.8 ;
     RECT  100.163 3.408 101.564 3.96 ;
     RECT  100.019 5.184 101.564 5.208 ;
     RECT  101.564 3.408 101.651 5.208 ;
     RECT  100.217 23.376 101.651 23.4 ;
     RECT  101.413 21.552 101.729 21.672 ;
     RECT  101.729 21.648 101.797 21.672 ;
     RECT  101.797 21.648 102.611 22.248 ;
     RECT  101.651 3.408 103.052 3.432 ;
     RECT  103.052 3.408 103.139 3.768 ;
     RECT  103.045 23.904 103.165 23.928 ;
     RECT  101.651 5.184 103.189 5.208 ;
     RECT  102.611 22.176 103.597 22.248 ;
     RECT  103.165 23.376 103.597 23.928 ;
     RECT  103.597 22.176 103.921 23.928 ;
     RECT  103.139 3.408 103.957 3.432 ;
     RECT  103.921 21.744 104.003 23.928 ;
     RECT  103.957 3.312 104.245 3.432 ;
     RECT  103.189 4.56 104.245 5.208 ;
     RECT  101.477 1.728 104.429 1.752 ;
     RECT  104.245 3.312 104.677 5.208 ;
     RECT  104.003 21.744 104.869 22.2 ;
     RECT  104.677 2.88 104.893 5.208 ;
     RECT  104.893 2.784 105.008 5.208 ;
     RECT  104.869 21.504 105.008 22.2 ;
     RECT  104.003 23.376 105.008 23.928 ;
     RECT  104.869 25.776 105.107 25.8 ;
     RECT  105.008 1.968 105.304 23.928 ;
     RECT  105.304 1.968 105.365 1.992 ;
     RECT  105.304 3.408 105.437 5.208 ;
     RECT  105.304 21.504 105.437 21.528 ;
     RECT  105.397 1.104 105.491 1.752 ;
     RECT  105.437 3.408 105.689 3.432 ;
     RECT  105.437 5.04 106.477 5.208 ;
     RECT  106.693 25.056 106.949 25.08 ;
     RECT  105.304 23.904 107.165 23.928 ;
     RECT  107.305 22.8 107.389 22.824 ;
     RECT  107.557 25.776 107.669 25.8 ;
     RECT  107.809 24.528 107.987 24.552 ;
     RECT  105.491 1.728 108.025 1.752 ;
     RECT  108.025 1.104 108.371 1.752 ;
     RECT  108.325 24.48 108.425 24.504 ;
     RECT  106.477 3.744 108.601 5.208 ;
     RECT  108.668 23.376 109.169 23.4 ;
     RECT  108.371 1.728 109.537 1.752 ;
     RECT  109.169 23.376 109.573 23.928 ;
     RECT  109.573 23.376 109.685 24.504 ;
     RECT  108.601 3.408 110.185 5.208 ;
     RECT  110.185 3.312 110.293 5.208 ;
     RECT  109.537 1.728 110.408 2.28 ;
     RECT  110.293 3.312 110.408 5.496 ;
     RECT  109.685 23.376 110.408 23.928 ;
     RECT  110.365 25.104 110.483 25.128 ;
     RECT  110.408 1.728 110.512 23.928 ;
     RECT  110.512 1.728 110.704 23.502 ;
     RECT  110.821 24.48 110.909 25.08 ;
     RECT  110.704 2.88 111.305 5.496 ;
     RECT  111.305 3.984 111.341 5.496 ;
     RECT  110.909 25.056 111.737 25.08 ;
     RECT  111.341 3.984 111.773 5.208 ;
     RECT  112.069 23.904 112.169 23.928 ;
     RECT  111.305 2.88 112.268 2.904 ;
     RECT  111.773 3.984 112.268 5.16 ;
     RECT  112.309 23.952 112.499 23.976 ;
     RECT  110.704 21.648 112.601 21.72 ;
     RECT  112.268 2.88 112.733 5.16 ;
     RECT  110.704 1.728 112.816 1.752 ;
     RECT  112.733 2.832 112.817 5.16 ;
     RECT  112.669 21.12 112.835 21.144 ;
     RECT  112.817 3.312 112.837 5.16 ;
     RECT  112.777 22.224 112.837 22.296 ;
     RECT  112.837 22.224 112.925 22.776 ;
     RECT  112.925 22.224 113.033 22.296 ;
     RECT  112.816 1.728 113.245 1.8 ;
     RECT  113.033 22.224 113.321 22.248 ;
     RECT  112.837 3.312 113.365 5.208 ;
     RECT  113.353 23.376 113.437 23.4 ;
     RECT  113.413 0.528 113.501 0.552 ;
     RECT  113.245 1.728 113.941 2.28 ;
     RECT  113.365 3.312 113.941 5.64 ;
     RECT  113.941 1.728 113.969 5.64 ;
     RECT  113.969 1.728 114.041 3.432 ;
     RECT  113.969 4.416 114.149 5.64 ;
     RECT  114.073 25.776 114.157 25.8 ;
     RECT  114.361 22.8 114.433 22.824 ;
     RECT  113.701 23.904 114.433 23.928 ;
     RECT  114.433 22.8 114.812 23.928 ;
     RECT  114.812 22.8 114.899 23.976 ;
     RECT  114.041 3.312 115.093 3.432 ;
     RECT  114.149 4.416 115.093 5.496 ;
     RECT  114.041 1.728 115.808 1.752 ;
     RECT  115.093 3.312 115.808 5.496 ;
     RECT  114.899 22.8 115.808 23.928 ;
     RECT  115.808 1.728 116.104 23.928 ;
     RECT  116.104 23.424 116.273 23.928 ;
     RECT  116.104 21.648 116.489 21.672 ;
     RECT  115.717 25.776 116.669 25.8 ;
     RECT  116.3 0.048 116.771 0.072 ;
     RECT  116.965 24.48 117.101 24.504 ;
     RECT  116.104 1.728 117.205 4.92 ;
     RECT  116.273 23.424 117.205 23.448 ;
     RECT  117.205 23.376 117.433 23.448 ;
     RECT  117.205 1.728 117.461 5.16 ;
     RECT  117.277 21.936 117.533 21.96 ;
     RECT  117.461 3.312 117.683 5.16 ;
     RECT  117.433 23.424 117.683 23.448 ;
     RECT  117.701 25.056 117.785 25.08 ;
     RECT  117.461 1.728 117.925 1.752 ;
     RECT  117.925 1.104 118.259 1.752 ;
     RECT  117.683 3.84 118.361 5.16 ;
     RECT  118.213 21.648 118.613 21.672 ;
     RECT  118.565 22.752 118.649 22.776 ;
     RECT  118.361 3.84 118.837 4.92 ;
     RECT  118.259 1.728 118.861 1.752 ;
     RECT  118.861 1.728 118.979 2.28 ;
     RECT  118.825 23.376 118.981 23.4 ;
     RECT  118.981 23.376 119.117 23.928 ;
     RECT  118.837 3.264 119.605 4.92 ;
     RECT  119.365 22.128 119.845 22.152 ;
     RECT  119.117 23.376 120.157 23.4 ;
     RECT  119.605 3.264 120.517 5.16 ;
     RECT  119.845 22.128 120.613 22.248 ;
     RECT  120.517 3.264 120.805 5.784 ;
     RECT  120.157 23.376 120.997 23.976 ;
     RECT  120.997 23.376 121.169 24.504 ;
     RECT  118.979 1.728 121.208 1.752 ;
     RECT  120.805 2.832 121.208 5.784 ;
     RECT  120.613 22.032 121.208 22.248 ;
     RECT  121.169 23.376 121.208 23.928 ;
     RECT  121.208 1.728 121.504 23.928 ;
     RECT  121.504 22.032 121.781 22.056 ;
     RECT  121.477 25.056 121.853 25.08 ;
     RECT  121.504 1.728 121.955 5.784 ;
     RECT  121.955 4.032 122.285 5.784 ;
     RECT  121.955 1.728 122.357 2.856 ;
     RECT  122.285 4.032 122.501 5.688 ;
     RECT  122.501 4.032 122.573 5.16 ;
     RECT  121.504 23.376 122.677 23.928 ;
     RECT  122.677 22.848 122.821 23.928 ;
     RECT  122.821 22.8 122.969 23.928 ;
     RECT  122.573 4.032 123.001 4.92 ;
     RECT  123.001 3.408 123.085 4.92 ;
     RECT  122.969 23.376 123.109 23.928 ;
     RECT  123.109 23.376 123.581 24.504 ;
     RECT  123.085 4.224 123.761 4.92 ;
     RECT  123.581 23.376 124.409 23.928 ;
     RECT  124.621 21.936 124.741 21.96 ;
     RECT  124.741 21.936 124.841 22.152 ;
     RECT  125.125 25.056 125.345 25.08 ;
     RECT  124.837 3.36 125.381 3.384 ;
     RECT  124.841 21.936 125.417 21.96 ;
     RECT  124.409 23.376 125.509 23.4 ;
     RECT  125.509 23.376 125.597 23.976 ;
     RECT  123.761 4.416 126.169 4.92 ;
     RECT  126.169 4.128 126.565 4.92 ;
     RECT  125.597 23.376 126.601 23.4 ;
     RECT  125.989 24.48 126.601 24.504 ;
     RECT  122.357 1.728 126.608 1.752 ;
     RECT  126.565 3.312 126.608 4.92 ;
     RECT  126.601 23.376 126.608 24.504 ;
     RECT  126.608 1.728 126.757 24.504 ;
     RECT  126.757 1.728 126.904 24.552 ;
     RECT  126.904 23.376 127.001 24.552 ;
     RECT  127.001 23.376 127.289 23.928 ;
     RECT  126.904 22.128 127.649 22.152 ;
     RECT  126.904 1.728 127.667 2.28 ;
     RECT  127.525 25.776 127.667 25.8 ;
     RECT  126.904 4.128 128.012 5.112 ;
     RECT  126.904 21.072 128.081 21.096 ;
     RECT  128.012 3.312 128.099 5.112 ;
     RECT  127.289 23.376 128.099 23.592 ;
     RECT  128.099 4.224 128.297 5.112 ;
     RECT  128.197 21.12 128.513 21.144 ;
     RECT  128.753 22.128 128.837 22.152 ;
     RECT  128.297 4.896 129.349 5.112 ;
     RECT  128.099 23.376 129.373 23.544 ;
     RECT  129.349 4.128 129.409 5.112 ;
     RECT  129.373 22.8 129.521 23.544 ;
     RECT  129.521 23.376 129.637 23.544 ;
     RECT  129.637 23.376 129.737 23.928 ;
     RECT  129.409 4.128 130.129 5.208 ;
     RECT  127.667 1.728 130.456 1.752 ;
     RECT  130.129 3.648 130.529 5.208 ;
     RECT  130.021 25.056 130.529 25.08 ;
     RECT  130.456 1.728 130.547 1.8 ;
     RECT  130.529 3.648 131.276 5.112 ;
     RECT  129.737 23.376 131.461 23.448 ;
     RECT  130.547 1.728 131.537 1.752 ;
     RECT  131.461 23.376 131.609 23.928 ;
     RECT  131.276 3.312 132.008 5.112 ;
     RECT  130.885 22.224 132.008 22.248 ;
     RECT  131.609 23.376 132.008 23.772 ;
     RECT  131.929 0.096 132.275 0.12 ;
     RECT  132.008 2.148 132.304 23.772 ;
     RECT  132.304 3.888 132.401 4.248 ;
     RECT  132.229 25.776 132.473 25.8 ;
     RECT  132.401 3.936 132.803 4.248 ;
     RECT  132.803 3.936 133.837 4.152 ;
     RECT  132.997 23.904 133.949 23.928 ;
     RECT  134.437 23.712 134.633 23.736 ;
     RECT  135.164 25.104 135.251 25.128 ;
     RECT  133.837 3.36 135.253 4.152 ;
     RECT  135.253 2.832 135.299 4.152 ;
     RECT  135.299 2.832 135.34 3.048 ;
     RECT  135.299 4.128 135.749 4.152 ;
     RECT  135.953 23.904 136.793 23.928 ;
     RECT  132.997 1.728 137.408 1.752 ;
     RECT  135.34 3.024 137.408 3.048 ;
     RECT  137.408 1.728 137.704 23.772 ;
     RECT  137.413 25.776 137.765 25.8 ;
     RECT  137.704 4.224 138.629 4.248 ;
     RECT  138.181 23.904 139.097 23.928 ;
     RECT  139.561 23.376 139.667 23.4 ;
     RECT  137.704 1.728 140.501 1.752 ;
     RECT  140.389 23.904 140.717 24.552 ;
     RECT  140.893 2.256 141.203 2.28 ;
     RECT  141.893 1.152 141.977 1.176 ;
     RECT  140.717 24.528 142.739 24.552 ;
     RECT  142.693 2.88 142.777 2.904 ;
    LAYER M5 ;
     RECT  1.128 0.016 1.2 0.084 ;
     RECT  1.224 0.016 1.296 0.084 ;
     RECT  1.32 0.016 1.392 0.084 ;
     RECT  1.416 0.016 1.488 0.084 ;
     RECT  1.512 0.016 1.584 0.084 ;
     RECT  1.608 0.016 1.68 0.084 ;
     RECT  1.704 0.016 1.776 0.084 ;
     RECT  1.8 0.016 1.872 0.084 ;
     RECT  1.896 0.016 2.064 0.084 ;
     RECT  2.088 0.016 2.352 0.084 ;
     RECT  2.376 0.016 2.544 0.084 ;
     RECT  2.568 0.016 2.736 0.084 ;
     RECT  2.76 0.016 2.928 0.084 ;
     RECT  2.952 0.016 3.12 0.084 ;
     RECT  3.144 0.016 3.312 0.084 ;
     RECT  3.336 0.016 3.504 0.084 ;
     RECT  3.528 0.016 3.792 0.084 ;
     RECT  3.816 0.016 3.984 0.084 ;
     RECT  4.008 0.016 4.176 0.084 ;
     RECT  4.2 0.016 4.368 0.084 ;
     RECT  4.392 0.016 4.56 0.084 ;
     RECT  4.584 0.016 4.752 0.084 ;
     RECT  4.776 0.016 4.944 0.084 ;
     RECT  4.968 0.016 5.136 0.084 ;
     RECT  5.16 0.016 5.424 0.084 ;
     RECT  5.448 0.016 5.616 0.084 ;
     RECT  5.64 0.016 5.808 0.084 ;
     RECT  5.832 0.016 6 0.084 ;
     RECT  6.024 0.016 6.192 0.084 ;
     RECT  6.216 0.016 6.384 0.084 ;
     RECT  6.408 0.016 6.576 0.084 ;
     RECT  6.6 0.016 6.864 0.084 ;
     RECT  6.888 0.016 7.056 0.084 ;
     RECT  7.08 0.016 7.248 0.084 ;
     RECT  7.272 0.016 7.44 0.084 ;
     RECT  7.464 0.016 7.632 0.084 ;
     RECT  7.656 0.016 7.824 0.084 ;
     RECT  7.848 0.016 8.016 0.084 ;
     RECT  8.04 0.016 8.208 0.084 ;
     RECT  8.232 0.016 8.496 0.084 ;
     RECT  8.52 0.016 8.688 0.084 ;
     RECT  8.712 0.016 8.88 0.084 ;
     RECT  8.904 0.016 9.072 0.084 ;
     RECT  9.096 0.016 9.264 0.084 ;
     RECT  9.288 0.016 9.456 0.084 ;
     RECT  9.48 0.016 9.648 0.084 ;
     RECT  9.672 0.016 9.936 0.084 ;
     RECT  9.96 0.016 10.128 0.084 ;
     RECT  10.152 0.016 10.32 0.084 ;
     RECT  10.344 0.016 10.512 0.084 ;
     RECT  10.536 0.016 10.704 0.084 ;
     RECT  10.728 0.016 10.896 0.084 ;
     RECT  10.92 0.016 11.088 0.084 ;
     RECT  11.112 0.016 11.28 0.084 ;
     RECT  11.304 0.016 11.568 0.084 ;
     RECT  11.592 0.016 11.76 0.084 ;
     RECT  11.784 0.016 11.952 0.084 ;
     RECT  11.976 0.016 12.144 0.084 ;
     RECT  12.168 0.016 12.336 0.084 ;
     RECT  12.36 0.016 12.528 0.084 ;
     RECT  12.552 0.016 12.72 0.084 ;
     RECT  12.744 0.016 13.008 0.084 ;
     RECT  13.032 0.016 13.392 0.084 ;
     RECT  13.416 0.016 13.872 0.084 ;
     RECT  13.896 0.016 14.256 0.084 ;
     RECT  14.28 0.016 14.64 0.084 ;
     RECT  14.664 0.016 15.024 0.084 ;
     RECT  15.048 0.016 15.504 0.084 ;
     RECT  15.528 0.016 15.888 0.084 ;
     RECT  15.912 0.016 16.272 0.084 ;
     RECT  16.296 0.016 16.656 0.084 ;
     RECT  16.68 0.016 17.136 0.084 ;
     RECT  17.16 0.016 17.52 0.084 ;
     RECT  17.544 0.016 17.904 0.084 ;
     RECT  17.928 0.016 18.384 0.084 ;
     RECT  18.408 0.016 18.768 0.084 ;
     RECT  18.792 0.016 19.152 0.084 ;
     RECT  19.176 0.016 19.536 0.084 ;
     RECT  19.56 0.016 20.016 0.084 ;
     RECT  20.04 0.016 20.688 0.084 ;
     RECT  20.712 0.016 21.552 0.084 ;
     RECT  21.576 0.016 22.416 0.084 ;
     RECT  22.44 0.016 23.184 0.084 ;
     RECT  23.208 0.016 24.048 0.084 ;
     RECT  24.072 0.016 24.816 0.084 ;
     RECT  24.84 0.016 25.68 0.084 ;
     RECT  25.704 0.016 26.448 0.084 ;
     RECT  26.472 0.016 27.312 0.084 ;
     RECT  27.336 0.016 28.08 0.084 ;
     RECT  28.104 0.016 28.944 0.084 ;
     RECT  28.968 0.016 29.712 0.084 ;
     RECT  29.736 0.016 30.576 0.084 ;
     RECT  30.6 0.016 31.344 0.084 ;
     RECT  31.368 0.016 32.208 0.084 ;
     RECT  32.232 0.016 32.976 0.084 ;
     RECT  33 0.016 33.84 0.084 ;
     RECT  33.864 0.016 34.608 0.084 ;
     RECT  34.632 0.016 35.472 0.084 ;
     RECT  35.496 0.016 36.336 0.084 ;
     RECT  36.36 0.016 37.104 0.084 ;
     RECT  37.128 0.016 37.968 0.084 ;
     RECT  37.992 0.016 38.736 0.084 ;
     RECT  38.76 0.016 39.6 0.084 ;
     RECT  39.624 0.016 40.368 0.084 ;
     RECT  40.392 0.016 41.232 0.084 ;
     RECT  41.256 0.016 42 0.084 ;
     RECT  42.024 0.016 42.864 0.084 ;
     RECT  42.888 0.016 43.632 0.084 ;
     RECT  43.656 0.016 44.496 0.084 ;
     RECT  44.52 0.016 45.264 0.084 ;
     RECT  45.288 0.016 46.128 0.084 ;
     RECT  46.152 0.016 46.896 0.084 ;
     RECT  46.92 0.016 47.76 0.084 ;
     RECT  47.784 0.016 48.528 0.084 ;
     RECT  48.552 0.016 49.392 0.084 ;
     RECT  49.416 0.016 50.256 0.084 ;
     RECT  50.28 0.016 51.024 0.084 ;
     RECT  51.048 0.016 51.888 0.084 ;
     RECT  51.912 0.016 52.656 0.084 ;
     RECT  52.68 0.016 53.52 0.084 ;
     RECT  53.544 0.016 54.288 0.084 ;
     RECT  54.312 0.016 55.152 0.084 ;
     RECT  55.176 0.016 55.92 0.084 ;
     RECT  55.944 0.016 56.784 0.084 ;
     RECT  56.808 0.016 57.552 0.084 ;
     RECT  57.576 0.016 58.416 0.084 ;
     RECT  58.44 0.016 59.184 0.084 ;
     RECT  59.208 0.016 60.048 0.084 ;
     RECT  60.072 0.016 60.432 0.084 ;
     RECT  60.456 0.016 60.816 0.084 ;
     RECT  60.84 0.016 61.296 0.084 ;
     RECT  61.32 0.016 61.68 0.084 ;
     RECT  61.704 0.016 62.064 0.084 ;
     RECT  62.088 0.016 62.448 0.084 ;
     RECT  62.472 0.016 62.928 0.084 ;
     RECT  62.952 0.016 63.312 0.084 ;
     RECT  63.336 0.016 63.696 0.084 ;
     RECT  63.72 0.016 64.176 0.084 ;
     RECT  64.2 0.016 64.56 0.084 ;
     RECT  64.584 0.016 64.944 0.084 ;
     RECT  64.968 0.016 65.328 0.084 ;
     RECT  65.352 0.016 65.808 0.084 ;
     RECT  65.832 0.016 66.192 0.084 ;
     RECT  66.216 0.016 66.576 0.084 ;
     RECT  66.6 0.016 66.96 0.084 ;
     RECT  66.984 0.016 67.44 0.084 ;
     RECT  67.464 0.016 67.824 0.084 ;
     RECT  67.848 0.016 68.208 0.084 ;
     RECT  68.232 0.016 68.592 0.084 ;
     RECT  68.616 0.016 69.072 0.084 ;
     RECT  69.096 0.016 69.456 0.084 ;
     RECT  69.48 0.016 69.84 0.084 ;
     RECT  69.864 0.016 70.32 0.084 ;
     RECT  70.344 0.016 70.704 0.084 ;
     RECT  70.728 0.016 71.088 0.084 ;
     RECT  71.112 0.016 71.472 0.084 ;
     RECT  71.496 0.016 71.952 0.084 ;
     RECT  71.976 0.016 72.336 0.084 ;
     RECT  72.36 0.016 72.72 0.084 ;
     RECT  72.744 0.016 73.104 0.084 ;
     RECT  73.128 0.016 73.584 0.084 ;
     RECT  73.608 0.016 73.968 0.084 ;
     RECT  73.992 0.016 74.352 0.084 ;
     RECT  74.376 0.016 74.736 0.084 ;
     RECT  74.76 0.016 75.216 0.084 ;
     RECT  75.24 0.016 75.6 0.084 ;
     RECT  75.624 0.016 75.984 0.084 ;
     RECT  76.008 0.016 76.464 0.084 ;
     RECT  76.488 0.016 76.848 0.084 ;
     RECT  76.872 0.016 77.232 0.084 ;
     RECT  77.256 0.016 77.616 0.084 ;
     RECT  77.64 0.016 78.096 0.084 ;
     RECT  78.12 0.016 78.48 0.084 ;
     RECT  78.504 0.016 78.864 0.084 ;
     RECT  78.888 0.016 79.248 0.084 ;
     RECT  79.272 0.016 79.728 0.084 ;
     RECT  79.752 0.016 80.112 0.084 ;
     RECT  80.136 0.016 80.496 0.084 ;
     RECT  80.52 0.016 80.88 0.084 ;
     RECT  80.904 0.016 81.36 0.084 ;
     RECT  81.384 0.016 81.744 0.084 ;
     RECT  81.768 0.016 82.128 0.084 ;
     RECT  82.152 0.016 82.512 0.084 ;
     RECT  82.536 0.016 82.992 0.084 ;
     RECT  83.016 0.016 83.376 0.084 ;
     RECT  83.4 0.016 83.76 0.084 ;
     RECT  83.784 0.016 84.24 0.084 ;
     RECT  84.264 0.016 84.624 0.084 ;
     RECT  84.648 0.016 85.008 0.084 ;
     RECT  85.032 0.016 85.392 0.084 ;
     RECT  85.416 0.016 85.872 0.084 ;
     RECT  85.896 0.016 86.256 0.084 ;
     RECT  86.28 0.016 86.64 0.084 ;
     RECT  86.664 0.016 87.024 0.084 ;
     RECT  87.048 0.016 87.504 0.084 ;
     RECT  87.528 0.016 87.888 0.084 ;
     RECT  87.912 0.016 88.272 0.084 ;
     RECT  88.296 0.016 88.656 0.084 ;
     RECT  88.68 0.016 89.136 0.084 ;
     RECT  89.16 0.016 89.52 0.084 ;
     RECT  89.544 0.016 89.904 0.084 ;
     RECT  89.928 0.016 90.384 0.084 ;
     RECT  90.408 0.016 90.768 0.084 ;
     RECT  90.792 0.016 91.152 0.084 ;
     RECT  91.176 0.016 91.536 0.084 ;
     RECT  91.56 0.016 92.016 0.084 ;
     RECT  92.04 0.016 92.4 0.084 ;
     RECT  92.424 0.016 92.784 0.084 ;
     RECT  92.808 0.016 93.168 0.084 ;
     RECT  93.192 0.016 93.648 0.084 ;
     RECT  93.672 0.016 94.032 0.084 ;
     RECT  94.056 0.016 94.416 0.084 ;
     RECT  94.44 0.016 94.8 0.084 ;
     RECT  94.824 0.016 95.28 0.084 ;
     RECT  95.304 0.016 95.664 0.084 ;
     RECT  95.688 0.016 96.048 0.084 ;
     RECT  96.072 0.016 96.528 0.084 ;
     RECT  96.552 0.016 96.912 0.084 ;
     RECT  96.936 0.016 97.296 0.084 ;
     RECT  97.32 0.016 97.68 0.084 ;
     RECT  97.704 0.016 98.16 0.084 ;
     RECT  98.184 0.016 98.544 0.084 ;
     RECT  98.568 0.016 98.928 0.084 ;
     RECT  98.952 0.016 99.312 0.084 ;
     RECT  99.336 0.016 99.792 0.084 ;
     RECT  99.816 0.016 100.176 0.084 ;
     RECT  100.2 0.016 100.56 0.084 ;
     RECT  100.584 0.016 100.944 0.084 ;
     RECT  100.968 0.016 101.424 0.084 ;
     RECT  101.448 0.016 101.808 0.084 ;
     RECT  101.832 0.016 102.192 0.084 ;
     RECT  102.216 0.016 102.576 0.084 ;
     RECT  102.6 0.016 103.056 0.084 ;
     RECT  103.08 0.016 103.44 0.084 ;
     RECT  103.464 0.016 103.824 0.084 ;
     RECT  103.848 0.016 104.304 0.084 ;
     RECT  104.328 0.016 104.688 0.084 ;
     RECT  104.712 0.016 105.072 0.084 ;
     RECT  105.096 0.016 105.456 0.084 ;
     RECT  105.48 0.016 105.936 0.084 ;
     RECT  105.96 0.016 106.32 0.084 ;
     RECT  106.344 0.016 106.704 0.084 ;
     RECT  106.728 0.016 107.088 0.084 ;
     RECT  107.112 0.016 107.568 0.084 ;
     RECT  107.592 0.016 107.952 0.084 ;
     RECT  107.976 0.016 108.336 0.084 ;
     RECT  108.36 0.016 108.72 0.084 ;
     RECT  108.744 0.016 109.2 0.084 ;
     RECT  109.224 0.016 109.584 0.084 ;
     RECT  109.608 0.016 109.968 0.084 ;
     RECT  109.992 0.016 110.448 0.084 ;
     RECT  110.472 0.016 110.832 0.084 ;
     RECT  110.856 0.016 111.216 0.084 ;
     RECT  111.24 0.016 111.6 0.084 ;
     RECT  111.624 0.016 112.08 0.084 ;
     RECT  112.104 0.016 112.464 0.084 ;
     RECT  112.488 0.016 112.848 0.084 ;
     RECT  112.872 0.016 113.232 0.084 ;
     RECT  113.256 0.016 113.712 0.084 ;
     RECT  113.736 0.016 114.096 0.084 ;
     RECT  114.12 0.016 114.48 0.084 ;
     RECT  114.504 0.016 114.864 0.084 ;
     RECT  114.888 0.016 115.344 0.084 ;
     RECT  115.368 0.016 115.728 0.084 ;
     RECT  115.752 0.016 116.112 0.084 ;
     RECT  116.136 0.016 116.592 0.084 ;
     RECT  116.616 0.016 116.976 0.084 ;
     RECT  117 0.016 117.36 0.084 ;
     RECT  117.384 0.016 117.744 0.084 ;
     RECT  117.768 0.016 118.224 0.084 ;
     RECT  118.248 0.016 118.608 0.084 ;
     RECT  118.632 0.016 118.992 0.084 ;
     RECT  119.016 0.016 119.376 0.084 ;
     RECT  119.4 0.016 119.856 0.084 ;
     RECT  119.88 0.016 120.24 0.084 ;
     RECT  120.264 0.016 120.624 0.084 ;
     RECT  120.648 0.016 121.008 0.084 ;
     RECT  121.032 0.016 121.488 0.084 ;
     RECT  121.512 0.016 121.872 0.084 ;
     RECT  121.896 0.016 122.256 0.084 ;
     RECT  122.28 0.016 122.64 0.084 ;
     RECT  122.664 0.016 123.12 0.084 ;
     RECT  123.144 0.016 123.504 0.084 ;
     RECT  123.528 0.016 123.888 0.084 ;
     RECT  123.912 0.016 124.368 0.084 ;
     RECT  124.392 0.016 124.752 0.084 ;
     RECT  124.776 0.016 125.136 0.084 ;
     RECT  125.16 0.016 125.52 0.084 ;
     RECT  125.544 0.016 126 0.084 ;
     RECT  126.024 0.016 126.384 0.084 ;
     RECT  126.408 0.016 126.768 0.084 ;
     RECT  126.792 0.016 127.152 0.084 ;
     RECT  127.176 0.016 127.632 0.084 ;
     RECT  127.656 0.016 128.016 0.084 ;
     RECT  128.04 0.016 128.4 0.084 ;
     RECT  128.424 0.016 128.784 0.084 ;
     RECT  128.808 0.016 129.264 0.084 ;
     RECT  129.288 0.016 129.648 0.084 ;
     RECT  129.672 0.016 130.032 0.084 ;
     RECT  130.056 0.016 130.512 0.084 ;
     RECT  130.536 0.016 130.896 0.084 ;
     RECT  130.92 0.016 131.472 0.084 ;
     RECT  131.496 0.016 132.24 0.084 ;
     RECT  132.264 0.016 133.008 0.084 ;
     RECT  133.032 0.016 133.68 0.084 ;
     RECT  133.704 0.016 134.448 0.084 ;
     RECT  134.472 0.016 135.216 0.084 ;
     RECT  135.24 0.016 135.984 0.084 ;
     RECT  136.008 0.016 136.656 0.084 ;
     RECT  136.68 0.016 137.424 0.084 ;
     RECT  137.448 0.016 138.192 0.084 ;
     RECT  138.216 0.016 138.96 0.084 ;
     RECT  138.984 0.016 139.632 0.084 ;
     RECT  139.656 0.016 140.4 0.084 ;
     RECT  140.424 0.016 141.168 0.084 ;
     RECT  141.192 0.016 141.936 0.084 ;
     RECT  141.96 0.016 142.704 0.084 ;
     RECT  1.104 0.084 142.728 0.131 ;
     RECT  1.104 0.131 51.048 0.611 ;
     RECT  1.104 0.611 36.36 1.187 ;
     RECT  133.008 0.131 142.728 1.187 ;
     RECT  1.104 1.187 14.664 1.763 ;
     RECT  15.888 1.187 36.36 1.763 ;
     RECT  37.968 0.611 40.392 1.763 ;
     RECT  42 0.611 43.656 1.763 ;
     RECT  45.264 0.611 46.152 1.763 ;
     RECT  47.76 0.611 51.048 1.763 ;
     RECT  52.656 0.131 131.496 1.763 ;
     RECT  133.008 1.187 141.192 1.763 ;
     RECT  66.576 1.763 67.848 1.811 ;
     RECT  77.136 1.763 79.752 1.811 ;
     RECT  80.88 1.763 81.384 1.811 ;
     RECT  82.512 1.763 83.712 1.811 ;
     RECT  101.424 1.763 101.448 1.811 ;
     RECT  112.848 1.763 114.504 1.811 ;
     RECT  130.512 1.763 130.536 1.811 ;
     RECT  71.088 1.763 72.912 1.859 ;
     RECT  85.392 1.763 85.416 1.859 ;
     RECT  98.544 1.763 98.568 1.859 ;
     RECT  79.728 1.811 79.752 1.907 ;
     RECT  51 1.763 51.048 2.137 ;
     RECT  40.2 1.763 40.392 2.151 ;
     RECT  51 2.137 51.12 2.151 ;
     RECT  63.696 1.763 63.72 2.291 ;
     RECT  66.576 1.811 67.512 2.291 ;
     RECT  69.456 1.763 69.48 2.291 ;
     RECT  94.032 1.763 94.512 2.291 ;
     RECT  109.968 1.763 111.624 2.291 ;
     RECT  126.6 1.763 127.656 2.291 ;
     RECT  141.168 1.763 141.192 2.291 ;
     RECT  1.104 1.763 14.28 2.339 ;
     RECT  16.896 1.763 16.92 2.339 ;
     RECT  1.2 2.339 14.28 2.387 ;
     RECT  45.6 1.763 45.912 2.773 ;
     RECT  15.888 1.763 15.912 2.821 ;
     RECT  18.6 1.763 19.56 2.821 ;
     RECT  40.2 2.151 40.512 2.821 ;
     RECT  44.736 2.773 45.912 2.821 ;
     RECT  71.712 1.859 72.912 2.821 ;
     RECT  74.352 1.763 74.376 2.821 ;
     RECT  77.136 1.811 78.696 2.821 ;
     RECT  80.928 1.811 81.384 2.821 ;
     RECT  88.8 1.763 89.928 2.821 ;
     RECT  94.08 2.291 94.512 2.821 ;
     RECT  113.28 1.811 114.504 2.821 ;
     RECT  121.2 1.763 121.896 2.821 ;
     RECT  1.392 2.387 14.28 2.867 ;
     RECT  104.688 1.763 105.312 2.915 ;
     RECT  110.304 2.291 111.624 2.915 ;
     RECT  142.704 1.187 142.728 2.915 ;
     RECT  15.888 2.821 15.96 2.917 ;
     RECT  80.928 2.821 81.48 3.205 ;
     RECT  86.352 2.821 86.376 3.205 ;
     RECT  118.944 1.763 118.968 3.253 ;
     RECT  17.088 3.205 17.112 3.301 ;
     RECT  18.144 2.821 19.56 3.301 ;
     RECT  71.712 2.821 74.376 3.301 ;
     RECT  77.136 2.821 78.744 3.301 ;
     RECT  80.688 3.205 81.48 3.301 ;
     RECT  83.136 1.811 83.712 3.301 ;
     RECT  86.016 3.205 86.376 3.301 ;
     RECT  91.152 1.763 92.088 3.301 ;
     RECT  99.6 1.763 99.912 3.301 ;
     RECT  115.8 1.763 117.288 3.301 ;
     RECT  132 2.137 132.312 3.301 ;
     RECT  71.04 3.301 74.376 3.349 ;
     RECT  86.016 3.301 86.808 3.349 ;
     RECT  88.416 2.821 89.928 3.349 ;
     RECT  135.264 2.821 135.288 3.395 ;
     RECT  70.944 3.349 74.376 3.397 ;
     RECT  86.016 3.349 89.928 3.397 ;
     RECT  91.152 3.301 92.376 3.397 ;
     RECT  120.816 2.821 122.28 3.397 ;
     RECT  1.392 2.867 13.512 3.443 ;
     RECT  17.088 3.301 19.56 3.443 ;
     RECT  112.752 2.821 114.504 3.443 ;
     RECT  67.2 2.291 67.512 3.445 ;
     RECT  4.368 3.443 4.392 3.491 ;
     RECT  7.392 3.443 11.784 3.539 ;
     RECT  44.544 2.821 45.912 3.589 ;
     RECT  47.712 2.821 47.736 3.635 ;
     RECT  15.84 2.917 15.96 3.733 ;
     RECT  61.8 1.763 62.112 3.733 ;
     RECT  70.944 3.397 74.664 3.733 ;
     RECT  103.968 3.301 103.992 3.733 ;
     RECT  112.752 3.443 113.976 3.733 ;
     RECT  115.8 3.301 117.672 3.733 ;
     RECT  13.2 3.443 13.512 3.829 ;
     RECT  14.688 3.733 14.712 3.829 ;
     RECT  17.088 3.443 19.224 3.829 ;
     RECT  110.304 2.915 110.712 3.829 ;
     RECT  120.816 3.397 123.048 3.829 ;
     RECT  15.744 3.733 15.96 3.877 ;
     RECT  17.04 3.829 19.224 3.877 ;
     RECT  86.016 3.397 92.376 3.877 ;
     RECT  94.08 2.821 95.736 3.877 ;
     RECT  96.912 3.301 96.936 3.877 ;
     RECT  106.608 3.733 106.632 3.877 ;
     RECT  7.392 3.539 9.624 3.923 ;
     RECT  131.328 3.301 132.312 3.925 ;
     RECT  44.544 3.589 46.152 3.971 ;
     RECT  103.104 3.733 103.992 3.973 ;
     RECT  105 2.915 105.312 3.973 ;
     RECT  75.792 1.763 75.816 4.019 ;
     RECT  83.136 3.301 84.696 4.019 ;
     RECT  120.144 3.829 123.048 4.019 ;
     RECT  7.488 3.923 9.624 4.067 ;
     RECT  10.656 3.539 11.784 4.067 ;
     RECT  131.328 3.925 132.792 4.259 ;
     RECT  77.136 3.301 81.48 4.261 ;
     RECT  44.736 3.971 46.152 4.355 ;
     RECT  13.2 3.829 14.712 4.501 ;
     RECT  15.744 3.877 19.224 4.501 ;
     RECT  67.2 3.445 67.8 4.501 ;
     RECT  68.976 3.925 69 4.501 ;
     RECT  70.416 3.733 74.664 4.501 ;
     RECT  98.496 3.733 98.52 4.501 ;
     RECT  99.6 3.301 100.152 4.501 ;
     RECT  112.32 3.733 113.976 4.501 ;
     RECT  115.104 3.733 117.672 4.501 ;
     RECT  126.6 2.291 126.912 4.501 ;
     RECT  7.488 4.067 9.048 4.547 ;
     RECT  67.2 4.501 69 4.547 ;
     RECT  20.544 3.301 20.568 4.595 ;
     RECT  106.608 3.877 107.352 4.595 ;
     RECT  77.136 4.261 82.056 4.643 ;
     RECT  112.32 4.501 117.672 4.643 ;
     RECT  118.848 3.253 118.968 4.691 ;
     RECT  70.032 4.501 74.664 4.739 ;
     RECT  114.816 4.643 117.672 4.739 ;
     RECT  13.2 4.501 19.224 4.837 ;
     RECT  68.544 4.547 69 4.837 ;
     RECT  70.032 4.739 74.616 4.837 ;
     RECT  53.568 4.453 53.592 4.931 ;
     RECT  129.36 4.117 129.384 4.931 ;
     RECT  83.4 4.019 84.696 5.029 ;
     RECT  1.392 3.443 2.952 5.077 ;
     RECT  64.992 3.205 65.016 5.077 ;
     RECT  78 4.643 82.056 5.077 ;
     RECT  83.4 5.029 84.984 5.077 ;
     RECT  86.016 3.877 96.936 5.077 ;
     RECT  118.896 4.691 118.968 5.125 ;
     RECT  120.144 4.019 120.168 5.125 ;
     RECT  1.392 5.077 3.336 5.171 ;
     RECT  76.8 4.645 76.824 5.171 ;
     RECT  78 5.077 96.936 5.171 ;
     RECT  112.32 4.643 113.352 5.171 ;
     RECT  13.2 4.837 19.32 5.315 ;
     RECT  7.488 4.547 8.328 5.461 ;
     RECT  27.36 4.117 27.384 5.507 ;
     RECT  112.8 5.171 113.352 5.605 ;
     RECT  1.632 5.171 3.336 5.653 ;
     RECT  10.656 4.067 10.68 5.699 ;
     RECT  118.896 5.125 120.168 5.749 ;
     RECT  121.2 4.019 123.048 5.749 ;
     RECT  7.104 5.461 8.328 6.851 ;
     RECT  41.76 4.117 41.784 10.019 ;
     RECT  0.528 11.221 0.552 14.149 ;
     RECT  1.632 5.653 3.864 14.149 ;
     RECT  7.104 6.851 8.112 14.197 ;
     RECT  13.2 5.315 16.776 14.197 ;
     RECT  12.96 14.197 16.776 14.533 ;
     RECT  6.336 14.197 8.112 14.723 ;
     RECT  12.672 14.533 16.776 14.773 ;
     RECT  0.528 14.149 3.864 15.205 ;
     RECT  10.656 14.197 10.68 15.349 ;
     RECT  10.656 15.349 11.256 15.637 ;
     RECT  12.336 14.773 16.776 15.925 ;
     RECT  6.672 14.723 8.112 16.165 ;
     RECT  10.56 15.637 11.256 16.165 ;
     RECT  12.288 15.925 16.776 16.165 ;
     RECT  0.48 15.205 3.864 16.501 ;
     RECT  10.56 16.165 16.776 16.501 ;
     RECT  6.672 16.165 8.76 17.075 ;
     RECT  6.672 17.075 6.696 17.077 ;
     RECT  5.952 17.077 6.696 18.037 ;
     RECT  7.68 17.075 8.76 18.037 ;
     RECT  0.432 16.501 3.864 18.181 ;
     RECT  4.896 14.005 4.92 18.181 ;
     RECT  5.952 18.037 8.76 18.181 ;
     RECT  10.368 16.501 16.776 18.805 ;
     RECT  0.432 18.181 8.76 18.901 ;
     RECT  10.32 18.805 16.776 18.901 ;
     RECT  125.808 4.501 126.912 21.061 ;
     RECT  128.064 3.301 128.088 21.061 ;
     RECT  125.808 21.061 128.088 21.109 ;
     RECT  0.432 18.901 16.776 21.155 ;
     RECT  17.808 5.315 19.32 21.155 ;
     RECT  88.8 5.171 96.936 21.155 ;
     RECT  112.8 5.605 113.4 21.155 ;
     RECT  101.616 4.261 101.64 21.541 ;
     RECT  61.8 3.733 62.424 21.637 ;
     RECT  67.2 4.547 67.512 21.637 ;
     RECT  68.544 4.837 74.616 21.637 ;
     RECT  101.424 21.541 101.64 21.637 ;
     RECT  103.104 3.973 105.312 21.637 ;
     RECT  109.488 3.829 110.712 21.637 ;
     RECT  114.816 4.739 116.112 21.637 ;
     RECT  117.216 4.739 117.672 21.637 ;
     RECT  118.896 5.749 123.048 21.637 ;
     RECT  66.96 21.637 67.512 21.973 ;
     RECT  61.68 21.637 62.424 22.117 ;
     RECT  125.808 21.109 128.232 22.117 ;
     RECT  0.432 21.155 16.584 22.165 ;
     RECT  17.808 21.155 19.272 22.165 ;
     RECT  66.672 21.973 67.512 22.165 ;
     RECT  68.544 21.637 75.24 22.165 ;
     RECT  0.432 22.165 19.272 22.213 ;
     RECT  113.376 21.155 113.4 22.213 ;
     RECT  131.328 4.259 132.312 22.213 ;
     RECT  0.336 22.213 19.272 22.499 ;
     RECT  0.48 22.499 19.272 22.547 ;
     RECT  34.8 1.763 35.112 22.741 ;
     RECT  97.968 4.501 100.152 22.741 ;
     RECT  113.232 22.213 113.4 22.741 ;
     RECT  64.08 5.077 65.016 22.789 ;
     RECT  0.912 22.547 19.272 22.835 ;
     RECT  66.672 22.165 75.24 22.835 ;
     RECT  78 5.171 85.848 22.835 ;
     RECT  95.616 21.155 96.936 22.835 ;
     RECT  107.328 4.595 107.352 22.835 ;
     RECT  97.968 22.741 100.2 22.883 ;
     RECT  34.8 22.741 35.496 23.365 ;
     RECT  56.4 1.763 56.712 23.365 ;
     RECT  66.672 22.835 70.056 23.365 ;
     RECT  109.488 21.637 111.624 23.365 ;
     RECT  125.808 22.117 128.808 23.365 ;
     RECT  0.912 22.835 19.224 23.411 ;
     RECT  44.736 4.355 45.912 23.411 ;
     RECT  66.576 23.365 70.056 23.411 ;
     RECT  71.232 22.835 73.128 23.411 ;
     RECT  87.456 5.171 87.48 23.411 ;
     RECT  117.216 21.637 123.048 23.411 ;
     RECT  130.896 22.213 132.312 23.413 ;
     RECT  66.576 23.411 68.568 23.459 ;
     RECT  69.84 23.411 70.056 23.459 ;
     RECT  88.8 21.155 94.512 23.459 ;
     RECT  79.536 22.835 85.848 23.461 ;
     RECT  24 1.763 24.312 23.769 ;
     RECT  29.4 1.763 29.712 23.769 ;
     RECT  39.744 2.821 40.512 23.769 ;
     RECT  51 2.151 51.312 23.769 ;
     RECT  79.536 23.461 85.896 23.769 ;
     RECT  88.8 23.459 91.56 23.769 ;
     RECT  24 23.769 24.12 23.783 ;
     RECT  29.4 23.769 29.52 23.783 ;
     RECT  51 23.769 51.12 23.783 ;
     RECT  56.4 23.365 57.576 23.783 ;
     RECT  79.536 23.769 83.52 23.783 ;
     RECT  88.8 23.769 88.92 23.783 ;
     RECT  130.512 23.413 132.312 23.783 ;
     RECT  137.4 1.763 137.712 23.783 ;
     RECT  61.68 22.117 62.952 23.845 ;
     RECT  64.08 22.789 64.968 23.845 ;
     RECT  17.52 23.411 19.224 23.893 ;
     RECT  20.688 22.741 20.712 23.893 ;
     RECT  34.608 23.365 35.496 23.893 ;
     RECT  38.736 23.365 38.76 23.893 ;
     RECT  39.744 23.769 40.392 23.893 ;
     RECT  45.264 23.411 45.912 23.893 ;
     RECT  56.784 23.783 57.576 23.893 ;
     RECT  61.68 23.845 64.968 23.893 ;
     RECT  71.952 23.411 73.128 23.893 ;
     RECT  74.304 22.835 75.24 23.893 ;
     RECT  78 22.835 78.504 23.893 ;
     RECT  79.536 23.783 83.304 23.893 ;
     RECT  84.624 23.769 85.896 23.893 ;
     RECT  95.664 22.835 96.504 23.893 ;
     RECT  98.928 22.883 100.2 23.893 ;
     RECT  101.424 21.637 105.312 23.893 ;
     RECT  108.72 23.365 111.624 23.893 ;
     RECT  112.848 22.741 113.4 23.893 ;
     RECT  114.816 21.637 116.232 23.893 ;
     RECT  117.36 23.411 123.048 23.893 ;
     RECT  124.752 22.117 124.776 23.893 ;
     RECT  125.808 23.365 129.288 23.893 ;
     RECT  130.512 23.783 131.496 23.893 ;
     RECT  134.448 23.701 134.472 23.893 ;
     RECT  139.632 23.365 139.656 23.893 ;
     RECT  0.912 23.411 15.912 23.939 ;
     RECT  95.664 23.893 96.936 23.941 ;
     RECT  98.544 23.893 100.2 23.941 ;
     RECT  117.36 23.893 124.776 23.941 ;
     RECT  125.808 23.893 131.496 23.941 ;
     RECT  1.104 23.939 15.912 24.469 ;
     RECT  32.976 23.893 33 24.469 ;
     RECT  53.52 23.893 53.544 24.469 ;
     RECT  66.576 23.459 68.232 24.469 ;
     RECT  69.84 23.459 69.864 24.469 ;
     RECT  71.952 23.893 76.872 24.469 ;
     RECT  78 23.893 83.304 24.469 ;
     RECT  84.624 23.893 86.664 24.469 ;
     RECT  89.904 23.769 91.56 24.469 ;
     RECT  92.784 23.459 94.512 24.469 ;
     RECT  95.664 23.941 100.2 24.469 ;
     RECT  101.424 23.893 107.112 24.469 ;
     RECT  108.72 23.893 116.232 24.469 ;
     RECT  117.36 23.941 131.496 24.469 ;
     RECT  17.52 23.893 19.56 24.517 ;
     RECT  20.688 23.893 21.576 24.517 ;
     RECT  84.624 24.469 87.048 24.517 ;
     RECT  88.272 23.893 88.68 24.517 ;
     RECT  89.904 24.469 107.112 24.517 ;
     RECT  108.336 24.469 131.496 24.517 ;
     RECT  138.192 23.893 140.424 24.517 ;
     RECT  45.264 23.893 46.152 25.045 ;
     RECT  47.76 23.893 47.784 25.045 ;
     RECT  60.048 23.893 64.968 25.045 ;
     RECT  66.192 24.469 68.232 25.045 ;
     RECT  69.456 24.469 83.304 25.045 ;
     RECT  84.624 24.517 88.68 25.045 ;
     RECT  89.904 24.517 131.496 25.045 ;
     RECT  17.52 24.517 21.576 25.093 ;
     RECT  45.264 25.045 48.552 25.093 ;
     RECT  50.256 24.469 50.28 25.093 ;
     RECT  133.008 23.893 134.472 25.093 ;
     RECT  135.984 23.893 136.68 25.093 ;
     RECT  1.104 24.469 16.296 25.765 ;
     RECT  17.52 25.093 22.44 25.765 ;
     RECT  27.312 23.893 28.968 25.765 ;
     RECT  30.576 24.469 30.6 25.765 ;
     RECT  32.208 24.469 33 25.765 ;
     RECT  34.608 23.893 36.36 25.765 ;
     RECT  37.968 23.893 40.392 25.765 ;
     RECT  42 23.893 42.024 25.765 ;
     RECT  43.632 23.893 43.656 25.765 ;
     RECT  45.264 25.093 51.048 25.765 ;
     RECT  53.52 24.469 54.312 25.765 ;
     RECT  56.784 23.893 58.44 25.765 ;
     RECT  60.048 25.045 131.496 25.765 ;
     RECT  133.008 25.093 136.68 25.765 ;
     RECT  138.192 24.517 142.728 25.765 ;
     RECT  1.104 25.765 142.728 25.836 ;
     RECT  1.128 25.836 1.296 25.872 ;
     RECT  1.32 25.836 1.488 25.872 ;
     RECT  1.512 25.836 1.68 25.872 ;
     RECT  1.704 25.836 1.872 25.872 ;
     RECT  1.896 25.836 2.064 25.872 ;
     RECT  2.088 25.836 2.352 25.872 ;
     RECT  2.376 25.836 2.544 25.872 ;
     RECT  2.568 25.836 2.736 25.872 ;
     RECT  2.76 25.836 2.928 25.872 ;
     RECT  2.952 25.836 3.12 25.872 ;
     RECT  3.144 25.836 3.312 25.872 ;
     RECT  3.336 25.836 3.504 25.872 ;
     RECT  3.528 25.836 3.792 25.872 ;
     RECT  3.816 25.836 3.984 25.872 ;
     RECT  4.008 25.836 4.176 25.872 ;
     RECT  4.2 25.836 4.368 25.872 ;
     RECT  4.392 25.836 4.56 25.872 ;
     RECT  4.584 25.836 4.752 25.872 ;
     RECT  4.776 25.836 4.944 25.872 ;
     RECT  4.968 25.836 5.136 25.872 ;
     RECT  5.16 25.836 5.424 25.872 ;
     RECT  5.448 25.836 5.616 25.872 ;
     RECT  5.64 25.836 5.808 25.872 ;
     RECT  5.832 25.836 6 25.872 ;
     RECT  6.024 25.836 6.192 25.872 ;
     RECT  6.216 25.836 6.384 25.872 ;
     RECT  6.408 25.836 6.576 25.872 ;
     RECT  6.6 25.836 6.864 25.872 ;
     RECT  6.888 25.836 7.056 25.872 ;
     RECT  7.08 25.836 7.248 25.872 ;
     RECT  7.272 25.836 7.44 25.872 ;
     RECT  7.464 25.836 7.632 25.872 ;
     RECT  7.656 25.836 7.824 25.872 ;
     RECT  7.848 25.836 8.016 25.872 ;
     RECT  8.04 25.836 8.208 25.872 ;
     RECT  8.232 25.836 8.496 25.872 ;
     RECT  8.52 25.836 8.688 25.872 ;
     RECT  8.712 25.836 8.88 25.872 ;
     RECT  8.904 25.836 9.072 25.872 ;
     RECT  9.096 25.836 9.264 25.872 ;
     RECT  9.288 25.836 9.456 25.872 ;
     RECT  9.48 25.836 9.648 25.872 ;
     RECT  9.672 25.836 9.936 25.872 ;
     RECT  9.96 25.836 10.128 25.872 ;
     RECT  10.152 25.836 10.32 25.872 ;
     RECT  10.344 25.836 10.512 25.872 ;
     RECT  10.536 25.836 10.704 25.872 ;
     RECT  10.728 25.836 10.896 25.872 ;
     RECT  10.92 25.836 11.088 25.872 ;
     RECT  11.112 25.836 11.28 25.872 ;
     RECT  11.304 25.836 11.568 25.872 ;
     RECT  11.592 25.836 11.76 25.872 ;
     RECT  11.784 25.836 11.952 25.872 ;
     RECT  11.976 25.836 12.144 25.872 ;
     RECT  12.168 25.836 12.336 25.872 ;
     RECT  12.36 25.836 12.528 25.872 ;
     RECT  12.552 25.836 12.72 25.872 ;
     RECT  12.744 25.836 13.008 25.872 ;
     RECT  13.032 25.836 13.392 25.872 ;
     RECT  13.416 25.836 13.872 25.872 ;
     RECT  13.896 25.836 14.256 25.872 ;
     RECT  14.28 25.836 14.64 25.872 ;
     RECT  14.664 25.836 15.024 25.872 ;
     RECT  15.048 25.836 15.504 25.872 ;
     RECT  15.528 25.836 15.888 25.872 ;
     RECT  15.912 25.836 16.272 25.872 ;
     RECT  16.296 25.836 16.656 25.872 ;
     RECT  16.68 25.836 17.136 25.872 ;
     RECT  17.16 25.836 17.52 25.872 ;
     RECT  17.544 25.836 17.904 25.872 ;
     RECT  17.928 25.836 18.384 25.872 ;
     RECT  18.408 25.836 18.768 25.872 ;
     RECT  18.792 25.836 19.152 25.872 ;
     RECT  19.176 25.836 19.536 25.872 ;
     RECT  19.56 25.836 20.016 25.872 ;
     RECT  20.04 25.836 20.688 25.872 ;
     RECT  20.712 25.836 21.552 25.872 ;
     RECT  21.576 25.836 22.416 25.872 ;
     RECT  22.44 25.836 23.184 25.872 ;
     RECT  23.208 25.836 24.048 25.872 ;
     RECT  24.072 25.836 24.816 25.872 ;
     RECT  24.84 25.836 25.68 25.872 ;
     RECT  25.704 25.836 26.448 25.872 ;
     RECT  26.472 25.836 27.312 25.872 ;
     RECT  27.336 25.836 28.08 25.872 ;
     RECT  28.104 25.836 28.944 25.872 ;
     RECT  28.968 25.836 29.712 25.872 ;
     RECT  29.736 25.836 30.576 25.872 ;
     RECT  30.6 25.836 31.344 25.872 ;
     RECT  31.368 25.836 32.208 25.872 ;
     RECT  32.232 25.836 32.976 25.872 ;
     RECT  33 25.836 33.84 25.872 ;
     RECT  33.864 25.836 34.608 25.872 ;
     RECT  34.632 25.836 35.472 25.872 ;
     RECT  35.496 25.836 36.336 25.872 ;
     RECT  36.36 25.836 37.104 25.872 ;
     RECT  37.128 25.836 37.968 25.872 ;
     RECT  37.992 25.836 38.736 25.872 ;
     RECT  38.76 25.836 39.6 25.872 ;
     RECT  39.624 25.836 40.368 25.872 ;
     RECT  40.392 25.836 41.232 25.872 ;
     RECT  41.256 25.836 42 25.872 ;
     RECT  42.024 25.836 42.864 25.872 ;
     RECT  42.888 25.836 43.632 25.872 ;
     RECT  43.656 25.836 44.496 25.872 ;
     RECT  44.52 25.836 45.264 25.872 ;
     RECT  45.288 25.836 46.128 25.872 ;
     RECT  46.152 25.836 46.896 25.872 ;
     RECT  46.92 25.836 47.76 25.872 ;
     RECT  47.784 25.836 48.528 25.872 ;
     RECT  48.552 25.836 49.392 25.872 ;
     RECT  49.416 25.836 50.256 25.872 ;
     RECT  50.28 25.836 51.024 25.872 ;
     RECT  51.048 25.836 51.888 25.872 ;
     RECT  51.912 25.836 52.656 25.872 ;
     RECT  52.68 25.836 53.52 25.872 ;
     RECT  53.544 25.836 54.288 25.872 ;
     RECT  54.312 25.836 55.152 25.872 ;
     RECT  55.176 25.836 55.92 25.872 ;
     RECT  55.944 25.836 56.784 25.872 ;
     RECT  56.808 25.836 57.552 25.872 ;
     RECT  57.576 25.836 58.416 25.872 ;
     RECT  58.44 25.836 59.184 25.872 ;
     RECT  59.208 25.836 60.048 25.872 ;
     RECT  60.072 25.836 60.432 25.872 ;
     RECT  60.456 25.836 60.816 25.872 ;
     RECT  60.84 25.836 61.296 25.872 ;
     RECT  61.32 25.836 61.68 25.872 ;
     RECT  61.704 25.836 62.064 25.872 ;
     RECT  62.088 25.836 62.448 25.872 ;
     RECT  62.472 25.836 62.928 25.872 ;
     RECT  62.952 25.836 63.312 25.872 ;
     RECT  63.336 25.836 63.696 25.872 ;
     RECT  63.72 25.836 64.176 25.872 ;
     RECT  64.2 25.836 64.56 25.872 ;
     RECT  64.584 25.836 64.944 25.872 ;
     RECT  64.968 25.836 65.328 25.872 ;
     RECT  65.352 25.836 65.808 25.872 ;
     RECT  65.832 25.836 66.192 25.872 ;
     RECT  66.216 25.836 66.576 25.872 ;
     RECT  66.6 25.836 66.96 25.872 ;
     RECT  66.984 25.836 67.44 25.872 ;
     RECT  67.464 25.836 67.824 25.872 ;
     RECT  67.848 25.836 68.208 25.872 ;
     RECT  68.232 25.836 68.592 25.872 ;
     RECT  68.616 25.836 69.072 25.872 ;
     RECT  69.096 25.836 69.456 25.872 ;
     RECT  69.48 25.836 69.84 25.872 ;
     RECT  69.864 25.836 70.32 25.872 ;
     RECT  70.344 25.836 70.704 25.872 ;
     RECT  70.728 25.836 71.088 25.872 ;
     RECT  71.112 25.836 71.472 25.872 ;
     RECT  71.496 25.836 71.952 25.872 ;
     RECT  71.976 25.836 72.336 25.872 ;
     RECT  72.36 25.836 72.72 25.872 ;
     RECT  72.744 25.836 73.104 25.872 ;
     RECT  73.128 25.836 73.584 25.872 ;
     RECT  73.608 25.836 73.968 25.872 ;
     RECT  73.992 25.836 74.352 25.872 ;
     RECT  74.376 25.836 74.736 25.872 ;
     RECT  74.76 25.836 75.216 25.872 ;
     RECT  75.24 25.836 75.6 25.872 ;
     RECT  75.624 25.836 75.984 25.872 ;
     RECT  76.008 25.836 76.464 25.872 ;
     RECT  76.488 25.836 76.848 25.872 ;
     RECT  76.872 25.836 77.232 25.872 ;
     RECT  77.256 25.836 77.616 25.872 ;
     RECT  77.64 25.836 78.096 25.872 ;
     RECT  78.12 25.836 78.48 25.872 ;
     RECT  78.504 25.836 78.864 25.872 ;
     RECT  78.888 25.836 79.248 25.872 ;
     RECT  79.272 25.836 79.728 25.872 ;
     RECT  79.752 25.836 80.112 25.872 ;
     RECT  80.136 25.836 80.496 25.872 ;
     RECT  80.52 25.836 80.88 25.872 ;
     RECT  80.904 25.836 81.36 25.872 ;
     RECT  81.384 25.836 81.744 25.872 ;
     RECT  81.768 25.836 82.128 25.872 ;
     RECT  82.152 25.836 82.512 25.872 ;
     RECT  82.536 25.836 82.992 25.872 ;
     RECT  83.016 25.836 83.376 25.872 ;
     RECT  83.4 25.836 83.76 25.872 ;
     RECT  83.784 25.836 84.24 25.872 ;
     RECT  84.264 25.836 84.624 25.872 ;
     RECT  84.648 25.836 85.008 25.872 ;
     RECT  85.032 25.836 85.392 25.872 ;
     RECT  85.416 25.836 85.872 25.872 ;
     RECT  85.896 25.836 86.256 25.872 ;
     RECT  86.28 25.836 86.64 25.872 ;
     RECT  86.664 25.836 87.024 25.872 ;
     RECT  87.048 25.836 87.504 25.872 ;
     RECT  87.528 25.836 87.888 25.872 ;
     RECT  87.912 25.836 88.272 25.872 ;
     RECT  88.296 25.836 88.656 25.872 ;
     RECT  88.68 25.836 89.136 25.872 ;
     RECT  89.16 25.836 89.52 25.872 ;
     RECT  89.544 25.836 89.904 25.872 ;
     RECT  89.928 25.836 90.384 25.872 ;
     RECT  90.408 25.836 90.768 25.872 ;
     RECT  90.792 25.836 91.152 25.872 ;
     RECT  91.176 25.836 91.536 25.872 ;
     RECT  91.56 25.836 92.016 25.872 ;
     RECT  92.04 25.836 92.4 25.872 ;
     RECT  92.424 25.836 92.784 25.872 ;
     RECT  92.808 25.836 93.168 25.872 ;
     RECT  93.192 25.836 93.648 25.872 ;
     RECT  93.672 25.836 94.032 25.872 ;
     RECT  94.056 25.836 94.416 25.872 ;
     RECT  94.44 25.836 94.8 25.872 ;
     RECT  94.824 25.836 95.28 25.872 ;
     RECT  95.304 25.836 95.664 25.872 ;
     RECT  95.688 25.836 96.048 25.872 ;
     RECT  96.072 25.836 96.528 25.872 ;
     RECT  96.552 25.836 96.912 25.872 ;
     RECT  96.936 25.836 97.296 25.872 ;
     RECT  97.32 25.836 97.68 25.872 ;
     RECT  97.704 25.836 98.16 25.872 ;
     RECT  98.184 25.836 98.544 25.872 ;
     RECT  98.568 25.836 98.928 25.872 ;
     RECT  98.952 25.836 99.312 25.872 ;
     RECT  99.336 25.836 99.792 25.872 ;
     RECT  99.816 25.836 100.176 25.872 ;
     RECT  100.2 25.836 100.56 25.872 ;
     RECT  100.584 25.836 100.944 25.872 ;
     RECT  100.968 25.836 101.424 25.872 ;
     RECT  101.448 25.836 101.808 25.872 ;
     RECT  101.832 25.836 102.192 25.872 ;
     RECT  102.216 25.836 102.576 25.872 ;
     RECT  102.6 25.836 103.056 25.872 ;
     RECT  103.08 25.836 103.44 25.872 ;
     RECT  103.464 25.836 103.824 25.872 ;
     RECT  103.848 25.836 104.304 25.872 ;
     RECT  104.328 25.836 104.688 25.872 ;
     RECT  104.712 25.836 105.072 25.872 ;
     RECT  105.096 25.836 105.456 25.872 ;
     RECT  105.48 25.836 105.936 25.872 ;
     RECT  105.96 25.836 106.32 25.872 ;
     RECT  106.344 25.836 106.704 25.872 ;
     RECT  106.728 25.836 107.088 25.872 ;
     RECT  107.112 25.836 107.568 25.872 ;
     RECT  107.592 25.836 107.952 25.872 ;
     RECT  107.976 25.836 108.336 25.872 ;
     RECT  108.36 25.836 108.72 25.872 ;
     RECT  108.744 25.836 109.2 25.872 ;
     RECT  109.224 25.836 109.584 25.872 ;
     RECT  109.608 25.836 109.968 25.872 ;
     RECT  109.992 25.836 110.448 25.872 ;
     RECT  110.472 25.836 110.832 25.872 ;
     RECT  110.856 25.836 111.216 25.872 ;
     RECT  111.24 25.836 111.6 25.872 ;
     RECT  111.624 25.836 112.08 25.872 ;
     RECT  112.104 25.836 112.464 25.872 ;
     RECT  112.488 25.836 112.848 25.872 ;
     RECT  112.872 25.836 113.232 25.872 ;
     RECT  113.256 25.836 113.712 25.872 ;
     RECT  113.736 25.836 114.096 25.872 ;
     RECT  114.12 25.836 114.48 25.872 ;
     RECT  114.504 25.836 114.864 25.872 ;
     RECT  114.888 25.836 115.344 25.872 ;
     RECT  115.368 25.836 115.728 25.872 ;
     RECT  115.752 25.836 116.112 25.872 ;
     RECT  116.136 25.836 116.592 25.872 ;
     RECT  116.616 25.836 116.976 25.872 ;
     RECT  117 25.836 117.36 25.872 ;
     RECT  117.384 25.836 117.744 25.872 ;
     RECT  117.768 25.836 118.224 25.872 ;
     RECT  118.248 25.836 118.608 25.872 ;
     RECT  118.632 25.836 118.992 25.872 ;
     RECT  119.016 25.836 119.376 25.872 ;
     RECT  119.4 25.836 119.856 25.872 ;
     RECT  119.88 25.836 120.24 25.872 ;
     RECT  120.264 25.836 120.624 25.872 ;
     RECT  120.648 25.836 121.008 25.872 ;
     RECT  121.032 25.836 121.488 25.872 ;
     RECT  121.512 25.836 121.872 25.872 ;
     RECT  121.896 25.836 122.256 25.872 ;
     RECT  122.28 25.836 122.64 25.872 ;
     RECT  122.664 25.836 123.12 25.872 ;
     RECT  123.144 25.836 123.504 25.872 ;
     RECT  123.528 25.836 123.888 25.872 ;
     RECT  123.912 25.836 124.368 25.872 ;
     RECT  124.392 25.836 124.752 25.872 ;
     RECT  124.776 25.836 125.136 25.872 ;
     RECT  125.16 25.836 125.52 25.872 ;
     RECT  125.544 25.836 126 25.872 ;
     RECT  126.024 25.836 126.384 25.872 ;
     RECT  126.408 25.836 126.768 25.872 ;
     RECT  126.792 25.836 127.152 25.872 ;
     RECT  127.176 25.836 127.632 25.872 ;
     RECT  127.656 25.836 128.016 25.872 ;
     RECT  128.04 25.836 128.4 25.872 ;
     RECT  128.424 25.836 128.784 25.872 ;
     RECT  128.808 25.836 129.264 25.872 ;
     RECT  129.288 25.836 129.648 25.872 ;
     RECT  129.672 25.836 130.032 25.872 ;
     RECT  130.056 25.836 130.512 25.872 ;
     RECT  130.536 25.836 130.896 25.872 ;
     RECT  130.92 25.836 131.472 25.872 ;
     RECT  131.496 25.836 132.24 25.872 ;
     RECT  132.264 25.836 133.008 25.872 ;
     RECT  133.032 25.836 133.68 25.872 ;
     RECT  133.704 25.836 134.448 25.872 ;
     RECT  134.472 25.836 135.216 25.872 ;
     RECT  135.24 25.836 135.984 25.872 ;
     RECT  136.008 25.836 136.656 25.872 ;
     RECT  136.68 25.836 137.424 25.872 ;
     RECT  137.448 25.836 138.192 25.872 ;
     RECT  138.216 25.836 138.96 25.872 ;
     RECT  138.984 25.836 139.632 25.872 ;
     RECT  139.656 25.836 140.4 25.872 ;
     RECT  140.424 25.836 141.168 25.872 ;
     RECT  141.192 25.836 141.936 25.872 ;
     RECT  141.96 25.836 142.704 25.872 ;
     RECT  131.544 0.131 132.192 0.132 ;
     RECT  132.312 0.131 132.96 0.132 ;
     RECT  131.496 0.132 133.008 1.763 ;
     RECT  14.664 1.187 15.888 1.763 ;
     RECT  141.192 1.187 142.704 2.291 ;
     RECT  15.84 1.763 15.888 2.917 ;
     RECT  15.912 1.763 16.896 2.339 ;
     RECT  16.92 1.763 18.6 2.339 ;
     RECT  39.744 1.763 40.2 2.821 ;
     RECT  45.264 1.763 45.6 2.773 ;
     RECT  63.72 1.763 65.016 2.291 ;
     RECT  72.912 1.763 74.352 2.821 ;
     RECT  74.376 1.763 75.792 3.397 ;
     RECT  75.816 1.763 77.136 4.019 ;
     RECT  79.752 1.763 80.88 1.811 ;
     RECT  81.384 1.763 82.512 1.811 ;
     RECT  85.416 1.763 86.376 1.859 ;
     RECT  88.416 1.763 88.8 2.821 ;
     RECT  89.928 1.763 91.152 3.397 ;
     RECT  94.512 1.763 95.736 2.821 ;
     RECT  98.568 1.763 99.6 1.859 ;
     RECT  99.912 1.763 101.424 1.811 ;
     RECT  111.624 1.763 112.848 1.811 ;
     RECT  114.504 1.763 115.8 3.443 ;
     RECT  118.848 1.763 118.944 3.253 ;
     RECT  120.816 1.763 121.2 2.821 ;
     RECT  121.896 1.763 122.28 2.821 ;
     RECT  130.536 1.763 132.312 1.811 ;
     RECT  135.264 1.763 135.288 2.821 ;
     RECT  78.696 1.811 79.728 1.907 ;
     RECT  79.752 1.811 80.928 1.907 ;
     RECT  81.384 1.811 81.48 2.821 ;
     RECT  99.912 1.811 100.152 3.301 ;
     RECT  111.624 1.811 113.28 2.821 ;
     RECT  131.328 1.811 132.312 2.137 ;
     RECT  71.088 1.859 71.712 3.301 ;
     RECT  85.392 1.859 86.376 2.821 ;
     RECT  78.696 1.907 80.928 2.821 ;
     RECT  131.328 2.137 132 3.301 ;
     RECT  64.992 2.291 65.016 3.205 ;
     RECT  126.912 2.291 127.656 3.301 ;
     RECT  15.912 2.339 18.6 2.821 ;
     RECT  15.96 2.821 18.144 3.205 ;
     RECT  78.744 2.821 80.928 3.205 ;
     RECT  85.392 2.821 86.352 3.205 ;
     RECT  111.624 2.821 112.752 2.915 ;
     RECT  13.512 2.867 14.28 3.733 ;
     RECT  104.688 2.915 105 3.301 ;
     RECT  112.32 2.915 112.752 3.733 ;
     RECT  15.96 3.205 17.088 3.829 ;
     RECT  17.112 3.205 18.144 3.301 ;
     RECT  78.744 3.205 80.688 3.301 ;
     RECT  85.392 3.205 86.016 3.301 ;
     RECT  19.56 3.301 20.544 3.443 ;
     RECT  84.696 3.301 86.016 5.029 ;
     RECT  95.736 3.301 96.912 3.877 ;
     RECT  103.992 3.301 105 3.973 ;
     RECT  117.672 3.301 118.848 4.691 ;
     RECT  126.912 3.301 128.064 21.061 ;
     RECT  74.664 3.397 75.792 4.019 ;
     RECT  2.952 3.443 4.368 3.491 ;
     RECT  11.784 3.443 13.2 4.067 ;
     RECT  19.224 3.443 20.544 4.595 ;
     RECT  113.976 3.443 115.8 3.733 ;
     RECT  9.624 3.539 10.656 4.067 ;
     RECT  13.512 3.733 14.688 3.829 ;
     RECT  14.712 3.733 15.744 4.501 ;
     RECT  98.52 3.733 99.6 4.501 ;
     RECT  105.312 3.733 106.608 4.595 ;
     RECT  113.976 3.733 115.104 4.501 ;
     RECT  15.96 3.829 17.04 3.877 ;
     RECT  118.968 3.829 120.144 5.125 ;
     RECT  67.8 3.925 68.976 4.501 ;
     RECT  69 3.925 70.416 4.501 ;
     RECT  76.8 4.019 77.136 4.643 ;
     RECT  83.136 4.019 83.4 4.261 ;
     RECT  120.168 4.019 121.2 5.749 ;
     RECT  40.512 4.117 41.76 10.019 ;
     RECT  128.088 4.117 129.36 4.931 ;
     RECT  82.056 4.261 83.4 5.077 ;
     RECT  100.152 4.261 101.616 21.541 ;
     RECT  101.64 4.261 103.104 21.637 ;
     RECT  69 4.501 70.032 4.837 ;
     RECT  96.936 4.501 97.968 22.835 ;
     RECT  67.512 4.547 68.544 22.165 ;
     RECT  19.224 4.595 19.32 4.837 ;
     RECT  76.8 4.643 78 4.645 ;
     RECT  113.352 4.643 114.816 5.605 ;
     RECT  76.824 4.645 78 5.171 ;
     RECT  117.672 4.691 118.896 21.637 ;
     RECT  116.112 4.739 117.216 21.637 ;
     RECT  84.984 5.029 86.016 5.077 ;
     RECT  87.48 5.171 88.8 23.411 ;
     RECT  16.776 5.315 17.808 21.155 ;
     RECT  113.4 5.605 114.816 23.893 ;
     RECT  0.552 11.221 1.632 11.904 ;
     RECT  0.565 11.904 1.632 12.024 ;
     RECT  0.552 12.024 1.632 12.96 ;
     RECT  0.565 12.96 1.632 13.08 ;
     RECT  0.552 13.08 1.632 14.149 ;
     RECT  3.864 14.005 4.896 18.181 ;
     RECT  4.92 14.197 6.336 14.723 ;
     RECT  11.256 15.349 12.336 15.925 ;
     RECT  11.256 15.925 12.288 16.165 ;
     RECT  6.696 17.075 7.68 18.037 ;
     RECT  4.92 17.077 5.952 18.181 ;
     RECT  16.584 21.155 17.808 22.165 ;
     RECT  94.512 21.155 95.616 22.835 ;
     RECT  113.232 21.155 113.376 22.213 ;
     RECT  100.152 21.541 101.424 22.741 ;
     RECT  116.232 21.637 117.216 23.411 ;
     RECT  62.952 22.117 64.08 23.845 ;
     RECT  124.776 22.117 125.808 23.941 ;
     RECT  19.272 22.741 20.688 22.835 ;
     RECT  100.2 22.741 101.424 24.469 ;
     RECT  111.624 22.741 112.848 23.893 ;
     RECT  19.224 22.835 20.688 23.893 ;
     RECT  70.056 22.835 71.232 23.411 ;
     RECT  73.128 22.835 74.304 23.893 ;
     RECT  78.504 22.835 79.536 23.893 ;
     RECT  94.512 22.835 95.664 24.469 ;
     RECT  96.504 22.835 97.968 22.883 ;
     RECT  96.504 22.883 98.928 23.893 ;
     RECT  38.76 23.365 39.744 23.893 ;
     RECT  15.912 23.411 17.52 24.469 ;
     RECT  68.568 23.411 69.84 23.459 ;
     RECT  70.056 23.411 71.952 23.459 ;
     RECT  87.456 23.411 88.8 23.783 ;
     RECT  116.232 23.411 117.36 24.469 ;
     RECT  129.288 23.413 130.512 23.893 ;
     RECT  68.232 23.459 69.84 24.469 ;
     RECT  69.864 23.459 71.952 24.469 ;
     RECT  91.56 23.459 92.784 24.469 ;
     RECT  83.52 23.769 84.624 23.783 ;
     RECT  88.92 23.769 89.904 23.783 ;
     RECT  51 23.783 51.048 24.469 ;
     RECT  83.304 23.783 84.624 25.045 ;
     RECT  87.456 23.783 89.904 23.893 ;
     RECT  131.496 23.783 132.312 23.893 ;
     RECT  137.4 23.783 137.712 23.893 ;
     RECT  19.56 23.893 20.688 24.517 ;
     RECT  76.872 23.893 78 24.469 ;
     RECT  86.664 23.893 88.272 24.469 ;
     RECT  88.68 23.893 89.904 25.045 ;
     RECT  96.936 23.893 98.544 23.941 ;
     RECT  131.496 23.893 133.008 25.765 ;
     RECT  134.472 23.893 135.984 25.093 ;
     RECT  136.68 23.893 138.192 25.765 ;
     RECT  16.296 24.469 17.52 25.765 ;
     RECT  50.28 24.469 51.048 25.093 ;
     RECT  64.968 24.469 66.192 25.045 ;
     RECT  68.232 24.469 69.456 25.045 ;
     RECT  87.048 24.469 88.272 24.517 ;
     RECT  107.112 24.469 108.336 24.517 ;
  END
END ot_s81_hc_ctrn_own_e
END LIBRARY
